VERSION 5.8 ;
BUSBITCHARS "[]" ;
DIVIDERCHAR "/" ;
UNITS
    DATABASE MICRONS 1000 ;
END UNITS

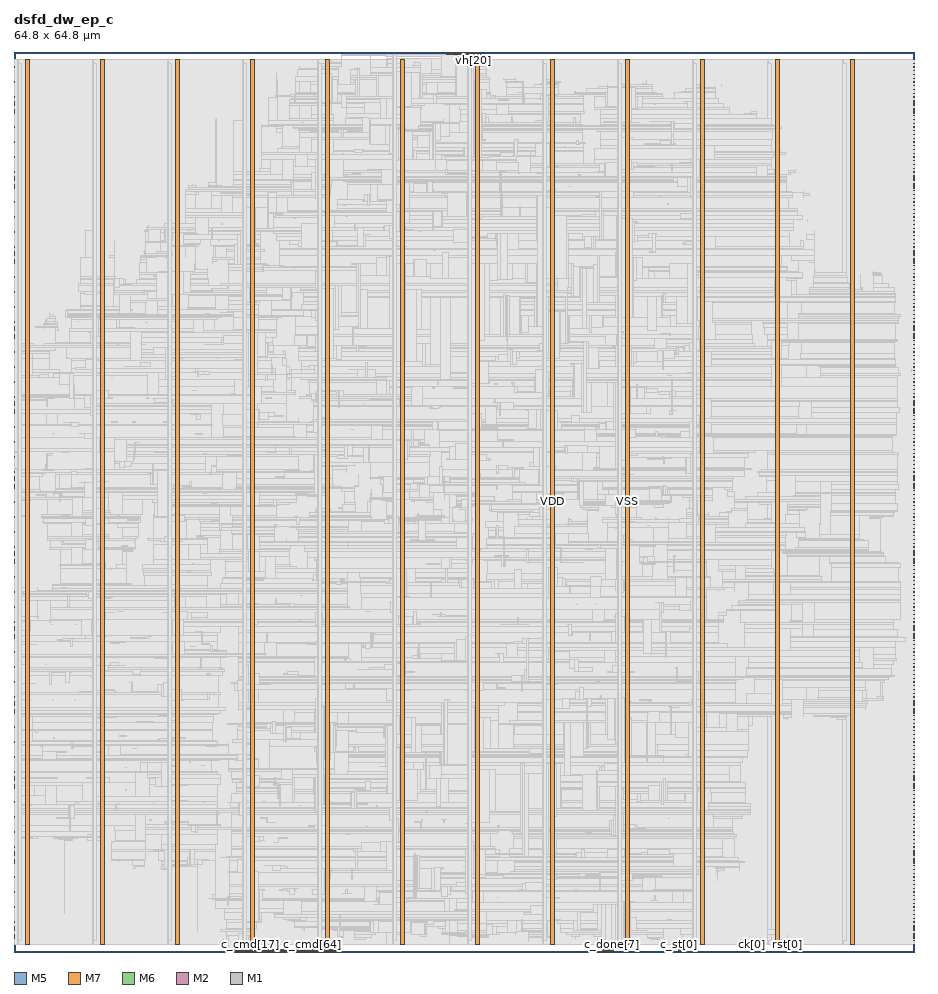
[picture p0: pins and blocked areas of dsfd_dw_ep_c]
MACRO dsfd_dw_ep_c
  FOREIGN dsfd_dw_ep_c 0 0 ;
  CLASS BLOCK ;
  SIZE 64.8 BY 64.8 ;
  PIN c_cmd[0]
    DIRECTION INPUT ;
    USE SIGNAL ;
    PORT
      LAYER M5 ;
        RECT  15.36 0 15.384 0.192 ;
    END
  END c_cmd[0]
  PIN c_cmd[10]
    DIRECTION INPUT ;
    USE SIGNAL ;
    PORT
      LAYER M5 ;
        RECT  16.32 0 16.344 0.192 ;
    END
  END c_cmd[10]
  PIN c_cmd[11]
    DIRECTION INPUT ;
    USE SIGNAL ;
    PORT
      LAYER M5 ;
        RECT  16.416 0 16.44 0.192 ;
    END
  END c_cmd[11]
  PIN c_cmd[12]
    DIRECTION INPUT ;
    USE SIGNAL ;
    PORT
      LAYER M5 ;
        RECT  16.512 0 16.536 0.192 ;
    END
  END c_cmd[12]
  PIN c_cmd[13]
    DIRECTION INPUT ;
    USE SIGNAL ;
    PORT
      LAYER M5 ;
        RECT  16.608 0 16.632 0.192 ;
    END
  END c_cmd[13]
  PIN c_cmd[14]
    DIRECTION INPUT ;
    USE SIGNAL ;
    PORT
      LAYER M5 ;
        RECT  16.704 0 16.728 0.192 ;
    END
  END c_cmd[14]
  PIN c_cmd[15]
    DIRECTION INPUT ;
    USE SIGNAL ;
    PORT
      LAYER M5 ;
        RECT  16.8 0 16.824 0.192 ;
    END
  END c_cmd[15]
  PIN c_cmd[16]
    DIRECTION INPUT ;
    USE SIGNAL ;
    PORT
      LAYER M5 ;
        RECT  16.896 0 16.92 0.192 ;
    END
  END c_cmd[16]
  PIN c_cmd[17]
    DIRECTION INPUT ;
    USE SIGNAL ;
    PORT
      LAYER M5 ;
        RECT  16.992 0 17.016 0.192 ;
    END
  END c_cmd[17]
  PIN c_cmd[18]
    DIRECTION INPUT ;
    USE SIGNAL ;
    PORT
      LAYER M5 ;
        RECT  17.088 0 17.112 0.192 ;
    END
  END c_cmd[18]
  PIN c_cmd[19]
    DIRECTION INPUT ;
    USE SIGNAL ;
    PORT
      LAYER M5 ;
        RECT  17.184 0 17.208 0.192 ;
    END
  END c_cmd[19]
  PIN c_cmd[1]
    DIRECTION INPUT ;
    USE SIGNAL ;
    PORT
      LAYER M5 ;
        RECT  15.456 0 15.48 0.192 ;
    END
  END c_cmd[1]
  PIN c_cmd[20]
    DIRECTION INPUT ;
    USE SIGNAL ;
    PORT
      LAYER M5 ;
        RECT  17.28 0 17.304 0.192 ;
    END
  END c_cmd[20]
  PIN c_cmd[21]
    DIRECTION INPUT ;
    USE SIGNAL ;
    PORT
      LAYER M5 ;
        RECT  17.376 0 17.4 0.192 ;
    END
  END c_cmd[21]
  PIN c_cmd[22]
    DIRECTION INPUT ;
    USE SIGNAL ;
    PORT
      LAYER M5 ;
        RECT  17.472 0 17.496 0.192 ;
    END
  END c_cmd[22]
  PIN c_cmd[23]
    DIRECTION INPUT ;
    USE SIGNAL ;
    PORT
      LAYER M5 ;
        RECT  17.568 0 17.592 0.192 ;
    END
  END c_cmd[23]
  PIN c_cmd[24]
    DIRECTION INPUT ;
    USE SIGNAL ;
    PORT
      LAYER M5 ;
        RECT  17.664 0 17.688 0.192 ;
    END
  END c_cmd[24]
  PIN c_cmd[25]
    DIRECTION INPUT ;
    USE SIGNAL ;
    PORT
      LAYER M5 ;
        RECT  17.76 0 17.784 0.192 ;
    END
  END c_cmd[25]
  PIN c_cmd[26]
    DIRECTION INPUT ;
    USE SIGNAL ;
    PORT
      LAYER M5 ;
        RECT  17.856 0 17.88 0.192 ;
    END
  END c_cmd[26]
  PIN c_cmd[27]
    DIRECTION INPUT ;
    USE SIGNAL ;
    PORT
      LAYER M5 ;
        RECT  17.952 0 17.976 0.192 ;
    END
  END c_cmd[27]
  PIN c_cmd[28]
    DIRECTION INPUT ;
    USE SIGNAL ;
    PORT
      LAYER M5 ;
        RECT  18.048 0 18.072 0.192 ;
    END
  END c_cmd[28]
  PIN c_cmd[29]
    DIRECTION INPUT ;
    USE SIGNAL ;
    PORT
      LAYER M5 ;
        RECT  18.144 0 18.168 0.192 ;
    END
  END c_cmd[29]
  PIN c_cmd[2]
    DIRECTION INPUT ;
    USE SIGNAL ;
    PORT
      LAYER M5 ;
        RECT  15.552 0 15.576 0.192 ;
    END
  END c_cmd[2]
  PIN c_cmd[30]
    DIRECTION INPUT ;
    USE SIGNAL ;
    PORT
      LAYER M5 ;
        RECT  18.24 0 18.264 0.192 ;
    END
  END c_cmd[30]
  PIN c_cmd[31]
    DIRECTION INPUT ;
    USE SIGNAL ;
    PORT
      LAYER M5 ;
        RECT  18.336 0 18.36 0.192 ;
    END
  END c_cmd[31]
  PIN c_cmd[32]
    DIRECTION INPUT ;
    USE SIGNAL ;
    PORT
      LAYER M5 ;
        RECT  18.432 0 18.456 0.192 ;
    END
  END c_cmd[32]
  PIN c_cmd[33]
    DIRECTION INPUT ;
    USE SIGNAL ;
    PORT
      LAYER M5 ;
        RECT  18.528 0 18.552 0.192 ;
    END
  END c_cmd[33]
  PIN c_cmd[34]
    DIRECTION INPUT ;
    USE SIGNAL ;
    PORT
      LAYER M5 ;
        RECT  18.624 0 18.648 0.192 ;
    END
  END c_cmd[34]
  PIN c_cmd[35]
    DIRECTION INPUT ;
    USE SIGNAL ;
    PORT
      LAYER M5 ;
        RECT  18.72 0 18.744 0.192 ;
    END
  END c_cmd[35]
  PIN c_cmd[36]
    DIRECTION INPUT ;
    USE SIGNAL ;
    PORT
      LAYER M5 ;
        RECT  18.816 0 18.84 0.192 ;
    END
  END c_cmd[36]
  PIN c_cmd[37]
    DIRECTION INPUT ;
    USE SIGNAL ;
    PORT
      LAYER M5 ;
        RECT  18.912 0 18.936 0.192 ;
    END
  END c_cmd[37]
  PIN c_cmd[38]
    DIRECTION INPUT ;
    USE SIGNAL ;
    PORT
      LAYER M5 ;
        RECT  19.008 0 19.032 0.192 ;
    END
  END c_cmd[38]
  PIN c_cmd[39]
    DIRECTION INPUT ;
    USE SIGNAL ;
    PORT
      LAYER M5 ;
        RECT  19.104 0 19.128 0.192 ;
    END
  END c_cmd[39]
  PIN c_cmd[3]
    DIRECTION INPUT ;
    USE SIGNAL ;
    PORT
      LAYER M5 ;
        RECT  15.648 0 15.672 0.192 ;
    END
  END c_cmd[3]
  PIN c_cmd[40]
    DIRECTION INPUT ;
    USE SIGNAL ;
    PORT
      LAYER M5 ;
        RECT  19.2 0 19.224 0.192 ;
    END
  END c_cmd[40]
  PIN c_cmd[41]
    DIRECTION INPUT ;
    USE SIGNAL ;
    PORT
      LAYER M5 ;
        RECT  19.296 0 19.32 0.192 ;
    END
  END c_cmd[41]
  PIN c_cmd[42]
    DIRECTION INPUT ;
    USE SIGNAL ;
    PORT
      LAYER M5 ;
        RECT  19.392 0 19.416 0.192 ;
    END
  END c_cmd[42]
  PIN c_cmd[43]
    DIRECTION INPUT ;
    USE SIGNAL ;
    PORT
      LAYER M5 ;
        RECT  19.488 0 19.512 0.192 ;
    END
  END c_cmd[43]
  PIN c_cmd[44]
    DIRECTION INPUT ;
    USE SIGNAL ;
    PORT
      LAYER M5 ;
        RECT  19.584 0 19.608 0.192 ;
    END
  END c_cmd[44]
  PIN c_cmd[45]
    DIRECTION INPUT ;
    USE SIGNAL ;
    PORT
      LAYER M5 ;
        RECT  19.68 0 19.704 0.192 ;
    END
  END c_cmd[45]
  PIN c_cmd[46]
    DIRECTION INPUT ;
    USE SIGNAL ;
    PORT
      LAYER M5 ;
        RECT  19.776 0 19.8 0.192 ;
    END
  END c_cmd[46]
  PIN c_cmd[47]
    DIRECTION INPUT ;
    USE SIGNAL ;
    PORT
      LAYER M5 ;
        RECT  19.872 0 19.896 0.192 ;
    END
  END c_cmd[47]
  PIN c_cmd[48]
    DIRECTION INPUT ;
    USE SIGNAL ;
    PORT
      LAYER M5 ;
        RECT  19.968 0 19.992 0.192 ;
    END
  END c_cmd[48]
  PIN c_cmd[49]
    DIRECTION INPUT ;
    USE SIGNAL ;
    PORT
      LAYER M5 ;
        RECT  20.064 0 20.088 0.192 ;
    END
  END c_cmd[49]
  PIN c_cmd[4]
    DIRECTION INPUT ;
    USE SIGNAL ;
    PORT
      LAYER M5 ;
        RECT  15.744 0 15.768 0.192 ;
    END
  END c_cmd[4]
  PIN c_cmd[50]
    DIRECTION INPUT ;
    USE SIGNAL ;
    PORT
      LAYER M5 ;
        RECT  20.16 0 20.184 0.192 ;
    END
  END c_cmd[50]
  PIN c_cmd[51]
    DIRECTION INPUT ;
    USE SIGNAL ;
    PORT
      LAYER M5 ;
        RECT  20.256 0 20.28 0.192 ;
    END
  END c_cmd[51]
  PIN c_cmd[52]
    DIRECTION INPUT ;
    USE SIGNAL ;
    PORT
      LAYER M5 ;
        RECT  20.352 0 20.376 0.192 ;
    END
  END c_cmd[52]
  PIN c_cmd[53]
    DIRECTION INPUT ;
    USE SIGNAL ;
    PORT
      LAYER M5 ;
        RECT  20.448 0 20.472 0.192 ;
    END
  END c_cmd[53]
  PIN c_cmd[54]
    DIRECTION INPUT ;
    USE SIGNAL ;
    PORT
      LAYER M5 ;
        RECT  20.544 0 20.568 0.192 ;
    END
  END c_cmd[54]
  PIN c_cmd[55]
    DIRECTION INPUT ;
    USE SIGNAL ;
    PORT
      LAYER M5 ;
        RECT  20.64 0 20.664 0.192 ;
    END
  END c_cmd[55]
  PIN c_cmd[56]
    DIRECTION INPUT ;
    USE SIGNAL ;
    PORT
      LAYER M5 ;
        RECT  20.736 0 20.76 0.192 ;
    END
  END c_cmd[56]
  PIN c_cmd[57]
    DIRECTION INPUT ;
    USE SIGNAL ;
    PORT
      LAYER M5 ;
        RECT  20.832 0 20.856 0.192 ;
    END
  END c_cmd[57]
  PIN c_cmd[58]
    DIRECTION INPUT ;
    USE SIGNAL ;
    PORT
      LAYER M5 ;
        RECT  20.928 0 20.952 0.192 ;
    END
  END c_cmd[58]
  PIN c_cmd[59]
    DIRECTION INPUT ;
    USE SIGNAL ;
    PORT
      LAYER M5 ;
        RECT  21.024 0 21.048 0.192 ;
    END
  END c_cmd[59]
  PIN c_cmd[5]
    DIRECTION INPUT ;
    USE SIGNAL ;
    PORT
      LAYER M5 ;
        RECT  15.84 0 15.864 0.192 ;
    END
  END c_cmd[5]
  PIN c_cmd[60]
    DIRECTION INPUT ;
    USE SIGNAL ;
    PORT
      LAYER M5 ;
        RECT  21.12 0 21.144 0.192 ;
    END
  END c_cmd[60]
  PIN c_cmd[61]
    DIRECTION INPUT ;
    USE SIGNAL ;
    PORT
      LAYER M5 ;
        RECT  21.216 0 21.24 0.192 ;
    END
  END c_cmd[61]
  PIN c_cmd[62]
    DIRECTION INPUT ;
    USE SIGNAL ;
    PORT
      LAYER M5 ;
        RECT  21.312 0 21.336 0.192 ;
    END
  END c_cmd[62]
  PIN c_cmd[63]
    DIRECTION INPUT ;
    USE SIGNAL ;
    PORT
      LAYER M5 ;
        RECT  21.408 0 21.432 0.192 ;
    END
  END c_cmd[63]
  PIN c_cmd[64]
    DIRECTION INPUT ;
    USE SIGNAL ;
    PORT
      LAYER M5 ;
        RECT  21.504 0 21.528 0.192 ;
    END
  END c_cmd[64]
  PIN c_cmd[65]
    DIRECTION INPUT ;
    USE SIGNAL ;
    PORT
      LAYER M5 ;
        RECT  21.6 0 21.624 0.192 ;
    END
  END c_cmd[65]
  PIN c_cmd[66]
    DIRECTION INPUT ;
    USE SIGNAL ;
    PORT
      LAYER M5 ;
        RECT  21.696 0 21.72 0.192 ;
    END
  END c_cmd[66]
  PIN c_cmd[67]
    DIRECTION INPUT ;
    USE SIGNAL ;
    PORT
      LAYER M5 ;
        RECT  21.792 0 21.816 0.192 ;
    END
  END c_cmd[67]
  PIN c_cmd[68]
    DIRECTION INPUT ;
    USE SIGNAL ;
    PORT
      LAYER M5 ;
        RECT  21.888 0 21.912 0.192 ;
    END
  END c_cmd[68]
  PIN c_cmd[69]
    DIRECTION INPUT ;
    USE SIGNAL ;
    PORT
      LAYER M5 ;
        RECT  21.984 0 22.008 0.192 ;
    END
  END c_cmd[69]
  PIN c_cmd[6]
    DIRECTION INPUT ;
    USE SIGNAL ;
    PORT
      LAYER M5 ;
        RECT  15.936 0 15.96 0.192 ;
    END
  END c_cmd[6]
  PIN c_cmd[70]
    DIRECTION INPUT ;
    USE SIGNAL ;
    PORT
      LAYER M5 ;
        RECT  22.08 0 22.104 0.192 ;
    END
  END c_cmd[70]
  PIN c_cmd[71]
    DIRECTION INPUT ;
    USE SIGNAL ;
    PORT
      LAYER M5 ;
        RECT  22.176 0 22.2 0.192 ;
    END
  END c_cmd[71]
  PIN c_cmd[72]
    DIRECTION INPUT ;
    USE SIGNAL ;
    PORT
      LAYER M5 ;
        RECT  22.272 0 22.296 0.192 ;
    END
  END c_cmd[72]
  PIN c_cmd[73]
    DIRECTION INPUT ;
    USE SIGNAL ;
    PORT
      LAYER M5 ;
        RECT  22.368 0 22.392 0.192 ;
    END
  END c_cmd[73]
  PIN c_cmd[74]
    DIRECTION INPUT ;
    USE SIGNAL ;
    PORT
      LAYER M5 ;
        RECT  22.464 0 22.488 0.192 ;
    END
  END c_cmd[74]
  PIN c_cmd[75]
    DIRECTION INPUT ;
    USE SIGNAL ;
    PORT
      LAYER M5 ;
        RECT  22.56 0 22.584 0.192 ;
    END
  END c_cmd[75]
  PIN c_cmd[76]
    DIRECTION INPUT ;
    USE SIGNAL ;
    PORT
      LAYER M5 ;
        RECT  22.656 0 22.68 0.192 ;
    END
  END c_cmd[76]
  PIN c_cmd[77]
    DIRECTION INPUT ;
    USE SIGNAL ;
    PORT
      LAYER M5 ;
        RECT  22.752 0 22.776 0.192 ;
    END
  END c_cmd[77]
  PIN c_cmd[78]
    DIRECTION INPUT ;
    USE SIGNAL ;
    PORT
      LAYER M5 ;
        RECT  22.848 0 22.872 0.192 ;
    END
  END c_cmd[78]
  PIN c_cmd[79]
    DIRECTION INPUT ;
    USE SIGNAL ;
    PORT
      LAYER M5 ;
        RECT  22.944 0 22.968 0.192 ;
    END
  END c_cmd[79]
  PIN c_cmd[7]
    DIRECTION INPUT ;
    USE SIGNAL ;
    PORT
      LAYER M5 ;
        RECT  16.032 0 16.056 0.192 ;
    END
  END c_cmd[7]
  PIN c_cmd[80]
    DIRECTION INPUT ;
    USE SIGNAL ;
    PORT
      LAYER M5 ;
        RECT  23.04 0 23.064 0.192 ;
    END
  END c_cmd[80]
  PIN c_cmd[81]
    DIRECTION INPUT ;
    USE SIGNAL ;
    PORT
      LAYER M5 ;
        RECT  23.136 0 23.16 0.192 ;
    END
  END c_cmd[81]
  PIN c_cmd[82]
    DIRECTION INPUT ;
    USE SIGNAL ;
    PORT
      LAYER M5 ;
        RECT  23.232 0 23.256 0.192 ;
    END
  END c_cmd[82]
  PIN c_cmd[83]
    DIRECTION INPUT ;
    USE SIGNAL ;
    PORT
      LAYER M5 ;
        RECT  23.328 0 23.352 0.192 ;
    END
  END c_cmd[83]
  PIN c_cmd[84]
    DIRECTION INPUT ;
    USE SIGNAL ;
    PORT
      LAYER M5 ;
        RECT  23.424 0 23.448 0.192 ;
    END
  END c_cmd[84]
  PIN c_cmd[8]
    DIRECTION INPUT ;
    USE SIGNAL ;
    PORT
      LAYER M5 ;
        RECT  16.128 0 16.152 0.192 ;
    END
  END c_cmd[8]
  PIN c_cmd[9]
    DIRECTION INPUT ;
    USE SIGNAL ;
    PORT
      LAYER M5 ;
        RECT  16.224 0 16.248 0.192 ;
    END
  END c_cmd[9]
  PIN c_done[0]
    DIRECTION OUTPUT ;
    USE SIGNAL ;
    PORT
      LAYER M5 ;
        RECT  42.336 0 42.36 0.192 ;
    END
  END c_done[0]
  PIN c_done[1]
    DIRECTION OUTPUT ;
    USE SIGNAL ;
    PORT
      LAYER M5 ;
        RECT  42.432 0 42.456 0.192 ;
    END
  END c_done[1]
  PIN c_done[2]
    DIRECTION OUTPUT ;
    USE SIGNAL ;
    PORT
      LAYER M5 ;
        RECT  42.528 0 42.552 0.192 ;
    END
  END c_done[2]
  PIN c_done[3]
    DIRECTION OUTPUT ;
    USE SIGNAL ;
    PORT
      LAYER M5 ;
        RECT  42.624 0 42.648 0.192 ;
    END
  END c_done[3]
  PIN c_done[4]
    DIRECTION OUTPUT ;
    USE SIGNAL ;
    PORT
      LAYER M5 ;
        RECT  42.72 0 42.744 0.192 ;
    END
  END c_done[4]
  PIN c_done[5]
    DIRECTION OUTPUT ;
    USE SIGNAL ;
    PORT
      LAYER M5 ;
        RECT  42.816 0 42.84 0.192 ;
    END
  END c_done[5]
  PIN c_done[6]
    DIRECTION OUTPUT ;
    USE SIGNAL ;
    PORT
      LAYER M5 ;
        RECT  42.912 0 42.936 0.192 ;
    END
  END c_done[6]
  PIN c_done[7]
    DIRECTION OUTPUT ;
    USE SIGNAL ;
    PORT
      LAYER M5 ;
        RECT  43.008 0 43.032 0.192 ;
    END
  END c_done[7]
  PIN c_done[8]
    DIRECTION OUTPUT ;
    USE SIGNAL ;
    PORT
      LAYER M5 ;
        RECT  43.104 0 43.128 0.192 ;
    END
  END c_done[8]
  PIN c_st[0]
    DIRECTION OUTPUT ;
    USE SIGNAL ;
    PORT
      LAYER M5 ;
        RECT  47.856 0 47.88 0.192 ;
    END
  END c_st[0]
  PIN c_st[1]
    DIRECTION OUTPUT ;
    USE SIGNAL ;
    PORT
      LAYER M5 ;
        RECT  47.952 0 47.976 0.192 ;
    END
  END c_st[1]
  PIN ck[0]
    DIRECTION INPUT ;
    USE SIGNAL ;
    PORT
      LAYER M5 ;
        RECT  53.088 0 53.112 0.192 ;
    END
  END ck[0]
  PIN rst[0]
    DIRECTION INPUT ;
    USE SIGNAL ;
    PORT
      LAYER M5 ;
        RECT  55.68 0 55.704 0.192 ;
    END
  END rst[0]
  PIN vh[0]
    DIRECTION INPUT ;
    USE SIGNAL ;
    PORT
      LAYER M5 ;
        RECT  31.152 64.608 31.176 64.8 ;
    END
  END vh[0]
  PIN vh[10]
    DIRECTION INPUT ;
    USE SIGNAL ;
    PORT
      LAYER M5 ;
        RECT  32.112 64.608 32.136 64.8 ;
    END
  END vh[10]
  PIN vh[11]
    DIRECTION INPUT ;
    USE SIGNAL ;
    PORT
      LAYER M5 ;
        RECT  32.208 64.608 32.232 64.8 ;
    END
  END vh[11]
  PIN vh[12]
    DIRECTION INPUT ;
    USE SIGNAL ;
    PORT
      LAYER M5 ;
        RECT  32.304 64.608 32.328 64.8 ;
    END
  END vh[12]
  PIN vh[13]
    DIRECTION INPUT ;
    USE SIGNAL ;
    PORT
      LAYER M5 ;
        RECT  32.4 64.608 32.424 64.8 ;
    END
  END vh[13]
  PIN vh[14]
    DIRECTION INPUT ;
    USE SIGNAL ;
    PORT
      LAYER M5 ;
        RECT  32.496 64.608 32.52 64.8 ;
    END
  END vh[14]
  PIN vh[15]
    DIRECTION INPUT ;
    USE SIGNAL ;
    PORT
      LAYER M5 ;
        RECT  32.592 64.608 32.616 64.8 ;
    END
  END vh[15]
  PIN vh[16]
    DIRECTION INPUT ;
    USE SIGNAL ;
    PORT
      LAYER M5 ;
        RECT  32.688 64.608 32.712 64.8 ;
    END
  END vh[16]
  PIN vh[17]
    DIRECTION INPUT ;
    USE SIGNAL ;
    PORT
      LAYER M5 ;
        RECT  32.784 64.608 32.808 64.8 ;
    END
  END vh[17]
  PIN vh[18]
    DIRECTION INPUT ;
    USE SIGNAL ;
    PORT
      LAYER M5 ;
        RECT  32.88 64.608 32.904 64.8 ;
    END
  END vh[18]
  PIN vh[19]
    DIRECTION INPUT ;
    USE SIGNAL ;
    PORT
      LAYER M5 ;
        RECT  32.976 64.608 33 64.8 ;
    END
  END vh[19]
  PIN vh[1]
    DIRECTION INPUT ;
    USE SIGNAL ;
    PORT
      LAYER M5 ;
        RECT  31.248 64.608 31.272 64.8 ;
    END
  END vh[1]
  PIN vh[20]
    DIRECTION INPUT ;
    USE SIGNAL ;
    PORT
      LAYER M5 ;
        RECT  33.072 64.608 33.096 64.8 ;
    END
  END vh[20]
  PIN vh[21]
    DIRECTION INPUT ;
    USE SIGNAL ;
    PORT
      LAYER M5 ;
        RECT  33.168 64.608 33.192 64.8 ;
    END
  END vh[21]
  PIN vh[22]
    DIRECTION INPUT ;
    USE SIGNAL ;
    PORT
      LAYER M5 ;
        RECT  33.264 64.608 33.288 64.8 ;
    END
  END vh[22]
  PIN vh[23]
    DIRECTION INPUT ;
    USE SIGNAL ;
    PORT
      LAYER M5 ;
        RECT  33.36 64.608 33.384 64.8 ;
    END
  END vh[23]
  PIN vh[24]
    DIRECTION INPUT ;
    USE SIGNAL ;
    PORT
      LAYER M5 ;
        RECT  33.456 64.608 33.48 64.8 ;
    END
  END vh[24]
  PIN vh[25]
    DIRECTION INPUT ;
    USE SIGNAL ;
    PORT
      LAYER M5 ;
        RECT  33.552 64.608 33.576 64.8 ;
    END
  END vh[25]
  PIN vh[2]
    DIRECTION INPUT ;
    USE SIGNAL ;
    PORT
      LAYER M5 ;
        RECT  31.344 64.608 31.368 64.8 ;
    END
  END vh[2]
  PIN vh[3]
    DIRECTION INPUT ;
    USE SIGNAL ;
    PORT
      LAYER M5 ;
        RECT  31.44 64.608 31.464 64.8 ;
    END
  END vh[3]
  PIN vh[4]
    DIRECTION INPUT ;
    USE SIGNAL ;
    PORT
      LAYER M5 ;
        RECT  31.536 64.608 31.56 64.8 ;
    END
  END vh[4]
  PIN vh[5]
    DIRECTION INPUT ;
    USE SIGNAL ;
    PORT
      LAYER M5 ;
        RECT  31.632 64.608 31.656 64.8 ;
    END
  END vh[5]
  PIN vh[6]
    DIRECTION INPUT ;
    USE SIGNAL ;
    PORT
      LAYER M5 ;
        RECT  31.728 64.608 31.752 64.8 ;
    END
  END vh[6]
  PIN vh[7]
    DIRECTION INPUT ;
    USE SIGNAL ;
    PORT
      LAYER M5 ;
        RECT  31.824 64.608 31.848 64.8 ;
    END
  END vh[7]
  PIN vh[8]
    DIRECTION INPUT ;
    USE SIGNAL ;
    PORT
      LAYER M5 ;
        RECT  31.92 64.608 31.944 64.8 ;
    END
  END vh[8]
  PIN vh[9]
    DIRECTION INPUT ;
    USE SIGNAL ;
    PORT
      LAYER M5 ;
        RECT  32.016 64.608 32.04 64.8 ;
    END
  END vh[9]
  PIN VDD
    DIRECTION INOUT ;
    USE POWER ;
    PORT
      LAYER M7 ;
        RECT  60.256 0.531 60.544 64.269 ;
        RECT  49.456 0.531 49.744 64.269 ;
        RECT  38.656 0.531 38.944 64.269 ;
        RECT  27.856 0.531 28.144 64.269 ;
        RECT  17.056 0.531 17.344 64.269 ;
        RECT  6.256 0.531 6.544 64.269 ;
      LAYER M6 ;
        RECT  64.768 60.972 64.8 61.26 ;
        RECT  0 60.972 0.032 61.26 ;
        RECT  64.768 55.572 64.8 55.86 ;
        RECT  0 55.572 0.032 55.86 ;
        RECT  64.768 50.172 64.8 50.46 ;
        RECT  0 50.172 0.032 50.46 ;
        RECT  64.768 44.772 64.8 45.06 ;
        RECT  0 44.772 0.032 45.06 ;
        RECT  64.768 39.372 64.8 39.66 ;
        RECT  0 39.372 0.032 39.66 ;
        RECT  64.768 33.972 64.8 34.26 ;
        RECT  0 33.972 0.032 34.26 ;
        RECT  64.768 28.572 64.8 28.86 ;
        RECT  0 28.572 0.032 28.86 ;
        RECT  64.768 23.172 64.8 23.46 ;
        RECT  0 23.172 0.032 23.46 ;
        RECT  64.768 17.772 64.8 18.06 ;
        RECT  0 17.772 0.032 18.06 ;
        RECT  64.768 12.372 64.8 12.66 ;
        RECT  0 12.372 0.032 12.66 ;
        RECT  64.768 6.972 64.8 7.26 ;
        RECT  0 6.972 0.032 7.26 ;
        RECT  64.768 1.572 64.8 1.86 ;
        RECT  0 1.572 0.032 1.86 ;
      LAYER M2 ;
        RECT  64.782 63.981 64.8 63.999 ;
        RECT  0 63.981 0.018 63.999 ;
        RECT  64.782 63.441 64.8 63.459 ;
        RECT  0 63.441 0.018 63.459 ;
        RECT  64.782 62.901 64.8 62.919 ;
        RECT  0 62.901 0.018 62.919 ;
        RECT  64.782 62.361 64.8 62.379 ;
        RECT  0 62.361 0.018 62.379 ;
        RECT  64.782 61.821 64.8 61.839 ;
        RECT  0 61.821 0.018 61.839 ;
        RECT  64.782 61.281 64.8 61.299 ;
        RECT  0 61.281 0.018 61.299 ;
        RECT  64.782 60.741 64.8 60.759 ;
        RECT  0 60.741 0.018 60.759 ;
        RECT  64.782 60.201 64.8 60.219 ;
        RECT  0 60.201 0.018 60.219 ;
        RECT  64.782 59.661 64.8 59.679 ;
        RECT  0 59.661 0.018 59.679 ;
        RECT  64.782 59.121 64.8 59.139 ;
        RECT  0 59.121 0.018 59.139 ;
        RECT  64.782 58.581 64.8 58.599 ;
        RECT  0 58.581 0.018 58.599 ;
        RECT  64.782 58.041 64.8 58.059 ;
        RECT  0 58.041 0.018 58.059 ;
        RECT  64.782 57.501 64.8 57.519 ;
        RECT  0 57.501 0.018 57.519 ;
        RECT  64.782 56.961 64.8 56.979 ;
        RECT  0 56.961 0.018 56.979 ;
        RECT  64.782 56.421 64.8 56.439 ;
        RECT  0 56.421 0.018 56.439 ;
        RECT  64.782 55.881 64.8 55.899 ;
        RECT  0 55.881 0.018 55.899 ;
        RECT  64.782 55.341 64.8 55.359 ;
        RECT  0 55.341 0.018 55.359 ;
        RECT  64.782 54.801 64.8 54.819 ;
        RECT  0 54.801 0.018 54.819 ;
        RECT  64.782 54.261 64.8 54.279 ;
        RECT  0 54.261 0.018 54.279 ;
        RECT  64.782 53.721 64.8 53.739 ;
        RECT  0 53.721 0.018 53.739 ;
        RECT  64.782 53.181 64.8 53.199 ;
        RECT  0 53.181 0.018 53.199 ;
        RECT  64.782 52.641 64.8 52.659 ;
        RECT  0 52.641 0.018 52.659 ;
        RECT  64.782 52.101 64.8 52.119 ;
        RECT  0 52.101 0.018 52.119 ;
        RECT  64.782 51.561 64.8 51.579 ;
        RECT  0 51.561 0.018 51.579 ;
        RECT  64.782 51.021 64.8 51.039 ;
        RECT  0 51.021 0.018 51.039 ;
        RECT  64.782 50.481 64.8 50.499 ;
        RECT  0 50.481 0.018 50.499 ;
        RECT  64.782 49.941 64.8 49.959 ;
        RECT  0 49.941 0.018 49.959 ;
        RECT  64.782 49.401 64.8 49.419 ;
        RECT  0 49.401 0.018 49.419 ;
        RECT  64.782 48.861 64.8 48.879 ;
        RECT  0 48.861 0.018 48.879 ;
        RECT  64.782 48.321 64.8 48.339 ;
        RECT  0 48.321 0.018 48.339 ;
        RECT  64.782 47.781 64.8 47.799 ;
        RECT  0 47.781 0.018 47.799 ;
        RECT  64.782 47.241 64.8 47.259 ;
        RECT  0 47.241 0.018 47.259 ;
        RECT  64.782 46.701 64.8 46.719 ;
        RECT  0 46.701 0.018 46.719 ;
        RECT  64.782 46.161 64.8 46.179 ;
        RECT  0 46.161 0.018 46.179 ;
        RECT  64.782 45.621 64.8 45.639 ;
        RECT  0 45.621 0.018 45.639 ;
        RECT  64.782 45.081 64.8 45.099 ;
        RECT  0 45.081 0.018 45.099 ;
        RECT  64.782 44.541 64.8 44.559 ;
        RECT  0 44.541 0.018 44.559 ;
        RECT  64.782 44.001 64.8 44.019 ;
        RECT  0 44.001 0.018 44.019 ;
        RECT  64.782 43.461 64.8 43.479 ;
        RECT  0 43.461 0.018 43.479 ;
        RECT  64.782 42.921 64.8 42.939 ;
        RECT  0 42.921 0.018 42.939 ;
        RECT  64.782 42.381 64.8 42.399 ;
        RECT  0 42.381 0.018 42.399 ;
        RECT  64.782 41.841 64.8 41.859 ;
        RECT  0 41.841 0.018 41.859 ;
        RECT  64.782 41.301 64.8 41.319 ;
        RECT  0 41.301 0.018 41.319 ;
        RECT  64.782 40.761 64.8 40.779 ;
        RECT  0 40.761 0.018 40.779 ;
        RECT  64.782 40.221 64.8 40.239 ;
        RECT  0 40.221 0.018 40.239 ;
        RECT  64.782 39.681 64.8 39.699 ;
        RECT  0 39.681 0.018 39.699 ;
        RECT  64.782 39.141 64.8 39.159 ;
        RECT  0 39.141 0.018 39.159 ;
        RECT  64.782 38.601 64.8 38.619 ;
        RECT  0 38.601 0.018 38.619 ;
        RECT  64.782 38.061 64.8 38.079 ;
        RECT  0 38.061 0.018 38.079 ;
        RECT  64.782 37.521 64.8 37.539 ;
        RECT  0 37.521 0.018 37.539 ;
        RECT  64.782 36.981 64.8 36.999 ;
        RECT  0 36.981 0.018 36.999 ;
        RECT  64.782 36.441 64.8 36.459 ;
        RECT  0 36.441 0.018 36.459 ;
        RECT  64.782 35.901 64.8 35.919 ;
        RECT  0 35.901 0.018 35.919 ;
        RECT  64.782 35.361 64.8 35.379 ;
        RECT  0 35.361 0.018 35.379 ;
        RECT  64.782 34.821 64.8 34.839 ;
        RECT  0 34.821 0.018 34.839 ;
        RECT  64.782 34.281 64.8 34.299 ;
        RECT  0 34.281 0.018 34.299 ;
        RECT  64.782 33.741 64.8 33.759 ;
        RECT  0 33.741 0.018 33.759 ;
        RECT  64.782 33.201 64.8 33.219 ;
        RECT  0 33.201 0.018 33.219 ;
        RECT  64.782 32.661 64.8 32.679 ;
        RECT  0 32.661 0.018 32.679 ;
        RECT  64.782 32.121 64.8 32.139 ;
        RECT  0 32.121 0.018 32.139 ;
        RECT  64.782 31.581 64.8 31.599 ;
        RECT  0 31.581 0.018 31.599 ;
        RECT  64.782 31.041 64.8 31.059 ;
        RECT  0 31.041 0.018 31.059 ;
        RECT  64.782 30.501 64.8 30.519 ;
        RECT  0 30.501 0.018 30.519 ;
        RECT  64.782 29.961 64.8 29.979 ;
        RECT  0 29.961 0.018 29.979 ;
        RECT  64.782 29.421 64.8 29.439 ;
        RECT  0 29.421 0.018 29.439 ;
        RECT  64.782 28.881 64.8 28.899 ;
        RECT  0 28.881 0.018 28.899 ;
        RECT  64.782 28.341 64.8 28.359 ;
        RECT  0 28.341 0.018 28.359 ;
        RECT  64.782 27.801 64.8 27.819 ;
        RECT  0 27.801 0.018 27.819 ;
        RECT  64.782 27.261 64.8 27.279 ;
        RECT  0 27.261 0.018 27.279 ;
        RECT  64.782 26.721 64.8 26.739 ;
        RECT  0 26.721 0.018 26.739 ;
        RECT  64.782 26.181 64.8 26.199 ;
        RECT  0 26.181 0.018 26.199 ;
        RECT  64.782 25.641 64.8 25.659 ;
        RECT  0 25.641 0.018 25.659 ;
        RECT  64.782 25.101 64.8 25.119 ;
        RECT  0 25.101 0.018 25.119 ;
        RECT  64.782 24.561 64.8 24.579 ;
        RECT  0 24.561 0.018 24.579 ;
        RECT  64.782 24.021 64.8 24.039 ;
        RECT  0 24.021 0.018 24.039 ;
        RECT  64.782 23.481 64.8 23.499 ;
        RECT  0 23.481 0.018 23.499 ;
        RECT  64.782 22.941 64.8 22.959 ;
        RECT  0 22.941 0.018 22.959 ;
        RECT  64.782 22.401 64.8 22.419 ;
        RECT  0 22.401 0.018 22.419 ;
        RECT  64.782 21.861 64.8 21.879 ;
        RECT  0 21.861 0.018 21.879 ;
        RECT  64.782 21.321 64.8 21.339 ;
        RECT  0 21.321 0.018 21.339 ;
        RECT  64.782 20.781 64.8 20.799 ;
        RECT  0 20.781 0.018 20.799 ;
        RECT  64.782 20.241 64.8 20.259 ;
        RECT  0 20.241 0.018 20.259 ;
        RECT  64.782 19.701 64.8 19.719 ;
        RECT  0 19.701 0.018 19.719 ;
        RECT  64.782 19.161 64.8 19.179 ;
        RECT  0 19.161 0.018 19.179 ;
        RECT  64.782 18.621 64.8 18.639 ;
        RECT  0 18.621 0.018 18.639 ;
        RECT  64.782 18.081 64.8 18.099 ;
        RECT  0 18.081 0.018 18.099 ;
        RECT  64.782 17.541 64.8 17.559 ;
        RECT  0 17.541 0.018 17.559 ;
        RECT  64.782 17.001 64.8 17.019 ;
        RECT  0 17.001 0.018 17.019 ;
        RECT  64.782 16.461 64.8 16.479 ;
        RECT  0 16.461 0.018 16.479 ;
        RECT  64.782 15.921 64.8 15.939 ;
        RECT  0 15.921 0.018 15.939 ;
        RECT  64.782 15.381 64.8 15.399 ;
        RECT  0 15.381 0.018 15.399 ;
        RECT  64.782 14.841 64.8 14.859 ;
        RECT  0 14.841 0.018 14.859 ;
        RECT  64.782 14.301 64.8 14.319 ;
        RECT  0 14.301 0.018 14.319 ;
        RECT  64.782 13.761 64.8 13.779 ;
        RECT  0 13.761 0.018 13.779 ;
        RECT  64.782 13.221 64.8 13.239 ;
        RECT  0 13.221 0.018 13.239 ;
        RECT  64.782 12.681 64.8 12.699 ;
        RECT  0 12.681 0.018 12.699 ;
        RECT  64.782 12.141 64.8 12.159 ;
        RECT  0 12.141 0.018 12.159 ;
        RECT  64.782 11.601 64.8 11.619 ;
        RECT  0 11.601 0.018 11.619 ;
        RECT  64.782 11.061 64.8 11.079 ;
        RECT  0 11.061 0.018 11.079 ;
        RECT  64.782 10.521 64.8 10.539 ;
        RECT  0 10.521 0.018 10.539 ;
        RECT  64.782 9.981 64.8 9.999 ;
        RECT  0 9.981 0.018 9.999 ;
        RECT  64.782 9.441 64.8 9.459 ;
        RECT  0 9.441 0.018 9.459 ;
        RECT  64.782 8.901 64.8 8.919 ;
        RECT  0 8.901 0.018 8.919 ;
        RECT  64.782 8.361 64.8 8.379 ;
        RECT  0 8.361 0.018 8.379 ;
        RECT  64.782 7.821 64.8 7.839 ;
        RECT  0 7.821 0.018 7.839 ;
        RECT  64.782 7.281 64.8 7.299 ;
        RECT  0 7.281 0.018 7.299 ;
        RECT  64.782 6.741 64.8 6.759 ;
        RECT  0 6.741 0.018 6.759 ;
        RECT  64.782 6.201 64.8 6.219 ;
        RECT  0 6.201 0.018 6.219 ;
        RECT  64.782 5.661 64.8 5.679 ;
        RECT  0 5.661 0.018 5.679 ;
        RECT  64.782 5.121 64.8 5.139 ;
        RECT  0 5.121 0.018 5.139 ;
        RECT  64.782 4.581 64.8 4.599 ;
        RECT  0 4.581 0.018 4.599 ;
        RECT  64.782 4.041 64.8 4.059 ;
        RECT  0 4.041 0.018 4.059 ;
        RECT  64.782 3.501 64.8 3.519 ;
        RECT  0 3.501 0.018 3.519 ;
        RECT  64.782 2.961 64.8 2.979 ;
        RECT  0 2.961 0.018 2.979 ;
        RECT  64.782 2.421 64.8 2.439 ;
        RECT  0 2.421 0.018 2.439 ;
        RECT  64.782 1.881 64.8 1.899 ;
        RECT  0 1.881 0.018 1.899 ;
        RECT  64.782 1.341 64.8 1.359 ;
        RECT  0 1.341 0.018 1.359 ;
        RECT  64.782 0.801 64.8 0.819 ;
        RECT  0 0.801 0.018 0.819 ;
      LAYER M1 ;
        RECT  64.782 63.981 64.8 63.999 ;
        RECT  0 63.981 0.018 63.999 ;
        RECT  64.782 63.441 64.8 63.459 ;
        RECT  0 63.441 0.018 63.459 ;
        RECT  64.782 62.901 64.8 62.919 ;
        RECT  0 62.901 0.018 62.919 ;
        RECT  64.782 62.361 64.8 62.379 ;
        RECT  0 62.361 0.018 62.379 ;
        RECT  64.782 61.821 64.8 61.839 ;
        RECT  0 61.821 0.018 61.839 ;
        RECT  64.782 61.281 64.8 61.299 ;
        RECT  0 61.281 0.018 61.299 ;
        RECT  64.782 60.741 64.8 60.759 ;
        RECT  0 60.741 0.018 60.759 ;
        RECT  64.782 60.201 64.8 60.219 ;
        RECT  0 60.201 0.018 60.219 ;
        RECT  64.782 59.661 64.8 59.679 ;
        RECT  0 59.661 0.018 59.679 ;
        RECT  64.782 59.121 64.8 59.139 ;
        RECT  0 59.121 0.018 59.139 ;
        RECT  64.782 58.581 64.8 58.599 ;
        RECT  0 58.581 0.018 58.599 ;
        RECT  64.782 58.041 64.8 58.059 ;
        RECT  0 58.041 0.018 58.059 ;
        RECT  64.782 57.501 64.8 57.519 ;
        RECT  0 57.501 0.018 57.519 ;
        RECT  64.782 56.961 64.8 56.979 ;
        RECT  0 56.961 0.018 56.979 ;
        RECT  64.782 56.421 64.8 56.439 ;
        RECT  0 56.421 0.018 56.439 ;
        RECT  64.782 55.881 64.8 55.899 ;
        RECT  0 55.881 0.018 55.899 ;
        RECT  64.782 55.341 64.8 55.359 ;
        RECT  0 55.341 0.018 55.359 ;
        RECT  64.782 54.801 64.8 54.819 ;
        RECT  0 54.801 0.018 54.819 ;
        RECT  64.782 54.261 64.8 54.279 ;
        RECT  0 54.261 0.018 54.279 ;
        RECT  64.782 53.721 64.8 53.739 ;
        RECT  0 53.721 0.018 53.739 ;
        RECT  64.782 53.181 64.8 53.199 ;
        RECT  0 53.181 0.018 53.199 ;
        RECT  64.782 52.641 64.8 52.659 ;
        RECT  0 52.641 0.018 52.659 ;
        RECT  64.782 52.101 64.8 52.119 ;
        RECT  0 52.101 0.018 52.119 ;
        RECT  64.782 51.561 64.8 51.579 ;
        RECT  0 51.561 0.018 51.579 ;
        RECT  64.782 51.021 64.8 51.039 ;
        RECT  0 51.021 0.018 51.039 ;
        RECT  64.782 50.481 64.8 50.499 ;
        RECT  0 50.481 0.018 50.499 ;
        RECT  64.782 49.941 64.8 49.959 ;
        RECT  0 49.941 0.018 49.959 ;
        RECT  64.782 49.401 64.8 49.419 ;
        RECT  0 49.401 0.018 49.419 ;
        RECT  64.782 48.861 64.8 48.879 ;
        RECT  0 48.861 0.018 48.879 ;
        RECT  64.782 48.321 64.8 48.339 ;
        RECT  0 48.321 0.018 48.339 ;
        RECT  64.782 47.781 64.8 47.799 ;
        RECT  0 47.781 0.018 47.799 ;
        RECT  64.782 47.241 64.8 47.259 ;
        RECT  0 47.241 0.018 47.259 ;
        RECT  64.782 46.701 64.8 46.719 ;
        RECT  0 46.701 0.018 46.719 ;
        RECT  64.782 46.161 64.8 46.179 ;
        RECT  0 46.161 0.018 46.179 ;
        RECT  64.782 45.621 64.8 45.639 ;
        RECT  0 45.621 0.018 45.639 ;
        RECT  64.782 45.081 64.8 45.099 ;
        RECT  0 45.081 0.018 45.099 ;
        RECT  64.782 44.541 64.8 44.559 ;
        RECT  0 44.541 0.018 44.559 ;
        RECT  64.782 44.001 64.8 44.019 ;
        RECT  0 44.001 0.018 44.019 ;
        RECT  64.782 43.461 64.8 43.479 ;
        RECT  0 43.461 0.018 43.479 ;
        RECT  64.782 42.921 64.8 42.939 ;
        RECT  0 42.921 0.018 42.939 ;
        RECT  64.782 42.381 64.8 42.399 ;
        RECT  0 42.381 0.018 42.399 ;
        RECT  64.782 41.841 64.8 41.859 ;
        RECT  0 41.841 0.018 41.859 ;
        RECT  64.782 41.301 64.8 41.319 ;
        RECT  0 41.301 0.018 41.319 ;
        RECT  64.782 40.761 64.8 40.779 ;
        RECT  0 40.761 0.018 40.779 ;
        RECT  64.782 40.221 64.8 40.239 ;
        RECT  0 40.221 0.018 40.239 ;
        RECT  64.782 39.681 64.8 39.699 ;
        RECT  0 39.681 0.018 39.699 ;
        RECT  64.782 39.141 64.8 39.159 ;
        RECT  0 39.141 0.018 39.159 ;
        RECT  64.782 38.601 64.8 38.619 ;
        RECT  0 38.601 0.018 38.619 ;
        RECT  64.782 38.061 64.8 38.079 ;
        RECT  0 38.061 0.018 38.079 ;
        RECT  64.782 37.521 64.8 37.539 ;
        RECT  0 37.521 0.018 37.539 ;
        RECT  64.782 36.981 64.8 36.999 ;
        RECT  0 36.981 0.018 36.999 ;
        RECT  64.782 36.441 64.8 36.459 ;
        RECT  0 36.441 0.018 36.459 ;
        RECT  64.782 35.901 64.8 35.919 ;
        RECT  0 35.901 0.018 35.919 ;
        RECT  64.782 35.361 64.8 35.379 ;
        RECT  0 35.361 0.018 35.379 ;
        RECT  64.782 34.821 64.8 34.839 ;
        RECT  0 34.821 0.018 34.839 ;
        RECT  64.782 34.281 64.8 34.299 ;
        RECT  0 34.281 0.018 34.299 ;
        RECT  64.782 33.741 64.8 33.759 ;
        RECT  0 33.741 0.018 33.759 ;
        RECT  64.782 33.201 64.8 33.219 ;
        RECT  0 33.201 0.018 33.219 ;
        RECT  64.782 32.661 64.8 32.679 ;
        RECT  0 32.661 0.018 32.679 ;
        RECT  64.782 32.121 64.8 32.139 ;
        RECT  0 32.121 0.018 32.139 ;
        RECT  64.782 31.581 64.8 31.599 ;
        RECT  0 31.581 0.018 31.599 ;
        RECT  64.782 31.041 64.8 31.059 ;
        RECT  0 31.041 0.018 31.059 ;
        RECT  64.782 30.501 64.8 30.519 ;
        RECT  0 30.501 0.018 30.519 ;
        RECT  64.782 29.961 64.8 29.979 ;
        RECT  0 29.961 0.018 29.979 ;
        RECT  64.782 29.421 64.8 29.439 ;
        RECT  0 29.421 0.018 29.439 ;
        RECT  64.782 28.881 64.8 28.899 ;
        RECT  0 28.881 0.018 28.899 ;
        RECT  64.782 28.341 64.8 28.359 ;
        RECT  0 28.341 0.018 28.359 ;
        RECT  64.782 27.801 64.8 27.819 ;
        RECT  0 27.801 0.018 27.819 ;
        RECT  64.782 27.261 64.8 27.279 ;
        RECT  0 27.261 0.018 27.279 ;
        RECT  64.782 26.721 64.8 26.739 ;
        RECT  0 26.721 0.018 26.739 ;
        RECT  64.782 26.181 64.8 26.199 ;
        RECT  0 26.181 0.018 26.199 ;
        RECT  64.782 25.641 64.8 25.659 ;
        RECT  0 25.641 0.018 25.659 ;
        RECT  64.782 25.101 64.8 25.119 ;
        RECT  0 25.101 0.018 25.119 ;
        RECT  64.782 24.561 64.8 24.579 ;
        RECT  0 24.561 0.018 24.579 ;
        RECT  64.782 24.021 64.8 24.039 ;
        RECT  0 24.021 0.018 24.039 ;
        RECT  64.782 23.481 64.8 23.499 ;
        RECT  0 23.481 0.018 23.499 ;
        RECT  64.782 22.941 64.8 22.959 ;
        RECT  0 22.941 0.018 22.959 ;
        RECT  64.782 22.401 64.8 22.419 ;
        RECT  0 22.401 0.018 22.419 ;
        RECT  64.782 21.861 64.8 21.879 ;
        RECT  0 21.861 0.018 21.879 ;
        RECT  64.782 21.321 64.8 21.339 ;
        RECT  0 21.321 0.018 21.339 ;
        RECT  64.782 20.781 64.8 20.799 ;
        RECT  0 20.781 0.018 20.799 ;
        RECT  64.782 20.241 64.8 20.259 ;
        RECT  0 20.241 0.018 20.259 ;
        RECT  64.782 19.701 64.8 19.719 ;
        RECT  0 19.701 0.018 19.719 ;
        RECT  64.782 19.161 64.8 19.179 ;
        RECT  0 19.161 0.018 19.179 ;
        RECT  64.782 18.621 64.8 18.639 ;
        RECT  0 18.621 0.018 18.639 ;
        RECT  64.782 18.081 64.8 18.099 ;
        RECT  0 18.081 0.018 18.099 ;
        RECT  64.782 17.541 64.8 17.559 ;
        RECT  0 17.541 0.018 17.559 ;
        RECT  64.782 17.001 64.8 17.019 ;
        RECT  0 17.001 0.018 17.019 ;
        RECT  64.782 16.461 64.8 16.479 ;
        RECT  0 16.461 0.018 16.479 ;
        RECT  64.782 15.921 64.8 15.939 ;
        RECT  0 15.921 0.018 15.939 ;
        RECT  64.782 15.381 64.8 15.399 ;
        RECT  0 15.381 0.018 15.399 ;
        RECT  64.782 14.841 64.8 14.859 ;
        RECT  0 14.841 0.018 14.859 ;
        RECT  64.782 14.301 64.8 14.319 ;
        RECT  0 14.301 0.018 14.319 ;
        RECT  64.782 13.761 64.8 13.779 ;
        RECT  0 13.761 0.018 13.779 ;
        RECT  64.782 13.221 64.8 13.239 ;
        RECT  0 13.221 0.018 13.239 ;
        RECT  64.782 12.681 64.8 12.699 ;
        RECT  0 12.681 0.018 12.699 ;
        RECT  64.782 12.141 64.8 12.159 ;
        RECT  0 12.141 0.018 12.159 ;
        RECT  64.782 11.601 64.8 11.619 ;
        RECT  0 11.601 0.018 11.619 ;
        RECT  64.782 11.061 64.8 11.079 ;
        RECT  0 11.061 0.018 11.079 ;
        RECT  64.782 10.521 64.8 10.539 ;
        RECT  0 10.521 0.018 10.539 ;
        RECT  64.782 9.981 64.8 9.999 ;
        RECT  0 9.981 0.018 9.999 ;
        RECT  64.782 9.441 64.8 9.459 ;
        RECT  0 9.441 0.018 9.459 ;
        RECT  64.782 8.901 64.8 8.919 ;
        RECT  0 8.901 0.018 8.919 ;
        RECT  64.782 8.361 64.8 8.379 ;
        RECT  0 8.361 0.018 8.379 ;
        RECT  64.782 7.821 64.8 7.839 ;
        RECT  0 7.821 0.018 7.839 ;
        RECT  64.782 7.281 64.8 7.299 ;
        RECT  0 7.281 0.018 7.299 ;
        RECT  64.782 6.741 64.8 6.759 ;
        RECT  0 6.741 0.018 6.759 ;
        RECT  64.782 6.201 64.8 6.219 ;
        RECT  0 6.201 0.018 6.219 ;
        RECT  64.782 5.661 64.8 5.679 ;
        RECT  0 5.661 0.018 5.679 ;
        RECT  64.782 5.121 64.8 5.139 ;
        RECT  0 5.121 0.018 5.139 ;
        RECT  64.782 4.581 64.8 4.599 ;
        RECT  0 4.581 0.018 4.599 ;
        RECT  64.782 4.041 64.8 4.059 ;
        RECT  0 4.041 0.018 4.059 ;
        RECT  64.782 3.501 64.8 3.519 ;
        RECT  0 3.501 0.018 3.519 ;
        RECT  64.782 2.961 64.8 2.979 ;
        RECT  0 2.961 0.018 2.979 ;
        RECT  64.782 2.421 64.8 2.439 ;
        RECT  0 2.421 0.018 2.439 ;
        RECT  64.782 1.881 64.8 1.899 ;
        RECT  0 1.881 0.018 1.899 ;
        RECT  64.782 1.341 64.8 1.359 ;
        RECT  0 1.341 0.018 1.359 ;
        RECT  64.782 0.801 64.8 0.819 ;
        RECT  0 0.801 0.018 0.819 ;
    END
  END VDD
  PIN VSS
    DIRECTION INOUT ;
    USE GROUND ;
    PORT
      LAYER M7 ;
        RECT  54.856 0.531 55.144 64.269 ;
        RECT  44.056 0.531 44.344 64.269 ;
        RECT  33.256 0.531 33.544 64.269 ;
        RECT  22.456 0.531 22.744 64.269 ;
        RECT  11.656 0.531 11.944 64.269 ;
        RECT  0.856 0.531 1.144 64.269 ;
      LAYER M6 ;
        RECT  64.768 60.396 64.8 60.684 ;
        RECT  0 60.396 0.032 60.684 ;
        RECT  64.768 54.996 64.8 55.284 ;
        RECT  0 54.996 0.032 55.284 ;
        RECT  64.768 49.596 64.8 49.884 ;
        RECT  0 49.596 0.032 49.884 ;
        RECT  64.768 44.196 64.8 44.484 ;
        RECT  0 44.196 0.032 44.484 ;
        RECT  64.768 38.796 64.8 39.084 ;
        RECT  0 38.796 0.032 39.084 ;
        RECT  64.768 33.396 64.8 33.684 ;
        RECT  0 33.396 0.032 33.684 ;
        RECT  64.768 27.996 64.8 28.284 ;
        RECT  0 27.996 0.032 28.284 ;
        RECT  64.768 22.596 64.8 22.884 ;
        RECT  0 22.596 0.032 22.884 ;
        RECT  64.768 17.196 64.8 17.484 ;
        RECT  0 17.196 0.032 17.484 ;
        RECT  64.768 11.796 64.8 12.084 ;
        RECT  0 11.796 0.032 12.084 ;
        RECT  64.768 6.396 64.8 6.684 ;
        RECT  0 6.396 0.032 6.684 ;
        RECT  64.768 0.996 64.8 1.284 ;
        RECT  0 0.996 0.032 1.284 ;
      LAYER M2 ;
        RECT  64.782 64.251 64.8 64.269 ;
        RECT  0 64.251 0.018 64.269 ;
        RECT  64.782 63.711 64.8 63.729 ;
        RECT  0 63.711 0.018 63.729 ;
        RECT  64.782 63.171 64.8 63.189 ;
        RECT  0 63.171 0.018 63.189 ;
        RECT  64.782 62.631 64.8 62.649 ;
        RECT  0 62.631 0.018 62.649 ;
        RECT  64.782 62.091 64.8 62.109 ;
        RECT  0 62.091 0.018 62.109 ;
        RECT  64.782 61.551 64.8 61.569 ;
        RECT  0 61.551 0.018 61.569 ;
        RECT  64.782 61.011 64.8 61.029 ;
        RECT  0 61.011 0.018 61.029 ;
        RECT  64.782 60.471 64.8 60.489 ;
        RECT  0 60.471 0.018 60.489 ;
        RECT  64.782 59.931 64.8 59.949 ;
        RECT  0 59.931 0.018 59.949 ;
        RECT  64.782 59.391 64.8 59.409 ;
        RECT  0 59.391 0.018 59.409 ;
        RECT  64.782 58.851 64.8 58.869 ;
        RECT  0 58.851 0.018 58.869 ;
        RECT  64.782 58.311 64.8 58.329 ;
        RECT  0 58.311 0.018 58.329 ;
        RECT  64.782 57.771 64.8 57.789 ;
        RECT  0 57.771 0.018 57.789 ;
        RECT  64.782 57.231 64.8 57.249 ;
        RECT  0 57.231 0.018 57.249 ;
        RECT  64.782 56.691 64.8 56.709 ;
        RECT  0 56.691 0.018 56.709 ;
        RECT  64.782 56.151 64.8 56.169 ;
        RECT  0 56.151 0.018 56.169 ;
        RECT  64.782 55.611 64.8 55.629 ;
        RECT  0 55.611 0.018 55.629 ;
        RECT  64.782 55.071 64.8 55.089 ;
        RECT  0 55.071 0.018 55.089 ;
        RECT  64.782 54.531 64.8 54.549 ;
        RECT  0 54.531 0.018 54.549 ;
        RECT  64.782 53.991 64.8 54.009 ;
        RECT  0 53.991 0.018 54.009 ;
        RECT  64.782 53.451 64.8 53.469 ;
        RECT  0 53.451 0.018 53.469 ;
        RECT  64.782 52.911 64.8 52.929 ;
        RECT  0 52.911 0.018 52.929 ;
        RECT  64.782 52.371 64.8 52.389 ;
        RECT  0 52.371 0.018 52.389 ;
        RECT  64.782 51.831 64.8 51.849 ;
        RECT  0 51.831 0.018 51.849 ;
        RECT  64.782 51.291 64.8 51.309 ;
        RECT  0 51.291 0.018 51.309 ;
        RECT  64.782 50.751 64.8 50.769 ;
        RECT  0 50.751 0.018 50.769 ;
        RECT  64.782 50.211 64.8 50.229 ;
        RECT  0 50.211 0.018 50.229 ;
        RECT  64.782 49.671 64.8 49.689 ;
        RECT  0 49.671 0.018 49.689 ;
        RECT  64.782 49.131 64.8 49.149 ;
        RECT  0 49.131 0.018 49.149 ;
        RECT  64.782 48.591 64.8 48.609 ;
        RECT  0 48.591 0.018 48.609 ;
        RECT  64.782 48.051 64.8 48.069 ;
        RECT  0 48.051 0.018 48.069 ;
        RECT  64.782 47.511 64.8 47.529 ;
        RECT  0 47.511 0.018 47.529 ;
        RECT  64.782 46.971 64.8 46.989 ;
        RECT  0 46.971 0.018 46.989 ;
        RECT  64.782 46.431 64.8 46.449 ;
        RECT  0 46.431 0.018 46.449 ;
        RECT  64.782 45.891 64.8 45.909 ;
        RECT  0 45.891 0.018 45.909 ;
        RECT  64.782 45.351 64.8 45.369 ;
        RECT  0 45.351 0.018 45.369 ;
        RECT  64.782 44.811 64.8 44.829 ;
        RECT  0 44.811 0.018 44.829 ;
        RECT  64.782 44.271 64.8 44.289 ;
        RECT  0 44.271 0.018 44.289 ;
        RECT  64.782 43.731 64.8 43.749 ;
        RECT  0 43.731 0.018 43.749 ;
        RECT  64.782 43.191 64.8 43.209 ;
        RECT  0 43.191 0.018 43.209 ;
        RECT  64.782 42.651 64.8 42.669 ;
        RECT  0 42.651 0.018 42.669 ;
        RECT  64.782 42.111 64.8 42.129 ;
        RECT  0 42.111 0.018 42.129 ;
        RECT  64.782 41.571 64.8 41.589 ;
        RECT  0 41.571 0.018 41.589 ;
        RECT  64.782 41.031 64.8 41.049 ;
        RECT  0 41.031 0.018 41.049 ;
        RECT  64.782 40.491 64.8 40.509 ;
        RECT  0 40.491 0.018 40.509 ;
        RECT  64.782 39.951 64.8 39.969 ;
        RECT  0 39.951 0.018 39.969 ;
        RECT  64.782 39.411 64.8 39.429 ;
        RECT  0 39.411 0.018 39.429 ;
        RECT  64.782 38.871 64.8 38.889 ;
        RECT  0 38.871 0.018 38.889 ;
        RECT  64.782 38.331 64.8 38.349 ;
        RECT  0 38.331 0.018 38.349 ;
        RECT  64.782 37.791 64.8 37.809 ;
        RECT  0 37.791 0.018 37.809 ;
        RECT  64.782 37.251 64.8 37.269 ;
        RECT  0 37.251 0.018 37.269 ;
        RECT  64.782 36.711 64.8 36.729 ;
        RECT  0 36.711 0.018 36.729 ;
        RECT  64.782 36.171 64.8 36.189 ;
        RECT  0 36.171 0.018 36.189 ;
        RECT  64.782 35.631 64.8 35.649 ;
        RECT  0 35.631 0.018 35.649 ;
        RECT  64.782 35.091 64.8 35.109 ;
        RECT  0 35.091 0.018 35.109 ;
        RECT  64.782 34.551 64.8 34.569 ;
        RECT  0 34.551 0.018 34.569 ;
        RECT  64.782 34.011 64.8 34.029 ;
        RECT  0 34.011 0.018 34.029 ;
        RECT  64.782 33.471 64.8 33.489 ;
        RECT  0 33.471 0.018 33.489 ;
        RECT  64.782 32.931 64.8 32.949 ;
        RECT  0 32.931 0.018 32.949 ;
        RECT  64.782 32.391 64.8 32.409 ;
        RECT  0 32.391 0.018 32.409 ;
        RECT  64.782 31.851 64.8 31.869 ;
        RECT  0 31.851 0.018 31.869 ;
        RECT  64.782 31.311 64.8 31.329 ;
        RECT  0 31.311 0.018 31.329 ;
        RECT  64.782 30.771 64.8 30.789 ;
        RECT  0 30.771 0.018 30.789 ;
        RECT  64.782 30.231 64.8 30.249 ;
        RECT  0 30.231 0.018 30.249 ;
        RECT  64.782 29.691 64.8 29.709 ;
        RECT  0 29.691 0.018 29.709 ;
        RECT  64.782 29.151 64.8 29.169 ;
        RECT  0 29.151 0.018 29.169 ;
        RECT  64.782 28.611 64.8 28.629 ;
        RECT  0 28.611 0.018 28.629 ;
        RECT  64.782 28.071 64.8 28.089 ;
        RECT  0 28.071 0.018 28.089 ;
        RECT  64.782 27.531 64.8 27.549 ;
        RECT  0 27.531 0.018 27.549 ;
        RECT  64.782 26.991 64.8 27.009 ;
        RECT  0 26.991 0.018 27.009 ;
        RECT  64.782 26.451 64.8 26.469 ;
        RECT  0 26.451 0.018 26.469 ;
        RECT  64.782 25.911 64.8 25.929 ;
        RECT  0 25.911 0.018 25.929 ;
        RECT  64.782 25.371 64.8 25.389 ;
        RECT  0 25.371 0.018 25.389 ;
        RECT  64.782 24.831 64.8 24.849 ;
        RECT  0 24.831 0.018 24.849 ;
        RECT  64.782 24.291 64.8 24.309 ;
        RECT  0 24.291 0.018 24.309 ;
        RECT  64.782 23.751 64.8 23.769 ;
        RECT  0 23.751 0.018 23.769 ;
        RECT  64.782 23.211 64.8 23.229 ;
        RECT  0 23.211 0.018 23.229 ;
        RECT  64.782 22.671 64.8 22.689 ;
        RECT  0 22.671 0.018 22.689 ;
        RECT  64.782 22.131 64.8 22.149 ;
        RECT  0 22.131 0.018 22.149 ;
        RECT  64.782 21.591 64.8 21.609 ;
        RECT  0 21.591 0.018 21.609 ;
        RECT  64.782 21.051 64.8 21.069 ;
        RECT  0 21.051 0.018 21.069 ;
        RECT  64.782 20.511 64.8 20.529 ;
        RECT  0 20.511 0.018 20.529 ;
        RECT  64.782 19.971 64.8 19.989 ;
        RECT  0 19.971 0.018 19.989 ;
        RECT  64.782 19.431 64.8 19.449 ;
        RECT  0 19.431 0.018 19.449 ;
        RECT  64.782 18.891 64.8 18.909 ;
        RECT  0 18.891 0.018 18.909 ;
        RECT  64.782 18.351 64.8 18.369 ;
        RECT  0 18.351 0.018 18.369 ;
        RECT  64.782 17.811 64.8 17.829 ;
        RECT  0 17.811 0.018 17.829 ;
        RECT  64.782 17.271 64.8 17.289 ;
        RECT  0 17.271 0.018 17.289 ;
        RECT  64.782 16.731 64.8 16.749 ;
        RECT  0 16.731 0.018 16.749 ;
        RECT  64.782 16.191 64.8 16.209 ;
        RECT  0 16.191 0.018 16.209 ;
        RECT  64.782 15.651 64.8 15.669 ;
        RECT  0 15.651 0.018 15.669 ;
        RECT  64.782 15.111 64.8 15.129 ;
        RECT  0 15.111 0.018 15.129 ;
        RECT  64.782 14.571 64.8 14.589 ;
        RECT  0 14.571 0.018 14.589 ;
        RECT  64.782 14.031 64.8 14.049 ;
        RECT  0 14.031 0.018 14.049 ;
        RECT  64.782 13.491 64.8 13.509 ;
        RECT  0 13.491 0.018 13.509 ;
        RECT  64.782 12.951 64.8 12.969 ;
        RECT  0 12.951 0.018 12.969 ;
        RECT  64.782 12.411 64.8 12.429 ;
        RECT  0 12.411 0.018 12.429 ;
        RECT  64.782 11.871 64.8 11.889 ;
        RECT  0 11.871 0.018 11.889 ;
        RECT  64.782 11.331 64.8 11.349 ;
        RECT  0 11.331 0.018 11.349 ;
        RECT  64.782 10.791 64.8 10.809 ;
        RECT  0 10.791 0.018 10.809 ;
        RECT  64.782 10.251 64.8 10.269 ;
        RECT  0 10.251 0.018 10.269 ;
        RECT  64.782 9.711 64.8 9.729 ;
        RECT  0 9.711 0.018 9.729 ;
        RECT  64.782 9.171 64.8 9.189 ;
        RECT  0 9.171 0.018 9.189 ;
        RECT  64.782 8.631 64.8 8.649 ;
        RECT  0 8.631 0.018 8.649 ;
        RECT  64.782 8.091 64.8 8.109 ;
        RECT  0 8.091 0.018 8.109 ;
        RECT  64.782 7.551 64.8 7.569 ;
        RECT  0 7.551 0.018 7.569 ;
        RECT  64.782 7.011 64.8 7.029 ;
        RECT  0 7.011 0.018 7.029 ;
        RECT  64.782 6.471 64.8 6.489 ;
        RECT  0 6.471 0.018 6.489 ;
        RECT  64.782 5.931 64.8 5.949 ;
        RECT  0 5.931 0.018 5.949 ;
        RECT  64.782 5.391 64.8 5.409 ;
        RECT  0 5.391 0.018 5.409 ;
        RECT  64.782 4.851 64.8 4.869 ;
        RECT  0 4.851 0.018 4.869 ;
        RECT  64.782 4.311 64.8 4.329 ;
        RECT  0 4.311 0.018 4.329 ;
        RECT  64.782 3.771 64.8 3.789 ;
        RECT  0 3.771 0.018 3.789 ;
        RECT  64.782 3.231 64.8 3.249 ;
        RECT  0 3.231 0.018 3.249 ;
        RECT  64.782 2.691 64.8 2.709 ;
        RECT  0 2.691 0.018 2.709 ;
        RECT  64.782 2.151 64.8 2.169 ;
        RECT  0 2.151 0.018 2.169 ;
        RECT  64.782 1.611 64.8 1.629 ;
        RECT  0 1.611 0.018 1.629 ;
        RECT  64.782 1.071 64.8 1.089 ;
        RECT  0 1.071 0.018 1.089 ;
        RECT  64.782 0.531 64.8 0.549 ;
        RECT  0 0.531 0.018 0.549 ;
      LAYER M1 ;
        RECT  64.782 64.251 64.8 64.269 ;
        RECT  0 64.251 0.018 64.269 ;
        RECT  64.782 63.711 64.8 63.729 ;
        RECT  0 63.711 0.018 63.729 ;
        RECT  64.782 63.171 64.8 63.189 ;
        RECT  0 63.171 0.018 63.189 ;
        RECT  64.782 62.631 64.8 62.649 ;
        RECT  0 62.631 0.018 62.649 ;
        RECT  64.782 62.091 64.8 62.109 ;
        RECT  0 62.091 0.018 62.109 ;
        RECT  64.782 61.551 64.8 61.569 ;
        RECT  0 61.551 0.018 61.569 ;
        RECT  64.782 61.011 64.8 61.029 ;
        RECT  0 61.011 0.018 61.029 ;
        RECT  64.782 60.471 64.8 60.489 ;
        RECT  0 60.471 0.018 60.489 ;
        RECT  64.782 59.931 64.8 59.949 ;
        RECT  0 59.931 0.018 59.949 ;
        RECT  64.782 59.391 64.8 59.409 ;
        RECT  0 59.391 0.018 59.409 ;
        RECT  64.782 58.851 64.8 58.869 ;
        RECT  0 58.851 0.018 58.869 ;
        RECT  64.782 58.311 64.8 58.329 ;
        RECT  0 58.311 0.018 58.329 ;
        RECT  64.782 57.771 64.8 57.789 ;
        RECT  0 57.771 0.018 57.789 ;
        RECT  64.782 57.231 64.8 57.249 ;
        RECT  0 57.231 0.018 57.249 ;
        RECT  64.782 56.691 64.8 56.709 ;
        RECT  0 56.691 0.018 56.709 ;
        RECT  64.782 56.151 64.8 56.169 ;
        RECT  0 56.151 0.018 56.169 ;
        RECT  64.782 55.611 64.8 55.629 ;
        RECT  0 55.611 0.018 55.629 ;
        RECT  64.782 55.071 64.8 55.089 ;
        RECT  0 55.071 0.018 55.089 ;
        RECT  64.782 54.531 64.8 54.549 ;
        RECT  0 54.531 0.018 54.549 ;
        RECT  64.782 53.991 64.8 54.009 ;
        RECT  0 53.991 0.018 54.009 ;
        RECT  64.782 53.451 64.8 53.469 ;
        RECT  0 53.451 0.018 53.469 ;
        RECT  64.782 52.911 64.8 52.929 ;
        RECT  0 52.911 0.018 52.929 ;
        RECT  64.782 52.371 64.8 52.389 ;
        RECT  0 52.371 0.018 52.389 ;
        RECT  64.782 51.831 64.8 51.849 ;
        RECT  0 51.831 0.018 51.849 ;
        RECT  64.782 51.291 64.8 51.309 ;
        RECT  0 51.291 0.018 51.309 ;
        RECT  64.782 50.751 64.8 50.769 ;
        RECT  0 50.751 0.018 50.769 ;
        RECT  64.782 50.211 64.8 50.229 ;
        RECT  0 50.211 0.018 50.229 ;
        RECT  64.782 49.671 64.8 49.689 ;
        RECT  0 49.671 0.018 49.689 ;
        RECT  64.782 49.131 64.8 49.149 ;
        RECT  0 49.131 0.018 49.149 ;
        RECT  64.782 48.591 64.8 48.609 ;
        RECT  0 48.591 0.018 48.609 ;
        RECT  64.782 48.051 64.8 48.069 ;
        RECT  0 48.051 0.018 48.069 ;
        RECT  64.782 47.511 64.8 47.529 ;
        RECT  0 47.511 0.018 47.529 ;
        RECT  64.782 46.971 64.8 46.989 ;
        RECT  0 46.971 0.018 46.989 ;
        RECT  64.782 46.431 64.8 46.449 ;
        RECT  0 46.431 0.018 46.449 ;
        RECT  64.782 45.891 64.8 45.909 ;
        RECT  0 45.891 0.018 45.909 ;
        RECT  64.782 45.351 64.8 45.369 ;
        RECT  0 45.351 0.018 45.369 ;
        RECT  64.782 44.811 64.8 44.829 ;
        RECT  0 44.811 0.018 44.829 ;
        RECT  64.782 44.271 64.8 44.289 ;
        RECT  0 44.271 0.018 44.289 ;
        RECT  64.782 43.731 64.8 43.749 ;
        RECT  0 43.731 0.018 43.749 ;
        RECT  64.782 43.191 64.8 43.209 ;
        RECT  0 43.191 0.018 43.209 ;
        RECT  64.782 42.651 64.8 42.669 ;
        RECT  0 42.651 0.018 42.669 ;
        RECT  64.782 42.111 64.8 42.129 ;
        RECT  0 42.111 0.018 42.129 ;
        RECT  64.782 41.571 64.8 41.589 ;
        RECT  0 41.571 0.018 41.589 ;
        RECT  64.782 41.031 64.8 41.049 ;
        RECT  0 41.031 0.018 41.049 ;
        RECT  64.782 40.491 64.8 40.509 ;
        RECT  0 40.491 0.018 40.509 ;
        RECT  64.782 39.951 64.8 39.969 ;
        RECT  0 39.951 0.018 39.969 ;
        RECT  64.782 39.411 64.8 39.429 ;
        RECT  0 39.411 0.018 39.429 ;
        RECT  64.782 38.871 64.8 38.889 ;
        RECT  0 38.871 0.018 38.889 ;
        RECT  64.782 38.331 64.8 38.349 ;
        RECT  0 38.331 0.018 38.349 ;
        RECT  64.782 37.791 64.8 37.809 ;
        RECT  0 37.791 0.018 37.809 ;
        RECT  64.782 37.251 64.8 37.269 ;
        RECT  0 37.251 0.018 37.269 ;
        RECT  64.782 36.711 64.8 36.729 ;
        RECT  0 36.711 0.018 36.729 ;
        RECT  64.782 36.171 64.8 36.189 ;
        RECT  0 36.171 0.018 36.189 ;
        RECT  64.782 35.631 64.8 35.649 ;
        RECT  0 35.631 0.018 35.649 ;
        RECT  64.782 35.091 64.8 35.109 ;
        RECT  0 35.091 0.018 35.109 ;
        RECT  64.782 34.551 64.8 34.569 ;
        RECT  0 34.551 0.018 34.569 ;
        RECT  64.782 34.011 64.8 34.029 ;
        RECT  0 34.011 0.018 34.029 ;
        RECT  64.782 33.471 64.8 33.489 ;
        RECT  0 33.471 0.018 33.489 ;
        RECT  64.782 32.931 64.8 32.949 ;
        RECT  0 32.931 0.018 32.949 ;
        RECT  64.782 32.391 64.8 32.409 ;
        RECT  0 32.391 0.018 32.409 ;
        RECT  64.782 31.851 64.8 31.869 ;
        RECT  0 31.851 0.018 31.869 ;
        RECT  64.782 31.311 64.8 31.329 ;
        RECT  0 31.311 0.018 31.329 ;
        RECT  64.782 30.771 64.8 30.789 ;
        RECT  0 30.771 0.018 30.789 ;
        RECT  64.782 30.231 64.8 30.249 ;
        RECT  0 30.231 0.018 30.249 ;
        RECT  64.782 29.691 64.8 29.709 ;
        RECT  0 29.691 0.018 29.709 ;
        RECT  64.782 29.151 64.8 29.169 ;
        RECT  0 29.151 0.018 29.169 ;
        RECT  64.782 28.611 64.8 28.629 ;
        RECT  0 28.611 0.018 28.629 ;
        RECT  64.782 28.071 64.8 28.089 ;
        RECT  0 28.071 0.018 28.089 ;
        RECT  64.782 27.531 64.8 27.549 ;
        RECT  0 27.531 0.018 27.549 ;
        RECT  64.782 26.991 64.8 27.009 ;
        RECT  0 26.991 0.018 27.009 ;
        RECT  64.782 26.451 64.8 26.469 ;
        RECT  0 26.451 0.018 26.469 ;
        RECT  64.782 25.911 64.8 25.929 ;
        RECT  0 25.911 0.018 25.929 ;
        RECT  64.782 25.371 64.8 25.389 ;
        RECT  0 25.371 0.018 25.389 ;
        RECT  64.782 24.831 64.8 24.849 ;
        RECT  0 24.831 0.018 24.849 ;
        RECT  64.782 24.291 64.8 24.309 ;
        RECT  0 24.291 0.018 24.309 ;
        RECT  64.782 23.751 64.8 23.769 ;
        RECT  0 23.751 0.018 23.769 ;
        RECT  64.782 23.211 64.8 23.229 ;
        RECT  0 23.211 0.018 23.229 ;
        RECT  64.782 22.671 64.8 22.689 ;
        RECT  0 22.671 0.018 22.689 ;
        RECT  64.782 22.131 64.8 22.149 ;
        RECT  0 22.131 0.018 22.149 ;
        RECT  64.782 21.591 64.8 21.609 ;
        RECT  0 21.591 0.018 21.609 ;
        RECT  64.782 21.051 64.8 21.069 ;
        RECT  0 21.051 0.018 21.069 ;
        RECT  64.782 20.511 64.8 20.529 ;
        RECT  0 20.511 0.018 20.529 ;
        RECT  64.782 19.971 64.8 19.989 ;
        RECT  0 19.971 0.018 19.989 ;
        RECT  64.782 19.431 64.8 19.449 ;
        RECT  0 19.431 0.018 19.449 ;
        RECT  64.782 18.891 64.8 18.909 ;
        RECT  0 18.891 0.018 18.909 ;
        RECT  64.782 18.351 64.8 18.369 ;
        RECT  0 18.351 0.018 18.369 ;
        RECT  64.782 17.811 64.8 17.829 ;
        RECT  0 17.811 0.018 17.829 ;
        RECT  64.782 17.271 64.8 17.289 ;
        RECT  0 17.271 0.018 17.289 ;
        RECT  64.782 16.731 64.8 16.749 ;
        RECT  0 16.731 0.018 16.749 ;
        RECT  64.782 16.191 64.8 16.209 ;
        RECT  0 16.191 0.018 16.209 ;
        RECT  64.782 15.651 64.8 15.669 ;
        RECT  0 15.651 0.018 15.669 ;
        RECT  64.782 15.111 64.8 15.129 ;
        RECT  0 15.111 0.018 15.129 ;
        RECT  64.782 14.571 64.8 14.589 ;
        RECT  0 14.571 0.018 14.589 ;
        RECT  64.782 14.031 64.8 14.049 ;
        RECT  0 14.031 0.018 14.049 ;
        RECT  64.782 13.491 64.8 13.509 ;
        RECT  0 13.491 0.018 13.509 ;
        RECT  64.782 12.951 64.8 12.969 ;
        RECT  0 12.951 0.018 12.969 ;
        RECT  64.782 12.411 64.8 12.429 ;
        RECT  0 12.411 0.018 12.429 ;
        RECT  64.782 11.871 64.8 11.889 ;
        RECT  0 11.871 0.018 11.889 ;
        RECT  64.782 11.331 64.8 11.349 ;
        RECT  0 11.331 0.018 11.349 ;
        RECT  64.782 10.791 64.8 10.809 ;
        RECT  0 10.791 0.018 10.809 ;
        RECT  64.782 10.251 64.8 10.269 ;
        RECT  0 10.251 0.018 10.269 ;
        RECT  64.782 9.711 64.8 9.729 ;
        RECT  0 9.711 0.018 9.729 ;
        RECT  64.782 9.171 64.8 9.189 ;
        RECT  0 9.171 0.018 9.189 ;
        RECT  64.782 8.631 64.8 8.649 ;
        RECT  0 8.631 0.018 8.649 ;
        RECT  64.782 8.091 64.8 8.109 ;
        RECT  0 8.091 0.018 8.109 ;
        RECT  64.782 7.551 64.8 7.569 ;
        RECT  0 7.551 0.018 7.569 ;
        RECT  64.782 7.011 64.8 7.029 ;
        RECT  0 7.011 0.018 7.029 ;
        RECT  64.782 6.471 64.8 6.489 ;
        RECT  0 6.471 0.018 6.489 ;
        RECT  64.782 5.931 64.8 5.949 ;
        RECT  0 5.931 0.018 5.949 ;
        RECT  64.782 5.391 64.8 5.409 ;
        RECT  0 5.391 0.018 5.409 ;
        RECT  64.782 4.851 64.8 4.869 ;
        RECT  0 4.851 0.018 4.869 ;
        RECT  64.782 4.311 64.8 4.329 ;
        RECT  0 4.311 0.018 4.329 ;
        RECT  64.782 3.771 64.8 3.789 ;
        RECT  0 3.771 0.018 3.789 ;
        RECT  64.782 3.231 64.8 3.249 ;
        RECT  0 3.231 0.018 3.249 ;
        RECT  64.782 2.691 64.8 2.709 ;
        RECT  0 2.691 0.018 2.709 ;
        RECT  64.782 2.151 64.8 2.169 ;
        RECT  0 2.151 0.018 2.169 ;
        RECT  64.782 1.611 64.8 1.629 ;
        RECT  0 1.611 0.018 1.629 ;
        RECT  64.782 1.071 64.8 1.089 ;
        RECT  0 1.071 0.018 1.089 ;
        RECT  64.782 0.531 64.8 0.549 ;
        RECT  0 0.531 0.018 0.549 ;
    END
  END VSS
  OBS
    LAYER RVTN ;
     RECT  0 0.54 64.8 0.675 ;
     RECT  0 0.945 64.8 1.215 ;
     RECT  0 1.485 64.8 1.755 ;
     RECT  0 2.025 64.8 2.295 ;
     RECT  0 2.565 64.8 2.835 ;
     RECT  0 3.105 64.8 3.375 ;
     RECT  0 3.645 64.8 3.915 ;
     RECT  0 4.185 64.8 4.455 ;
     RECT  0 4.725 64.8 4.995 ;
     RECT  0 5.265 64.8 5.535 ;
     RECT  0 5.805 64.8 6.075 ;
     RECT  0 6.345 64.8 6.615 ;
     RECT  0 6.885 64.8 7.155 ;
     RECT  0 7.425 64.8 7.695 ;
     RECT  0 7.965 64.8 8.235 ;
     RECT  0 8.505 64.8 8.775 ;
     RECT  0 9.045 64.8 9.315 ;
     RECT  0 9.585 64.8 9.855 ;
     RECT  0 10.125 64.8 10.395 ;
     RECT  0 10.665 64.8 10.935 ;
     RECT  0 11.205 64.8 11.475 ;
     RECT  0 11.745 64.8 12.015 ;
     RECT  0 12.285 64.8 12.555 ;
     RECT  0 12.825 64.8 13.095 ;
     RECT  0 13.365 64.8 13.635 ;
     RECT  0 13.905 64.8 14.175 ;
     RECT  0 14.445 64.8 14.715 ;
     RECT  0 14.985 64.8 15.255 ;
     RECT  0 15.525 64.8 15.795 ;
     RECT  0 16.065 64.8 16.335 ;
     RECT  0 16.605 64.8 16.875 ;
     RECT  0 17.145 64.8 17.415 ;
     RECT  0 17.685 64.8 17.955 ;
     RECT  0 18.225 64.8 18.495 ;
     RECT  0 18.765 64.8 19.035 ;
     RECT  0 19.305 64.8 19.575 ;
     RECT  0 19.845 64.8 20.115 ;
     RECT  0 20.385 64.8 20.655 ;
     RECT  0 20.925 64.8 21.195 ;
     RECT  0 21.465 64.8 21.735 ;
     RECT  0 22.005 64.8 22.275 ;
     RECT  0 22.545 64.8 22.815 ;
     RECT  0 23.085 64.8 23.355 ;
     RECT  0 23.625 64.8 23.895 ;
     RECT  0 24.165 64.8 24.435 ;
     RECT  0 24.705 64.8 24.975 ;
     RECT  0 25.245 64.8 25.515 ;
     RECT  0 25.785 64.8 26.055 ;
     RECT  0 26.325 64.8 26.595 ;
     RECT  0 26.865 64.8 27.135 ;
     RECT  0 27.405 64.8 27.675 ;
     RECT  0 27.945 64.8 28.215 ;
     RECT  0 28.485 64.8 28.755 ;
     RECT  0 29.025 64.8 29.295 ;
     RECT  0 29.565 64.8 29.835 ;
     RECT  0 30.105 64.8 30.375 ;
     RECT  0 30.645 64.8 30.915 ;
     RECT  0 31.185 64.8 31.455 ;
     RECT  0 31.725 64.8 31.995 ;
     RECT  0 32.265 64.8 32.535 ;
     RECT  0 32.805 64.8 33.075 ;
     RECT  0 33.345 64.8 33.615 ;
     RECT  0 33.885 64.8 34.155 ;
     RECT  0 34.425 64.8 34.695 ;
     RECT  0 34.965 64.8 35.235 ;
     RECT  0 35.505 64.8 35.775 ;
     RECT  0 36.045 64.8 36.315 ;
     RECT  0 36.585 64.8 36.855 ;
     RECT  0 37.125 64.8 37.395 ;
     RECT  0 37.665 64.8 37.935 ;
     RECT  0 38.205 64.8 38.475 ;
     RECT  0 38.745 64.8 39.015 ;
     RECT  0 39.285 64.8 39.555 ;
     RECT  0 39.825 64.8 40.095 ;
     RECT  0 40.365 64.8 40.635 ;
     RECT  0 40.905 64.8 41.175 ;
     RECT  0 41.445 64.8 41.715 ;
     RECT  0 41.985 64.8 42.255 ;
     RECT  0 42.525 64.8 42.795 ;
     RECT  0 43.065 64.8 43.335 ;
     RECT  0 43.605 64.8 43.875 ;
     RECT  0 44.145 64.8 44.415 ;
     RECT  0 44.685 64.8 44.955 ;
     RECT  0 45.225 64.8 45.495 ;
     RECT  0 45.765 64.8 46.035 ;
     RECT  0 46.305 64.8 46.575 ;
     RECT  0 46.845 64.8 47.115 ;
     RECT  0 47.385 64.8 47.655 ;
     RECT  0 47.925 64.8 48.195 ;
     RECT  0 48.465 64.8 48.735 ;
     RECT  0 49.005 64.8 49.275 ;
     RECT  0 49.545 64.8 49.815 ;
     RECT  0 50.085 64.8 50.355 ;
     RECT  0 50.625 64.8 50.895 ;
     RECT  0 51.165 64.8 51.435 ;
     RECT  0 51.705 64.8 51.975 ;
     RECT  0 52.245 64.8 52.515 ;
     RECT  0 52.785 64.8 53.055 ;
     RECT  0 53.325 64.8 53.595 ;
     RECT  0 53.865 64.8 54.135 ;
     RECT  0 54.405 64.8 54.675 ;
     RECT  0 54.945 64.8 55.215 ;
     RECT  0 55.485 64.8 55.755 ;
     RECT  0 56.025 64.8 56.295 ;
     RECT  0 56.565 64.8 56.835 ;
     RECT  0 57.105 64.8 57.375 ;
     RECT  0 57.645 64.8 57.915 ;
     RECT  0 58.185 64.8 58.455 ;
     RECT  0 58.725 64.8 58.995 ;
     RECT  0 59.265 64.8 59.535 ;
     RECT  0 59.805 64.8 60.075 ;
     RECT  0 60.345 64.8 60.615 ;
     RECT  0 60.885 64.8 61.155 ;
     RECT  0 61.425 64.8 61.695 ;
     RECT  0 61.965 64.8 62.235 ;
     RECT  0 62.505 64.8 62.775 ;
     RECT  0 63.045 64.8 63.315 ;
     RECT  0 63.585 64.8 63.855 ;
     RECT  0 64.125 64.8 64.26 ;
    LAYER RVTP ;
     RECT  0 0.675 64.8 0.945 ;
     RECT  0 1.215 64.8 1.485 ;
     RECT  0 1.755 64.8 2.025 ;
     RECT  0 2.295 64.8 2.565 ;
     RECT  0 2.835 64.8 3.105 ;
     RECT  0 3.375 64.8 3.645 ;
     RECT  0 3.915 64.8 4.185 ;
     RECT  0 4.455 64.8 4.725 ;
     RECT  0 4.995 64.8 5.265 ;
     RECT  0 5.535 64.8 5.805 ;
     RECT  0 6.075 64.8 6.345 ;
     RECT  0 6.615 64.8 6.885 ;
     RECT  0 7.155 64.8 7.425 ;
     RECT  0 7.695 64.8 7.965 ;
     RECT  0 8.235 64.8 8.505 ;
     RECT  0 8.775 64.8 9.045 ;
     RECT  0 9.315 64.8 9.585 ;
     RECT  0 9.855 64.8 10.125 ;
     RECT  0 10.395 64.8 10.665 ;
     RECT  0 10.935 64.8 11.205 ;
     RECT  0 11.475 64.8 11.745 ;
     RECT  0 12.015 64.8 12.285 ;
     RECT  0 12.555 64.8 12.825 ;
     RECT  0 13.095 64.8 13.365 ;
     RECT  0 13.635 64.8 13.905 ;
     RECT  0 14.175 64.8 14.445 ;
     RECT  0 14.715 64.8 14.985 ;
     RECT  0 15.255 64.8 15.525 ;
     RECT  0 15.795 64.8 16.065 ;
     RECT  0 16.335 64.8 16.605 ;
     RECT  0 16.875 64.8 17.145 ;
     RECT  0 17.415 64.8 17.685 ;
     RECT  0 17.955 64.8 18.225 ;
     RECT  0 18.495 64.8 18.765 ;
     RECT  0 19.035 64.8 19.305 ;
     RECT  0 19.575 64.8 19.845 ;
     RECT  0 20.115 64.8 20.385 ;
     RECT  0 20.655 64.8 20.925 ;
     RECT  0 21.195 64.8 21.465 ;
     RECT  0 21.735 64.8 22.005 ;
     RECT  0 22.275 64.8 22.545 ;
     RECT  0 22.815 64.8 23.085 ;
     RECT  0 23.355 64.8 23.625 ;
     RECT  0 23.895 64.8 24.165 ;
     RECT  0 24.435 64.8 24.705 ;
     RECT  0 24.975 64.8 25.245 ;
     RECT  0 25.515 64.8 25.785 ;
     RECT  0 26.055 64.8 26.325 ;
     RECT  0 26.595 64.8 26.865 ;
     RECT  0 27.135 64.8 27.405 ;
     RECT  0 27.675 64.8 27.945 ;
     RECT  0 28.215 64.8 28.485 ;
     RECT  0 28.755 64.8 29.025 ;
     RECT  0 29.295 64.8 29.565 ;
     RECT  0 29.835 64.8 30.105 ;
     RECT  0 30.375 64.8 30.645 ;
     RECT  0 30.915 64.8 31.185 ;
     RECT  0 31.455 64.8 31.725 ;
     RECT  0 31.995 64.8 32.265 ;
     RECT  0 32.535 64.8 32.805 ;
     RECT  0 33.075 64.8 33.345 ;
     RECT  0 33.615 64.8 33.885 ;
     RECT  0 34.155 64.8 34.425 ;
     RECT  0 34.695 64.8 34.965 ;
     RECT  0 35.235 64.8 35.505 ;
     RECT  0 35.775 64.8 36.045 ;
     RECT  0 36.315 64.8 36.585 ;
     RECT  0 36.855 64.8 37.125 ;
     RECT  0 37.395 64.8 37.665 ;
     RECT  0 37.935 64.8 38.205 ;
     RECT  0 38.475 64.8 38.745 ;
     RECT  0 39.015 64.8 39.285 ;
     RECT  0 39.555 64.8 39.825 ;
     RECT  0 40.095 64.8 40.365 ;
     RECT  0 40.635 64.8 40.905 ;
     RECT  0 41.175 64.8 41.445 ;
     RECT  0 41.715 64.8 41.985 ;
     RECT  0 42.255 64.8 42.525 ;
     RECT  0 42.795 64.8 43.065 ;
     RECT  0 43.335 64.8 43.605 ;
     RECT  0 43.875 64.8 44.145 ;
     RECT  0 44.415 64.8 44.685 ;
     RECT  0 44.955 64.8 45.225 ;
     RECT  0 45.495 64.8 45.765 ;
     RECT  0 46.035 64.8 46.305 ;
     RECT  0 46.575 64.8 46.845 ;
     RECT  0 47.115 64.8 47.385 ;
     RECT  0 47.655 64.8 47.925 ;
     RECT  0 48.195 64.8 48.465 ;
     RECT  0 48.735 64.8 49.005 ;
     RECT  0 49.275 64.8 49.545 ;
     RECT  0 49.815 64.8 50.085 ;
     RECT  0 50.355 64.8 50.625 ;
     RECT  0 50.895 64.8 51.165 ;
     RECT  0 51.435 64.8 51.705 ;
     RECT  0 51.975 64.8 52.245 ;
     RECT  0 52.515 64.8 52.785 ;
     RECT  0 53.055 64.8 53.325 ;
     RECT  0 53.595 64.8 53.865 ;
     RECT  0 54.135 64.8 54.405 ;
     RECT  0 54.675 64.8 54.945 ;
     RECT  0 55.215 64.8 55.485 ;
     RECT  0 55.755 64.8 56.025 ;
     RECT  0 56.295 64.8 56.565 ;
     RECT  0 56.835 64.8 57.105 ;
     RECT  0 57.375 64.8 57.645 ;
     RECT  0 57.915 64.8 58.185 ;
     RECT  0 58.455 64.8 58.725 ;
     RECT  0 58.995 64.8 59.265 ;
     RECT  0 59.535 64.8 59.805 ;
     RECT  0 60.075 64.8 60.345 ;
     RECT  0 60.615 64.8 60.885 ;
     RECT  0 61.155 64.8 61.425 ;
     RECT  0 61.695 64.8 61.965 ;
     RECT  0 62.235 64.8 62.505 ;
     RECT  0 62.775 64.8 63.045 ;
     RECT  0 63.315 64.8 63.585 ;
     RECT  0 63.855 64.8 64.125 ;
    LAYER M1 ;
     RECT  0 0.531 64.8 64.269 ;
    LAYER M2 ;
     RECT  0 0.531 26.851 64.269 ;
     RECT  26.851 0.531 31.379 64.314 ;
     RECT  31.379 0.531 64.8 64.269 ;
    LAYER M3 ;
     RECT  15.444 0.187 16.182 0.283 ;
     RECT  15.3 0.283 16.182 0.379 ;
     RECT  15.3 0.379 16.434 0.523 ;
     RECT  43.308 0.187 43.326 0.523 ;
     RECT  42.624 0.523 43.545 0.571 ;
     RECT  48.855 0.523 48.945 0.571 ;
     RECT  42.444 0.571 43.545 0.619 ;
     RECT  48.636 0.571 48.945 0.619 ;
     RECT  15.3 0.523 16.545 0.667 ;
     RECT  42.444 0.619 43.902 0.715 ;
     RECT  15.3 0.667 16.794 0.751 ;
     RECT  42.444 0.715 44.046 0.751 ;
     RECT  0.255 0.523 0.345 0.793 ;
     RECT  5.655 0.523 5.745 0.793 ;
     RECT  11.055 0.523 11.145 0.793 ;
     RECT  21.855 0.523 21.945 0.793 ;
     RECT  27.255 0.523 27.345 0.793 ;
     RECT  32.655 0.523 32.745 0.793 ;
     RECT  38.055 0.523 38.145 0.793 ;
     RECT  48.096 0.619 48.945 0.793 ;
     RECT  54.255 0.523 54.345 0.793 ;
     RECT  59.655 0.523 59.745 0.793 ;
     RECT  45.864 0.841 45.882 0.877 ;
     RECT  24.48 0.877 25.146 0.913 ;
     RECT  45.864 0.877 46.494 0.949 ;
     RECT  23.472 0.187 23.49 1.021 ;
     RECT  24.48 0.913 25.29 1.021 ;
     RECT  32.655 0.793 32.937 1.021 ;
     RECT  37.008 0.751 37.026 1.021 ;
     RECT  38.055 0.793 38.337 1.021 ;
     RECT  45.612 0.949 46.494 1.021 ;
     RECT  32.655 1.021 34.182 1.111 ;
     RECT  40.428 0.985 40.446 1.111 ;
     RECT  37.008 1.021 38.862 1.139 ;
     RECT  23.472 1.021 23.706 1.147 ;
     RECT  40.104 1.111 40.446 1.147 ;
     RECT  42.012 0.751 44.37 1.147 ;
     RECT  55.656 0.187 55.674 1.175 ;
     RECT  31.932 1.111 34.182 1.219 ;
     RECT  31.356 1.219 34.182 1.243 ;
     RECT  29.232 1.111 29.682 1.255 ;
     RECT  31.356 1.243 34.722 1.255 ;
     RECT  41.688 1.147 44.37 1.255 ;
     RECT  48.096 0.793 49.137 1.255 ;
     RECT  37.008 1.139 38.466 1.277 ;
     RECT  24.48 1.021 25.758 1.291 ;
     RECT  27.255 0.793 27.537 1.291 ;
     RECT  30.816 1.255 34.722 1.291 ;
     RECT  40.104 1.147 40.698 1.291 ;
     RECT  41.688 1.255 44.874 1.291 ;
     RECT  45.612 1.021 46.746 1.291 ;
     RECT  54.255 0.793 54.537 1.291 ;
     RECT  36.108 1.255 36.126 1.387 ;
     RECT  30.816 1.291 34.974 1.409 ;
     RECT  37.008 1.277 38.43 1.409 ;
     RECT  39.744 1.291 46.746 1.417 ;
     RECT  36 1.387 36.126 1.453 ;
     RECT  37.008 1.409 38.394 1.453 ;
     RECT  15.3 0.751 17.19 1.489 ;
     RECT  24.48 1.291 26.01 1.489 ;
     RECT  27.216 1.291 27.846 1.489 ;
     RECT  23.328 1.147 23.706 1.525 ;
     RECT  24.48 1.489 27.846 1.525 ;
     RECT  31.932 1.409 34.974 1.561 ;
     RECT  36 1.453 38.394 1.561 ;
     RECT  14.832 1.489 17.19 1.589 ;
     RECT  54.255 1.291 54.918 1.589 ;
     RECT  20.916 1.525 20.934 1.651 ;
     RECT  21.855 0.793 22.137 1.651 ;
     RECT  22.968 1.525 27.846 1.651 ;
     RECT  15.3 1.589 17.19 1.687 ;
     RECT  21.855 1.651 27.846 1.687 ;
     RECT  28.656 1.255 29.682 1.687 ;
     RECT  30.816 1.409 31.086 1.687 ;
     RECT  39.348 1.417 46.746 1.687 ;
     RECT  47.988 1.255 49.137 1.687 ;
     RECT  20.736 1.651 20.934 1.759 ;
     RECT  21.855 1.687 29.682 1.759 ;
     RECT  20.736 1.759 29.682 1.795 ;
     RECT  20.16 1.795 29.682 1.831 ;
     RECT  30.528 1.687 31.086 1.831 ;
     RECT  31.932 1.561 38.394 2.021 ;
     RECT  39.348 1.687 49.137 2.065 ;
     RECT  15.3 1.687 17.442 2.101 ;
     RECT  20.16 1.831 31.086 2.191 ;
     RECT  19.944 2.191 31.086 2.251 ;
     RECT  19.692 2.251 31.086 2.263 ;
     RECT  31.932 2.021 33.246 2.263 ;
     RECT  33.984 2.021 38.394 2.299 ;
     RECT  39.132 2.065 49.137 2.299 ;
     RECT  19.692 2.263 33.246 2.335 ;
     RECT  15.3 2.101 17.838 2.371 ;
     RECT  19.404 2.335 33.246 2.497 ;
     RECT  18.72 2.497 33.246 2.669 ;
     RECT  18.72 2.669 19.422 2.803 ;
     RECT  15.156 2.371 17.838 2.875 ;
     RECT  18.648 2.803 19.422 2.875 ;
     RECT  20.664 2.669 33.246 2.923 ;
     RECT  33.984 2.299 49.137 2.923 ;
     RECT  20.664 2.923 49.137 2.939 ;
     RECT  31.716 2.939 49.137 3.053 ;
     RECT  15.156 2.875 19.422 3.109 ;
     RECT  31.824 3.053 49.137 3.569 ;
     RECT  20.664 2.939 30.978 3.605 ;
     RECT  26.028 3.605 30.978 3.677 ;
     RECT  14.508 3.109 19.422 3.721 ;
     RECT  20.664 3.605 25.254 3.721 ;
     RECT  14.508 3.721 25.254 3.811 ;
     RECT  14.256 3.811 25.254 3.835 ;
     RECT  14.004 3.835 25.254 3.869 ;
     RECT  14.004 3.869 14.526 3.875 ;
     RECT  26.1 3.677 30.978 3.883 ;
     RECT  31.824 3.569 33.03 3.883 ;
     RECT  14.256 3.875 14.526 4.109 ;
     RECT  33.768 3.569 47.43 4.351 ;
     RECT  48.204 3.569 49.137 4.351 ;
     RECT  26.1 3.883 33.03 4.387 ;
     RECT  33.768 4.351 49.137 4.387 ;
     RECT  26.1 4.387 49.137 4.451 ;
     RECT  46.008 4.451 49.137 4.487 ;
     RECT  15.48 3.869 25.254 4.693 ;
     RECT  26.1 4.451 45.27 4.693 ;
     RECT  15.48 4.693 45.27 4.829 ;
     RECT  29.628 4.829 45.27 5.305 ;
     RECT  29.628 5.305 45.342 5.341 ;
     RECT  46.152 4.487 49.137 5.341 ;
     RECT  29.628 5.341 49.137 5.575 ;
     RECT  29.628 5.575 49.302 5.639 ;
     RECT  50.652 5.161 50.67 5.737 ;
     RECT  15.48 4.829 28.854 5.755 ;
     RECT  29.628 5.639 34.83 5.755 ;
     RECT  35.712 5.639 49.302 5.765 ;
     RECT  50.544 5.737 50.67 5.773 ;
     RECT  50.544 5.773 50.742 5.845 ;
     RECT  11.055 0.793 11.337 5.971 ;
     RECT  36 5.765 49.302 5.971 ;
     RECT  50.544 5.845 51.138 6.043 ;
     RECT  50.508 6.043 51.138 6.079 ;
     RECT  52.236 5.881 52.254 6.079 ;
     RECT  8.676 5.995 8.694 6.151 ;
     RECT  10.584 5.971 11.337 6.151 ;
     RECT  13.212 1.489 13.23 6.151 ;
     RECT  36 5.971 49.77 6.151 ;
     RECT  50.508 6.079 52.254 6.151 ;
     RECT  8.676 6.151 9.378 6.241 ;
     RECT  10.584 6.151 13.23 6.331 ;
     RECT  36 6.151 52.254 6.421 ;
     RECT  10.584 6.331 13.554 6.511 ;
     RECT  36 6.421 52.578 6.539 ;
     RECT  7.596 6.511 7.614 6.583 ;
     RECT  10.584 6.511 13.59 6.583 ;
     RECT  15.48 5.755 34.83 6.583 ;
     RECT  36 6.539 52.182 6.583 ;
     RECT  7.02 6.583 7.614 6.619 ;
     RECT  8.496 6.241 9.378 6.619 ;
     RECT  10.404 6.583 13.59 6.619 ;
     RECT  14.508 4.109 14.526 6.619 ;
     RECT  7.02 6.619 9.378 6.691 ;
     RECT  15.48 6.583 52.182 6.808 ;
     RECT  15.3 6.808 52.182 6.809 ;
     RECT  15.3 6.809 34.938 6.845 ;
     RECT  35.676 6.809 51.066 6.845 ;
     RECT  7.02 6.691 9.486 7.231 ;
     RECT  10.404 6.619 14.526 7.231 ;
     RECT  15.624 6.845 34.938 7.349 ;
     RECT  7.02 7.231 14.526 7.373 ;
     RECT  35.676 6.845 50.994 7.421 ;
     RECT  15.624 7.349 34.65 7.427 ;
     RECT  15.624 7.427 34.578 7.619 ;
     RECT  10.584 7.373 14.526 7.771 ;
     RECT  7.02 7.373 9.486 7.925 ;
     RECT  7.056 7.925 9.486 7.949 ;
     RECT  7.308 7.949 9.486 8.033 ;
     RECT  3.6 2.803 3.618 8.041 ;
     RECT  5.655 0.793 5.937 8.041 ;
     RECT  3.6 8.041 4.194 8.131 ;
     RECT  0.255 0.793 0.537 8.155 ;
     RECT  3.204 8.131 4.194 8.167 ;
     RECT  35.928 7.421 50.994 8.167 ;
     RECT  51.84 6.809 51.858 8.167 ;
     RECT  0.255 8.155 0.702 8.203 ;
     RECT  1.656 8.155 1.674 8.203 ;
     RECT  3.06 8.167 4.554 8.275 ;
     RECT  5.292 8.041 6.246 8.275 ;
     RECT  0.255 8.203 1.674 8.311 ;
     RECT  3.06 8.275 6.246 8.311 ;
     RECT  35.928 8.167 51.858 8.311 ;
     RECT  35.928 8.311 52.038 8.429 ;
     RECT  9.468 8.033 9.486 8.473 ;
     RECT  10.584 7.771 14.67 8.473 ;
     RECT  15.624 7.619 34.29 8.509 ;
     RECT  35.928 8.429 51.822 8.539 ;
     RECT  15.624 8.509 34.326 8.545 ;
     RECT  35.856 8.539 51.822 8.699 ;
     RECT  0.255 8.311 6.246 8.707 ;
     RECT  15.624 8.545 34.83 8.707 ;
     RECT  35.856 8.699 51.75 8.707 ;
     RECT  7.308 8.033 8.73 8.743 ;
     RECT  15.624 8.707 34.866 8.779 ;
     RECT  35.712 8.707 51.75 8.779 ;
     RECT  9.468 8.473 14.67 8.851 ;
     RECT  15.624 8.779 51.75 8.851 ;
     RECT  9.468 8.851 51.75 8.969 ;
     RECT  0.255 8.707 6.39 9.115 ;
     RECT  7.2 8.743 8.73 9.115 ;
     RECT  9.468 8.969 14.85 9.149 ;
     RECT  50.328 8.969 51.75 9.625 ;
     RECT  50.328 9.625 52.434 9.751 ;
     RECT  0.255 9.115 8.73 9.895 ;
     RECT  9.468 9.149 14.67 9.895 ;
     RECT  15.624 8.969 49.554 9.895 ;
     RECT  50.292 9.751 52.434 9.895 ;
     RECT  0.255 9.895 14.67 9.931 ;
     RECT  15.624 9.895 52.434 9.931 ;
     RECT  0.255 9.931 14.778 10.057 ;
     RECT  15.624 9.931 53.01 10.057 ;
     RECT  0.255 10.057 53.01 10.157 ;
     RECT  49.968 10.157 53.01 10.229 ;
     RECT  0.255 10.157 49.194 10.355 ;
     RECT  15.552 10.355 49.194 10.427 ;
     RECT  50.004 10.229 53.01 10.471 ;
     RECT  0.255 10.355 14.67 10.589 ;
     RECT  50.004 10.471 53.046 10.661 ;
     RECT  50.004 10.661 52.686 10.769 ;
     RECT  15.588 10.427 49.194 10.781 ;
     RECT  3.024 10.589 14.67 10.859 ;
     RECT  5.655 10.859 14.67 11.201 ;
     RECT  0.255 10.589 2.286 11.273 ;
     RECT  15.624 10.781 49.194 11.407 ;
     RECT  15.624 11.407 49.23 11.435 ;
     RECT  50.22 10.769 52.686 11.515 ;
     RECT  15.984 11.435 49.23 11.551 ;
     RECT  15.984 11.551 49.266 11.785 ;
     RECT  50.148 11.515 52.686 11.785 ;
     RECT  15.984 11.785 52.686 11.813 ;
     RECT  2.268 11.273 2.286 11.983 ;
     RECT  3.024 10.859 4.914 11.983 ;
     RECT  0.255 11.273 1.494 12.019 ;
     RECT  2.268 11.983 4.914 12.019 ;
     RECT  9.72 11.201 14.67 12.091 ;
     RECT  0.255 12.019 4.914 12.181 ;
     RECT  5.655 11.201 8.73 12.181 ;
     RECT  15.984 11.813 34.866 12.181 ;
     RECT  15.696 12.181 34.866 12.209 ;
     RECT  35.604 11.813 52.686 12.209 ;
     RECT  35.604 12.209 52.29 12.245 ;
     RECT  30.636 12.209 34.866 12.281 ;
     RECT  15.696 12.209 29.898 12.389 ;
     RECT  30.708 12.281 34.866 12.389 ;
     RECT  9.72 12.091 14.886 12.487 ;
     RECT  20.016 12.389 29.898 12.515 ;
     RECT  15.696 12.389 19.278 12.523 ;
     RECT  20.016 12.515 28.746 12.749 ;
     RECT  30.744 12.389 34.866 12.763 ;
     RECT  35.604 12.245 51.534 12.763 ;
     RECT  9.576 12.487 14.886 12.797 ;
     RECT  0.255 12.181 8.73 12.901 ;
     RECT  9.576 12.797 14.67 12.901 ;
     RECT  15.624 12.523 19.278 12.991 ;
     RECT  0.255 12.901 14.67 13.019 ;
     RECT  24.012 12.749 28.746 13.019 ;
     RECT  15.408 12.991 19.278 13.171 ;
     RECT  20.016 12.749 23.094 13.171 ;
     RECT  15.408 13.171 23.094 13.199 ;
     RECT  29.484 12.515 29.898 13.441 ;
     RECT  30.744 12.763 51.534 13.441 ;
     RECT  52.272 12.245 52.29 13.441 ;
     RECT  24.084 13.019 28.746 13.639 ;
     RECT  29.484 13.441 52.29 13.639 ;
     RECT  0.255 13.019 14.238 13.801 ;
     RECT  0.255 13.801 14.49 13.837 ;
     RECT  15.408 13.199 17.586 13.837 ;
     RECT  0.255 13.837 17.586 13.937 ;
     RECT  24.084 13.639 52.434 13.981 ;
     RECT  24.084 13.981 52.794 14.099 ;
     RECT  0.255 13.937 17.262 14.135 ;
     RECT  24.084 14.099 45.558 14.171 ;
     RECT  7.632 14.135 17.262 14.237 ;
     RECT  24.084 14.171 45.486 14.251 ;
     RECT  24.048 14.251 45.486 14.341 ;
     RECT  24.012 14.341 45.486 14.429 ;
     RECT  46.296 14.099 52.794 14.521 ;
     RECT  18.36 13.199 23.094 14.791 ;
     RECT  24.048 14.429 45.486 14.819 ;
     RECT  0.255 14.135 6.822 14.881 ;
     RECT  7.632 14.237 15.426 14.881 ;
     RECT  24.084 14.819 45.486 14.923 ;
     RECT  46.296 14.521 52.902 14.923 ;
     RECT  0.255 14.881 15.426 14.945 ;
     RECT  16.455 14.237 17.262 14.953 ;
     RECT  15.408 14.945 15.426 14.981 ;
     RECT  16.455 14.953 17.298 15.025 ;
     RECT  16.455 15.025 17.334 15.061 ;
     RECT  0.255 14.945 14.67 15.179 ;
     RECT  1.332 15.179 14.598 15.215 ;
     RECT  15.732 15.061 17.334 15.287 ;
     RECT  16.056 15.287 17.334 15.331 ;
     RECT  18.36 14.791 23.238 15.331 ;
     RECT  24.084 14.923 52.902 15.863 ;
     RECT  24.084 15.863 51.282 15.869 ;
     RECT  0.255 15.179 0.537 15.961 ;
     RECT  1.332 15.215 14.31 15.961 ;
     RECT  16.056 15.331 23.238 15.979 ;
     RECT  24.084 15.869 45.594 15.979 ;
     RECT  52.092 15.863 52.902 15.989 ;
     RECT  0.255 15.961 14.31 16.013 ;
     RECT  46.44 15.869 51.282 16.133 ;
     RECT  16.056 15.979 45.594 16.259 ;
     RECT  52.884 15.989 52.902 16.339 ;
     RECT  16.236 16.259 45.594 16.403 ;
     RECT  16.416 16.403 45.594 16.439 ;
     RECT  15.48 16.375 15.498 16.445 ;
     RECT  16.416 16.439 23.274 16.529 ;
     RECT  1.332 16.013 14.31 16.537 ;
     RECT  35.676 16.439 45.594 16.673 ;
     RECT  59.655 0.793 59.937 16.771 ;
     RECT  55.656 16.771 55.674 16.843 ;
     RECT  55.404 16.843 55.674 16.915 ;
     RECT  59.292 16.771 59.937 16.915 ;
     RECT  0.255 16.013 0.537 16.951 ;
     RECT  1.332 16.537 14.346 16.951 ;
     RECT  52.092 15.989 52.11 16.951 ;
     RECT  52.884 16.339 53.154 16.951 ;
     RECT  54.255 1.589 54.537 16.951 ;
     RECT  58.788 16.915 59.937 16.951 ;
     RECT  57.636 16.951 59.937 17.041 ;
     RECT  0.255 16.951 14.346 17.077 ;
     RECT  52.092 16.951 54.537 17.077 ;
     RECT  55.404 16.915 55.962 17.077 ;
     RECT  0.255 17.077 14.634 17.149 ;
     RECT  56.808 16.951 56.826 17.149 ;
     RECT  57.564 17.041 60.318 17.149 ;
     RECT  50.796 16.133 51.282 17.185 ;
     RECT  52.092 17.077 55.962 17.185 ;
     RECT  20.196 16.529 23.274 17.221 ;
     RECT  24.084 16.439 34.902 17.221 ;
     RECT  36.252 16.673 45.594 17.221 ;
     RECT  46.44 16.133 49.878 17.221 ;
     RECT  50.796 17.185 55.962 17.221 ;
     RECT  36.252 17.221 45.702 17.311 ;
     RECT  46.44 17.221 55.962 17.311 ;
     RECT  0.255 17.149 14.85 17.419 ;
     RECT  16.416 16.529 19.386 17.455 ;
     RECT  20.196 17.221 34.902 17.455 ;
     RECT  56.808 17.149 60.318 17.581 ;
     RECT  61.308 17.491 61.326 17.581 ;
     RECT  0.255 17.419 15.21 17.609 ;
     RECT  36.252 17.311 55.962 17.717 ;
     RECT  16.128 17.455 34.902 17.725 ;
     RECT  56.808 17.581 61.326 17.761 ;
     RECT  36.252 17.717 54.537 17.879 ;
     RECT  55.296 17.717 55.962 17.887 ;
     RECT  56.808 17.761 61.398 17.887 ;
     RECT  16.128 17.725 35.334 17.951 ;
     RECT  17.604 17.951 35.334 17.995 ;
     RECT  36.252 17.879 51.966 17.995 ;
     RECT  56.808 17.887 61.47 18.023 ;
     RECT  61.092 18.023 61.47 18.121 ;
     RECT  56.808 18.023 60.318 18.185 ;
     RECT  55.296 17.887 55.998 18.193 ;
     RECT  56.808 18.185 57.042 18.193 ;
     RECT  61.092 18.121 62.622 18.221 ;
     RECT  57.852 18.185 60.318 18.293 ;
     RECT  62.136 18.221 62.622 18.419 ;
     RECT  0.255 17.609 14.706 18.571 ;
     RECT  52.74 17.879 54.537 18.605 ;
     RECT  0.255 18.571 14.886 18.689 ;
     RECT  57.888 18.293 60.318 18.841 ;
     RECT  61.092 18.221 61.398 18.841 ;
     RECT  57.888 18.841 61.398 18.845 ;
     RECT  16.128 17.951 16.866 18.859 ;
     RECT  15.948 18.859 16.866 18.931 ;
     RECT  17.604 17.995 51.966 18.931 ;
     RECT  55.296 18.193 57.042 19.039 ;
     RECT  57.888 18.845 61.326 19.039 ;
     RECT  15.948 18.931 51.966 19.339 ;
     RECT  15.624 19.339 51.966 19.379 ;
     RECT  62.352 18.419 62.55 19.381 ;
     RECT  16.128 19.379 51.966 19.579 ;
     RECT  55.296 19.039 61.326 19.579 ;
     RECT  62.352 19.381 62.658 19.579 ;
     RECT  16.128 19.579 52.038 19.615 ;
     RECT  53.316 18.605 54.537 19.615 ;
     RECT  55.296 19.579 62.658 19.615 ;
     RECT  53.316 19.615 62.658 19.651 ;
     RECT  16.128 19.615 52.47 19.777 ;
     RECT  53.316 19.651 62.982 19.777 ;
     RECT  16.128 19.777 63.018 19.805 ;
     RECT  52.704 19.805 63.018 19.813 ;
     RECT  52.704 19.813 63.198 19.849 ;
     RECT  52.704 19.849 63.378 19.901 ;
     RECT  0.255 18.689 14.706 19.921 ;
     RECT  0.255 19.921 15.03 20.191 ;
     RECT  0.255 20.191 15.138 20.309 ;
     RECT  52.704 19.901 63.198 20.381 ;
     RECT  0.255 20.309 15.03 20.489 ;
     RECT  52.704 20.381 61.11 20.489 ;
     RECT  61.848 20.381 63.198 20.695 ;
     RECT  16.128 19.805 51.966 20.849 ;
     RECT  52.884 20.489 61.11 20.849 ;
     RECT  16.128 20.849 42.534 20.885 ;
     RECT  61.848 20.695 63.306 20.965 ;
     RECT  61.848 20.965 63.378 21.001 ;
     RECT  16.128 20.885 24.21 21.119 ;
     RECT  16.128 21.119 24.138 21.155 ;
     RECT  61.848 21.001 63.522 21.155 ;
     RECT  25.02 20.885 42.534 21.191 ;
     RECT  0.255 20.489 14.85 21.235 ;
     RECT  16.128 21.155 24.066 21.235 ;
     RECT  0.255 21.235 15.318 21.271 ;
     RECT  16.092 21.235 24.066 21.271 ;
     RECT  43.272 20.849 51.966 21.271 ;
     RECT  52.884 20.849 60.858 21.271 ;
     RECT  0.255 21.271 24.066 21.299 ;
     RECT  61.848 21.155 63.486 21.389 ;
     RECT  0.255 21.299 18.09 21.425 ;
     RECT  12.276 21.425 18.09 21.461 ;
     RECT  16.128 21.461 18.09 21.497 ;
     RECT  12.276 21.461 15.318 21.677 ;
     RECT  43.272 21.271 60.858 21.695 ;
     RECT  36.252 21.191 42.534 21.739 ;
     RECT  43.272 21.695 54.99 21.739 ;
     RECT  12.276 21.677 14.706 21.767 ;
     RECT  55.872 21.695 60.858 21.901 ;
     RECT  61.848 21.389 63.45 21.901 ;
     RECT  36.252 21.739 54.99 21.929 ;
     RECT  25.02 21.191 35.478 21.937 ;
     RECT  36.252 21.929 51.39 22.199 ;
     RECT  18.864 21.299 24.066 22.207 ;
     RECT  24.984 21.937 35.478 22.207 ;
     RECT  18.864 22.207 35.478 22.219 ;
     RECT  36.252 22.199 50.706 22.219 ;
     RECT  16.128 21.497 18.054 22.315 ;
     RECT  18.864 22.219 50.706 22.315 ;
     RECT  0.255 21.425 11.394 22.351 ;
     RECT  12.276 21.767 14.634 22.351 ;
     RECT  55.872 21.901 63.45 22.351 ;
     RECT  55.872 22.351 64.17 22.649 ;
     RECT  55.872 22.649 63.702 22.739 ;
     RECT  0.255 22.351 14.634 22.781 ;
     RECT  5.58 22.781 14.634 22.811 ;
     RECT  12.168 22.811 14.634 22.981 ;
     RECT  16.128 22.315 50.706 22.981 ;
     RECT  52.596 21.929 54.99 23.017 ;
     RECT  57.528 22.739 63.63 23.189 ;
     RECT  52.56 23.017 54.99 23.323 ;
     RECT  55.872 22.739 56.754 23.323 ;
     RECT  12.168 22.981 14.85 23.431 ;
     RECT  16.128 22.981 50.742 23.431 ;
     RECT  52.56 23.323 56.754 23.593 ;
     RECT  57.528 23.189 63.342 23.593 ;
     RECT  52.56 23.593 63.342 23.693 ;
     RECT  12.168 23.431 50.742 23.701 ;
     RECT  52.56 23.693 56.754 23.701 ;
     RECT  52.236 23.701 56.754 23.729 ;
     RECT  52.236 23.729 55.062 23.741 ;
     RECT  12.168 23.701 51.102 23.819 ;
     RECT  55.8 23.729 56.754 23.819 ;
     RECT  0.255 22.781 4.842 23.891 ;
     RECT  42.444 23.819 51.102 23.891 ;
     RECT  55.872 23.819 56.754 23.891 ;
     RECT  5.58 22.811 11.394 23.935 ;
     RECT  12.168 23.819 41.634 23.935 ;
     RECT  42.48 23.891 51.102 23.963 ;
     RECT  2.628 23.891 4.842 23.971 ;
     RECT  5.58 23.935 41.634 23.971 ;
     RECT  57.636 23.693 63.342 23.971 ;
     RECT  0.255 23.891 1.782 24.161 ;
     RECT  50.724 23.963 51.102 24.205 ;
     RECT  50.724 24.205 51.282 24.461 ;
     RECT  51.264 24.461 51.282 24.601 ;
     RECT  52.308 23.741 55.062 24.601 ;
     RECT  2.628 23.971 41.634 24.629 ;
     RECT  51.264 24.601 55.062 24.629 ;
     RECT  25.02 24.629 41.634 24.637 ;
     RECT  42.48 23.963 49.878 24.637 ;
     RECT  2.628 24.629 24.138 24.773 ;
     RECT  14.832 24.773 24.138 24.899 ;
     RECT  51.66 24.629 55.062 24.935 ;
     RECT  14.832 24.899 24.03 25.043 ;
     RECT  52.164 24.935 55.062 25.051 ;
     RECT  55.944 23.891 56.754 25.051 ;
     RECT  52.164 25.051 56.754 25.141 ;
     RECT  57.636 23.971 63.81 25.141 ;
     RECT  52.164 25.141 63.81 25.277 ;
     RECT  0.255 24.161 1.71 25.321 ;
     RECT  2.628 24.773 11.574 25.321 ;
     RECT  52.668 25.277 63.81 25.349 ;
     RECT  25.02 24.637 49.878 25.511 ;
     RECT  42.228 25.511 49.878 25.583 ;
     RECT  0.255 25.321 11.574 25.591 ;
     RECT  12.348 24.773 13.842 25.591 ;
     RECT  52.884 25.349 63.81 25.709 ;
     RECT  0.255 25.591 13.842 25.753 ;
     RECT  14.832 25.043 15.318 25.753 ;
     RECT  0.255 25.753 15.318 25.825 ;
     RECT  16.128 25.043 24.03 25.825 ;
     RECT  25.02 25.511 41.49 25.825 ;
     RECT  0.255 25.825 24.03 25.979 ;
     RECT  1.692 25.979 24.03 26.015 ;
     RECT  50.724 25.951 50.742 26.095 ;
     RECT  48.384 25.583 49.878 26.131 ;
     RECT  50.652 26.095 50.742 26.131 ;
     RECT  55.908 25.709 63.81 26.131 ;
     RECT  2.736 26.015 24.03 26.159 ;
     RECT  0.255 25.979 0.918 26.249 ;
     RECT  1.692 26.015 1.71 26.249 ;
     RECT  48.384 26.131 51.138 26.249 ;
     RECT  55.908 26.131 63.846 26.249 ;
     RECT  50.976 26.249 51.138 26.257 ;
     RECT  51.876 25.951 51.894 26.257 ;
     RECT  2.736 26.159 13.914 26.393 ;
     RECT  24.912 25.825 41.49 26.401 ;
     RECT  42.228 25.583 47.646 26.401 ;
     RECT  2.736 26.393 8.478 26.429 ;
     RECT  3.312 26.429 8.478 26.519 ;
     RECT  14.832 26.159 24.03 26.555 ;
     RECT  50.976 26.257 51.894 26.599 ;
     RECT  52.884 25.709 54.702 26.599 ;
     RECT  55.908 26.249 63.81 26.599 ;
     RECT  24.912 26.401 47.646 26.699 ;
     RECT  50.976 26.599 63.81 26.699 ;
     RECT  33.984 26.699 47.646 26.789 ;
     RECT  50.976 26.699 58.122 26.789 ;
     RECT  14.976 26.555 24.03 26.861 ;
     RECT  24.912 26.699 33.246 26.861 ;
     RECT  15.084 26.861 18.09 26.933 ;
     RECT  24.912 26.861 32.937 26.941 ;
     RECT  47.016 26.789 47.646 26.941 ;
     RECT  48.384 26.249 50.13 26.941 ;
     RECT  43.344 26.789 45.99 27.059 ;
     RECT  47.016 26.941 50.13 27.059 ;
     RECT  52.668 26.789 58.122 27.059 ;
     RECT  52.668 27.059 57.978 27.095 ;
     RECT  9.396 26.393 13.914 27.103 ;
     RECT  9.396 27.103 14.238 27.139 ;
     RECT  33.984 26.789 42.57 27.239 ;
     RECT  9.324 27.139 14.238 27.329 ;
     RECT  52.668 27.095 54.738 27.329 ;
     RECT  18.828 26.861 24.03 27.337 ;
     RECT  24.876 26.941 32.937 27.337 ;
     RECT  15.228 26.933 18.09 27.365 ;
     RECT  50.976 26.789 51.93 27.409 ;
     RECT  9.324 27.329 14.13 27.481 ;
     RECT  50.688 27.409 51.93 27.509 ;
     RECT  18.828 27.337 32.937 27.599 ;
     RECT  3.312 26.519 8.118 27.635 ;
     RECT  52.668 27.329 54.702 27.635 ;
     RECT  58.86 26.699 63.702 27.715 ;
     RECT  18.828 27.599 20.322 27.779 ;
     RECT  3.312 27.635 6.606 27.835 ;
     RECT  50.724 27.509 51.93 27.841 ;
     RECT  52.668 27.635 54.537 27.841 ;
     RECT  9.252 27.481 14.13 27.869 ;
     RECT  18.828 27.779 19.926 27.869 ;
     RECT  3.276 27.835 6.606 27.905 ;
     RECT  7.38 27.635 8.118 27.905 ;
     RECT  45.216 27.059 45.99 27.913 ;
     RECT  4.932 27.905 6.606 27.941 ;
     RECT  58.86 27.715 63.81 27.941 ;
     RECT  31.5 27.599 32.937 27.949 ;
     RECT  58.86 27.941 63.702 27.949 ;
     RECT  45.216 27.913 46.17 27.985 ;
     RECT  58.716 27.949 63.702 28.013 ;
     RECT  45.036 27.985 46.17 28.027 ;
     RECT  47.016 27.059 49.878 28.027 ;
     RECT  58.716 28.013 63.486 28.049 ;
     RECT  43.344 27.059 44.226 28.139 ;
     RECT  45.036 28.027 49.878 28.139 ;
     RECT  15.228 27.365 16.866 28.147 ;
     RECT  34.092 27.239 42.57 28.219 ;
     RECT  31.5 27.949 32.994 28.255 ;
     RECT  33.768 28.219 42.57 28.255 ;
     RECT  10.044 27.869 14.13 28.283 ;
     RECT  13.392 28.283 14.13 28.291 ;
     RECT  15.192 28.147 16.866 28.291 ;
     RECT  47.016 28.139 49.878 28.291 ;
     RECT  50.724 27.841 54.537 28.291 ;
     RECT  13.392 28.291 16.866 28.381 ;
     RECT  21.132 27.599 30.762 28.381 ;
     RECT  31.5 28.255 42.57 28.381 ;
     RECT  58.716 28.049 62.766 28.445 ;
     RECT  45.036 28.139 46.134 28.481 ;
     RECT  17.64 27.365 18.09 28.489 ;
     RECT  18.828 27.869 19.854 28.489 ;
     RECT  55.692 27.095 57.978 28.489 ;
     RECT  58.716 28.445 62.622 28.489 ;
     RECT  55.692 28.489 62.622 28.561 ;
     RECT  13.392 28.381 16.902 28.679 ;
     RECT  55.62 28.561 62.622 28.723 ;
     RECT  55.332 28.723 62.622 28.751 ;
     RECT  55.332 28.751 62.442 28.829 ;
     RECT  7.812 27.905 8.118 28.831 ;
     RECT  14.796 28.679 16.902 28.831 ;
     RECT  17.64 28.489 19.854 28.831 ;
     RECT  21.132 28.381 42.57 28.831 ;
     RECT  7.812 28.831 8.514 28.921 ;
     RECT  47.016 28.291 54.537 28.921 ;
     RECT  55.332 28.829 61.542 28.921 ;
     RECT  14.796 28.831 19.854 28.949 ;
     RECT  3.312 27.905 4.122 28.957 ;
     RECT  7.812 28.921 8.586 28.957 ;
     RECT  47.016 28.921 61.542 28.985 ;
     RECT  3.276 28.957 4.122 28.987 ;
     RECT  4.932 27.941 6.534 28.987 ;
     RECT  7.488 28.957 8.586 28.987 ;
     RECT  4.932 28.987 8.586 28.993 ;
     RECT  14.796 28.949 14.85 29.021 ;
     RECT  20.916 28.831 42.57 29.021 ;
     RECT  4.932 28.993 8.622 29.065 ;
     RECT  17.64 28.949 19.854 29.065 ;
     RECT  34.02 29.021 42.57 29.065 ;
     RECT  43.38 28.139 44.226 29.065 ;
     RECT  2.592 28.987 4.122 29.101 ;
     RECT  4.932 29.065 8.73 29.101 ;
     RECT  56.268 28.985 61.542 29.129 ;
     RECT  45.036 28.481 46.026 29.191 ;
     RECT  45 29.191 46.026 29.227 ;
     RECT  17.64 29.065 19.89 29.263 ;
     RECT  20.916 29.021 31.878 29.263 ;
     RECT  34.02 29.065 44.226 29.299 ;
     RECT  45 29.227 46.206 29.299 ;
     RECT  47.016 28.985 55.53 29.299 ;
     RECT  34.02 29.299 46.206 29.363 ;
     RECT  10.044 28.283 12.582 29.371 ;
     RECT  13.392 28.679 13.914 29.371 ;
     RECT  39.888 29.363 46.206 29.371 ;
     RECT  46.944 29.299 55.53 29.371 ;
     RECT  39.888 29.371 55.53 29.489 ;
     RECT  17.64 29.263 31.878 29.501 ;
     RECT  39.888 29.489 49.59 29.525 ;
     RECT  17.64 29.501 18.846 29.549 ;
     RECT  46.8 29.525 49.59 29.549 ;
     RECT  19.584 29.501 31.878 29.561 ;
     RECT  56.448 29.129 61.542 29.597 ;
     RECT  2.592 29.101 8.73 29.605 ;
     RECT  56.448 29.597 61.146 29.669 ;
     RECT  10.044 29.371 13.914 29.731 ;
     RECT  9.612 29.731 13.914 29.759 ;
     RECT  34.02 29.363 38.97 29.759 ;
     RECT  56.448 29.669 60.858 29.759 ;
     RECT  2.412 29.605 8.73 29.767 ;
     RECT  9.612 29.759 12.438 29.789 ;
     RECT  2.412 29.767 8.874 29.795 ;
     RECT  19.584 29.561 19.602 29.795 ;
     RECT  47.124 29.549 49.59 29.795 ;
     RECT  56.448 29.759 57.114 29.795 ;
     RECT  50.472 29.489 55.53 29.831 ;
     RECT  34.128 29.759 38.97 29.837 ;
     RECT  20.484 29.561 31.878 29.839 ;
     RECT  32.655 29.021 33.03 29.839 ;
     RECT  56.448 29.795 57.006 29.867 ;
     RECT  13.176 29.759 13.914 29.875 ;
     RECT  14.832 29.021 14.85 29.875 ;
     RECT  56.448 29.867 56.97 29.875 ;
     RECT  2.412 29.795 6.822 29.903 ;
     RECT  48.384 29.795 49.59 29.903 ;
     RECT  7.812 29.795 8.874 29.911 ;
     RECT  17.64 29.549 18.738 29.911 ;
     RECT  20.484 29.839 33.03 29.911 ;
     RECT  34.128 29.837 35.298 29.939 ;
     RECT  13.176 29.875 14.85 29.981 ;
     RECT  50.508 29.831 55.53 30.001 ;
     RECT  4.932 29.903 6.822 30.029 ;
     RECT  57.96 29.759 60.858 30.029 ;
     RECT  57.96 30.029 58.05 30.065 ;
     RECT  15.696 28.949 16.794 30.073 ;
     RECT  17.568 29.911 18.738 30.073 ;
     RECT  20.484 29.911 33.066 30.101 ;
     RECT  39.888 29.525 41.346 30.101 ;
     RECT  20.484 30.101 33.03 30.137 ;
     RECT  15.696 30.073 18.738 30.145 ;
     RECT  36.036 29.837 38.97 30.145 ;
     RECT  39.888 30.101 41.274 30.145 ;
     RECT  50.508 30.001 55.602 30.181 ;
     RECT  56.34 29.875 56.97 30.181 ;
     RECT  20.484 30.137 32.937 30.299 ;
     RECT  50.508 30.181 56.97 30.299 ;
     RECT  34.128 29.939 35.262 30.335 ;
     RECT  13.392 29.981 14.85 30.379 ;
     RECT  15.624 30.145 18.738 30.379 ;
     RECT  20.484 30.299 24.102 30.415 ;
     RECT  13.392 30.379 18.738 30.569 ;
     RECT  50.508 30.299 56.898 30.569 ;
     RECT  34.128 30.335 35.226 30.571 ;
     RECT  7.812 29.911 8.982 30.577 ;
     RECT  15.696 30.569 18.738 30.577 ;
     RECT  20.304 30.415 24.102 30.577 ;
     RECT  42.696 29.525 46.026 30.577 ;
     RECT  47.124 29.795 47.142 30.577 ;
     RECT  15.696 30.577 18.882 30.613 ;
     RECT  19.836 30.577 24.102 30.613 ;
     RECT  36.036 30.145 41.274 30.641 ;
     RECT  36.324 30.641 41.274 30.749 ;
     RECT  4.932 30.029 6.534 30.811 ;
     RECT  48.384 29.903 49.482 30.811 ;
     RECT  50.508 30.569 51.426 30.811 ;
     RECT  57.96 30.065 57.978 30.811 ;
     RECT  57.96 30.811 58.05 30.839 ;
     RECT  13.392 30.569 14.85 30.845 ;
     RECT  2.412 29.903 4.122 30.847 ;
     RECT  4.896 30.811 6.534 30.859 ;
     RECT  7.416 30.577 8.982 30.859 ;
     RECT  39.816 30.749 41.274 30.875 ;
     RECT  52.632 30.569 56.538 30.875 ;
     RECT  48.384 30.811 51.426 30.907 ;
     RECT  52.776 30.875 54.81 30.911 ;
     RECT  2.16 30.847 4.122 30.949 ;
     RECT  2.088 30.949 4.122 30.955 ;
     RECT  4.896 30.859 8.982 30.955 ;
     RECT  42.696 30.577 47.142 30.955 ;
     RECT  47.916 30.907 51.426 30.955 ;
     RECT  24.984 30.299 32.937 30.983 ;
     RECT  33.948 30.571 35.226 30.983 ;
     RECT  39.888 30.875 41.274 30.983 ;
     RECT  13.392 30.845 14.814 30.991 ;
     RECT  41.22 30.983 41.274 30.991 ;
     RECT  24.984 30.983 31.77 31.019 ;
     RECT  32.508 30.983 32.937 31.081 ;
     RECT  15.696 30.613 24.102 31.099 ;
     RECT  24.984 31.019 31.662 31.099 ;
     RECT  13.32 30.991 14.814 31.109 ;
     RECT  15.696 31.099 31.662 31.109 ;
     RECT  36.324 30.749 38.79 31.109 ;
     RECT  39.888 30.983 40.158 31.109 ;
     RECT  41.22 30.991 41.31 31.109 ;
     RECT  42.372 30.955 51.426 31.109 ;
     RECT  52.776 30.911 54.537 31.109 ;
     RECT  15.696 31.109 26.082 31.145 ;
     RECT  52.776 31.109 53.118 31.145 ;
     RECT  53.892 31.109 54.537 31.145 ;
     RECT  32.508 31.081 32.994 31.181 ;
     RECT  46.188 31.109 46.35 31.181 ;
     RECT  47.088 31.109 47.142 31.181 ;
     RECT  54 31.145 54.537 31.181 ;
     RECT  2.088 30.955 9.09 31.189 ;
     RECT  26.856 31.109 31.662 31.217 ;
     RECT  47.952 31.109 51.426 31.229 ;
     RECT  61.596 31.225 61.614 31.243 ;
     RECT  62.388 28.829 62.406 31.243 ;
     RECT  15.696 31.145 25.758 31.253 ;
     RECT  39.888 31.109 39.906 31.253 ;
     RECT  42.372 31.109 45.162 31.253 ;
     RECT  46.188 31.181 46.206 31.253 ;
     RECT  2.016 31.189 9.09 31.261 ;
     RECT  10.044 29.789 12.438 31.261 ;
     RECT  13.32 31.109 14.778 31.261 ;
     RECT  61.596 31.243 62.406 31.261 ;
     RECT  15.696 31.253 20.394 31.289 ;
     RECT  26.856 31.217 31.194 31.289 ;
     RECT  42.372 31.253 44.802 31.289 ;
     RECT  47.124 31.181 47.142 31.289 ;
     RECT  20.16 31.289 20.394 31.325 ;
     RECT  1.98 31.261 9.09 31.379 ;
     RECT  21.24 31.253 25.758 31.379 ;
     RECT  26.856 31.289 27.594 31.379 ;
     RECT  28.908 31.289 30.978 31.379 ;
     RECT  48.384 31.229 51.426 31.379 ;
     RECT  0.255 26.249 0.537 31.381 ;
     RECT  61.596 31.261 62.622 31.387 ;
     RECT  21.24 31.379 25.686 31.415 ;
     RECT  26.856 31.379 27.537 31.415 ;
     RECT  29.088 31.379 30.978 31.415 ;
     RECT  0.255 31.381 1.026 31.421 ;
     RECT  58.788 30.029 60.858 31.423 ;
     RECT  61.596 31.387 63.306 31.423 ;
     RECT  20.376 31.325 20.394 31.451 ;
     RECT  15.696 31.289 18.918 31.459 ;
     RECT  4.932 31.379 9.09 31.469 ;
     RECT  48.384 31.379 49.986 31.487 ;
     RECT  36.324 31.109 37.314 31.495 ;
     RECT  1.98 31.379 4.194 31.523 ;
     RECT  10.044 31.261 14.778 31.523 ;
     RECT  55.548 30.875 56.538 31.523 ;
     RECT  7.812 31.469 9.09 31.531 ;
     RECT  29.088 31.415 29.106 31.565 ;
     RECT  4.932 31.469 6.93 31.649 ;
     RECT  21.24 31.415 25.65 31.649 ;
     RECT  48.384 31.487 49.23 31.649 ;
     RECT  49.968 31.487 49.986 31.649 ;
     RECT  50.76 31.379 51.426 31.649 ;
     RECT  36.216 31.495 37.314 31.657 ;
     RECT  51.3 31.649 51.426 31.657 ;
     RECT  58.788 31.423 63.306 31.657 ;
     RECT  34.776 30.983 35.226 31.675 ;
     RECT  35.964 31.657 37.314 31.675 ;
     RECT  21.672 31.649 24.606 31.685 ;
     RECT  58.788 31.657 63.378 31.693 ;
     RECT  51.3 31.657 51.678 31.721 ;
     RECT  34.776 31.675 37.314 31.729 ;
     RECT  41.292 31.109 41.31 31.765 ;
     RECT  42.084 31.729 42.102 31.765 ;
     RECT  4.932 31.649 6.858 31.793 ;
     RECT  51.66 31.721 51.678 31.801 ;
     RECT  52.776 31.145 52.794 31.801 ;
     RECT  55.656 31.523 56.538 31.801 ;
     RECT  58.788 31.693 63.594 31.805 ;
     RECT  30.168 31.415 30.798 31.829 ;
     RECT  32.508 31.181 32.937 31.891 ;
     RECT  34.308 31.729 37.314 31.891 ;
     RECT  38.055 31.109 38.79 31.891 ;
     RECT  41.292 31.765 42.102 31.891 ;
     RECT  55.656 31.801 57.006 31.891 ;
     RECT  21.672 31.685 22.77 31.919 ;
     RECT  48.384 31.649 49.194 31.919 ;
     RECT  21.855 31.919 22.626 31.955 ;
     RECT  51.66 31.801 52.794 31.955 ;
     RECT  43.38 31.289 44.802 31.999 ;
     RECT  55.656 31.891 57.15 31.999 ;
     RECT  58.032 30.839 58.05 31.999 ;
     RECT  32.04 31.891 32.937 32.011 ;
     RECT  40.896 31.891 42.102 32.035 ;
     RECT  43.38 31.999 44.91 32.035 ;
     RECT  31.68 32.011 32.937 32.063 ;
     RECT  10.08 31.523 14.778 32.071 ;
     RECT  15.588 31.459 18.918 32.071 ;
     RECT  31.86 32.063 32.937 32.071 ;
     RECT  55.656 31.999 58.05 32.071 ;
     RECT  10.08 32.071 18.918 32.155 ;
     RECT  40.752 32.035 42.102 32.155 ;
     RECT  43.02 32.035 44.91 32.155 ;
     RECT  31.86 32.071 32.994 32.161 ;
     RECT  34.308 31.891 38.79 32.197 ;
     RECT  40.752 32.155 44.91 32.197 ;
     RECT  46.116 32.035 46.746 32.197 ;
     RECT  54.255 31.181 54.537 32.197 ;
     RECT  23.616 31.685 24.606 32.225 ;
     RECT  55.656 32.071 58.086 32.225 ;
     RECT  10.08 32.155 19.062 32.233 ;
     RECT  19.836 32.197 19.854 32.233 ;
     RECT  31.86 32.161 33.318 32.233 ;
     RECT  34.164 32.197 38.79 32.233 ;
     RECT  31.86 32.233 38.79 32.297 ;
     RECT  58.86 31.805 63.594 32.297 ;
     RECT  40.752 32.197 46.746 32.305 ;
     RECT  10.08 32.233 19.854 32.341 ;
     RECT  30.168 31.829 30.186 32.341 ;
     RECT  37.584 32.297 38.79 32.341 ;
     RECT  40.752 32.305 47.178 32.341 ;
     RECT  51.876 31.955 52.794 32.341 ;
     RECT  53.676 32.197 54.537 32.341 ;
     RECT  23.796 32.225 24.606 32.369 ;
     RECT  25.452 31.649 25.65 32.431 ;
     RECT  27.255 31.415 27.537 32.431 ;
     RECT  28.836 32.341 28.854 32.431 ;
     RECT  51.876 32.341 54.537 32.431 ;
     RECT  55.656 32.225 58.05 32.431 ;
     RECT  25.452 32.431 25.758 32.459 ;
     RECT  31.86 32.297 36.522 32.459 ;
     RECT  40.752 32.341 47.358 32.459 ;
     RECT  39.636 32.341 39.654 32.467 ;
     RECT  42.768 32.459 47.358 32.495 ;
     RECT  0.255 31.421 0.537 32.503 ;
     RECT  31.86 32.459 34.65 32.531 ;
     RECT  26.856 32.431 27.537 32.539 ;
     RECT  28.584 32.431 28.854 32.539 ;
     RECT  29.7 32.341 30.186 32.539 ;
     RECT  37.584 32.341 38.826 32.539 ;
     RECT  39.6 32.467 39.654 32.539 ;
     RECT  48.636 31.919 49.194 32.539 ;
     RECT  50.292 32.431 50.31 32.539 ;
     RECT  35.496 32.459 36.522 32.567 ;
     RECT  25.596 32.459 25.758 32.575 ;
     RECT  26.532 32.539 27.537 32.575 ;
     RECT  28.584 32.539 30.186 32.575 ;
     RECT  51.876 32.431 58.05 32.603 ;
     RECT  0.255 32.503 1.17 32.611 ;
     RECT  2.412 31.523 4.194 32.611 ;
     RECT  7.812 31.531 9.234 32.611 ;
     RECT  9.972 32.341 20.322 32.611 ;
     RECT  37.584 32.539 39.654 32.611 ;
     RECT  40.752 32.459 41.994 32.611 ;
     RECT  25.596 32.575 27.537 32.639 ;
     RECT  28.44 32.575 30.186 32.701 ;
     RECT  25.632 32.639 27.537 32.729 ;
     RECT  28.44 32.701 30.222 32.729 ;
     RECT  51.876 32.603 51.894 32.729 ;
     RECT  0.255 32.611 4.194 32.731 ;
     RECT  4.932 31.793 6.822 32.731 ;
     RECT  48.636 32.539 50.31 32.737 ;
     RECT  31.86 32.531 34.578 32.765 ;
     RECT  52.668 32.603 58.05 32.765 ;
     RECT  34.56 32.765 34.578 32.771 ;
     RECT  21.855 31.955 22.137 32.773 ;
     RECT  53.496 32.765 58.05 32.801 ;
     RECT  21.456 32.773 22.137 32.809 ;
     RECT  31.86 32.765 33.462 32.845 ;
     RECT  46.584 32.495 47.358 32.845 ;
     RECT  48.132 32.737 50.31 32.845 ;
     RECT  56.124 32.801 58.05 32.873 ;
     RECT  7.812 32.611 20.322 32.881 ;
     RECT  21.132 32.809 22.137 32.881 ;
     RECT  58.86 32.297 63.45 32.881 ;
     RECT  30.996 32.611 31.014 32.971 ;
     RECT  31.788 32.845 33.462 32.971 ;
     RECT  25.632 32.729 25.758 32.999 ;
     RECT  56.268 32.873 58.05 33.007 ;
     RECT  58.824 32.881 63.45 33.007 ;
     RECT  56.268 33.007 63.45 33.053 ;
     RECT  0.255 32.731 6.822 33.067 ;
     RECT  7.812 32.881 22.446 33.067 ;
     RECT  37.584 32.611 41.994 33.071 ;
     RECT  53.496 32.801 55.026 33.071 ;
     RECT  35.892 32.567 36.522 33.079 ;
     RECT  37.584 33.071 41.454 33.079 ;
     RECT  54.036 33.071 55.026 33.107 ;
     RECT  29.916 32.729 30.222 33.109 ;
     RECT  30.996 32.971 33.462 33.109 ;
     RECT  0.255 33.067 22.446 33.143 ;
     RECT  23.796 32.369 24.534 33.151 ;
     RECT  26.496 32.729 27.537 33.151 ;
     RECT  28.44 32.729 29.178 33.151 ;
     RECT  35.892 33.079 41.454 33.179 ;
     RECT  51.336 32.773 51.858 33.179 ;
     RECT  0.255 33.143 1.926 33.269 ;
     RECT  2.988 33.143 22.446 33.269 ;
     RECT  25.74 32.999 25.758 33.269 ;
     RECT  26.496 33.151 29.178 33.269 ;
     RECT  42.768 32.495 45.738 33.277 ;
     RECT  51.336 33.179 51.714 33.277 ;
     RECT  58.824 33.053 63.45 33.277 ;
     RECT  15.84 33.269 22.446 33.305 ;
     RECT  46.584 32.845 50.31 33.307 ;
     RECT  2.988 33.269 14.994 33.341 ;
     RECT  15.912 33.305 22.446 33.341 ;
     RECT  15.948 33.341 22.446 33.349 ;
     RECT  23.58 33.151 24.534 33.349 ;
     RECT  42.372 33.277 45.738 33.349 ;
     RECT  46.548 33.307 50.31 33.349 ;
     RECT  4.032 33.341 14.994 33.413 ;
     RECT  15.948 33.349 24.534 33.413 ;
     RECT  42.372 33.349 50.31 33.421 ;
     RECT  51.156 33.277 51.714 33.421 ;
     RECT  15.948 33.413 23.598 33.449 ;
     RECT  24.516 33.413 24.534 33.511 ;
     RECT  15.984 33.449 23.598 33.539 ;
     RECT  24.516 33.511 24.822 33.611 ;
     RECT  29.916 33.109 33.462 33.619 ;
     RECT  34.704 33.277 34.794 33.619 ;
     RECT  35.892 33.179 41.058 33.619 ;
     RECT  35.82 33.619 41.058 33.629 ;
     RECT  58.824 33.277 63.666 33.629 ;
     RECT  28.764 33.269 29.178 33.643 ;
     RECT  29.916 33.619 34.794 33.643 ;
     RECT  15.984 33.539 22.986 33.647 ;
     RECT  35.82 33.629 36.954 33.677 ;
     RECT  26.496 33.269 27.99 33.691 ;
     RECT  28.764 33.643 34.794 33.691 ;
     RECT  35.82 33.677 36.846 33.691 ;
     RECT  28.764 33.691 36.846 33.809 ;
     RECT  42.372 33.421 51.714 33.883 ;
     RECT  56.268 33.053 58.05 33.883 ;
     RECT  58.824 33.629 63.594 33.883 ;
     RECT  54.144 33.107 54.846 33.925 ;
     RECT  37.764 33.629 41.058 33.961 ;
     RECT  41.976 33.883 51.714 33.961 ;
     RECT  26.388 33.691 27.99 34.051 ;
     RECT  28.764 33.809 36.414 34.051 ;
     RECT  37.764 33.961 51.714 34.087 ;
     RECT  15.984 33.647 22.95 34.115 ;
     RECT  25.632 34.051 25.65 34.123 ;
     RECT  26.388 34.051 36.414 34.123 ;
     RECT  22.896 34.115 22.95 34.187 ;
     RECT  25.632 34.123 36.414 34.187 ;
     RECT  0.255 33.269 1.818 34.231 ;
     RECT  37.764 34.087 51.822 34.231 ;
     RECT  54.144 33.925 54.99 34.231 ;
     RECT  53.64 34.231 54.99 34.321 ;
     RECT  56.268 33.883 63.594 34.321 ;
     RECT  2.988 33.341 3.258 34.357 ;
     RECT  4.104 33.413 14.994 34.357 ;
     RECT  24.804 33.611 24.822 34.385 ;
     RECT  2.988 34.357 14.994 34.393 ;
     RECT  0.255 34.231 2.034 34.429 ;
     RECT  2.988 34.393 15.102 34.493 ;
     RECT  0.255 34.429 2.25 34.501 ;
     RECT  2.988 34.493 13.77 34.501 ;
     RECT  14.544 34.493 15.102 34.501 ;
     RECT  15.984 34.115 22.137 34.501 ;
     RECT  53.64 34.321 63.594 34.501 ;
     RECT  14.544 34.501 22.137 34.619 ;
     RECT  53.496 34.501 63.594 34.619 ;
     RECT  21.348 34.619 22.137 34.655 ;
     RECT  37.764 34.231 52.578 34.691 ;
     RECT  23.94 34.501 23.958 34.699 ;
     RECT  0.255 34.501 13.77 34.727 ;
     RECT  14.544 34.619 20.538 34.733 ;
     RECT  41.688 34.691 52.578 34.735 ;
     RECT  53.82 34.619 63.594 34.763 ;
     RECT  22.932 34.187 22.95 34.771 ;
     RECT  23.904 34.699 23.958 34.771 ;
     RECT  30.78 34.187 36.414 34.771 ;
     RECT  37.764 34.691 40.914 34.771 ;
     RECT  41.688 34.735 53.082 34.781 ;
     RECT  41.688 34.781 52.578 34.889 ;
     RECT  21.528 34.655 22.137 34.933 ;
     RECT  22.932 34.771 23.958 34.933 ;
     RECT  21.528 34.933 23.958 35.041 ;
     RECT  7.236 34.727 13.77 35.159 ;
     RECT  21.528 35.041 24.498 35.227 ;
     RECT  25.632 34.187 29.934 35.227 ;
     RECT  7.236 35.159 7.29 35.357 ;
     RECT  41.904 34.889 52.578 35.581 ;
     RECT  8.1 35.159 13.77 35.671 ;
     RECT  14.544 34.733 20.502 35.671 ;
     RECT  21.528 35.227 29.934 35.671 ;
     RECT  8.1 35.671 20.502 35.815 ;
     RECT  8.1 35.815 20.754 35.851 ;
     RECT  21.528 35.671 30.006 35.851 ;
     RECT  54.255 34.763 63.594 35.851 ;
     RECT  41.904 35.581 52.902 35.879 ;
     RECT  30.78 34.771 40.914 35.941 ;
     RECT  54.255 35.851 63.666 35.969 ;
     RECT  50.364 35.879 52.902 35.977 ;
     RECT  0.255 34.727 6.498 36.013 ;
     RECT  7.236 35.357 7.254 36.013 ;
     RECT  8.1 35.851 30.006 36.013 ;
     RECT  30.78 35.941 41.058 36.013 ;
     RECT  41.904 35.879 49.374 36.013 ;
     RECT  50.364 35.977 53.37 36.085 ;
     RECT  54.255 35.969 63.234 36.085 ;
     RECT  0.255 36.013 7.254 36.239 ;
     RECT  8.1 36.013 49.374 36.347 ;
     RECT  8.1 36.347 29.898 36.481 ;
     RECT  8.064 36.481 29.898 36.509 ;
     RECT  30.636 36.347 49.374 36.779 ;
     RECT  8.064 36.509 29.574 36.887 ;
     RECT  7.236 36.239 7.254 36.895 ;
     RECT  8.064 36.887 25.722 36.895 ;
     RECT  7.236 36.895 25.722 37.049 ;
     RECT  0.255 36.239 6.498 37.051 ;
     RECT  7.236 37.049 14.202 37.051 ;
     RECT  50.364 36.085 63.234 37.057 ;
     RECT  41.904 36.779 49.374 37.093 ;
     RECT  50.292 37.057 63.234 37.093 ;
     RECT  15.048 37.049 20.286 37.121 ;
     RECT  41.904 37.093 63.234 37.201 ;
     RECT  41.904 37.201 63.522 37.229 ;
     RECT  41.904 37.229 56.322 37.319 ;
     RECT  30.636 36.779 41.094 37.579 ;
     RECT  26.496 36.887 29.574 37.627 ;
     RECT  30.492 37.579 41.094 37.627 ;
     RECT  15.048 37.121 20.142 37.733 ;
     RECT  41.904 37.319 49.374 37.741 ;
     RECT  26.496 37.627 41.094 37.831 ;
     RECT  41.868 37.741 49.374 37.831 ;
     RECT  0.255 37.051 14.202 37.903 ;
     RECT  15.048 37.733 16.737 37.939 ;
     RECT  21.06 37.049 25.722 37.939 ;
     RECT  26.496 37.831 49.374 37.939 ;
     RECT  17.532 37.733 20.142 37.975 ;
     RECT  21.06 37.939 49.374 37.975 ;
     RECT  0.255 37.903 14.274 38.003 ;
     RECT  17.532 37.975 49.374 38.003 ;
     RECT  50.184 37.319 56.322 38.011 ;
     RECT  57.06 37.229 63.522 38.011 ;
     RECT  17.532 38.003 33.966 38.129 ;
     RECT  34.704 38.003 49.374 38.137 ;
     RECT  50.184 38.011 63.522 38.137 ;
     RECT  17.532 38.129 20.502 38.201 ;
     RECT  21.312 38.129 33.966 38.201 ;
     RECT  21.492 38.201 33.966 38.309 ;
     RECT  20.484 38.201 20.502 38.399 ;
     RECT  34.704 38.137 63.522 38.399 ;
     RECT  50.148 38.399 56.466 38.543 ;
     RECT  15.012 37.939 16.737 38.668 ;
     RECT  14.976 38.668 16.737 38.717 ;
     RECT  0.255 38.003 2.322 38.749 ;
     RECT  3.096 38.003 14.202 38.749 ;
     RECT  57.384 38.399 63.522 38.821 ;
     RECT  0.255 38.749 14.202 39.083 ;
     RECT  57.384 38.821 63.738 39.209 ;
     RECT  5.148 39.083 14.202 39.245 ;
     RECT  21.528 38.309 33.966 39.289 ;
     RECT  34.704 38.399 49.41 39.289 ;
     RECT  50.184 38.543 56.466 39.289 ;
     RECT  21.528 39.289 49.41 39.317 ;
     RECT  5.655 39.245 14.202 39.361 ;
     RECT  17.532 38.201 19.602 39.479 ;
     RECT  5.655 39.361 14.238 39.523 ;
     RECT  15.048 38.717 16.737 39.523 ;
     RECT  50.184 39.289 56.574 39.631 ;
     RECT  57.384 39.209 63.594 39.631 ;
     RECT  21.528 39.317 28.602 39.721 ;
     RECT  50.184 39.631 63.594 39.721 ;
     RECT  21.42 39.721 28.602 39.829 ;
     RECT  29.412 39.317 49.41 39.829 ;
     RECT  50.148 39.721 63.594 39.829 ;
     RECT  21.06 39.829 28.602 39.865 ;
     RECT  0.255 39.083 4.374 39.901 ;
     RECT  0.255 39.901 4.626 39.991 ;
     RECT  20.52 39.865 28.602 40.019 ;
     RECT  0.255 39.991 4.806 40.063 ;
     RECT  5.655 39.523 17.082 40.063 ;
     RECT  21.06 40.019 28.602 40.127 ;
     RECT  17.82 39.479 19.602 40.135 ;
     RECT  0.255 40.063 17.082 40.163 ;
     RECT  21.06 40.127 26.118 40.163 ;
     RECT  17.82 40.135 20.25 40.289 ;
     RECT  17.82 40.289 18.81 40.361 ;
     RECT  19.584 40.289 20.25 40.445 ;
     RECT  27 40.127 28.602 40.639 ;
     RECT  10.368 40.163 17.082 40.711 ;
     RECT  17.82 40.361 18.666 40.711 ;
     RECT  27 40.639 28.674 40.711 ;
     RECT  29.412 39.829 63.594 40.711 ;
     RECT  27 40.711 63.594 40.739 ;
     RECT  21.24 40.163 26.118 40.981 ;
     RECT  21.168 40.981 26.118 41.131 ;
     RECT  27 40.739 54.537 41.131 ;
     RECT  21.168 41.131 54.537 41.215 ;
     RECT  10.368 40.711 18.666 41.251 ;
     RECT  19.584 40.445 19.602 41.251 ;
     RECT  55.26 40.739 63.594 41.369 ;
     RECT  19.584 41.251 19.854 41.377 ;
     RECT  20.628 41.215 54.537 41.377 ;
     RECT  0.255 40.163 9.594 41.513 ;
     RECT  58.032 41.369 63.594 41.521 ;
     RECT  58.032 41.521 63.81 41.639 ;
     RECT  19.584 41.377 54.537 41.675 ;
     RECT  1.296 41.513 9.594 41.693 ;
     RECT  4.104 41.693 9.594 41.719 ;
     RECT  10.368 41.251 18.81 41.719 ;
     RECT  1.296 41.693 3.294 41.909 ;
     RECT  64.584 41.791 64.602 41.909 ;
     RECT  4.104 41.719 18.81 42.017 ;
     RECT  58.032 41.639 63.666 42.089 ;
     RECT  58.032 42.089 63.486 42.151 ;
     RECT  19.584 41.675 19.854 42.179 ;
     RECT  20.664 41.675 54.537 42.179 ;
     RECT  55.26 41.369 57.078 42.223 ;
     RECT  57.924 42.151 63.486 42.223 ;
     RECT  19.584 42.179 19.602 42.259 ;
     RECT  50.184 42.179 54.537 42.287 ;
     RECT  50.22 42.287 54.537 42.295 ;
     RECT  55.26 42.223 63.486 42.295 ;
     RECT  20.664 42.179 49.446 42.565 ;
     RECT  4.104 42.017 18.558 42.593 ;
     RECT  50.22 42.295 63.486 42.629 ;
     RECT  50.22 42.629 55.782 42.701 ;
     RECT  19.332 42.259 19.602 42.755 ;
     RECT  56.628 42.629 63.486 42.755 ;
     RECT  4.104 42.593 8.37 42.763 ;
     RECT  9.18 42.593 18.558 42.799 ;
     RECT  19.332 42.755 19.53 42.799 ;
     RECT  20.448 42.565 49.446 42.899 ;
     RECT  9.18 42.799 19.53 42.989 ;
     RECT  50.22 42.701 54.537 43.033 ;
     RECT  56.628 42.755 63.414 43.061 ;
     RECT  0.255 41.513 0.537 43.105 ;
     RECT  1.296 41.909 2.538 43.105 ;
     RECT  9.18 42.989 18.666 43.133 ;
     RECT  19.404 42.989 19.53 43.259 ;
     RECT  0.255 43.105 2.538 43.267 ;
     RECT  20.484 42.899 49.446 43.267 ;
     RECT  50.184 43.033 54.537 43.267 ;
     RECT  19.404 43.259 19.422 43.295 ;
     RECT  0.255 43.267 2.574 43.303 ;
     RECT  9.18 43.133 18.63 43.411 ;
     RECT  20.484 43.267 54.537 43.439 ;
     RECT  20.484 43.439 46.098 43.529 ;
     RECT  0.255 43.303 2.97 43.537 ;
     RECT  3.78 42.763 8.37 43.537 ;
     RECT  46.944 43.439 54.537 43.601 ;
     RECT  0.255 43.537 8.37 43.673 ;
     RECT  20.52 43.529 46.098 43.673 ;
     RECT  55.26 42.701 55.782 43.681 ;
     RECT  0.255 43.673 1.386 43.799 ;
     RECT  2.16 43.673 8.37 43.799 ;
     RECT  46.944 43.601 53.334 43.799 ;
     RECT  46.944 43.799 53.19 43.805 ;
     RECT  0.255 43.799 1.242 43.835 ;
     RECT  2.52 43.799 8.37 43.835 ;
     RECT  9.144 43.411 18.63 43.853 ;
     RECT  2.952 43.835 8.37 43.871 ;
     RECT  55.26 43.681 55.854 43.879 ;
     RECT  56.664 43.061 63.414 43.879 ;
     RECT  55.26 43.879 63.414 43.951 ;
     RECT  54.255 43.601 54.537 44.041 ;
     RECT  55.26 43.951 63.594 44.041 ;
     RECT  54.255 44.041 63.594 44.069 ;
     RECT  46.944 43.805 53.154 44.105 ;
     RECT  46.944 44.105 49.662 44.177 ;
     RECT  43.344 43.673 46.098 44.185 ;
     RECT  46.944 44.177 49.302 44.185 ;
     RECT  9.18 43.853 18.63 44.221 ;
     RECT  20.52 43.673 42.57 44.347 ;
     RECT  50.472 44.105 53.154 44.447 ;
     RECT  20.232 44.347 42.57 44.455 ;
     RECT  43.344 44.185 49.302 44.455 ;
     RECT  54.255 44.069 55.674 44.491 ;
     RECT  9.18 44.221 18.882 44.609 ;
     RECT  3.996 43.871 8.37 44.689 ;
     RECT  9.18 44.609 12.906 44.689 ;
     RECT  13.644 44.609 18.882 44.753 ;
     RECT  2.952 43.871 2.97 44.761 ;
     RECT  15.768 44.753 18.882 44.789 ;
     RECT  3.996 44.689 12.906 44.915 ;
     RECT  2.952 44.761 3.222 44.951 ;
     RECT  2.16 44.887 2.178 44.959 ;
     RECT  2.952 44.951 3.114 44.959 ;
     RECT  2.16 44.959 3.114 44.971 ;
     RECT  54 44.491 55.674 44.995 ;
     RECT  1.548 44.971 3.114 45.023 ;
     RECT  20.232 44.455 49.302 45.031 ;
     RECT  50.472 44.447 53.118 45.157 ;
     RECT  53.964 44.995 55.674 45.229 ;
     RECT  2.16 45.023 3.114 45.257 ;
     RECT  56.448 44.069 63.45 45.265 ;
     RECT  50.4 45.157 53.118 45.301 ;
     RECT  53.856 45.229 55.674 45.355 ;
     RECT  56.412 45.265 63.666 45.355 ;
     RECT  2.304 45.257 3.114 45.419 ;
     RECT  50.292 45.301 53.118 45.499 ;
     RECT  53.856 45.355 63.666 45.499 ;
     RECT  4.104 44.915 12.906 45.535 ;
     RECT  13.644 44.753 14.418 45.535 ;
     RECT  4.104 45.535 14.418 45.571 ;
     RECT  17.568 44.789 18.882 45.571 ;
     RECT  2.304 45.419 3.006 45.581 ;
     RECT  50.292 45.499 63.666 45.599 ;
     RECT  4.104 45.571 14.67 45.661 ;
     RECT  17.568 45.571 18.954 45.661 ;
     RECT  4.104 45.661 14.958 45.691 ;
     RECT  17.568 45.661 19.278 45.691 ;
     RECT  15.768 44.789 16.737 45.697 ;
     RECT  17.532 45.691 19.278 45.697 ;
     RECT  4.068 45.691 14.958 45.733 ;
     RECT  15.768 45.697 19.278 45.733 ;
     RECT  20.232 45.031 49.374 45.733 ;
     RECT  2.556 45.581 3.006 45.761 ;
     RECT  3.96 45.733 14.958 45.769 ;
     RECT  15.768 45.733 49.374 45.769 ;
     RECT  56.448 45.599 63.666 45.769 ;
     RECT  3.96 45.769 49.374 45.821 ;
     RECT  3.96 45.821 17.586 45.841 ;
     RECT  2.556 45.761 2.826 45.869 ;
     RECT  3.852 45.841 17.586 45.869 ;
     RECT  56.448 45.769 63.81 45.869 ;
     RECT  3.852 45.869 9.486 45.959 ;
     RECT  56.448 45.869 63.378 45.959 ;
     RECT  2.556 45.869 2.574 46.031 ;
     RECT  3.852 45.959 7.614 46.171 ;
     RECT  18.504 45.821 49.374 46.171 ;
     RECT  3.78 46.171 7.614 46.229 ;
     RECT  10.296 45.869 17.586 46.229 ;
     RECT  18.504 46.171 49.41 46.253 ;
     RECT  10.296 46.229 14.526 46.265 ;
     RECT  12.492 46.265 14.526 46.301 ;
     RECT  12.492 46.301 14.49 46.397 ;
     RECT  4.752 46.229 7.578 46.499 ;
     RECT  10.296 46.265 11.646 46.499 ;
     RECT  4.752 46.499 6.138 46.571 ;
     RECT  20.7 46.253 49.41 46.643 ;
     RECT  15.408 46.229 17.586 46.651 ;
     RECT  8.352 45.959 9.486 46.741 ;
     RECT  50.292 45.599 55.674 46.741 ;
     RECT  56.7 45.959 63.378 46.741 ;
     RECT  50.256 46.741 55.674 46.777 ;
     RECT  56.7 46.741 63.45 46.777 ;
     RECT  20.808 46.643 49.41 46.813 ;
     RECT  50.256 46.777 63.45 46.813 ;
     RECT  8.352 46.741 9.558 46.885 ;
     RECT  10.296 46.499 11.394 46.885 ;
     RECT  15.408 46.651 17.658 46.921 ;
     RECT  18.504 46.253 19.926 46.921 ;
     RECT  20.808 46.813 63.45 47.119 ;
     RECT  20.808 47.119 63.486 47.183 ;
     RECT  15.408 46.921 19.926 47.191 ;
     RECT  12.564 46.397 14.49 47.281 ;
     RECT  15.408 47.191 20.07 47.281 ;
     RECT  55.944 47.183 63.486 47.309 ;
     RECT  7.164 46.499 7.578 47.317 ;
     RECT  8.352 46.885 11.394 47.317 ;
     RECT  12.564 47.281 20.07 47.323 ;
     RECT  7.164 47.317 11.394 47.353 ;
     RECT  12.168 47.323 20.07 47.353 ;
     RECT  57.276 47.309 63.486 47.381 ;
     RECT  4.752 46.571 5.937 47.389 ;
     RECT  7.164 47.353 20.07 47.461 ;
     RECT  20.808 47.183 54.774 47.461 ;
     RECT  57.276 47.381 63.414 47.579 ;
     RECT  4.752 47.389 6.426 47.587 ;
     RECT  7.164 47.461 54.774 47.615 ;
     RECT  57.276 47.579 61.11 47.687 ;
     RECT  60.912 47.687 61.11 47.759 ;
     RECT  39.852 47.615 54.774 47.849 ;
     RECT  57.276 47.687 60.174 47.849 ;
     RECT  60.912 47.759 61.074 47.849 ;
     RECT  61.848 47.579 63.414 47.849 ;
     RECT  60.912 47.849 60.966 47.885 ;
     RECT  7.164 47.615 39.114 47.957 ;
     RECT  4.644 47.587 6.426 47.965 ;
     RECT  7.164 47.957 13.986 47.965 ;
     RECT  4.644 47.965 13.986 48.119 ;
     RECT  57.564 47.849 60.174 48.119 ;
     RECT  61.848 47.849 62.946 48.119 ;
     RECT  4.752 48.119 13.986 48.155 ;
     RECT  14.832 47.957 39.114 48.155 ;
     RECT  57.564 48.119 60.102 48.191 ;
     RECT  55.944 47.309 56.358 48.361 ;
     RECT  4.752 48.155 8.046 48.389 ;
     RECT  8.82 48.155 13.986 48.389 ;
     RECT  4.752 48.389 7.866 48.461 ;
     RECT  9.036 48.389 13.986 48.461 ;
     RECT  55.62 48.361 56.358 48.505 ;
     RECT  39.924 47.849 54.774 48.541 ;
     RECT  55.62 48.505 56.79 48.541 ;
     RECT  57.564 48.191 60.03 48.569 ;
     RECT  4.752 48.461 7.326 48.659 ;
     RECT  57.564 48.569 59.937 48.695 ;
     RECT  61.848 48.119 62.55 48.731 ;
     RECT  9.036 48.461 13.914 48.767 ;
     RECT  60.948 47.885 60.966 48.767 ;
     RECT  61.848 48.731 62.442 48.811 ;
     RECT  61.776 48.811 62.442 48.839 ;
     RECT  9.036 48.767 12.15 48.929 ;
     RECT  12.924 48.767 13.914 48.929 ;
     RECT  39.924 48.541 56.79 48.929 ;
     RECT  57.6 48.695 59.937 48.929 ;
     RECT  61.776 48.839 62.37 48.929 ;
     RECT  10.404 48.929 12.006 48.941 ;
     RECT  10.404 48.941 11.337 48.965 ;
     RECT  39.924 48.929 56.466 48.965 ;
     RECT  61.848 48.929 61.866 48.965 ;
     RECT  57.6 48.929 57.726 48.989 ;
     RECT  39.924 48.965 55.674 49.009 ;
     RECT  15.408 48.155 39.114 49.045 ;
     RECT  39.888 49.009 55.674 49.045 ;
     RECT  12.96 48.929 13.914 49.109 ;
     RECT  12.96 49.109 13.122 49.199 ;
     RECT  13.896 49.109 13.914 49.199 ;
     RECT  15.408 49.045 55.674 49.271 ;
     RECT  19.08 49.271 55.674 49.379 ;
     RECT  15.408 49.271 18.342 49.469 ;
     RECT  15.408 49.469 18.198 49.541 ;
     RECT  12.96 49.199 13.086 49.577 ;
     RECT  57.6 48.989 57.618 49.621 ;
     RECT  9.036 48.929 9.522 49.649 ;
     RECT  14.256 49.549 14.274 49.747 ;
     RECT  56.448 48.965 56.466 49.819 ;
     RECT  57.24 49.621 57.618 49.819 ;
     RECT  9.108 49.649 9.522 49.891 ;
     RECT  14.256 49.747 14.598 49.891 ;
     RECT  15.408 49.541 17.73 49.891 ;
     RECT  7.236 48.659 7.254 49.981 ;
     RECT  9.108 49.891 9.558 49.981 ;
     RECT  4.752 48.659 5.937 50.009 ;
     RECT  14.256 49.891 17.73 50.009 ;
     RECT  9.108 49.981 10.242 50.089 ;
     RECT  11.055 48.965 11.337 50.089 ;
     RECT  9.108 50.089 11.337 50.117 ;
     RECT  9.396 50.117 11.337 50.125 ;
     RECT  19.08 49.379 55.242 50.125 ;
     RECT  55.98 49.819 57.618 50.125 ;
     RECT  6.84 49.981 7.254 50.153 ;
     RECT  9.396 50.125 11.43 50.279 ;
     RECT  15.3 50.009 17.73 50.431 ;
     RECT  10.224 50.279 11.337 50.459 ;
     RECT  9.396 50.279 9.45 50.477 ;
     RECT  15.3 50.431 18.054 50.549 ;
     RECT  19.08 50.125 57.618 50.549 ;
     RECT  19.08 50.549 56.826 50.657 ;
     RECT  13.068 49.577 13.086 50.791 ;
     RECT  50.472 50.657 56.826 50.819 ;
     RECT  12.312 50.017 12.33 50.821 ;
     RECT  13.068 50.791 13.194 50.821 ;
     RECT  12.312 50.821 13.194 50.827 ;
     RECT  14.364 50.009 14.526 50.827 ;
     RECT  15.3 50.549 17.73 50.827 ;
     RECT  14.364 50.827 17.73 50.863 ;
     RECT  12.312 50.827 13.266 50.971 ;
     RECT  12.204 50.971 13.374 51.019 ;
     RECT  9.432 50.477 9.45 51.115 ;
     RECT  9.432 51.115 9.738 51.161 ;
     RECT  19.08 50.657 49.518 51.205 ;
     RECT  7.236 50.153 7.254 51.233 ;
     RECT  19.044 51.205 49.518 51.233 ;
     RECT  56.592 50.819 56.826 51.233 ;
     RECT  10.512 50.459 11.337 51.241 ;
     RECT  19.044 51.233 22.137 51.241 ;
     RECT  12.204 51.019 13.41 51.307 ;
     RECT  14.148 50.863 17.73 51.307 ;
     RECT  57.6 50.549 57.618 51.307 ;
     RECT  18.9 51.241 22.137 51.511 ;
     RECT  22.932 51.233 49.518 51.511 ;
     RECT  50.472 50.819 55.854 51.511 ;
     RECT  12.204 51.307 17.73 51.629 ;
     RECT  57.06 51.307 57.618 51.629 ;
     RECT  12.204 51.629 13.23 51.701 ;
     RECT  18.864 51.511 22.137 51.745 ;
     RECT  10.512 51.241 11.394 51.781 ;
     RECT  12.204 51.701 13.086 51.781 ;
     RECT  9.432 51.161 9.666 51.871 ;
     RECT  14.004 51.629 17.73 51.871 ;
     RECT  18.648 51.745 22.137 51.871 ;
     RECT  9.396 51.871 9.666 51.917 ;
     RECT  5.112 50.009 5.937 51.935 ;
     RECT  57.6 51.629 57.618 51.971 ;
     RECT  14.004 51.871 22.137 51.979 ;
     RECT  22.932 51.511 55.854 51.979 ;
     RECT  9.54 51.917 9.666 52.051 ;
     RECT  10.512 51.781 13.086 52.051 ;
     RECT  9.54 52.051 13.086 52.169 ;
     RECT  14.004 51.979 56.142 52.169 ;
     RECT  9.612 52.169 9.666 52.241 ;
     RECT  9.648 52.241 9.666 52.313 ;
     RECT  10.836 52.169 13.086 52.439 ;
     RECT  23.076 52.169 56.142 52.445 ;
     RECT  57.096 52.591 57.114 52.709 ;
     RECT  28.476 52.445 56.142 52.717 ;
     RECT  12.312 52.439 13.086 52.861 ;
     RECT  14.004 52.169 22.137 52.861 ;
     RECT  28.476 52.717 56.79 53.015 ;
     RECT  12.312 52.861 22.137 53.059 ;
     RECT  23.076 52.445 27.738 53.059 ;
     RECT  12.312 53.059 27.738 53.249 ;
     RECT  19.692 53.249 27.738 53.329 ;
     RECT  28.476 53.015 56.394 53.329 ;
     RECT  19.692 53.329 56.394 53.393 ;
     RECT  12.312 53.249 14.922 53.519 ;
     RECT  23.292 53.393 56.394 53.519 ;
     RECT  12.312 53.519 13.158 53.555 ;
     RECT  23.292 53.519 27.738 53.789 ;
     RECT  23.292 53.789 27.537 54.167 ;
     RECT  28.476 53.519 55.746 54.301 ;
     RECT  15.732 53.249 18.918 54.337 ;
     RECT  19.692 53.393 22.518 54.337 ;
     RECT  56.808 54.301 56.826 54.445 ;
     RECT  14.22 53.519 14.922 54.481 ;
     RECT  15.732 54.337 22.518 54.481 ;
     RECT  28.476 54.301 56.034 54.481 ;
     RECT  12.312 53.555 13.086 54.571 ;
     RECT  56.808 54.445 57.258 54.599 ;
     RECT  28.476 54.481 56.07 54.667 ;
     RECT  56.808 54.599 56.826 54.667 ;
     RECT  28.476 54.667 56.826 54.707 ;
     RECT  56.808 54.707 56.826 54.743 ;
     RECT  12.312 54.571 13.266 54.751 ;
     RECT  14.22 54.481 22.806 54.751 ;
     RECT  28.476 54.707 55.998 54.752 ;
     RECT  12.312 54.751 22.806 54.869 ;
     RECT  12.528 54.869 22.806 55.013 ;
     RECT  13.968 55.013 22.806 55.021 ;
     RECT  13.968 55.021 22.842 55.139 ;
     RECT  12.528 55.013 13.122 55.175 ;
     RECT  14.004 55.139 14.922 55.175 ;
     RECT  12.78 55.175 12.87 55.211 ;
     RECT  12.852 55.211 12.87 55.247 ;
     RECT  15.768 55.139 22.842 55.291 ;
     RECT  23.976 54.167 27.537 55.291 ;
     RECT  14.004 55.175 14.562 55.409 ;
     RECT  23.976 55.291 27.702 55.435 ;
     RECT  28.476 54.752 55.638 55.435 ;
     RECT  23.976 55.435 55.638 55.489 ;
     RECT  15.768 55.291 22.878 55.561 ;
     RECT  23.688 55.489 55.638 55.561 ;
     RECT  15.768 55.561 55.638 55.589 ;
     RECT  20.088 55.589 55.638 55.751 ;
     RECT  23.688 55.751 55.638 55.853 ;
     RECT  15.768 55.589 19.314 55.949 ;
     RECT  20.088 55.751 22.374 55.949 ;
     RECT  54.255 55.853 55.638 55.949 ;
     RECT  55.764 55.957 55.782 55.993 ;
     RECT  54.255 55.949 54.954 56.057 ;
     RECT  55.764 55.993 55.89 56.101 ;
     RECT  23.688 55.853 53.478 56.129 ;
     RECT  15.768 55.949 18.45 56.219 ;
     RECT  23.688 56.129 36.306 56.255 ;
     RECT  55.764 56.101 56.25 56.255 ;
     RECT  54.255 56.057 54.774 56.327 ;
     RECT  56.232 56.255 56.25 56.327 ;
     RECT  17.64 56.219 18.45 56.399 ;
     RECT  37.152 56.129 53.478 56.489 ;
     RECT  20.088 55.949 22.137 56.561 ;
     RECT  37.188 56.489 53.478 56.641 ;
     RECT  54.255 56.327 54.537 56.641 ;
     RECT  37.188 56.641 54.537 56.759 ;
     RECT  34.704 56.255 36.306 56.831 ;
     RECT  31.104 56.255 33.75 57.001 ;
     RECT  34.704 56.831 36.162 57.001 ;
     RECT  41.76 56.759 54.537 57.029 ;
     RECT  17.784 56.399 18.45 57.037 ;
     RECT  19.296 55.949 19.314 57.037 ;
     RECT  20.088 56.561 20.25 57.037 ;
     RECT  21.096 56.561 22.137 57.037 ;
     RECT  23.688 56.255 30.366 57.037 ;
     RECT  31.104 57.001 36.162 57.037 ;
     RECT  21.096 57.037 22.914 57.073 ;
     RECT  23.688 57.037 36.162 57.073 ;
     RECT  50.436 57.029 54.537 57.181 ;
     RECT  21.096 57.073 36.162 57.407 ;
     RECT  17.784 57.037 20.25 57.415 ;
     RECT  21.096 57.407 22.137 57.415 ;
     RECT  50.436 57.181 54.666 57.415 ;
     RECT  50.436 57.415 55.17 57.451 ;
     RECT  17.784 57.415 22.137 57.569 ;
     RECT  50.436 57.451 55.53 57.569 ;
     RECT  17.784 57.569 20.538 57.592 ;
     RECT  50.436 57.569 55.17 57.605 ;
     RECT  22.968 57.407 36.162 57.613 ;
     RECT  37.188 56.759 41.022 57.613 ;
     RECT  50.436 57.605 54.738 57.641 ;
     RECT  22.968 57.613 41.022 57.713 ;
     RECT  41.76 57.029 49.626 57.839 ;
     RECT  18.936 57.592 20.538 57.875 ;
     RECT  28.404 57.713 41.022 57.911 ;
     RECT  19.26 57.875 20.538 57.983 ;
     RECT  42.228 57.839 49.626 58.081 ;
     RECT  50.436 57.641 54.537 58.081 ;
     RECT  29.916 57.911 41.022 58.189 ;
     RECT  29.916 58.189 41.13 58.289 ;
     RECT  21.42 57.569 22.137 58.531 ;
     RECT  22.968 57.713 27.666 58.531 ;
     RECT  28.404 57.911 29.07 58.531 ;
     RECT  42.228 58.081 54.537 58.531 ;
     RECT  20.52 57.983 20.538 58.657 ;
     RECT  21.42 58.531 29.07 58.657 ;
     RECT  19.296 57.983 19.314 58.999 ;
     RECT  20.52 58.657 29.07 59.035 ;
     RECT  29.916 58.289 40.95 59.035 ;
     RECT  42.228 58.531 54.63 59.071 ;
     RECT  20.52 59.035 40.95 59.161 ;
     RECT  20.484 59.161 40.95 59.197 ;
     RECT  41.976 59.071 54.63 59.197 ;
     RECT  20.484 59.197 54.63 59.225 ;
     RECT  29.088 59.225 54.63 59.233 ;
     RECT  18.9 58.999 19.314 59.305 ;
     RECT  20.484 59.225 28.206 59.305 ;
     RECT  29.088 59.233 54.702 59.305 ;
     RECT  20.124 59.305 28.206 59.333 ;
     RECT  29.088 59.305 55.278 59.459 ;
     RECT  17.784 57.592 17.802 59.467 ;
     RECT  18.864 59.305 19.314 59.467 ;
     RECT  17.784 59.467 19.314 59.495 ;
     RECT  29.088 59.459 54.702 59.495 ;
     RECT  18.288 59.495 19.314 59.539 ;
     RECT  20.124 59.333 27.918 59.539 ;
     RECT  18.288 59.539 27.918 59.567 ;
     RECT  29.268 59.495 40.95 59.567 ;
     RECT  42.228 59.495 54.702 59.603 ;
     RECT  29.268 59.567 40.77 59.729 ;
     RECT  29.268 59.729 30.942 59.765 ;
     RECT  30.168 59.765 30.942 59.789 ;
     RECT  30.528 59.789 30.942 59.801 ;
     RECT  15.768 56.219 16.737 59.837 ;
     RECT  18.288 59.567 23.022 59.837 ;
     RECT  14.472 55.409 14.562 59.909 ;
     RECT  14.544 59.909 14.562 59.999 ;
     RECT  19.836 59.837 23.022 59.999 ;
     RECT  23.832 59.567 27.918 59.999 ;
     RECT  42.228 59.603 54.537 59.999 ;
     RECT  23.832 59.999 26.406 60.035 ;
     RECT  30.924 59.801 30.942 60.035 ;
     RECT  21.42 59.999 23.022 60.269 ;
     RECT  27.216 59.999 27.918 60.269 ;
     RECT  32.112 59.729 40.77 60.269 ;
     RECT  42.228 59.999 53.442 60.269 ;
     RECT  42.228 60.269 51.678 60.277 ;
     RECT  42.192 60.277 51.678 60.305 ;
     RECT  52.452 60.269 53.442 60.305 ;
     RECT  23.904 60.035 26.406 60.341 ;
     RECT  52.596 60.305 53.442 60.341 ;
     RECT  35.568 60.269 40.77 60.385 ;
     RECT  35.568 60.385 41.094 60.539 ;
     RECT  53.1 60.341 53.442 60.539 ;
     RECT  29.268 59.765 29.286 60.691 ;
     RECT  32.112 60.269 34.758 60.691 ;
     RECT  42.192 60.305 51.498 60.691 ;
     RECT  23.904 60.341 25.218 60.808 ;
     RECT  41.796 60.691 51.498 60.809 ;
     RECT  27.255 60.269 27.918 60.817 ;
     RECT  29.268 60.691 29.358 60.817 ;
     RECT  19.836 59.999 20.574 60.925 ;
     RECT  21.42 60.269 22.842 60.925 ;
     RECT  27.255 60.817 29.358 60.961 ;
     RECT  31.176 60.925 31.194 61.051 ;
     RECT  32.076 60.691 34.758 61.051 ;
     RECT  35.568 60.539 41.022 61.051 ;
     RECT  19.836 60.925 22.842 61.087 ;
     RECT  23.616 60.808 25.218 61.087 ;
     RECT  30.924 61.051 41.022 61.099 ;
     RECT  45.216 60.809 51.066 61.115 ;
     RECT  27.255 60.961 29.538 61.123 ;
     RECT  30.42 61.099 41.022 61.123 ;
     RECT  19.836 61.087 25.218 61.159 ;
     RECT  26.388 60.341 26.406 61.159 ;
     RECT  19.836 61.159 26.406 61.349 ;
     RECT  45.216 61.115 50.706 61.421 ;
     RECT  19.944 61.349 26.406 61.429 ;
     RECT  27.255 61.123 41.022 61.429 ;
     RECT  47.52 61.421 50.706 61.457 ;
     RECT  18.288 59.837 18.99 61.529 ;
     RECT  41.796 60.809 44.298 61.579 ;
     RECT  45.216 61.421 46.71 61.579 ;
     RECT  19.944 61.429 41.022 61.619 ;
     RECT  18.864 61.529 18.99 61.661 ;
     RECT  19.944 61.619 34.65 61.691 ;
     RECT  35.424 61.619 41.022 61.735 ;
     RECT  41.796 61.579 46.71 61.735 ;
     RECT  19.944 61.691 34.326 61.757 ;
     RECT  35.424 61.735 46.71 61.763 ;
     RECT  20.232 61.757 34.326 61.799 ;
     RECT  40.356 61.763 46.71 61.799 ;
     RECT  20.232 61.799 29.718 61.889 ;
     RECT  30.492 61.799 34.326 61.889 ;
     RECT  40.356 61.799 46.242 61.889 ;
     RECT  47.52 61.457 50.526 61.889 ;
     RECT  40.356 61.889 40.446 61.925 ;
     RECT  40.356 61.925 40.374 61.961 ;
     RECT  48.06 61.889 50.526 61.961 ;
     RECT  41.22 61.889 45.99 62.159 ;
     RECT  41.22 62.159 41.238 62.195 ;
     RECT  48.312 61.961 50.526 62.195 ;
     RECT  48.855 62.195 50.526 62.231 ;
     RECT  35.424 61.763 39.222 62.267 ;
     RECT  50.22 62.231 50.526 62.267 ;
     RECT  42.084 62.159 45.99 62.303 ;
     RECT  50.508 62.267 50.526 62.303 ;
     RECT  37.476 62.267 39.222 62.429 ;
     RECT  42.696 62.303 42.714 62.429 ;
     RECT  43.455 62.303 45.99 62.429 ;
     RECT  48.855 62.231 49.338 62.429 ;
     RECT  50.94 62.311 50.958 62.429 ;
     RECT  21.348 61.889 29.718 62.465 ;
     RECT  37.908 62.429 39.222 62.501 ;
     RECT  43.455 62.429 43.794 62.501 ;
     RECT  45.252 62.429 45.522 62.501 ;
     RECT  24.228 62.465 29.718 62.581 ;
     RECT  30.492 61.889 34.218 62.581 ;
     RECT  35.424 62.267 36.666 62.581 ;
     RECT  38.055 62.501 39.222 62.581 ;
     RECT  35.388 62.581 36.666 62.669 ;
     RECT  35.388 62.669 36.522 62.699 ;
     RECT  38.055 62.581 39.33 62.699 ;
     RECT  20.232 61.889 20.574 62.707 ;
     RECT  21.348 62.465 23.346 62.707 ;
     RECT  45.504 62.501 45.522 62.735 ;
     RECT  18.9 61.661 18.99 62.807 ;
     RECT  35.388 62.699 36.09 62.807 ;
     RECT  38.055 62.699 38.898 62.843 ;
     RECT  24.228 62.581 34.218 62.851 ;
     RECT  35.244 62.815 35.262 62.861 ;
     RECT  24.228 62.851 34.254 62.969 ;
     RECT  36.072 62.807 36.09 62.969 ;
     RECT  20.232 62.707 23.346 63.005 ;
     RECT  24.228 62.969 34.038 63.077 ;
     RECT  25.668 63.077 34.038 63.239 ;
     RECT  18.9 62.807 18.918 63.347 ;
     RECT  25.668 63.239 29.286 63.347 ;
     RECT  20.412 63.005 23.346 63.509 ;
     RECT  30.024 63.239 34.038 63.509 ;
     RECT  24.228 63.077 24.894 63.545 ;
     RECT  20.556 63.509 23.346 63.581 ;
     RECT  24.516 63.545 24.894 63.581 ;
     RECT  24.696 63.581 24.714 63.689 ;
     RECT  25.668 63.347 29.25 63.689 ;
     RECT  20.556 63.581 20.574 63.779 ;
     RECT  21.816 63.581 23.346 63.779 ;
     RECT  30.78 63.509 34.038 63.779 ;
     RECT  21.855 63.779 23.346 63.787 ;
     RECT  28.692 63.689 29.25 63.815 ;
     RECT  28.8 63.815 29.25 63.851 ;
     RECT  26.856 63.689 27.81 63.959 ;
     RECT  0.255 43.835 0.537 64.007 ;
     RECT  5.655 51.935 5.937 64.007 ;
     RECT  11.055 52.439 11.337 64.007 ;
     RECT  16.455 59.837 16.737 64.007 ;
     RECT  21.855 63.787 23.598 64.007 ;
     RECT  26.856 63.959 27.537 64.007 ;
     RECT  38.055 62.843 38.337 64.007 ;
     RECT  43.455 62.501 43.737 64.007 ;
     RECT  48.855 62.429 49.137 64.007 ;
     RECT  54.255 59.999 54.537 64.007 ;
     RECT  59.655 48.929 59.937 64.007 ;
     RECT  30.78 63.779 33.786 64.013 ;
     RECT  22.824 64.007 23.598 64.049 ;
     RECT  28.836 63.851 29.25 64.049 ;
     RECT  28.836 64.049 28.854 64.121 ;
     RECT  30.024 63.509 30.042 64.157 ;
     RECT  30.78 64.013 31.41 64.205 ;
     RECT  22.824 64.049 22.842 64.229 ;
     RECT  32.436 64.013 33.786 64.229 ;
     RECT  31.068 64.205 31.41 64.253 ;
     RECT  32.436 64.229 33.066 64.253 ;
     RECT  0.255 64.007 0.345 64.277 ;
     RECT  5.655 64.007 5.745 64.277 ;
     RECT  11.055 64.007 11.145 64.277 ;
     RECT  16.455 64.007 16.545 64.277 ;
     RECT  21.855 64.007 21.945 64.277 ;
     RECT  26.856 64.007 27.345 64.277 ;
     RECT  32.436 64.253 32.745 64.277 ;
     RECT  38.055 64.007 38.145 64.277 ;
     RECT  43.455 64.007 43.545 64.277 ;
     RECT  48.855 64.007 48.945 64.277 ;
     RECT  54.255 64.007 54.345 64.277 ;
     RECT  59.655 64.007 59.745 64.277 ;
     RECT  26.856 64.277 26.874 64.319 ;
     RECT  31.356 64.253 31.41 64.349 ;
     RECT  32.436 64.277 32.454 64.397 ;
     RECT  31.392 64.349 31.41 64.445 ;
     RECT  23.58 64.049 23.598 64.589 ;
     RECT  25.668 63.689 25.686 64.637 ;
     RECT  26.784 64.507 26.802 64.637 ;
    LAYER M4 ;
     RECT  0.133 34.752 0.248 34.776 ;
     RECT  0.133 36 0.248 36.024 ;
     RECT  0.248 0.528 0.352 64.272 ;
     RECT  0.352 0.798 0.544 64.002 ;
     RECT  0.544 39.744 0.659 39.816 ;
     RECT  0.544 25.92 0.707 25.944 ;
     RECT  0.544 31.392 1.043 31.416 ;
     RECT  0.544 17.616 1.139 18.216 ;
     RECT  0.544 19.344 1.139 20.712 ;
     RECT  0.544 23.136 1.18 23.784 ;
     RECT  1.139 18.192 1.181 18.216 ;
     RECT  1.18 23.568 1.187 23.784 ;
     RECT  0.544 10.56 1.283 10.584 ;
     RECT  0.544 8.16 1.331 8.28 ;
     RECT  1.139 19.344 1.523 19.368 ;
     RECT  0.544 15.984 1.573 16.008 ;
     RECT  1.532 44.976 1.619 45 ;
     RECT  0.544 22.128 1.649 22.152 ;
     RECT  1.573 15.84 1.66 16.008 ;
     RECT  1.621 24.096 1.708 24.12 ;
     RECT  1.331 8.16 1.715 8.184 ;
     RECT  0.544 41.376 1.861 41.4 ;
     RECT  1.897 14.832 2.041 14.856 ;
     RECT  2.041 13.872 2.045 14.856 ;
     RECT  2.06 30.96 2.147 30.984 ;
     RECT  2.077 34.656 2.221 34.68 ;
     RECT  2.149 45.216 2.252 45.24 ;
     RECT  1.609 32.88 2.293 32.904 ;
     RECT  0.659 39.744 2.293 39.768 ;
     RECT  2.221 34.656 2.3 34.824 ;
     RECT  2.293 39.744 2.329 39.864 ;
     RECT  1.66 15.984 2.333 16.008 ;
     RECT  2.252 20.688 2.339 20.712 ;
     RECT  2.252 45.216 2.339 45.576 ;
     RECT  2.293 32.736 2.365 32.904 ;
     RECT  2.3 34.656 2.365 35.112 ;
     RECT  2.365 34.656 2.387 35.88 ;
     RECT  2.329 39.312 2.435 39.864 ;
     RECT  2.396 25.968 2.483 25.992 ;
     RECT  1.861 41.376 2.509 41.592 ;
     RECT  0.544 42.72 2.549 42.744 ;
     RECT  2.581 19.248 2.588 19.272 ;
     RECT  2.54 23.76 2.627 23.784 ;
     RECT  2.588 19.248 2.668 20.184 ;
     RECT  2.668 20.064 2.675 20.184 ;
     RECT  2.387 35.712 2.723 35.88 ;
     RECT  2.684 23.568 2.771 23.592 ;
     RECT  2.339 45.216 2.78 45.24 ;
     RECT  2.435 39.84 2.819 39.864 ;
     RECT  2.365 32.736 2.837 33.048 ;
     RECT  2.387 34.656 2.837 34.68 ;
     RECT  2.78 18.192 2.867 18.216 ;
     RECT  2.723 35.856 2.867 35.88 ;
     RECT  2.509 41.376 2.867 41.736 ;
     RECT  2.78 45.168 2.867 45.24 ;
     RECT  2.773 37.344 2.88 37.368 ;
     RECT  2.833 15.408 2.917 15.432 ;
     RECT  2.045 13.872 3.059 14.424 ;
     RECT  2.869 8.208 3.089 8.232 ;
     RECT  0.544 12.528 3.125 12.552 ;
     RECT  2.867 45.216 3.155 45.24 ;
     RECT  2.837 32.736 3.253 33 ;
     RECT  2.867 41.376 3.265 41.688 ;
     RECT  3.253 32.448 3.34 33 ;
     RECT  3.26 27.84 3.347 27.864 ;
     RECT  2.581 28.992 3.347 29.016 ;
     RECT  3.34 32.784 3.413 33 ;
     RECT  3.116 22.464 3.481 22.488 ;
     RECT  3.413 32.784 3.521 32.904 ;
     RECT  3.452 29.376 3.539 29.544 ;
     RECT  2.675 20.112 3.733 20.184 ;
     RECT  3.397 26.256 3.773 26.28 ;
     RECT  3.059 14.4 3.779 14.424 ;
     RECT  3.74 45.696 3.827 46.2 ;
     RECT  3.769 42.768 3.853 42.792 ;
     RECT  3.829 25.728 3.884 25.752 ;
     RECT  3.049 9.648 3.949 9.672 ;
     RECT  3.397 35.952 3.953 35.976 ;
     RECT  3.884 24.864 3.971 25.752 ;
     RECT  3.397 31.392 3.971 31.416 ;
     RECT  3.265 40.848 3.973 41.688 ;
     RECT  3.949 9.648 3.98 10.584 ;
     RECT  3.733 19.392 4.012 20.184 ;
     RECT  3.827 45.696 4.022 45.768 ;
     RECT  3.971 25.728 4.025 25.752 ;
     RECT  3.98 8.688 4.067 10.584 ;
     RECT  3.481 22.464 4.093 22.584 ;
     RECT  4.022 45.696 4.108 45.72 ;
     RECT  3.589 38.112 4.124 38.136 ;
     RECT  3.409 34.368 4.129 34.392 ;
     RECT  4.012 20.16 4.169 20.184 ;
     RECT  4.129 14.64 4.213 15.048 ;
     RECT  4.093 21.984 4.241 22.584 ;
     RECT  4.213 14.64 4.252 14.808 ;
     RECT  3.973 39.888 4.277 41.688 ;
     RECT  4.067 9.648 4.321 10.584 ;
     RECT  4.277 39.888 4.348 40.824 ;
     RECT  4.321 10.56 4.355 10.584 ;
     RECT  4.309 27.84 4.396 27.864 ;
     RECT  4.357 18.192 4.444 18.216 ;
     RECT  4.129 34.368 4.492 34.632 ;
     RECT  4.417 23.568 4.501 23.592 ;
     RECT  4.556 45.408 4.643 45.432 ;
     RECT  4.453 10.656 4.652 10.776 ;
     RECT  4.124 37.872 4.673 38.136 ;
     RECT  3.521 32.784 4.693 32.808 ;
     RECT  4.693 37.344 5.057 37.368 ;
     RECT  4.693 32.736 5.065 32.808 ;
     RECT  4.693 33.792 5.065 33.816 ;
     RECT  4.796 47.568 5.065 47.592 ;
     RECT  4.348 39.888 5.093 40.056 ;
     RECT  3.539 29.376 5.125 29.4 ;
     RECT  3.985 31.2 5.125 31.224 ;
     RECT  4.417 41.904 5.125 42.072 ;
     RECT  4.241 22.56 5.173 22.584 ;
     RECT  5.221 25.68 5.389 25.992 ;
     RECT  5.093 39.216 5.509 40.056 ;
     RECT  5.353 44.64 5.509 44.664 ;
     RECT  5.389 25.488 5.641 25.992 ;
     RECT  5.276 8.448 5.648 8.472 ;
     RECT  4.652 10.656 5.648 10.872 ;
     RECT  5.209 12.528 5.648 12.552 ;
     RECT  4.252 14.784 5.648 14.808 ;
     RECT  4.741 18.72 5.648 18.744 ;
     RECT  5.509 19.776 5.648 19.8 ;
     RECT  5.173 22.56 5.648 22.776 ;
     RECT  5.641 25.44 5.648 25.992 ;
     RECT  5.509 27.6 5.648 27.624 ;
     RECT  5.125 28.992 5.648 29.688 ;
     RECT  5.125 30.72 5.648 31.224 ;
     RECT  5.065 32.736 5.648 33.816 ;
     RECT  5.125 34.8 5.648 34.824 ;
     RECT  5.057 36.96 5.648 37.368 ;
     RECT  5.509 38.64 5.648 40.056 ;
     RECT  5.125 41.904 5.648 42.648 ;
     RECT  5.509 43.824 5.648 44.664 ;
     RECT  5.065 47.376 5.648 47.592 ;
     RECT  5.648 0.528 5.752 64.272 ;
     RECT  5.752 0.798 5.944 64.002 ;
     RECT  5.944 26.784 6.077 26.808 ;
     RECT  5.944 10.32 6.083 10.728 ;
     RECT  5.944 28.992 6.083 29.592 ;
     RECT  5.944 44.304 6.085 45.72 ;
     RECT  5.944 42.672 6.113 42.696 ;
     RECT  6.085 45.552 6.172 45.72 ;
     RECT  5.944 36 6.185 37.08 ;
     RECT  5.944 16.848 6.257 16.92 ;
     RECT  5.944 30.864 6.265 31.944 ;
     RECT  6.185 36.048 6.275 37.08 ;
     RECT  5.944 23.952 6.293 25.56 ;
     RECT  6.275 36.048 6.293 36.072 ;
     RECT  5.944 18.864 6.323 20.664 ;
     RECT  5.944 14.4 6.329 14.424 ;
     RECT  5.944 41.664 6.365 41.688 ;
     RECT  6.085 44.304 6.419 44.328 ;
     RECT  6.083 10.608 6.509 10.728 ;
     RECT  6.293 23.952 6.611 24.456 ;
     RECT  5.944 22.752 6.645 22.776 ;
     RECT  6.323 20.304 6.797 20.664 ;
     RECT  6.265 30.864 6.797 31.224 ;
     RECT  5.944 33.84 6.797 33.864 ;
     RECT  5.944 39.888 6.803 40.44 ;
     RECT  5.944 9.12 6.851 9.144 ;
     RECT  5.944 12.192 6.869 12.552 ;
     RECT  5.944 48.48 6.899 48.504 ;
     RECT  6.797 20.64 6.937 20.664 ;
     RECT  6.275 37.056 6.94 37.08 ;
     RECT  6.293 25.44 6.977 25.56 ;
     RECT  6.869 12.192 6.995 12.216 ;
     RECT  6.929 27.552 7.013 27.576 ;
     RECT  6.997 7.92 7.085 7.944 ;
     RECT  6.977 25.536 7.085 25.56 ;
     RECT  7.004 41.376 7.091 41.4 ;
     RECT  6.803 39.888 7.121 39.912 ;
     RECT  6.323 18.864 7.225 18.936 ;
     RECT  7.141 47.568 7.228 48.456 ;
     RECT  7.225 18.768 7.265 18.936 ;
     RECT  6.611 24.432 7.265 24.456 ;
     RECT  6.509 10.608 7.292 10.632 ;
     RECT  7.265 18.768 7.373 18.792 ;
     RECT  7.292 10.224 7.379 10.632 ;
     RECT  6.172 45.552 7.381 45.576 ;
     RECT  6.257 16.896 7.409 16.92 ;
     RECT  7.045 38.16 7.427 38.184 ;
     RECT  7.379 10.608 7.477 10.632 ;
     RECT  7.429 43.728 7.516 43.752 ;
     RECT  6.083 28.992 7.517 29.016 ;
     RECT  6.937 20.64 7.553 20.856 ;
     RECT  7.477 31.44 7.564 31.464 ;
     RECT  7.261 35.328 7.585 35.352 ;
     RECT  6.973 22.224 7.589 22.296 ;
     RECT  7.477 10.608 7.625 10.728 ;
     RECT  7.381 44.976 7.625 45.576 ;
     RECT  7.228 47.856 7.625 48.456 ;
     RECT  7.549 37.92 7.733 37.944 ;
     RECT  7.429 24.528 7.877 24.552 ;
     RECT  7.625 48.096 7.907 48.456 ;
     RECT  7.585 34.896 7.955 35.352 ;
     RECT  7.553 20.64 8.021 20.664 ;
     RECT  7.589 22.272 8.021 22.296 ;
     RECT  7.441 33.072 8.021 33.096 ;
     RECT  7.957 26.16 8.057 26.184 ;
     RECT  8.005 13.296 8.092 13.32 ;
     RECT  8.005 11.664 8.093 11.688 ;
     RECT  7.621 15.552 8.093 15.576 ;
     RECT  7.625 44.976 8.125 45 ;
     RECT  7.773 29.232 8.195 29.256 ;
     RECT  8.305 19.392 8.444 19.416 ;
     RECT  7.907 48.096 8.483 48.12 ;
     RECT  7.955 34.992 8.489 35.352 ;
     RECT  8.444 18.72 8.531 19.416 ;
     RECT  8.444 46.224 8.531 46.248 ;
     RECT  8.489 35.328 8.581 35.352 ;
     RECT  8.581 35.328 8.593 35.496 ;
     RECT  8.513 15.984 8.597 16.008 ;
     RECT  8.593 35.328 8.597 35.88 ;
     RECT  8.597 35.472 8.668 35.88 ;
     RECT  8.588 29.472 8.675 29.496 ;
     RECT  8.588 39.264 8.675 39.288 ;
     RECT  8.668 35.856 8.677 35.88 ;
     RECT  8.125 44.88 8.705 45 ;
     RECT  8.636 6 8.723 6.024 ;
     RECT  8.677 35.856 8.723 36.696 ;
     RECT  8.636 45.984 8.723 46.008 ;
     RECT  8.557 38.16 8.764 38.184 ;
     RECT  8.533 14.64 8.819 14.664 ;
     RECT  8.197 31.104 8.957 31.128 ;
     RECT  8.723 36.672 9.065 36.696 ;
     RECT  8.533 20.016 9.107 20.328 ;
     RECT  7.964 42.144 9.109 42.168 ;
     RECT  9.109 43.824 9.196 43.848 ;
     RECT  9.164 48.912 9.251 48.936 ;
     RECT  9.313 47.568 9.404 47.592 ;
     RECT  9.356 50.448 9.404 50.472 ;
     RECT  9.404 50.064 9.443 50.472 ;
     RECT  9.443 50.064 9.491 50.088 ;
     RECT  8.377 22.608 9.493 22.632 ;
     RECT  9.241 43.728 9.497 43.752 ;
     RECT  9.5 45.312 9.587 45.336 ;
     RECT  9.404 47.328 9.589 47.592 ;
     RECT  9.109 13.008 9.605 13.656 ;
     RECT  9.385 51.888 9.665 51.912 ;
     RECT  9.493 22.608 9.677 22.776 ;
     RECT  9.529 39.888 9.677 39.912 ;
     RECT  9.665 51.12 9.683 51.912 ;
     RECT  8.531 18.72 9.685 18.744 ;
     RECT  9.601 29.76 9.685 29.784 ;
     RECT  9.685 34.464 9.817 34.488 ;
     RECT  9.109 42.144 9.82 42.456 ;
     RECT  9.788 9.504 9.875 9.528 ;
     RECT  9.677 22.752 9.893 22.776 ;
     RECT  9.884 26.16 9.971 26.184 ;
     RECT  9.817 33.648 9.98 34.488 ;
     RECT  8.845 16.56 10.019 16.584 ;
     RECT  7.625 10.608 10.033 10.632 ;
     RECT  9.98 33.648 10.067 35.112 ;
     RECT  10.069 31.344 10.141 31.368 ;
     RECT  9.997 39.84 10.141 39.864 ;
     RECT  9.745 12.528 10.213 12.552 ;
     RECT  9.589 47.088 10.261 47.592 ;
     RECT  10.069 48.672 10.261 48.696 ;
     RECT  10.141 31.344 10.309 32.328 ;
     RECT  10.067 33.648 10.309 34.68 ;
     RECT  9.685 18.72 10.364 18.792 ;
     RECT  10.321 15.264 10.46 15.288 ;
     RECT  9.685 29.664 10.537 29.784 ;
     RECT  10.213 11.952 10.645 12.552 ;
     RECT  9.605 13.632 10.645 13.656 ;
     RECT  10.364 18.72 10.645 19.272 ;
     RECT  10.645 18.432 10.748 19.272 ;
     RECT  10.537 29.568 10.825 29.784 ;
     RECT  9.683 51.12 10.837 51.144 ;
     RECT  10.556 6 10.861 6.024 ;
     RECT  10.033 7.344 10.861 7.368 ;
     RECT  10.837 9.36 10.897 9.384 ;
     RECT  10.028 43.008 10.933 43.56 ;
     RECT  10.837 51.12 10.933 51.96 ;
     RECT  10.861 6 11.048 7.368 ;
     RECT  10.897 9.264 11.048 9.384 ;
     RECT  10.033 10.608 11.048 10.824 ;
     RECT  10.645 11.952 11.048 13.656 ;
     RECT  10.46 15.264 11.048 15.384 ;
     RECT  10.393 17.04 11.048 17.064 ;
     RECT  10.748 18.432 11.048 19.416 ;
     RECT  10.105 21.12 11.048 21.144 ;
     RECT  10.717 24.432 11.048 24.456 ;
     RECT  9.241 27.6 11.048 27.624 ;
     RECT  10.825 29.568 11.048 29.928 ;
     RECT  10.309 31.344 11.048 34.68 ;
     RECT  10.117 35.952 11.048 35.976 ;
     RECT  10.753 38.16 11.048 38.184 ;
     RECT  10.141 39.6 11.048 39.864 ;
     RECT  10.933 41.232 11.048 43.56 ;
     RECT  10.261 47.088 11.048 48.936 ;
     RECT  10.933 50.016 11.048 50.04 ;
     RECT  10.933 51.12 11.048 52.056 ;
     RECT  11.048 0.528 11.152 64.272 ;
     RECT  11.152 0.798 11.344 64.002 ;
     RECT  11.344 12 11.369 13.416 ;
     RECT  11.344 39.6 11.405 39.768 ;
     RECT  11.344 9.264 11.441 9.384 ;
     RECT  11.344 15.264 11.441 15.432 ;
     RECT  11.405 39.744 11.459 39.768 ;
     RECT  11.344 33.36 11.477 33.672 ;
     RECT  11.344 41.232 11.621 41.448 ;
     RECT  11.344 7.584 11.692 7.608 ;
     RECT  11.344 37.584 11.692 37.608 ;
     RECT  11.621 41.232 11.693 41.256 ;
     RECT  11.344 45.408 11.788 45.432 ;
     RECT  11.344 16.656 11.843 16.68 ;
     RECT  11.369 13.392 11.873 13.416 ;
     RECT  11.344 26.112 11.939 26.472 ;
     RECT  11.939 26.112 11.987 26.136 ;
     RECT  11.344 43.872 12.017 43.896 ;
     RECT  11.344 18.144 12.025 18.888 ;
     RECT  11.344 29.568 12.125 29.592 ;
     RECT  11.344 42.624 12.125 42.744 ;
     RECT  11.477 33.36 12.161 33.576 ;
     RECT  12.025 18.144 12.179 18.216 ;
     RECT  11.344 47.328 12.227 49.032 ;
     RECT  11.344 35.808 12.275 35.832 ;
     RECT  11.344 31.008 12.305 31.416 ;
     RECT  12.305 31.008 12.323 31.176 ;
     RECT  11.344 6.24 12.337 6.264 ;
     RECT  11.441 15.408 12.341 15.432 ;
     RECT  12.337 6.24 12.409 6.312 ;
     RECT  12.409 6.24 12.481 6.36 ;
     RECT  11.344 10.896 12.515 10.92 ;
     RECT  11.344 23.952 12.515 24.504 ;
     RECT  11.344 52.032 12.517 52.056 ;
     RECT  11.369 12 12.521 12.024 ;
     RECT  11.441 9.36 12.553 9.384 ;
     RECT  12.469 46.368 12.556 46.392 ;
     RECT  12.553 9.12 12.593 9.384 ;
     RECT  12.481 6.24 12.661 6.84 ;
     RECT  12.161 33.552 12.661 33.576 ;
     RECT  12.227 47.472 12.7 49.032 ;
     RECT  12.661 6.24 12.701 7.368 ;
     RECT  12.613 13.68 12.701 13.704 ;
     RECT  12.517 27.408 12.701 27.432 ;
     RECT  12.517 51.936 12.701 52.056 ;
     RECT  12.661 33.552 12.745 33.864 ;
     RECT  12.517 16.944 12.773 16.968 ;
     RECT  12.593 9.12 12.805 9.144 ;
     RECT  12.515 23.952 12.809 24.456 ;
     RECT  12.745 33.552 12.809 33.576 ;
     RECT  12.869 27.936 12.953 27.96 ;
     RECT  12.701 6.288 12.988 7.368 ;
     RECT  12.7 49.008 12.989 49.032 ;
     RECT  11.344 50.832 13.061 50.856 ;
     RECT  12.733 21.984 13.091 22.008 ;
     RECT  12.805 8.688 13.093 9.144 ;
     RECT  12.701 52.032 13.097 52.056 ;
     RECT  12.908 41.76 13.1 41.784 ;
     RECT  12.877 40.416 13.133 40.44 ;
     RECT  13.052 54.72 13.139 54.744 ;
     RECT  12.697 38.688 13.141 38.712 ;
     RECT  13.093 8.592 13.18 9.144 ;
     RECT  13.1 41.76 13.187 42.024 ;
     RECT  13.187 41.76 13.189 41.784 ;
     RECT  12.988 6.288 13.205 6.648 ;
     RECT  13.189 41.424 13.276 41.784 ;
     RECT  12.7 47.472 13.277 47.592 ;
     RECT  12.323 31.152 13.349 31.176 ;
     RECT  13.388 20.448 13.417 20.472 ;
     RECT  13.34 51.024 13.427 51.048 ;
     RECT  13.141 38.352 13.457 38.712 ;
     RECT  13.417 20.448 13.475 21.144 ;
     RECT  13.093 23.088 13.525 23.112 ;
     RECT  13.475 21.12 13.529 21.144 ;
     RECT  13.477 26.16 13.564 26.184 ;
     RECT  13.205 6.336 13.565 6.648 ;
     RECT  13.093 37.296 13.565 37.32 ;
     RECT  13.525 22.176 13.601 23.112 ;
     RECT  13.165 29.952 13.667 29.976 ;
     RECT  13.621 10.752 13.708 10.776 ;
     RECT  13.525 13.44 13.745 13.464 ;
     RECT  13.276 41.568 13.745 41.784 ;
     RECT  13.669 35.856 13.853 35.88 ;
     RECT  13.669 33.024 13.889 33.048 ;
     RECT  12.179 18.192 13.921 18.216 ;
     RECT  12.809 24.096 13.925 24.456 ;
     RECT  13.565 6.624 14.033 6.648 ;
     RECT  13.745 41.616 14.051 41.784 ;
     RECT  13.601 22.176 14.069 22.2 ;
     RECT  13.777 45.984 14.092 46.008 ;
     RECT  13.921 18.192 14.105 18.696 ;
     RECT  14.051 41.616 14.105 41.64 ;
     RECT  13.885 20.016 14.177 20.04 ;
     RECT  14.101 34.464 14.197 34.488 ;
     RECT  13.993 51.312 14.197 51.336 ;
     RECT  14.105 18.672 14.243 18.696 ;
     RECT  14.156 23.808 14.243 23.832 ;
     RECT  14.197 34.464 14.243 35.016 ;
     RECT  14.156 37.968 14.243 37.992 ;
     RECT  13.277 47.568 14.245 47.592 ;
     RECT  14.197 51.312 14.284 52.152 ;
     RECT  14.245 47.568 14.285 47.784 ;
     RECT  14.173 21.648 14.291 22.104 ;
     RECT  13.777 17.136 14.393 17.16 ;
     RECT  13.849 14.832 14.545 14.856 ;
     RECT  14.243 34.992 14.573 35.016 ;
     RECT  13.18 9.12 14.588 9.144 ;
     RECT  14.245 32.304 14.609 32.328 ;
     RECT  14.588 9.12 14.675 10.104 ;
     RECT  14.629 42.72 14.716 42.744 ;
     RECT  14.713 12.768 14.797 12.792 ;
     RECT  14.447 13.824 14.819 13.848 ;
     RECT  14.713 51.216 14.819 51.24 ;
     RECT  14.245 31.056 14.821 31.08 ;
     RECT  14.821 30.432 14.825 31.08 ;
     RECT  14.675 9.12 14.861 9.144 ;
     RECT  14.821 20.448 14.905 20.472 ;
     RECT  14.825 30.432 14.905 30.84 ;
     RECT  13.741 43.728 14.917 43.752 ;
     RECT  14.917 52.416 15.005 52.44 ;
     RECT  14.917 43.728 15.073 44.088 ;
     RECT  15.073 43.728 15.077 44.376 ;
     RECT  14.965 38.688 15.185 38.712 ;
     RECT  15.289 0.288 15.317 0.312 ;
     RECT  14.869 6.816 15.329 6.84 ;
     RECT  14.291 21.648 15.329 21.672 ;
     RECT  14.285 47.76 15.349 47.784 ;
     RECT  13.993 3.84 15.356 3.864 ;
     RECT  15.356 3.36 15.397 3.864 ;
     RECT  14.893 46.032 15.404 46.056 ;
     RECT  15.317 0.288 15.433 1.176 ;
     RECT  15.349 47.76 15.436 47.976 ;
     RECT  15.397 3.36 15.443 4.008 ;
     RECT  15.397 23.808 15.481 23.832 ;
     RECT  15.443 3.984 15.505 4.008 ;
     RECT  15.404 46.032 15.836 46.152 ;
     RECT  15.644 40.176 15.884 40.2 ;
     RECT  15.596 19.344 15.893 19.368 ;
     RECT  15.493 49.488 15.893 49.512 ;
     RECT  15.836 50.88 15.893 50.904 ;
     RECT  15.884 40.176 15.901 40.44 ;
     RECT  15.893 49.488 16.076 50.904 ;
     RECT  15.445 5.76 16.117 5.784 ;
     RECT  15.973 13.824 16.117 13.848 ;
     RECT  15.893 18.864 16.124 19.368 ;
     RECT  15.397 10.752 16.153 10.776 ;
     RECT  15.433 0.192 16.189 1.176 ;
     RECT  16.189 0.192 16.193 1.368 ;
     RECT  16.153 10.08 16.268 10.776 ;
     RECT  16.076 49.488 16.309 51.672 ;
     RECT  16.193 0.288 16.448 1.368 ;
     RECT  16.405 2.592 16.448 2.616 ;
     RECT  15.505 3.984 16.448 4.248 ;
     RECT  16.117 5.76 16.448 6.696 ;
     RECT  16.405 7.968 16.448 7.992 ;
     RECT  16.268 9.84 16.448 10.776 ;
     RECT  16.225 12.288 16.448 12.312 ;
     RECT  16.117 13.824 16.448 14.232 ;
     RECT  15.397 16.416 16.448 16.44 ;
     RECT  16.124 18.864 16.448 19.56 ;
     RECT  14.905 30.816 16.448 30.84 ;
     RECT  15.397 35.76 16.448 35.784 ;
     RECT  15.901 40.176 16.448 41.256 ;
     RECT  15.865 42.624 16.448 42.648 ;
     RECT  15.077 43.776 16.448 44.376 ;
     RECT  15.836 45.696 16.448 46.152 ;
     RECT  15.692 47.328 16.448 47.352 ;
     RECT  16.309 49.488 16.448 51.96 ;
     RECT  14.849 54.624 16.448 54.648 ;
     RECT  16.448 0.288 16.552 64.272 ;
     RECT  16.552 0.288 16.744 64.002 ;
     RECT  16.744 0.288 16.883 1.176 ;
     RECT  16.744 10.896 16.883 10.92 ;
     RECT  16.744 19.296 16.883 20.712 ;
     RECT  16.744 40.656 16.883 44.616 ;
     RECT  16.744 56.16 16.883 56.184 ;
     RECT  16.744 46.8 16.949 47.88 ;
     RECT  16.883 1.152 17.021 1.176 ;
     RECT  16.744 17.568 17.021 17.592 ;
     RECT  16.744 2.208 17.057 8.328 ;
     RECT  17.057 7.344 17.068 8.328 ;
     RECT  16.744 54.576 17.123 54.6 ;
     RECT  16.744 15.84 17.129 16.152 ;
     RECT  16.744 23.184 17.171 23.976 ;
     RECT  16.744 50.976 17.381 53.592 ;
     RECT  16.949 46.8 17.507 46.824 ;
     RECT  16.883 41.568 17.555 44.616 ;
     RECT  17.171 23.568 17.561 23.976 ;
     RECT  16.744 25.104 17.569 25.128 ;
     RECT  17.381 50.976 17.596 51 ;
     RECT  17.057 2.208 17.597 5.832 ;
     RECT  16.744 38.16 17.603 39.048 ;
     RECT  16.744 45.696 17.603 45.816 ;
     RECT  16.744 11.952 17.651 12.744 ;
     RECT  16.883 19.296 17.651 20.088 ;
     RECT  17.068 7.968 17.669 8.328 ;
     RECT  17.651 12.24 17.692 12.744 ;
     RECT  17.597 2.208 17.705 4.488 ;
     RECT  17.692 12.24 17.705 12.312 ;
     RECT  16.744 32.16 17.705 33.048 ;
     RECT  17.603 38.352 17.705 39.048 ;
     RECT  17.705 2.208 17.747 2.232 ;
     RECT  17.603 45.792 17.813 45.816 ;
     RECT  17.705 3.696 17.885 4.488 ;
     RECT  16.744 49.008 17.917 49.176 ;
     RECT  17.669 8.016 17.957 8.328 ;
     RECT  17.917 49.008 17.957 49.416 ;
     RECT  16.744 26.784 17.993 26.808 ;
     RECT  17.957 8.016 18.029 8.04 ;
     RECT  17.948 10.896 18.035 10.92 ;
     RECT  17.885 4.464 18.065 4.488 ;
     RECT  17.651 19.296 18.085 19.32 ;
     RECT  18.037 55.968 18.124 55.992 ;
     RECT  17.555 41.568 18.133 41.592 ;
     RECT  17.555 42.864 18.137 44.616 ;
     RECT  17.737 9.648 18.169 9.672 ;
     RECT  16.949 47.856 18.169 47.88 ;
     RECT  18.085 19.248 18.172 19.32 ;
     RECT  18.161 22.32 18.181 22.344 ;
     RECT  17.129 16.128 18.205 16.152 ;
     RECT  18.169 9.312 18.227 9.672 ;
     RECT  17.381 52.08 18.236 53.592 ;
     RECT  18.229 54.576 18.236 54.6 ;
     RECT  18.181 22.32 18.245 23.016 ;
     RECT  18.137 42.864 18.245 43.848 ;
     RECT  18.245 22.992 18.268 23.016 ;
     RECT  18.133 41.184 18.281 41.592 ;
     RECT  18.236 52.08 18.313 54.6 ;
     RECT  17.705 38.352 18.317 38.856 ;
     RECT  18.313 52.08 18.323 54.648 ;
     RECT  18.245 43.248 18.353 43.848 ;
     RECT  18.205 16.128 18.457 16.44 ;
     RECT  18.172 19.296 18.497 19.32 ;
     RECT  18.281 41.568 18.517 41.592 ;
     RECT  18.097 39.888 18.533 39.912 ;
     RECT  18.457 15.744 18.601 16.44 ;
     RECT  18.517 41.568 18.604 42.216 ;
     RECT  18.025 6.24 18.637 6.264 ;
     RECT  18.353 43.248 18.659 43.704 ;
     RECT  18.323 52.08 18.677 53.208 ;
     RECT  17.705 12.288 18.709 12.312 ;
     RECT  17.705 32.16 18.709 32.184 ;
     RECT  18.709 12 18.745 12.312 ;
     RECT  18.317 38.592 18.755 38.856 ;
     RECT  18.737 30.672 18.757 30.696 ;
     RECT  18.601 15.744 18.803 16.584 ;
     RECT  18.677 52.992 18.803 53.208 ;
     RECT  18.241 36 18.805 36.024 ;
     RECT  18.805 25.44 18.817 25.464 ;
     RECT  18.227 9.312 18.821 9.336 ;
     RECT  18.757 30.672 18.821 30.792 ;
     RECT  18.805 36 18.851 36.504 ;
     RECT  18.745 12 18.857 12.6 ;
     RECT  18.803 15.744 18.857 16.44 ;
     RECT  18.757 45.744 18.864 45.768 ;
     RECT  18.817 25.104 18.893 25.464 ;
     RECT  18.323 54.336 18.893 54.648 ;
     RECT  18.709 32.16 18.929 32.568 ;
     RECT  18.821 30.768 18.937 30.792 ;
     RECT  18.857 12 18.997 12.168 ;
     RECT  18.745 7.872 19.069 7.896 ;
     RECT  19.069 7.872 19.073 8.232 ;
     RECT  18.997 11.088 19.073 12.168 ;
     RECT  18.929 32.16 19.073 32.184 ;
     RECT  19.073 11.088 19.1 12.072 ;
     RECT  19.052 51.936 19.139 51.96 ;
     RECT  18.637 5.856 19.181 6.264 ;
     RECT  19.1 10.56 19.187 12.072 ;
     RECT  18.893 54.336 19.283 54.36 ;
     RECT  18.817 29.52 19.321 29.544 ;
     RECT  18.803 53.088 19.324 53.208 ;
     RECT  18.893 25.104 19.325 25.128 ;
     RECT  19.237 51.504 19.325 51.528 ;
     RECT  18.169 47.328 19.349 47.88 ;
     RECT  18.755 38.592 19.379 38.616 ;
     RECT  19.324 53.088 19.379 53.112 ;
     RECT  18.857 15.744 19.381 16.344 ;
     RECT  17.957 49.392 19.397 49.416 ;
     RECT  19.141 4.464 19.429 4.488 ;
     RECT  18.805 2.832 19.433 2.856 ;
     RECT  18.817 34.176 19.465 34.2 ;
     RECT  19.181 6 19.505 6.264 ;
     RECT  19.465 34.176 19.505 34.728 ;
     RECT  19.429 4.464 19.573 4.584 ;
     RECT  19.381 15.168 19.577 16.344 ;
     RECT  19.577 15.168 19.613 16.152 ;
     RECT  18.604 41.568 19.681 41.592 ;
     RECT  19.573 4.416 19.717 4.584 ;
     RECT  19.381 20.016 19.717 20.04 ;
     RECT  19.505 6 19.721 6.168 ;
     RECT  19.073 8.208 19.721 8.232 ;
     RECT  19.321 29.472 19.793 29.544 ;
     RECT  19.717 4.368 19.825 4.584 ;
     RECT  19.813 51.216 19.825 51.24 ;
     RECT  19.393 25.008 19.861 25.08 ;
     RECT  18.851 36.48 19.868 36.504 ;
     RECT  19.349 46.992 19.897 47.88 ;
     RECT  18.853 61.632 19.933 61.656 ;
     RECT  19.868 35.808 19.955 36.504 ;
     RECT  19.681 41.376 19.957 41.592 ;
     RECT  19.897 46.752 19.957 47.88 ;
     RECT  19.897 55.44 19.957 55.464 ;
     RECT  19.613 15.36 19.973 16.152 ;
     RECT  19.957 40.416 20.003 41.928 ;
     RECT  19.957 46.176 20.003 47.88 ;
     RECT  19.187 10.8 20.077 12.072 ;
     RECT  19.957 54.48 20.153 55.464 ;
     RECT  20.101 49.248 20.188 49.272 ;
     RECT  20.077 10.8 20.189 12.552 ;
     RECT  19.861 24.912 20.189 25.08 ;
     RECT  19.933 61.632 20.204 61.752 ;
     RECT  18.659 43.68 20.221 43.704 ;
     RECT  19.825 4.128 20.225 4.584 ;
     RECT  20.225 4.416 20.261 4.584 ;
     RECT  20.003 40.416 20.261 40.44 ;
     RECT  19.955 36.48 20.284 36.504 ;
     RECT  20.197 52.8 20.284 52.824 ;
     RECT  20.204 61.2 20.291 61.752 ;
     RECT  20.149 31.296 20.321 31.32 ;
     RECT  19.717 20.016 20.473 20.184 ;
     RECT  19.825 50.928 20.473 51.24 ;
     RECT  20.261 4.56 20.477 4.584 ;
     RECT  20.473 19.872 20.513 20.184 ;
     RECT  19.793 29.52 20.513 29.544 ;
     RECT  20.321 30.816 20.531 31.32 ;
     RECT  20.113 38.16 20.531 38.184 ;
     RECT  20.003 46.176 20.531 46.248 ;
     RECT  18.241 57.552 20.531 57.576 ;
     RECT  19.505 34.704 20.549 34.728 ;
     RECT  19.681 2.256 20.617 2.28 ;
     RECT  20.533 10.56 20.62 10.584 ;
     RECT  19.973 15.36 20.62 15.816 ;
     RECT  20.003 47.472 20.621 47.88 ;
     RECT  20.54 23.856 20.627 23.88 ;
     RECT  20.473 50.832 20.725 51.24 ;
     RECT  20.629 25.68 20.801 25.704 ;
     RECT  20.732 59.712 20.819 59.736 ;
     RECT  20.531 46.176 20.869 46.2 ;
     RECT  20.617 2.256 21.049 2.52 ;
     RECT  20.221 43.68 21.049 44.376 ;
     RECT  20.257 32.976 21.121 33 ;
     RECT  21.049 43.68 21.157 44.424 ;
     RECT  21.157 40.08 21.253 40.104 ;
     RECT  20.003 41.904 21.265 41.928 ;
     RECT  20.869 45.744 21.404 46.2 ;
     RECT  20.153 54.912 21.404 55.464 ;
     RECT  21.253 40.08 21.452 40.248 ;
     RECT  21.445 4.512 21.517 4.536 ;
     RECT  21.068 37.44 21.553 37.464 ;
     RECT  20.189 11.712 21.589 12.552 ;
     RECT  21.517 26.784 21.589 26.808 ;
     RECT  21.589 11.328 21.625 12.552 ;
     RECT  20.513 19.872 21.625 19.896 ;
     RECT  21.121 32.976 21.625 33.096 ;
     RECT  21.589 10.176 21.637 10.2 ;
     RECT  21.625 11.232 21.637 12.552 ;
     RECT  20.62 15.792 21.637 15.816 ;
     RECT  20.761 17.472 21.637 17.496 ;
     RECT  21.625 32.976 21.637 34.2 ;
     RECT  21.265 41.904 21.637 42.216 ;
     RECT  20.291 61.632 21.637 61.752 ;
     RECT  21.229 9.072 21.661 9.096 ;
     RECT  21.625 19.872 21.661 20.808 ;
     RECT  21.637 10.176 21.685 12.552 ;
     RECT  21.637 15.792 21.685 17.496 ;
     RECT  21.637 24.432 21.685 24.456 ;
     RECT  21.404 45.696 21.692 46.2 ;
     RECT  21.404 54.912 21.692 56.136 ;
     RECT  21.685 23.616 21.725 24.456 ;
     RECT  21.109 22.176 21.733 22.2 ;
     RECT  21.452 39.792 21.733 40.248 ;
     RECT  21.157 43.584 21.733 44.424 ;
     RECT  20.621 47.712 21.733 47.88 ;
     RECT  21.692 54.24 21.733 56.136 ;
     RECT  21.589 26.784 21.769 27.192 ;
     RECT  21.661 28.224 21.769 28.248 ;
     RECT  21.733 39.6 21.769 40.248 ;
     RECT  21.637 14.448 21.805 14.76 ;
     RECT  21.805 13.584 21.841 14.76 ;
     RECT  21.685 15.792 21.841 18.264 ;
     RECT  21.049 2.208 21.848 2.52 ;
     RECT  21.517 4.176 21.848 4.536 ;
     RECT  19.721 6 21.848 6.024 ;
     RECT  21.661 8.832 21.848 9.096 ;
     RECT  21.685 10.128 21.848 12.552 ;
     RECT  21.841 13.584 21.848 18.264 ;
     RECT  21.661 19.872 21.848 21.192 ;
     RECT  21.733 22.176 21.848 22.344 ;
     RECT  21.725 23.52 21.848 24.456 ;
     RECT  21.769 26.784 21.848 28.248 ;
     RECT  20.545 30.432 21.848 30.456 ;
     RECT  21.733 31.776 21.848 31.8 ;
     RECT  21.637 32.976 21.848 35.832 ;
     RECT  21.553 37.44 21.848 38.184 ;
     RECT  21.769 39.6 21.848 40.44 ;
     RECT  21.637 41.664 21.848 42.216 ;
     RECT  21.733 43.296 21.848 44.424 ;
     RECT  21.692 45.504 21.848 46.2 ;
     RECT  21.733 47.712 21.848 49.032 ;
     RECT  20.725 50.688 21.848 52.488 ;
     RECT  21.733 54.24 21.848 57.096 ;
     RECT  21.373 59.04 21.848 59.064 ;
     RECT  21.637 61.584 21.848 61.752 ;
     RECT  21.848 0.528 21.952 64.272 ;
     RECT  21.952 0.798 22.144 64.002 ;
     RECT  22.144 20.4 22.205 20.424 ;
     RECT  22.144 23.568 22.205 24.456 ;
     RECT  22.144 26.592 22.205 26.808 ;
     RECT  22.144 57.072 22.205 57.096 ;
     RECT  22.144 41.664 22.241 41.688 ;
     RECT  22.144 10.656 22.259 17.688 ;
     RECT  22.144 60.096 22.348 60.12 ;
     RECT  22.144 4.176 22.349 6.024 ;
     RECT  22.259 10.656 22.349 12.84 ;
     RECT  22.259 13.872 22.385 17.688 ;
     RECT  22.385 17.664 22.421 17.688 ;
     RECT  22.144 36.144 22.444 36.168 ;
     RECT  22.349 10.656 22.493 11.256 ;
     RECT  22.144 8.544 22.565 9.096 ;
     RECT  22.144 54.528 22.565 54.936 ;
     RECT  22.144 19.296 22.588 19.368 ;
     RECT  22.205 23.568 22.601 23.592 ;
     RECT  22.565 54.528 22.637 54.552 ;
     RECT  22.493 10.656 22.709 11.016 ;
     RECT  22.349 4.176 22.745 4.2 ;
     RECT  22.349 12.336 22.745 12.84 ;
     RECT  22.349 5.28 22.787 6.024 ;
     RECT  22.565 8.544 22.787 8.568 ;
     RECT  22.385 13.872 22.787 16.536 ;
     RECT  22.588 19.296 22.787 19.32 ;
     RECT  22.144 29.52 22.787 29.544 ;
     RECT  22.144 38.448 22.787 38.472 ;
     RECT  22.745 12.768 22.817 12.84 ;
     RECT  22.144 61.152 22.883 63.288 ;
     RECT  22.787 5.808 22.889 6.024 ;
     RECT  22.817 12.816 22.889 12.84 ;
     RECT  22.883 61.152 22.897 63.048 ;
     RECT  22.787 14.352 22.997 16.536 ;
     RECT  22.144 42.72 22.997 47.784 ;
     RECT  22.997 14.352 23.141 16.296 ;
     RECT  22.997 44.832 23.173 47.784 ;
     RECT  22.205 26.592 23.209 26.664 ;
     RECT  22.144 40.368 23.209 40.392 ;
     RECT  22.997 42.72 23.209 43.704 ;
     RECT  22.144 34.992 23.219 35.016 ;
     RECT  22.144 50.832 23.221 51.192 ;
     RECT  23.141 15.984 23.285 16.296 ;
     RECT  23.221 50.832 23.308 51.24 ;
     RECT  22.897 61.152 23.315 62.808 ;
     RECT  22.144 1.824 23.317 1.848 ;
     RECT  23.209 40.032 23.353 40.392 ;
     RECT  22.144 59.04 23.353 59.064 ;
     RECT  23.173 44.832 23.363 48.024 ;
     RECT  23.315 62.784 23.363 62.808 ;
     RECT  23.317 1.152 23.401 1.848 ;
     RECT  23.401 1.824 23.42 1.848 ;
     RECT  23.353 39.216 23.437 40.392 ;
     RECT  23.353 20.928 23.497 20.952 ;
     RECT  23.413 0.192 23.501 0.216 ;
     RECT  23.42 1.824 23.501 2.712 ;
     RECT  23.501 2.688 23.507 2.712 ;
     RECT  23.209 26.496 23.533 26.664 ;
     RECT  23.315 61.152 23.605 61.752 ;
     RECT  23.533 26.496 23.609 26.808 ;
     RECT  23.209 42.672 23.609 43.704 ;
     RECT  23.363 45.744 23.609 48.024 ;
     RECT  23.353 59.04 23.612 59.256 ;
     RECT  23.609 26.64 23.641 26.808 ;
     RECT  23.365 31.968 23.645 31.992 ;
     RECT  23.569 19.584 23.681 19.608 ;
     RECT  23.612 58.656 23.699 59.256 ;
     RECT  23.497 20.832 23.753 20.952 ;
     RECT  23.641 26.64 23.753 26.856 ;
     RECT  23.437 40.032 23.753 40.392 ;
     RECT  23.669 57.504 23.753 57.528 ;
     RECT  23.753 20.928 23.821 20.952 ;
     RECT  23.317 35.52 23.821 35.736 ;
     RECT  23.753 26.64 23.825 26.808 ;
     RECT  23.756 22.992 23.843 23.016 ;
     RECT  23.756 53.76 23.843 53.784 ;
     RECT  23.677 55.968 23.857 55.992 ;
     RECT  23.677 4.224 23.893 4.248 ;
     RECT  23.821 20.928 23.933 21.048 ;
     RECT  23.605 60.816 23.939 61.752 ;
     RECT  23.933 20.928 23.969 20.952 ;
     RECT  23.857 55.92 23.969 55.992 ;
     RECT  23.893 52.992 23.977 53.016 ;
     RECT  23.821 35.52 23.98 36.504 ;
     RECT  23.893 4.224 24.005 4.488 ;
     RECT  23.699 59.04 24.041 59.256 ;
     RECT  24.001 29.232 24.085 29.256 ;
     RECT  24.085 29.232 24.113 29.544 ;
     RECT  24.113 29.52 24.172 29.544 ;
     RECT  22.709 10.656 24.217 10.68 ;
     RECT  23.941 8.448 24.257 8.472 ;
     RECT  22.889 5.856 24.277 6.024 ;
     RECT  24.217 10.56 24.289 11.496 ;
     RECT  24.005 4.224 24.329 4.248 ;
     RECT  24.277 5.232 24.364 6.024 ;
     RECT  23.98 35.712 24.371 36.504 ;
     RECT  23.609 43.68 24.389 43.704 ;
     RECT  24.361 44.928 24.389 44.952 ;
     RECT  23.969 55.968 24.397 55.992 ;
     RECT  24.325 37.584 24.412 37.608 ;
     RECT  24.109 7.44 24.433 7.464 ;
     RECT  23.893 18.96 24.437 19.368 ;
     RECT  23.141 14.352 24.469 14.472 ;
     RECT  24.389 43.68 24.473 44.952 ;
     RECT  24.145 51.936 24.505 51.96 ;
     RECT  24.433 31.104 24.517 31.128 ;
     RECT  24.289 10.368 24.541 11.496 ;
     RECT  24.437 18.96 24.545 19.32 ;
     RECT  24.469 14.352 24.577 14.712 ;
     RECT  23.939 61.632 24.577 61.752 ;
     RECT  24.469 62.784 24.577 62.808 ;
     RECT  24.505 51.936 24.589 52.392 ;
     RECT  24.364 5.856 24.613 6.024 ;
     RECT  24.433 7.248 24.613 7.464 ;
     RECT  24.541 10.368 24.653 11.688 ;
     RECT  24.473 43.68 24.668 43.704 ;
     RECT  23.285 15.984 24.685 16.152 ;
     RECT  23.609 46.032 24.685 48.024 ;
     RECT  24.289 49.536 24.685 49.56 ;
     RECT  24.613 5.856 24.7 7.464 ;
     RECT  23.308 50.832 24.757 50.856 ;
     RECT  24.589 51.936 24.757 52.152 ;
     RECT  24.653 10.368 24.761 10.68 ;
     RECT  24.073 41.904 24.764 41.928 ;
     RECT  24.577 61.632 24.764 62.808 ;
     RECT  24.577 14.352 24.797 14.808 ;
     RECT  24.473 44.928 24.829 44.952 ;
     RECT  24.685 46.032 24.829 49.56 ;
     RECT  24.668 43.248 24.833 43.704 ;
     RECT  24.764 61.632 24.851 63.528 ;
     RECT  24.829 44.928 24.941 49.56 ;
     RECT  24.397 55.968 24.941 56.04 ;
     RECT  24.797 14.352 25.043 14.472 ;
     RECT  24.7 7.248 25.045 7.464 ;
     RECT  24.041 59.04 25.117 59.064 ;
     RECT  24.073 60.048 25.117 60.072 ;
     RECT  25.043 14.352 25.121 14.424 ;
     RECT  24.505 57.6 25.121 57.768 ;
     RECT  24.371 35.712 25.141 36.36 ;
     RECT  24.757 50.832 25.149 52.152 ;
     RECT  25.1 38.112 25.187 38.136 ;
     RECT  25.121 57.744 25.187 57.768 ;
     RECT  25.045 22.032 25.189 22.056 ;
     RECT  25.117 54.048 25.225 54.072 ;
     RECT  25.148 39.504 25.235 39.528 ;
     RECT  24.653 11.664 25.297 11.688 ;
     RECT  25.149 50.832 25.301 51.672 ;
     RECT  25.189 22.032 25.333 22.248 ;
     RECT  24.764 41.376 25.34 41.928 ;
     RECT  24.833 43.584 25.373 43.704 ;
     RECT  25.34 41.376 25.427 42.456 ;
     RECT  24.761 10.656 25.445 10.68 ;
     RECT  24.941 44.928 25.445 47.736 ;
     RECT  25.388 9.024 25.475 9.048 ;
     RECT  25.225 54.048 25.477 54.552 ;
     RECT  25.141 35.232 25.525 36.36 ;
     RECT  25.477 53.76 25.564 54.552 ;
     RECT  24.757 20.352 25.585 20.376 ;
     RECT  25.117 59.04 25.589 60.072 ;
     RECT  25.525 35.232 25.612 36.552 ;
     RECT  25.297 39.744 25.619 39.864 ;
     RECT  25.117 1.536 25.621 1.56 ;
     RECT  25.589 59.04 25.621 59.88 ;
     RECT  25.564 54.048 25.657 54.552 ;
     RECT  23.569 64.56 25.657 64.584 ;
     RECT  25.333 21.888 25.661 22.248 ;
     RECT  25.297 24.528 25.667 24.552 ;
     RECT  25.58 32.592 25.667 32.616 ;
     RECT  25.661 21.936 25.669 22.248 ;
     RECT  25.621 1.536 25.693 2.184 ;
     RECT  25.297 11.664 25.697 12.264 ;
     RECT  25.301 51.648 25.697 51.672 ;
     RECT  25.621 58.128 25.697 59.88 ;
     RECT  25.669 21.936 25.763 23.016 ;
     RECT  25.763 22.032 25.805 23.016 ;
     RECT  25.693 1.44 25.873 2.184 ;
     RECT  25.805 22.224 25.913 23.016 ;
     RECT  25.441 56.304 26.017 56.328 ;
     RECT  25.913 22.848 26.021 23.016 ;
     RECT  25.427 41.376 26.021 41.928 ;
     RECT  24.941 48.72 26.125 49.56 ;
     RECT  24.851 61.632 26.125 62.808 ;
     RECT  25.657 54.048 26.14 55.272 ;
     RECT  26.101 10.512 26.188 10.536 ;
     RECT  25.873 3.408 26.233 3.432 ;
     RECT  26.149 38.16 26.236 38.184 ;
     RECT  25.873 1.44 26.243 2.28 ;
     RECT  26.156 8.976 26.243 9 ;
     RECT  26.125 61.632 26.243 63.336 ;
     RECT  26.233 3.408 26.3 3.912 ;
     RECT  26.3 3.408 26.341 4.2 ;
     RECT  25.045 7.248 26.389 7.896 ;
     RECT  26.14 55.248 26.449 55.272 ;
     RECT  26.017 56.256 26.449 56.328 ;
     RECT  24.685 15.792 26.593 16.152 ;
     RECT  26.588 33.072 26.636 33.096 ;
     RECT  26.269 34.224 26.636 34.248 ;
     RECT  26.593 15.456 26.665 16.152 ;
     RECT  25.585 20.352 26.665 20.472 ;
     RECT  25.765 31.104 26.665 31.128 ;
     RECT  26.629 51.936 26.701 52.248 ;
     RECT  25.121 14.352 26.737 14.376 ;
     RECT  26.665 15.456 26.737 16.344 ;
     RECT  26.305 13.344 26.773 13.368 ;
     RECT  26.737 14.352 26.773 16.344 ;
     RECT  25.697 58.128 26.773 59.496 ;
     RECT  25.657 64.56 26.773 64.632 ;
     RECT  24.7 5.856 26.809 6.024 ;
     RECT  26.389 7.248 26.809 7.944 ;
     RECT  24.545 18.96 26.809 18.984 ;
     RECT  26.021 41.376 26.809 41.448 ;
     RECT  26.773 64.512 26.813 64.632 ;
     RECT  23.825 26.64 26.828 26.664 ;
     RECT  26.125 48.72 26.828 49.992 ;
     RECT  26.14 54.048 26.828 54.072 ;
     RECT  26.413 11.424 26.845 11.448 ;
     RECT  26.845 11.424 26.917 11.976 ;
     RECT  26.773 13.344 26.917 16.344 ;
     RECT  26.665 30.864 26.953 31.128 ;
     RECT  27.013 9.504 27.02 9.528 ;
     RECT  26.701 51.936 27.02 52.296 ;
     RECT  26.773 58.128 27.02 59.544 ;
     RECT  26.828 26.544 27.061 26.664 ;
     RECT  25.445 44.928 27.061 47.16 ;
     RECT  26.828 48.72 27.061 50.088 ;
     RECT  27.025 25.152 27.109 25.176 ;
     RECT  26.243 1.44 27.248 2.184 ;
     RECT  26.341 3.408 27.248 4.296 ;
     RECT  26.809 5.856 27.248 7.944 ;
     RECT  27.02 9.504 27.248 10.44 ;
     RECT  26.917 11.424 27.248 16.344 ;
     RECT  26.809 18.144 27.248 18.984 ;
     RECT  26.665 20.352 27.248 20.712 ;
     RECT  26.021 22.848 27.248 22.872 ;
     RECT  27.109 24.48 27.248 25.176 ;
     RECT  27.061 26.544 27.248 26.808 ;
     RECT  26.953 30.864 27.248 31.224 ;
     RECT  26.636 33.072 27.248 34.248 ;
     RECT  25.612 35.232 27.248 36.36 ;
     RECT  25.619 39.744 27.248 39.768 ;
     RECT  26.809 41.136 27.248 41.448 ;
     RECT  25.373 43.68 27.248 43.704 ;
     RECT  27.061 44.928 27.248 50.088 ;
     RECT  27.02 51.408 27.248 52.296 ;
     RECT  26.828 53.28 27.248 54.072 ;
     RECT  26.449 55.248 27.248 56.328 ;
     RECT  27.02 57.456 27.248 59.544 ;
     RECT  26.243 61.632 27.248 63.096 ;
     RECT  26.813 64.512 27.248 64.584 ;
     RECT  27.248 0.528 27.352 64.584 ;
     RECT  27.352 0.798 27.544 64.584 ;
     RECT  27.544 7.872 27.683 9.624 ;
     RECT  27.544 30.192 27.683 31.368 ;
     RECT  27.544 57.024 27.683 59.208 ;
     RECT  27.683 7.872 27.713 9.144 ;
     RECT  27.544 23.616 27.713 24.264 ;
     RECT  27.544 50.784 27.713 50.856 ;
     RECT  27.544 15.696 27.721 17.016 ;
     RECT  27.713 7.872 27.749 7.992 ;
     RECT  27.544 39.36 27.749 39.816 ;
     RECT  27.749 7.872 27.779 7.896 ;
     RECT  27.544 10.944 27.785 14.712 ;
     RECT  27.544 51.888 27.785 53.352 ;
     RECT  27.683 30.192 27.821 30.888 ;
     RECT  27.713 9.12 27.893 9.144 ;
     RECT  27.544 55.44 27.923 55.464 ;
     RECT  27.544 60.864 27.929 63.432 ;
     RECT  27.683 57.072 28.012 59.208 ;
     RECT  27.749 39.36 28.037 39.384 ;
     RECT  27.785 51.984 28.145 52.296 ;
     RECT  27.544 19.92 28.163 20.76 ;
     RECT  27.544 42.528 28.204 49.56 ;
     RECT  28.163 20.16 28.217 20.76 ;
     RECT  28.145 51.984 28.217 52.248 ;
     RECT  27.544 38.112 28.259 38.136 ;
     RECT  27.713 50.784 28.259 50.808 ;
     RECT  27.544 3.6 28.289 3.96 ;
     RECT  27.544 25.584 28.289 27.624 ;
     RECT  27.544 35.472 28.361 36.84 ;
     RECT  28.289 25.584 28.499 25.608 ;
     RECT  27.544 32.592 28.499 32.616 ;
     RECT  28.361 35.712 28.505 36.84 ;
     RECT  27.544 33.696 28.549 33.72 ;
     RECT  27.544 1.44 28.556 2.28 ;
     RECT  27.544 18.864 28.577 18.888 ;
     RECT  27.929 60.864 28.588 63.336 ;
     RECT  28.556 1.44 28.604 2.328 ;
     RECT  27.785 14.352 28.609 14.712 ;
     RECT  27.721 15.696 28.609 16.92 ;
     RECT  28.604 1.296 28.643 2.328 ;
     RECT  28.505 36.384 28.652 36.84 ;
     RECT  27.713 23.616 28.681 24.168 ;
     RECT  28.012 57.072 28.685 59.064 ;
     RECT  28.652 36.384 28.739 37.608 ;
     RECT  28.217 51.984 28.739 52.008 ;
     RECT  28.289 3.888 28.741 3.96 ;
     RECT  27.544 5.184 28.741 6.888 ;
     RECT  28.204 48.672 28.741 49.56 ;
     RECT  28.741 3.888 28.789 6.888 ;
     RECT  28.681 23.568 28.789 24.168 ;
     RECT  27.544 41.136 28.793 41.16 ;
     RECT  28.685 57.072 28.793 57.768 ;
     RECT  28.741 48.672 28.828 49.896 ;
     RECT  28.217 20.16 28.829 20.184 ;
     RECT  28.789 3.888 28.844 6.936 ;
     RECT  28.609 14.352 28.883 16.92 ;
     RECT  27.821 30.864 28.897 30.888 ;
     RECT  28.844 3.888 28.931 7.128 ;
     RECT  28.289 26.64 28.937 27.624 ;
     RECT  28.789 23.568 28.973 24.504 ;
     RECT  28.204 42.528 28.973 47.688 ;
     RECT  28.793 57.072 28.973 57.72 ;
     RECT  28.931 3.888 29.009 6.936 ;
     RECT  27.785 10.944 29.027 13.128 ;
     RECT  28.897 30.864 29.036 31.08 ;
     RECT  28.549 33.312 29.045 33.72 ;
     RECT  29.009 4.464 29.075 6.936 ;
     RECT  28.717 21.168 29.084 21.384 ;
     RECT  29.084 21.168 29.113 21.768 ;
     RECT  28.973 23.568 29.117 23.64 ;
     RECT  29.036 30.864 29.123 31.56 ;
     RECT  28.739 36.384 29.123 36.84 ;
     RECT  28.573 29.664 29.125 29.688 ;
     RECT  29.123 30.864 29.125 31.08 ;
     RECT  29.075 4.56 29.189 6.936 ;
     RECT  28.588 61.44 29.189 63.336 ;
     RECT  29.113 21.168 29.197 22.152 ;
     RECT  29.117 23.616 29.261 23.64 ;
     RECT  29.045 33.648 29.261 33.72 ;
     RECT  29.123 36.624 29.261 36.84 ;
     RECT  28.837 9.36 29.269 9.384 ;
     RECT  29.197 21.168 29.293 21.528 ;
     RECT  29.027 11.424 29.297 13.128 ;
     RECT  29.189 61.488 29.297 63.336 ;
     RECT  29.221 51.888 29.308 51.912 ;
     RECT  29.269 8.832 29.317 9.384 ;
     RECT  29.317 8.832 29.356 9.528 ;
     RECT  28.883 14.352 29.369 16.344 ;
     RECT  28.973 44.832 29.369 47.688 ;
     RECT  29.297 61.488 29.404 63.096 ;
     RECT  29.356 9.504 29.405 9.528 ;
     RECT  28.973 42.528 29.437 43.848 ;
     RECT  29.261 33.696 29.545 33.72 ;
     RECT  29.261 36.624 29.548 36.648 ;
     RECT  28.643 1.296 29.564 2.136 ;
     RECT  29.297 11.712 29.612 13.128 ;
     RECT  29.564 1.248 29.651 2.136 ;
     RECT  29.437 42.192 29.651 43.848 ;
     RECT  29.612 11.712 29.653 13.32 ;
     RECT  29.369 14.352 29.653 14.376 ;
     RECT  29.125 29.664 29.657 31.08 ;
     RECT  28.789 54.672 29.689 55.32 ;
     RECT  29.653 11.712 29.699 14.376 ;
     RECT  28.828 48.672 29.729 49.848 ;
     RECT  29.653 10.08 29.737 10.104 ;
     RECT  29.651 1.968 29.756 2.136 ;
     RECT  29.689 54.672 29.773 55.56 ;
     RECT  29.617 27.888 29.797 27.912 ;
     RECT  29.545 33.696 29.797 34.152 ;
     RECT  28.973 57.072 29.948 57.528 ;
     RECT  28.685 58.8 29.948 59.064 ;
     RECT  29.729 48.672 29.977 49.56 ;
     RECT  28.753 25.536 29.989 25.56 ;
     RECT  28.937 26.64 29.989 26.664 ;
     RECT  29.651 42.288 29.996 43.848 ;
     RECT  29.369 44.832 29.996 47.16 ;
     RECT  29.189 4.56 30.049 6.024 ;
     RECT  29.989 25.536 30.076 26.664 ;
     RECT  29.941 39.168 30.121 39.192 ;
     RECT  27.785 53.328 30.121 53.352 ;
     RECT  29.948 57.072 30.133 59.064 ;
     RECT  30.133 38.16 30.157 38.184 ;
     RECT  30.076 25.536 30.161 25.56 ;
     RECT  29.773 54.672 30.161 55.512 ;
     RECT  30.133 57.072 30.22 59.784 ;
     RECT  30.121 51.984 30.227 53.352 ;
     RECT  30.161 54.672 30.227 54.888 ;
     RECT  29.404 61.488 30.229 61.752 ;
     RECT  29.756 1.968 30.233 2.28 ;
     RECT  30.121 40.608 30.269 40.632 ;
     RECT  30.049 4.416 30.301 6.024 ;
     RECT  29.657 29.664 30.305 29.688 ;
     RECT  30.229 50.544 30.316 50.568 ;
     RECT  30.22 57.072 30.364 59.64 ;
     RECT  29.699 11.712 30.428 12.504 ;
     RECT  30.229 61.104 30.449 61.752 ;
     RECT  30.157 37.632 30.469 38.184 ;
     RECT  30.476 40.848 30.481 40.872 ;
     RECT  30.121 24.288 30.517 24.312 ;
     RECT  30.229 22.992 30.521 23.016 ;
     RECT  30.469 37.584 30.556 38.184 ;
     RECT  30.121 39.168 30.563 39.384 ;
     RECT  30.481 40.848 30.563 41.16 ;
     RECT  30.563 41.136 30.659 41.16 ;
     RECT  29.699 14.208 30.661 14.376 ;
     RECT  29.797 33.696 30.661 34.2 ;
     RECT  29.797 27.888 30.665 27.96 ;
     RECT  30.661 13.584 30.697 14.376 ;
     RECT  30.301 4.416 30.701 6.072 ;
     RECT  30.428 10.464 30.701 12.504 ;
     RECT  29.404 62.976 30.701 63.096 ;
     RECT  30.701 10.608 30.707 12.504 ;
     RECT  30.364 58.416 30.707 59.64 ;
     RECT  30.517 24.192 30.709 24.312 ;
     RECT  29.996 42.288 30.725 47.16 ;
     RECT  29.369 15.696 30.733 16.344 ;
     RECT  30.563 39.216 30.737 39.384 ;
     RECT  30.668 2.304 30.755 2.328 ;
     RECT  30.076 26.64 30.757 26.664 ;
     RECT  30.701 4.416 30.769 4.728 ;
     RECT  30.697 13.488 30.769 14.376 ;
     RECT  29.293 21.12 30.769 21.528 ;
     RECT  29.657 30.864 30.769 31.08 ;
     RECT  27.544 64.512 30.769 64.584 ;
     RECT  30.665 27.888 30.773 27.912 ;
     RECT  30.709 24.192 30.796 24.456 ;
     RECT  30.733 15.696 30.805 16.392 ;
     RECT  30.445 17.952 30.805 17.976 ;
     RECT  30.227 52.224 30.805 53.352 ;
     RECT  30.701 63.024 30.805 63.096 ;
     RECT  30.769 64.176 30.805 64.584 ;
     RECT  30.364 57.072 30.809 57.432 ;
     RECT  30.661 33.696 30.844 34.968 ;
     RECT  29.977 48.48 30.877 49.56 ;
     RECT  30.701 5.952 30.881 6.072 ;
     RECT  29.185 19.392 30.881 19.416 ;
     RECT  30.805 52.224 30.881 53.4 ;
     RECT  30.844 33.696 30.901 34.2 ;
     RECT  30.805 9.552 30.908 9.576 ;
     RECT  30.769 13.488 30.913 14.472 ;
     RECT  30.805 15.696 30.913 17.976 ;
     RECT  30.881 6.048 30.953 6.072 ;
     RECT  30.913 13.488 30.985 17.976 ;
     RECT  30.901 33.12 30.988 34.2 ;
     RECT  30.908 9.36 30.995 9.576 ;
     RECT  30.809 57.072 31.061 57.336 ;
     RECT  30.757 26.64 31.093 26.856 ;
     RECT  30.769 54.624 31.093 54.648 ;
     RECT  31.057 55.968 31.093 55.992 ;
     RECT  30.796 24.192 31.097 24.312 ;
     RECT  30.995 9.552 31.139 9.576 ;
     RECT  31.093 26.64 31.18 27.576 ;
     RECT  30.881 52.992 31.201 53.4 ;
     RECT  31.093 54.432 31.201 54.648 ;
     RECT  30.769 3.984 31.205 4.728 ;
     RECT  31.093 55.968 31.205 56.328 ;
     RECT  30.985 13.488 31.241 18.168 ;
     RECT  30.707 10.752 31.277 12.504 ;
     RECT  30.877 48.48 31.277 50.376 ;
     RECT  30.805 1.296 31.333 1.32 ;
     RECT  30.769 30.864 31.333 31.272 ;
     RECT  31.148 35.472 31.333 35.544 ;
     RECT  31.241 17.952 31.349 18.168 ;
     RECT  30.707 58.704 31.349 59.64 ;
     RECT  30.988 33.888 31.385 34.2 ;
     RECT  31.333 1.248 31.42 1.32 ;
     RECT  31.205 4.176 31.42 4.728 ;
     RECT  30.737 39.36 31.421 39.384 ;
     RECT  30.725 41.232 31.421 47.16 ;
     RECT  31.385 33.888 31.427 34.152 ;
     RECT  31.421 41.232 31.457 42.84 ;
     RECT  31.42 4.416 31.493 4.728 ;
     RECT  31.349 17.952 31.493 17.976 ;
     RECT  31.333 30.864 31.601 32.04 ;
     RECT  31.621 51.984 31.669 52.008 ;
     RECT  30.769 20.976 31.705 21.528 ;
     RECT  30.449 61.632 31.772 61.752 ;
     RECT  30.805 63.024 31.772 64.584 ;
     RECT  31.705 3.024 31.813 3.048 ;
     RECT  31.333 35.472 31.82 36.408 ;
     RECT  31.493 4.704 31.849 4.728 ;
     RECT  31.772 61.632 31.859 64.584 ;
     RECT  31.705 20.976 31.885 22.296 ;
     RECT  31.18 26.64 31.993 26.808 ;
     RECT  31.993 26.544 32.065 26.808 ;
     RECT  32.065 26.352 32.101 26.808 ;
     RECT  31.349 59.04 32.101 59.64 ;
     RECT  32.101 26.256 32.209 26.808 ;
     RECT  31.601 32.016 32.245 32.04 ;
     RECT  31.061 57.312 32.396 57.336 ;
     RECT  32.396 57.312 32.453 57.96 ;
     RECT  31.42 1.296 32.485 1.32 ;
     RECT  31.849 4.704 32.485 5.016 ;
     RECT  32.341 6.144 32.485 6.168 ;
     RECT  31.885 20.976 32.492 22.536 ;
     RECT  32.485 4.704 32.497 6.168 ;
     RECT  32.209 7.392 32.497 7.416 ;
     RECT  32.497 4.704 32.533 7.416 ;
     RECT  32.209 10.32 32.569 10.344 ;
     RECT  31.201 52.992 32.605 54.648 ;
     RECT  31.241 13.488 32.641 16.392 ;
     RECT  32.485 1.296 32.648 1.464 ;
     RECT  31.813 2.976 32.648 3.048 ;
     RECT  32.533 4.224 32.648 7.416 ;
     RECT  32.533 9.264 32.648 9.288 ;
     RECT  32.569 10.32 32.648 10.44 ;
     RECT  31.277 11.616 32.648 12.504 ;
     RECT  32.641 13.488 32.648 16.68 ;
     RECT  32.485 18.816 32.648 18.84 ;
     RECT  32.492 20.976 32.648 22.728 ;
     RECT  31.097 24.192 32.648 24.216 ;
     RECT  32.209 26.256 32.648 26.856 ;
     RECT  32.533 28.176 32.648 28.2 ;
     RECT  31.697 30.192 32.648 30.84 ;
     RECT  32.245 32.016 32.648 32.568 ;
     RECT  31.427 34.08 32.648 34.152 ;
     RECT  31.82 35.472 32.648 36.6 ;
     RECT  30.556 37.632 32.648 38.184 ;
     RECT  31.633 40.608 32.648 40.632 ;
     RECT  31.457 41.712 32.648 42.84 ;
     RECT  31.421 43.824 32.648 47.16 ;
     RECT  31.277 48.48 32.648 49.992 ;
     RECT  31.669 51.072 32.648 52.008 ;
     RECT  32.605 52.992 32.648 54.696 ;
     RECT  31.205 55.968 32.648 56.088 ;
     RECT  32.453 57.264 32.648 57.96 ;
     RECT  32.101 59.04 32.648 59.832 ;
     RECT  31.859 61.632 32.648 64.488 ;
     RECT  32.648 0.528 32.723 64.488 ;
     RECT  32.723 0.528 32.752 64.392 ;
     RECT  32.752 0.798 32.944 64.392 ;
     RECT  32.944 5.568 33.059 7.944 ;
     RECT  32.944 33.024 33.059 33.048 ;
     RECT  32.944 57.216 33.059 64.392 ;
     RECT  33.059 63.84 33.077 64.248 ;
     RECT  32.944 22.8 33.113 22.824 ;
     RECT  32.944 26.208 33.113 26.808 ;
     RECT  33.059 57.216 33.148 62.76 ;
     RECT  32.944 14.448 33.155 17.64 ;
     RECT  33.077 63.84 33.365 64.104 ;
     RECT  32.944 40.944 33.437 49.56 ;
     RECT  32.944 55.968 33.437 56.232 ;
     RECT  33.437 55.968 33.473 56.088 ;
     RECT  33.365 63.888 33.491 64.104 ;
     RECT  32.944 34.08 33.509 35.832 ;
     RECT  33.473 56.064 33.509 56.088 ;
     RECT  33.437 43.824 33.545 49.56 ;
     RECT  33.509 34.08 33.581 34.44 ;
     RECT  33.491 64.08 33.587 64.104 ;
     RECT  32.944 28.992 33.635 29.016 ;
     RECT  32.944 54.672 33.635 54.792 ;
     RECT  32.944 52.8 33.683 53.112 ;
     RECT  33.148 57.216 33.683 62.088 ;
     RECT  32.944 37.68 33.689 38.808 ;
     RECT  33.683 57.216 33.689 60.408 ;
     RECT  33.689 58.464 33.725 60.408 ;
     RECT  32.944 18.816 33.797 19.416 ;
     RECT  33.155 14.448 33.827 16.92 ;
     RECT  33.581 34.08 33.869 34.104 ;
     RECT  32.944 2.928 33.875 2.952 ;
     RECT  33.545 44.016 33.875 49.56 ;
     RECT  33.725 58.464 33.923 58.488 ;
     RECT  33.059 5.568 33.971 7.416 ;
     RECT  33.725 59.76 33.977 60.408 ;
     RECT  32.944 1.248 34.009 1.416 ;
     RECT  33.683 61.488 34.013 62.088 ;
     RECT  33.509 35.424 34.049 35.832 ;
     RECT  32.944 51.36 34.081 51.48 ;
     RECT  34.081 51.36 34.117 51.528 ;
     RECT  33.977 59.76 34.156 60.072 ;
     RECT  33.437 40.944 34.157 42.552 ;
     RECT  34.049 35.424 34.193 35.544 ;
     RECT  34.157 40.944 34.204 41.256 ;
     RECT  32.944 9.36 34.211 13.128 ;
     RECT  33.689 57.216 34.211 57.336 ;
     RECT  33.875 44.448 34.229 49.56 ;
     RECT  34.124 32.208 34.261 32.232 ;
     RECT  34.156 59.76 34.265 59.784 ;
     RECT  33.827 14.64 34.301 16.92 ;
     RECT  34.193 35.424 34.337 35.496 ;
     RECT  34.013 61.488 34.337 61.752 ;
     RECT  34.261 31.776 34.348 32.232 ;
     RECT  33.113 26.208 34.405 26.616 ;
     RECT  34.337 61.488 34.445 61.656 ;
     RECT  34.009 1.248 34.481 1.992 ;
     RECT  34.405 26.208 34.585 26.664 ;
     RECT  34.508 32.736 34.595 32.76 ;
     RECT  34.441 39.552 34.597 39.576 ;
     RECT  33.925 30.576 34.657 30.6 ;
     RECT  34.157 42.528 34.657 42.552 ;
     RECT  33.971 7.056 34.661 7.416 ;
     RECT  34.445 61.488 34.661 61.608 ;
     RECT  34.597 39.552 34.684 39.768 ;
     RECT  34.117 51.36 34.693 51.72 ;
     RECT  34.211 10.128 34.697 13.128 ;
     RECT  34.657 29.808 34.729 30.6 ;
     RECT  34.481 1.248 34.739 1.848 ;
     RECT  33.797 19.392 34.765 19.416 ;
     RECT  34.693 51.264 34.765 51.72 ;
     RECT  34.229 48.384 34.78 49.56 ;
     RECT  34.621 40.896 34.787 40.92 ;
     RECT  34.78 48.432 34.789 49.56 ;
     RECT  34.765 50.832 34.789 51.72 ;
     RECT  34.684 39.552 34.801 39.576 ;
     RECT  34.765 19.008 34.805 19.416 ;
     RECT  33.689 37.68 34.837 37.8 ;
     RECT  34.837 36.864 34.841 37.8 ;
     RECT  34.693 21.504 34.873 21.528 ;
     RECT  34.729 34.464 34.876 35.016 ;
     RECT  34.301 14.64 34.877 16.68 ;
     RECT  34.585 26.208 34.877 26.808 ;
     RECT  34.796 3.936 34.883 3.96 ;
     RECT  34.657 42.528 34.909 42.888 ;
     RECT  34.729 29.808 34.913 30.696 ;
     RECT  34.801 39.072 34.933 39.576 ;
     RECT  34.873 21.264 34.945 21.528 ;
     RECT  34.789 9.072 34.985 9.096 ;
     RECT  33.635 54.672 34.988 54.696 ;
     RECT  34.909 56.16 34.988 56.184 ;
     RECT  33.683 52.992 35.017 53.112 ;
     RECT  34.988 54.672 35.017 56.184 ;
     RECT  34.933 38.64 35.02 39.576 ;
     RECT  34.229 44.448 35.036 47.16 ;
     RECT  34.789 48.432 35.053 51.72 ;
     RECT  34.211 57.312 35.053 57.336 ;
     RECT  35.017 52.992 35.075 56.184 ;
     RECT  34.585 28.512 35.089 28.536 ;
     RECT  35.075 52.992 35.165 54.696 ;
     RECT  34.841 36.864 35.189 36.888 ;
     RECT  35.089 27.744 35.221 28.536 ;
     RECT  34.913 29.808 35.221 29.832 ;
     RECT  33.973 5.328 35.237 5.496 ;
     RECT  35.036 44.304 35.269 47.16 ;
     RECT  34.945 20.832 35.273 21.528 ;
     RECT  35.189 36.384 35.273 36.888 ;
     RECT  35.221 62.832 35.308 62.856 ;
     RECT  35.221 27.744 35.309 29.832 ;
     RECT  35.228 31.68 35.315 31.704 ;
     RECT  35.269 44.304 35.353 47.352 ;
     RECT  34.805 19.008 35.363 19.032 ;
     RECT  35.237 5.328 35.381 5.352 ;
     RECT  35.309 27.744 35.381 28.536 ;
     RECT  35.309 29.808 35.381 29.832 ;
     RECT  35.353 44.304 35.441 47.304 ;
     RECT  35.075 56.16 35.453 56.184 ;
     RECT  34.909 42.528 35.521 43.032 ;
     RECT  35.441 44.016 35.521 47.304 ;
     RECT  35.521 42.528 35.525 47.304 ;
     RECT  35.053 48.432 35.555 51.768 ;
     RECT  34.876 34.752 35.561 35.016 ;
     RECT  34.739 1.392 35.564 1.848 ;
     RECT  35.381 28.512 35.597 28.536 ;
     RECT  34.909 61.344 35.633 61.416 ;
     RECT  35.525 44.496 35.699 47.304 ;
     RECT  35.273 20.832 35.705 20.856 ;
     RECT  35.525 42.528 35.773 43.368 ;
     RECT  35.165 54.672 35.777 54.696 ;
     RECT  35.804 60.144 35.845 60.168 ;
     RECT  35.845 40.944 35.881 40.968 ;
     RECT  35.555 48.432 35.885 49.608 ;
     RECT  35.773 42.288 35.891 43.368 ;
     RECT  35.885 48.48 35.891 49.608 ;
     RECT  35.845 59.76 35.891 60.168 ;
     RECT  35.561 34.752 35.917 34.872 ;
     RECT  35.891 59.76 35.939 59.784 ;
     RECT  35.053 23.568 35.953 23.592 ;
     RECT  35.053 57.312 35.953 57.576 ;
     RECT  34.877 14.64 35.957 16.392 ;
     RECT  35.273 36.864 35.957 36.888 ;
     RECT  35.02 39.072 35.957 39.576 ;
     RECT  35.953 57.312 36.025 58.152 ;
     RECT  35.881 40.704 36.029 40.968 ;
     RECT  35.957 15.696 36.035 16.392 ;
     RECT  35.917 34.176 36.035 34.872 ;
     RECT  36.029 40.704 36.037 40.728 ;
     RECT  34.877 26.208 36.061 26.664 ;
     RECT  36.025 57.312 36.061 58.392 ;
     RECT  35.564 1.392 36.172 2.28 ;
     RECT  35.891 42.288 36.209 43.272 ;
     RECT  35.953 23.568 36.236 23.736 ;
     RECT  35.564 32.256 36.281 32.28 ;
     RECT  36.037 40.32 36.281 40.728 ;
     RECT  36.061 57.312 36.281 58.488 ;
     RECT  36.281 58.368 36.317 58.488 ;
     RECT  36.236 23.568 36.323 24.072 ;
     RECT  36.317 58.368 36.323 58.392 ;
     RECT  35.555 50.592 36.325 51.768 ;
     RECT  36.277 31.152 36.364 31.176 ;
     RECT  35.699 44.496 36.371 47.208 ;
     RECT  35.165 52.992 36.38 53.64 ;
     RECT  36.209 42.72 36.389 43.272 ;
     RECT  36.325 56.064 36.412 56.088 ;
     RECT  34.697 10.128 36.457 12.792 ;
     RECT  36.389 43.248 36.461 43.272 ;
     RECT  36.371 44.496 36.467 47.16 ;
     RECT  36.38 52.992 36.467 53.688 ;
     RECT  35.845 8.544 36.469 8.568 ;
     RECT  36.457 10.128 36.469 13.608 ;
     RECT  36.277 37.584 36.497 37.608 ;
     RECT  35.845 19.488 36.517 19.944 ;
     RECT  36.172 1.488 36.524 2.28 ;
     RECT  36.467 44.496 36.533 45.816 ;
     RECT  36.061 26.208 36.569 27.528 ;
     RECT  36.277 61.872 36.593 61.896 ;
     RECT  35.953 22.224 36.601 22.344 ;
     RECT  36.517 18.768 36.605 19.944 ;
     RECT  36.524 1.488 36.611 2.328 ;
     RECT  36.421 4.464 36.637 4.488 ;
     RECT  34.661 7.056 36.637 7.128 ;
     RECT  36.469 8.544 36.637 13.608 ;
     RECT  36.593 61.872 36.637 62.664 ;
     RECT  36.611 1.488 36.677 1.704 ;
     RECT  36.637 61.008 36.677 62.664 ;
     RECT  36.035 34.848 36.713 34.872 ;
     RECT  36.677 61.008 36.721 61.8 ;
     RECT  36.637 7.056 36.745 13.608 ;
     RECT  36.605 19.488 36.745 19.944 ;
     RECT  36.745 6.864 36.785 13.608 ;
     RECT  36.323 23.568 36.821 23.736 ;
     RECT  36.637 4.464 36.853 4.92 ;
     RECT  35.891 48.48 36.853 49.56 ;
     RECT  35.957 39.072 36.917 39.096 ;
     RECT  36.745 19.488 36.925 20.328 ;
     RECT  36.601 22.224 36.925 22.584 ;
     RECT  36.908 31.2 36.995 31.224 ;
     RECT  36.569 26.208 36.997 26.568 ;
     RECT  36.853 48.24 36.997 49.56 ;
     RECT  36.925 19.488 37.037 22.584 ;
     RECT  36.821 23.568 37.037 23.592 ;
     RECT  36.533 44.592 37.037 45.816 ;
     RECT  36.785 6.864 37.043 12.84 ;
     RECT  37.037 19.488 37.043 20.904 ;
     RECT  36.889 28.032 37.043 29.016 ;
     RECT  36.908 37.68 37.045 37.704 ;
     RECT  36.917 38.976 37.045 39.096 ;
     RECT  35.957 14.64 37.105 14.664 ;
     RECT  36.709 2.736 37.177 2.856 ;
     RECT  37.093 34.944 37.393 35.256 ;
     RECT  37.357 36.336 37.393 36.36 ;
     RECT  37.393 41.376 37.465 41.4 ;
     RECT  36.281 40.32 37.501 40.344 ;
     RECT  37.465 41.376 37.501 41.448 ;
     RECT  37.037 45.024 37.501 45.816 ;
     RECT  36.467 47.088 37.501 47.16 ;
     RECT  37.501 40.32 37.573 41.448 ;
     RECT  36.281 57.312 37.573 57.336 ;
     RECT  36.325 51.216 37.609 51.768 ;
     RECT  36.467 52.992 37.609 53.64 ;
     RECT  37.045 37.68 37.621 39.096 ;
     RECT  37.501 45.024 37.621 47.16 ;
     RECT  36.997 48.192 37.621 49.56 ;
     RECT  36.908 33.648 37.645 33.672 ;
     RECT  37.609 51.216 37.645 53.64 ;
     RECT  37.621 45.024 37.669 49.56 ;
     RECT  37.645 51.216 37.669 54.456 ;
     RECT  37.141 31.344 37.813 31.656 ;
     RECT  37.645 33.6 37.813 33.672 ;
     RECT  37.393 34.944 37.813 36.36 ;
     RECT  37.704 43.296 37.861 43.32 ;
     RECT  37.621 37.632 37.909 39.096 ;
     RECT  36.721 61.44 37.909 61.8 ;
     RECT  36.677 1.68 38.048 1.704 ;
     RECT  37.177 2.736 38.048 3.336 ;
     RECT  36.853 4.464 38.048 5.016 ;
     RECT  37.043 6.864 38.048 7.416 ;
     RECT  37.043 8.976 38.048 9 ;
     RECT  37.043 10.32 38.048 12.84 ;
     RECT  37.105 14.304 38.048 14.664 ;
     RECT  36.035 15.696 38.048 16.344 ;
     RECT  37.043 19.488 38.048 19.608 ;
     RECT  37.043 20.832 38.048 20.904 ;
     RECT  37.037 22.56 38.048 22.584 ;
     RECT  37.909 23.952 38.048 23.976 ;
     RECT  36.997 26.16 38.048 26.568 ;
     RECT  37.043 28.032 38.048 28.056 ;
     RECT  37.813 31.344 38.048 32.04 ;
     RECT  37.813 33.6 38.048 36.36 ;
     RECT  37.909 37.584 38.048 39.096 ;
     RECT  37.573 40.32 38.048 41.976 ;
     RECT  37.861 43.296 38.048 43.848 ;
     RECT  37.669 45.024 38.048 54.456 ;
     RECT  37.609 56.064 38.048 56.088 ;
     RECT  37.573 57.312 38.048 58.248 ;
     RECT  37.537 59.856 38.048 59.88 ;
     RECT  37.909 61.392 38.048 61.8 ;
     RECT  38.048 0.528 38.152 64.272 ;
     RECT  38.152 0.798 38.344 64.002 ;
     RECT  38.344 39.984 38.369 47.208 ;
     RECT  38.344 1.248 38.483 1.272 ;
     RECT  38.344 7.056 38.483 13.608 ;
     RECT  38.344 21.072 38.483 21.96 ;
     RECT  38.344 25.44 38.483 27.672 ;
     RECT  38.344 59.712 38.483 61.704 ;
     RECT  38.369 42.768 38.485 47.208 ;
     RECT  38.483 59.712 38.485 59.88 ;
     RECT  38.369 39.984 38.513 41.784 ;
     RECT  38.513 39.984 38.531 40.44 ;
     RECT  38.344 29.088 38.572 29.256 ;
     RECT  38.344 56.544 38.585 58.248 ;
     RECT  38.485 59.856 38.585 59.88 ;
     RECT  38.344 33.024 38.621 34.968 ;
     RECT  38.344 2.304 38.693 3.912 ;
     RECT  38.344 36.048 38.693 39 ;
     RECT  38.585 58.032 38.729 58.248 ;
     RECT  38.483 61.44 38.729 61.704 ;
     RECT  38.344 48.48 38.765 53.592 ;
     RECT  38.344 30.576 38.771 30.6 ;
     RECT  38.765 48.48 38.771 53.256 ;
     RECT  38.513 41.664 38.801 41.784 ;
     RECT  38.344 15.696 38.837 18.216 ;
     RECT  38.621 33.024 38.837 33.672 ;
     RECT  38.585 56.544 38.837 56.712 ;
     RECT  38.344 54.864 38.873 55.464 ;
     RECT  38.621 34.704 38.963 34.968 ;
     RECT  38.873 54.864 39.011 54.888 ;
     RECT  38.344 23.904 39.017 23.928 ;
     RECT  38.483 7.056 39.053 8.568 ;
     RECT  38.344 5.232 39.059 5.592 ;
     RECT  38.483 9.744 39.059 13.608 ;
     RECT  38.963 34.944 39.059 34.968 ;
     RECT  38.729 61.68 39.1 61.704 ;
     RECT  38.693 37.584 39.125 39 ;
     RECT  39.053 8.496 39.155 8.568 ;
     RECT  38.344 19.248 39.155 19.272 ;
     RECT  38.483 26.304 39.161 27.672 ;
     RECT  38.837 56.544 39.197 56.568 ;
     RECT  38.485 42.768 39.244 46.104 ;
     RECT  38.693 3.888 39.299 3.912 ;
     RECT  38.572 29.088 39.329 29.112 ;
     RECT  39.059 10.32 39.341 13.608 ;
     RECT  39.244 43.344 39.347 46.104 ;
     RECT  38.693 2.304 39.377 2.328 ;
     RECT  39.329 28.032 39.395 29.112 ;
     RECT  38.837 33.024 39.404 33.048 ;
     RECT  39.395 28.032 39.413 28.488 ;
     RECT  39.125 37.584 39.443 38.184 ;
     RECT  39.341 10.32 39.449 11.688 ;
     RECT  39.161 26.304 39.485 26.952 ;
     RECT  39.404 32.832 39.491 33.048 ;
     RECT  38.837 17.568 39.517 18.216 ;
     RECT  38.344 14.592 39.553 14.664 ;
     RECT  38.837 15.696 39.553 16.536 ;
     RECT  39.341 12.72 39.625 13.608 ;
     RECT  39.553 14.592 39.625 16.536 ;
     RECT  39.491 33.024 39.635 33.048 ;
     RECT  38.693 36.048 39.661 36.072 ;
     RECT  39.661 36.048 39.697 36.456 ;
     RECT  39.347 43.776 39.697 46.104 ;
     RECT  38.485 47.184 39.697 47.208 ;
     RECT  39.644 57.984 39.731 58.008 ;
     RECT  39.485 26.304 39.737 26.904 ;
     RECT  39.737 26.304 39.809 26.568 ;
     RECT  38.771 48.48 39.809 53.016 ;
     RECT  39.697 43.776 39.827 47.208 ;
     RECT  39.827 47.184 39.829 47.208 ;
     RECT  39.827 43.776 39.875 46.104 ;
     RECT  39.697 35.856 39.881 36.456 ;
     RECT  39.805 59.28 39.889 59.304 ;
     RECT  39.809 48.48 39.917 51.768 ;
     RECT  39.877 23.568 39.925 23.592 ;
     RECT  39.875 43.776 39.925 45.816 ;
     RECT  38.483 21.072 39.971 21.672 ;
     RECT  39.809 26.304 39.98 26.328 ;
     RECT  39.971 21.072 39.985 21.096 ;
     RECT  39.925 30.72 40.012 30.744 ;
     RECT  39.925 43.92 40.012 45.816 ;
     RECT  39.517 17.568 40.025 18.264 ;
     RECT  39.98 25.824 40.067 26.328 ;
     RECT  39.98 55.104 40.067 55.128 ;
     RECT  38.531 39.984 40.093 40.344 ;
     RECT  39.625 12.72 40.097 16.536 ;
     RECT  39.443 38.112 40.129 38.184 ;
     RECT  39.829 47.184 40.165 47.4 ;
     RECT  39.917 48.48 40.165 49.56 ;
     RECT  39.925 22.8 40.169 23.592 ;
     RECT  40.076 33.84 40.172 33.864 ;
     RECT  40.093 39.984 40.201 40.44 ;
     RECT  40.169 22.8 40.241 23.064 ;
     RECT  40.172 33.84 40.259 34.248 ;
     RECT  40.093 42.288 40.268 42.36 ;
     RECT  39.913 2.256 40.273 2.28 ;
     RECT  39.155 8.496 40.277 8.52 ;
     RECT  40.165 47.184 40.277 49.56 ;
     RECT  40.201 39.984 40.309 41.256 ;
     RECT  40.268 42.288 40.309 42.408 ;
     RECT  39.985 20.4 40.381 21.096 ;
     RECT  40.309 39.984 40.381 42.408 ;
     RECT  40.309 59.52 40.393 60.12 ;
     RECT  39.053 7.056 40.453 7.128 ;
     RECT  40.025 18.192 40.453 18.264 ;
     RECT  40.453 6.912 40.489 7.128 ;
     RECT  40.405 61.872 40.492 61.896 ;
     RECT  40.489 6.912 40.525 7.176 ;
     RECT  40.417 4.464 40.529 4.488 ;
     RECT  40.508 25.008 40.595 25.032 ;
     RECT  40.273 1.536 40.597 2.28 ;
     RECT  40.556 32.64 40.597 32.664 ;
     RECT  40.259 33.84 40.597 34.104 ;
     RECT  40.381 20.208 40.637 21.096 ;
     RECT  40.497 58.176 40.643 58.44 ;
     RECT  40.597 32.64 40.673 34.104 ;
     RECT  40.643 58.176 40.691 58.2 ;
     RECT  39.059 5.472 40.705 5.592 ;
     RECT  40.129 38.112 40.709 38.664 ;
     RECT  40.277 47.184 40.709 49.368 ;
     RECT  40.393 59.52 40.732 59.544 ;
     RECT  40.453 18.192 40.741 18.792 ;
     RECT  40.673 32.64 40.741 33.912 ;
     RECT  40.597 1.536 40.781 2.952 ;
     RECT  40.669 55.92 40.781 55.944 ;
     RECT  40.709 47.184 40.813 49.224 ;
     RECT  40.525 6.816 40.849 7.176 ;
     RECT  40.789 61.632 40.876 61.656 ;
     RECT  39.809 52.992 40.885 53.016 ;
     RECT  40.381 39.888 40.892 42.408 ;
     RECT  39.449 10.896 40.933 11.688 ;
     RECT  40.097 12.72 40.933 12.792 ;
     RECT  40.012 44.928 40.949 45.816 ;
     RECT  40.813 46.848 40.949 49.224 ;
     RECT  40.933 10.896 40.957 12.792 ;
     RECT  39.917 51.312 40.961 51.768 ;
     RECT  40.892 38.832 40.993 42.408 ;
     RECT  40.097 14.112 41.02 16.536 ;
     RECT  40.741 18.192 41.027 19.08 ;
     RECT  40.741 32.112 41.027 33.912 ;
     RECT  40.993 38.832 41.029 42.552 ;
     RECT  40.012 43.92 41.029 43.944 ;
     RECT  39.413 28.032 41.033 28.056 ;
     RECT  40.961 51.312 41.065 51.528 ;
     RECT  40.849 6.816 41.105 7.416 ;
     RECT  40.417 29.04 41.173 29.064 ;
     RECT  40.705 5.472 41.177 5.64 ;
     RECT  41.029 38.832 41.213 43.944 ;
     RECT  41.02 14.64 41.221 16.536 ;
     RECT  41.027 18.192 41.221 18.264 ;
     RECT  40.949 44.928 41.249 49.224 ;
     RECT  41.221 14.64 41.285 18.264 ;
     RECT  39.881 36 41.285 36.456 ;
     RECT  41.285 14.736 41.308 18.264 ;
     RECT  41.308 14.736 41.357 16.536 ;
     RECT  41.213 42 41.363 43.944 ;
     RECT  40.241 23.04 41.42 23.064 ;
     RECT  41.249 44.928 41.461 45.816 ;
     RECT  41.357 14.784 41.501 16.536 ;
     RECT  41.42 22.464 41.507 23.064 ;
     RECT  40.067 26.304 41.533 26.328 ;
     RECT  41.461 44.592 41.545 45.816 ;
     RECT  41.213 38.832 41.573 40.968 ;
     RECT  41.173 8.592 41.603 8.616 ;
     RECT  41.065 50.736 41.605 51.528 ;
     RECT  41.308 17.712 41.609 18.264 ;
     RECT  40.637 20.208 41.645 20.472 ;
     RECT  41.173 28.992 41.645 29.064 ;
     RECT  41.645 20.448 41.681 20.472 ;
     RECT  40.781 2.832 41.701 2.952 ;
     RECT  41.605 50.64 41.701 51.528 ;
     RECT  41.249 46.8 41.713 49.224 ;
     RECT  40.885 52.992 41.857 53.112 ;
     RECT  41.701 50.592 41.891 51.528 ;
     RECT  40.849 37.632 41.893 37.656 ;
     RECT  41.857 25.104 41.941 25.128 ;
     RECT  40.957 10.176 41.948 12.792 ;
     RECT  41.893 37.584 41.98 37.656 ;
     RECT  41.948 10.176 42.005 13.08 ;
     RECT  41.027 32.592 42.005 33.912 ;
     RECT  42.005 13.056 42.035 13.08 ;
     RECT  40.781 1.536 42.037 1.656 ;
     RECT  41.701 2.832 42.037 3.432 ;
     RECT  41.713 46.8 42.037 49.512 ;
     RECT  41.645 29.04 42.101 29.064 ;
     RECT  41.363 42 42.113 43.56 ;
     RECT  41.965 19.44 42.131 19.464 ;
     RECT  41.98 37.632 42.133 37.656 ;
     RECT  41.285 36 42.145 36.408 ;
     RECT  41.891 51.312 42.145 51.528 ;
     RECT  41.857 52.992 42.145 53.304 ;
     RECT  41.857 54.384 42.145 54.408 ;
     RECT  42.005 10.176 42.149 11.928 ;
     RECT  42.073 34.752 42.157 34.776 ;
     RECT  42.113 42 42.172 42.6 ;
     RECT  41.177 5.472 42.173 5.496 ;
     RECT  42.037 46.8 42.179 50.184 ;
     RECT  42.173 4.512 42.181 5.496 ;
     RECT  41.609 18.192 42.181 18.264 ;
     RECT  42.145 35.904 42.181 36.408 ;
     RECT  42.145 51.312 42.181 53.304 ;
     RECT  42.145 54.384 42.181 54.456 ;
     RECT  42.037 56.208 42.181 56.232 ;
     RECT  42.101 29.04 42.221 29.352 ;
     RECT  42.181 18.192 42.229 18.312 ;
     RECT  42.181 4.512 42.257 5.736 ;
     RECT  42.181 51.312 42.265 54.792 ;
     RECT  42.181 13.104 42.289 13.32 ;
     RECT  42.229 18.192 42.316 18.504 ;
     RECT  42.037 1.536 42.325 3.432 ;
     RECT  41.533 26.304 42.329 27.048 ;
     RECT  41.545 44.976 42.401 45.816 ;
     RECT  42.265 51.312 42.437 53.16 ;
     RECT  42.401 45.024 42.473 45.816 ;
     RECT  42.289 13.104 42.541 13.368 ;
     RECT  42.181 56.208 42.541 56.808 ;
     RECT  42.005 32.592 42.565 32.952 ;
     RECT  41.605 61.872 42.565 61.896 ;
     RECT  41.501 15.696 42.572 16.536 ;
     RECT  42.316 18.192 42.572 18.264 ;
     RECT  42.541 55.824 42.577 56.808 ;
     RECT  42.325 0.576 42.613 3.432 ;
     RECT  42.133 37.632 42.613 38.04 ;
     RECT  42.613 37.632 42.668 38.184 ;
     RECT  41.105 6.816 42.721 7.176 ;
     RECT  42.572 15.696 42.757 18.264 ;
     RECT  41.573 39.312 42.757 40.968 ;
     RECT  42.565 60.912 42.757 61.896 ;
     RECT  42.793 8.736 42.901 8.76 ;
     RECT  42.613 0.528 42.997 3.432 ;
     RECT  42.901 8.736 42.997 9.48 ;
     RECT  41.507 23.04 42.997 23.064 ;
     RECT  42.997 8.496 43.045 9.48 ;
     RECT  42.757 20.16 43.117 20.184 ;
     RECT  43.045 8.4 43.153 9.48 ;
     RECT  42.668 37.632 43.153 38.232 ;
     RECT  42.757 39.312 43.153 41.016 ;
     RECT  42.757 15.312 43.261 18.264 ;
     RECT  42.997 22.32 43.292 23.064 ;
     RECT  43.225 24.144 43.292 24.168 ;
     RECT  43.292 22.32 43.297 24.168 ;
     RECT  42.181 34.8 43.325 36.408 ;
     RECT  43.153 37.632 43.325 41.016 ;
     RECT  43.153 8.4 43.333 9.864 ;
     RECT  42.149 10.896 43.333 11.928 ;
     RECT  43.261 15.216 43.333 18.264 ;
     RECT  43.297 22.32 43.333 24.216 ;
     RECT  42.329 26.304 43.333 26.856 ;
     RECT  42.565 32.16 43.333 32.952 ;
     RECT  42.172 42.192 43.333 42.6 ;
     RECT  43.117 43.632 43.333 43.656 ;
     RECT  42.473 45.696 43.333 45.816 ;
     RECT  42.179 46.8 43.333 47.304 ;
     RECT  42.179 48.672 43.333 50.184 ;
     RECT  42.997 0.192 43.337 3.432 ;
     RECT  43.333 48.672 43.369 50.328 ;
     RECT  42.437 51.312 43.369 53.016 ;
     RECT  43.337 0.528 43.448 3.432 ;
     RECT  42.257 5.472 43.448 5.736 ;
     RECT  42.721 6.816 43.448 7.416 ;
     RECT  43.333 8.4 43.448 11.928 ;
     RECT  42.541 13.104 43.448 13.56 ;
     RECT  43.333 15.024 43.448 18.264 ;
     RECT  43.117 20.16 43.448 20.616 ;
     RECT  43.333 22.32 43.448 24.408 ;
     RECT  43.333 26.016 43.448 26.856 ;
     RECT  42.221 29.328 43.448 29.352 ;
     RECT  43.333 30.48 43.448 30.504 ;
     RECT  43.333 31.488 43.448 32.952 ;
     RECT  43.325 34.8 43.448 41.016 ;
     RECT  43.333 42.192 43.448 43.656 ;
     RECT  43.333 45.696 43.448 47.304 ;
     RECT  43.369 48.672 43.448 53.016 ;
     RECT  42.265 54.336 43.448 54.792 ;
     RECT  42.577 55.824 43.448 56.856 ;
     RECT  42.469 59.76 43.448 59.784 ;
     RECT  42.757 60.912 43.448 62.28 ;
     RECT  43.448 0.528 43.552 64.272 ;
     RECT  43.552 0.624 43.744 64.002 ;
     RECT  43.744 10.992 43.859 11.688 ;
     RECT  43.744 25.92 43.859 26.808 ;
     RECT  43.744 44.64 43.859 44.664 ;
     RECT  43.744 29.52 43.907 29.976 ;
     RECT  43.744 0.624 43.913 3.624 ;
     RECT  43.744 8.736 43.913 9.96 ;
     RECT  43.744 13.68 43.921 18.312 ;
     RECT  43.744 23.04 43.921 24.168 ;
     RECT  43.859 26.016 43.955 26.664 ;
     RECT  43.913 0.96 43.985 3.624 ;
     RECT  43.744 6.912 43.985 7.416 ;
     RECT  43.921 14.16 43.985 18.312 ;
     RECT  43.985 18 43.993 18.312 ;
     RECT  43.913 8.736 44.021 9.192 ;
     RECT  43.955 26.256 44.093 26.376 ;
     RECT  43.744 35.424 44.165 37.656 ;
     RECT  43.907 29.712 44.188 29.976 ;
     RECT  43.744 32.208 44.188 32.232 ;
     RECT  43.744 34.368 44.188 34.44 ;
     RECT  43.921 24.144 44.201 24.168 ;
     RECT  44.165 35.424 44.237 35.928 ;
     RECT  43.744 56.352 44.237 58.68 ;
     RECT  43.744 20.16 44.309 20.616 ;
     RECT  44.093 26.352 44.309 26.376 ;
     RECT  43.985 1.536 44.381 3.624 ;
     RECT  43.744 38.784 44.417 40.632 ;
     RECT  44.237 56.352 44.435 57.048 ;
     RECT  43.985 14.16 44.453 16.92 ;
     RECT  43.993 18 44.489 18.024 ;
     RECT  43.744 42.192 44.489 43.656 ;
     RECT  43.744 59.712 44.489 62.28 ;
     RECT  44.188 29.712 44.524 29.736 ;
     RECT  43.744 45.696 44.524 52.776 ;
     RECT  43.744 5.184 44.531 5.64 ;
     RECT  44.531 5.184 44.561 5.496 ;
     RECT  44.524 51.168 44.561 52.776 ;
     RECT  44.489 42.192 44.579 43.272 ;
     RECT  43.744 54.336 44.579 54.744 ;
     RECT  44.188 34.368 44.62 34.392 ;
     RECT  44.524 45.696 44.627 50.04 ;
     RECT  44.435 56.352 44.633 56.856 ;
     RECT  44.237 58.656 44.633 58.68 ;
     RECT  44.561 51.168 44.669 52.632 ;
     RECT  43.744 30.96 44.675 30.984 ;
     RECT  44.381 3.6 44.705 3.624 ;
     RECT  44.309 20.16 44.705 20.184 ;
     RECT  44.579 54.336 44.705 54.36 ;
     RECT  44.165 37.056 44.723 37.656 ;
     RECT  44.489 60.768 44.741 62.28 ;
     RECT  44.021 8.88 44.777 9.192 ;
     RECT  44.669 52.56 44.777 52.632 ;
     RECT  44.381 1.536 44.813 2.472 ;
     RECT  44.627 48.384 44.813 50.04 ;
     RECT  44.723 37.584 44.819 37.656 ;
     RECT  44.579 42.432 44.819 43.272 ;
     RECT  44.417 39.888 44.828 40.632 ;
     RECT  44.819 37.632 44.849 37.656 ;
     RECT  44.633 56.544 44.867 56.856 ;
     RECT  44.777 8.88 44.885 9.096 ;
     RECT  44.669 51.168 44.885 51.576 ;
     RECT  44.777 52.56 44.885 52.584 ;
     RECT  44.741 60.768 44.885 61.608 ;
     RECT  44.828 39.888 44.915 40.872 ;
     RECT  43.859 10.992 44.917 11.4 ;
     RECT  44.237 35.76 44.921 35.928 ;
     RECT  44.885 8.88 44.993 8.952 ;
     RECT  44.489 59.712 45.065 59.736 ;
     RECT  44.917 10.848 45.137 11.4 ;
     RECT  43.985 7.056 45.157 7.128 ;
     RECT  44.813 48.528 45.245 50.04 ;
     RECT  43.921 23.04 45.26 23.064 ;
     RECT  45.301 21.504 45.313 21.528 ;
     RECT  45.26 23.04 45.313 23.976 ;
     RECT  45.013 32.448 45.313 32.472 ;
     RECT  45.313 21.504 45.347 23.976 ;
     RECT  45.169 28.416 45.349 28.44 ;
     RECT  44.915 39.888 45.389 40.632 ;
     RECT  45.013 18.144 45.425 18.216 ;
     RECT  44.993 8.928 45.484 8.952 ;
     RECT  45.313 32.4 45.493 32.472 ;
     RECT  44.453 14.16 45.529 16.536 ;
     RECT  44.417 38.784 45.529 38.808 ;
     RECT  45.493 32.208 45.533 32.472 ;
     RECT  45.389 40.32 45.533 40.632 ;
     RECT  45.533 32.208 45.58 32.424 ;
     RECT  45.349 28.032 45.587 28.44 ;
     RECT  45.385 29.52 45.587 29.544 ;
     RECT  45.58 32.4 45.587 32.424 ;
     RECT  44.627 45.696 45.589 47.208 ;
     RECT  45.529 13.728 45.613 16.536 ;
     RECT  45.157 7.056 45.637 7.176 ;
     RECT  44.813 1.536 45.641 1.56 ;
     RECT  44.885 51.456 45.673 51.576 ;
     RECT  45.245 48.528 45.676 49.32 ;
     RECT  44.885 61.584 45.677 61.608 ;
     RECT  45.137 10.944 45.709 11.4 ;
     RECT  45.425 18.144 45.74 18.168 ;
     RECT  45.601 30.72 45.779 30.744 ;
     RECT  45.709 33.504 45.817 33.528 ;
     RECT  45.529 38.784 45.821 39.288 ;
     RECT  45.74 18 45.827 18.168 ;
     RECT  45.385 26.832 45.857 26.856 ;
     RECT  45.821 38.784 45.857 38.808 ;
     RECT  45.347 21.504 45.893 23.928 ;
     RECT  45.827 18.144 45.929 18.168 ;
     RECT  45.781 50.4 45.953 50.424 ;
     RECT  45.673 51.456 45.953 51.72 ;
     RECT  45.853 3.696 46.097 3.72 ;
     RECT  45.889 53.04 46.109 53.064 ;
     RECT  44.867 56.544 46.109 56.568 ;
     RECT  45.676 48.528 46.141 48.984 ;
     RECT  45.853 19.776 46.163 19.8 ;
     RECT  46.133 37.2 46.172 37.224 ;
     RECT  46.097 3.696 46.181 4.104 ;
     RECT  46.105 61.008 46.189 61.032 ;
     RECT  46.172 37.104 46.213 37.224 ;
     RECT  46.133 2.256 46.217 2.28 ;
     RECT  45.613 14.16 46.217 16.536 ;
     RECT  45.953 50.4 46.217 51.72 ;
     RECT  45.589 44.736 46.289 47.208 ;
     RECT  46.217 51.696 46.289 51.72 ;
     RECT  46.213 37.104 46.3 37.464 ;
     RECT  46.181 3.696 46.348 3.72 ;
     RECT  44.561 5.472 46.357 5.496 ;
     RECT  44.819 42.528 46.357 43.272 ;
     RECT  45.533 40.32 46.361 40.584 ;
     RECT  46.105 8.736 46.397 8.76 ;
     RECT  46.357 5.472 46.444 5.64 ;
     RECT  45.709 10.944 46.465 11.976 ;
     RECT  45.893 23.04 46.465 23.928 ;
     RECT  46.177 25.152 46.465 25.176 ;
     RECT  46.361 40.32 46.501 40.344 ;
     RECT  45.817 33.456 46.537 33.528 ;
     RECT  45.385 58.176 46.537 58.2 ;
     RECT  45.587 28.032 46.541 28.056 ;
     RECT  46.46 30.912 46.547 30.936 ;
     RECT  46.46 54.432 46.547 54.456 ;
     RECT  46.3 37.104 46.609 37.176 ;
     RECT  46.289 45.648 46.645 47.208 ;
     RECT  46.444 5.472 46.649 5.496 ;
     RECT  46.465 23.04 46.649 25.176 ;
     RECT  46.465 10.944 46.652 12.264 ;
     RECT  46.537 33.312 46.673 33.528 ;
     RECT  45.589 35.472 46.673 35.496 ;
     RECT  46.357 42.528 46.709 43.32 ;
     RECT  46.645 45.648 46.721 47.256 ;
     RECT  46.652 10.608 46.739 12.264 ;
     RECT  46.649 24.48 46.739 25.176 ;
     RECT  46.217 14.16 46.741 14.184 ;
     RECT  46.673 35.472 46.741 35.688 ;
     RECT  46.673 32.928 46.753 33.528 ;
     RECT  46.741 35.184 46.757 35.688 ;
     RECT  46.721 46.8 46.789 47.256 ;
     RECT  46.741 13.632 46.793 14.184 ;
     RECT  46.709 41.904 46.793 43.32 ;
     RECT  46.739 10.944 46.796 12.264 ;
     RECT  46.757 35.184 46.828 35.592 ;
     RECT  46.741 29.52 46.829 29.544 ;
     RECT  46.789 46.8 46.876 47.4 ;
     RECT  46.796 10.944 46.883 12.504 ;
     RECT  45.893 21.504 46.892 21.528 ;
     RECT  46.793 13.632 46.901 13.656 ;
     RECT  46.753 32.928 46.901 33.576 ;
     RECT  46.892 21.216 46.933 21.528 ;
     RECT  46.649 23.04 46.933 23.064 ;
     RECT  46.609 37.056 46.937 37.176 ;
     RECT  46.885 38.4 46.973 38.424 ;
     RECT  46.933 21.216 46.979 23.064 ;
     RECT  46.883 10.944 47.027 12.264 ;
     RECT  46.901 32.928 47.045 33.528 ;
     RECT  47.036 53.856 47.123 53.88 ;
     RECT  46.556 44.496 47.18 44.52 ;
     RECT  46.141 48.48 47.185 48.984 ;
     RECT  45.637 7.056 47.189 7.416 ;
     RECT  47.045 32.928 47.189 33.336 ;
     RECT  47.125 9.6 47.212 9.624 ;
     RECT  46.501 40.176 47.221 40.344 ;
     RECT  47.185 48.48 47.221 49.464 ;
     RECT  46.217 15.696 47.257 16.536 ;
     RECT  47.185 17.616 47.257 17.784 ;
     RECT  47.18 44.4 47.267 44.52 ;
     RECT  46.537 58.176 47.276 58.44 ;
     RECT  46.721 45.648 47.293 45.816 ;
     RECT  45.745 59.808 47.293 59.832 ;
     RECT  46.979 22.224 47.297 23.064 ;
     RECT  47.077 41.52 47.315 41.544 ;
     RECT  47.185 38.688 47.324 39 ;
     RECT  47.221 39.984 47.324 40.344 ;
     RECT  47.285 56.736 47.324 56.76 ;
     RECT  47.324 38.688 47.329 40.344 ;
     RECT  47.276 58.176 47.329 58.488 ;
     RECT  47.293 59.664 47.329 59.832 ;
     RECT  46.828 35.568 47.333 35.592 ;
     RECT  47.077 2.304 47.369 2.328 ;
     RECT  47.257 15.696 47.369 17.784 ;
     RECT  47.285 32.352 47.369 32.904 ;
     RECT  47.329 38.688 47.404 41.064 ;
     RECT  47.404 38.976 47.411 41.064 ;
     RECT  47.324 56.304 47.411 56.76 ;
     RECT  47.411 39.984 47.441 41.064 ;
     RECT  47.013 27.744 47.468 27.768 ;
     RECT  47.329 58.176 47.477 59.832 ;
     RECT  47.189 7.056 47.509 7.128 ;
     RECT  47.468 27.312 47.509 27.768 ;
     RECT  47.509 27.312 47.555 28.536 ;
     RECT  47.468 61.824 47.555 61.848 ;
     RECT  46.793 42.768 47.585 43.32 ;
     RECT  47.477 59.28 47.585 59.832 ;
     RECT  47.555 28.512 47.593 28.536 ;
     RECT  47.369 15.696 47.617 16.536 ;
     RECT  47.441 39.984 47.621 40.392 ;
     RECT  47.585 43.056 47.653 43.32 ;
     RECT  47.477 58.176 47.657 58.2 ;
     RECT  47.653 43.056 47.689 43.368 ;
     RECT  47.293 45.024 47.693 45.816 ;
     RECT  47.401 19.392 47.725 19.416 ;
     RECT  47.653 20.448 47.725 20.472 ;
     RECT  47.693 45.264 47.725 45.816 ;
     RECT  46.876 46.8 47.725 47.208 ;
     RECT  47.411 38.976 47.729 39 ;
     RECT  47.725 19.392 47.737 20.472 ;
     RECT  47.509 55.488 47.749 55.8 ;
     RECT  47.369 17.616 47.873 17.784 ;
     RECT  47.737 19.392 47.873 19.608 ;
     RECT  47.689 43.056 47.873 43.56 ;
     RECT  46.739 24.864 47.893 25.032 ;
     RECT  47.845 0.576 47.941 0.6 ;
     RECT  47.893 30.912 47.941 30.936 ;
     RECT  46.937 37.056 47.989 37.08 ;
     RECT  47.977 52.8 47.989 52.824 ;
     RECT  47.873 43.248 48.229 43.56 ;
     RECT  48.133 50.976 48.229 51 ;
     RECT  47.027 10.944 48.301 11.4 ;
     RECT  48.229 43.248 48.301 43.608 ;
     RECT  48.301 10.896 48.332 11.4 ;
     RECT  47.893 34.656 48.332 34.68 ;
     RECT  48.229 50.976 48.332 51.096 ;
     RECT  48.332 34.464 48.373 34.68 ;
     RECT  48.373 34.464 48.428 35.544 ;
     RECT  48.373 14.208 48.445 14.232 ;
     RECT  47.749 55.152 48.469 55.8 ;
     RECT  47.725 45.264 48.481 47.208 ;
     RECT  47.221 48.48 48.481 49.56 ;
     RECT  48.181 61.2 48.524 61.224 ;
     RECT  48.481 41.712 48.553 41.736 ;
     RECT  48.445 14.112 48.589 14.232 ;
     RECT  47.617 15.456 48.589 16.536 ;
     RECT  47.873 17.76 48.589 17.784 ;
     RECT  47.297 23.04 48.661 23.064 ;
     RECT  48.301 43.248 48.661 43.656 ;
     RECT  47.989 37.056 48.668 37.464 ;
     RECT  48.428 34.464 48.689 35.592 ;
     RECT  47.893 24.624 48.709 25.032 ;
     RECT  48.469 54.672 48.709 55.8 ;
     RECT  47.893 56.832 48.709 56.856 ;
     RECT  48.589 17.76 48.769 17.976 ;
     RECT  47.941 0.576 48.848 0.648 ;
     RECT  47.509 6.144 48.848 7.128 ;
     RECT  48.332 10.8 48.848 11.4 ;
     RECT  48.589 14.112 48.848 16.536 ;
     RECT  48.769 17.76 48.848 18.216 ;
     RECT  47.873 19.392 48.848 19.512 ;
     RECT  48.589 21.696 48.848 21.72 ;
     RECT  48.661 23.04 48.848 23.304 ;
     RECT  48.709 24.624 48.848 25.224 ;
     RECT  47.555 27.456 48.848 27.48 ;
     RECT  48.805 28.464 48.848 28.488 ;
     RECT  47.941 30.912 48.848 31.224 ;
     RECT  47.369 32.88 48.848 32.904 ;
     RECT  48.689 34.464 48.848 35.832 ;
     RECT  48.668 37.056 48.848 38.184 ;
     RECT  47.621 39.984 48.848 40.344 ;
     RECT  48.553 41.664 48.848 41.736 ;
     RECT  48.661 43.248 48.848 43.896 ;
     RECT  48.481 45.264 48.848 49.56 ;
     RECT  48.332 50.976 48.848 51.192 ;
     RECT  47.989 52.8 48.848 53.208 ;
     RECT  48.709 54.432 48.848 55.8 ;
     RECT  48.709 56.832 48.848 57.144 ;
     RECT  47.585 59.28 48.848 59.688 ;
     RECT  48.524 60.816 48.848 61.224 ;
     RECT  48.848 0.528 48.952 64.272 ;
     RECT  48.952 0.798 49.144 64.002 ;
     RECT  49.144 10.944 49.205 12.072 ;
     RECT  49.144 21.696 49.205 21.768 ;
     RECT  49.205 10.944 49.241 11.784 ;
     RECT  49.144 37.056 49.241 37.176 ;
     RECT  49.144 45.456 49.241 47.16 ;
     RECT  49.144 30.96 49.277 31.416 ;
     RECT  49.144 48.72 49.283 48.792 ;
     RECT  49.144 19.584 49.285 20.232 ;
     RECT  49.144 38.16 49.321 38.616 ;
     RECT  49.144 43.296 49.349 44.088 ;
     RECT  49.144 55.776 49.349 57.096 ;
     RECT  49.241 45.456 49.427 47.112 ;
     RECT  49.285 19.584 49.493 19.944 ;
     RECT  49.349 56.256 49.565 57.096 ;
     RECT  49.144 40.128 49.571 40.392 ;
     RECT  49.144 17.712 49.601 18.216 ;
     RECT  49.493 19.92 49.601 19.944 ;
     RECT  49.321 38.16 49.609 38.184 ;
     RECT  49.277 31.2 49.637 31.416 ;
     RECT  49.241 37.104 49.637 37.176 ;
     RECT  49.144 22.8 49.673 23.304 ;
     RECT  49.144 58.128 49.673 58.68 ;
     RECT  49.144 52.56 49.715 53.112 ;
     RECT  49.673 22.8 49.745 22.824 ;
     RECT  49.349 43.392 49.859 44.088 ;
     RECT  49.144 54.672 49.859 54.696 ;
     RECT  49.144 61.632 49.859 62.184 ;
     RECT  49.144 41.76 49.907 41.784 ;
     RECT  49.144 6.672 49.925 6.792 ;
     RECT  49.565 56.256 49.961 56.904 ;
     RECT  49.961 56.496 49.996 56.904 ;
     RECT  49.205 21.744 50.051 21.768 ;
     RECT  49.673 58.128 50.051 58.392 ;
     RECT  49.996 56.496 50.147 56.52 ;
     RECT  49.144 33.6 50.173 33.624 ;
     RECT  49.144 59.664 50.173 59.88 ;
     RECT  49.859 62.16 50.177 62.184 ;
     RECT  50.173 59.664 50.197 60.456 ;
     RECT  50.173 14.736 50.209 14.76 ;
     RECT  49.427 46.848 50.281 47.112 ;
     RECT  49.601 17.712 50.284 18.024 ;
     RECT  49.715 53.088 50.285 53.112 ;
     RECT  50.197 59.664 50.285 60.696 ;
     RECT  49.144 35.28 50.317 35.544 ;
     RECT  49.144 50.592 50.317 50.616 ;
     RECT  50.284 17.712 50.321 17.976 ;
     RECT  50.245 21.696 50.332 21.72 ;
     RECT  49.427 45.456 50.341 45.72 ;
     RECT  50.321 17.712 50.348 17.736 ;
     RECT  50.285 59.664 50.393 60.456 ;
     RECT  50.348 17.472 50.435 17.736 ;
     RECT  49.241 10.944 50.492 10.968 ;
     RECT  50.281 13.68 50.497 13.704 ;
     RECT  50.209 14.736 50.537 14.952 ;
     RECT  50.435 17.712 50.537 17.736 ;
     RECT  50.341 45.168 50.605 45.72 ;
     RECT  50.54 39.024 50.627 39.048 ;
     RECT  49.637 31.2 50.636 31.224 ;
     RECT  50.317 50.496 50.636 50.616 ;
     RECT  50.492 10.944 50.677 11.544 ;
     RECT  50.245 37.392 50.677 37.416 ;
     RECT  50.497 13.632 50.713 13.704 ;
     RECT  50.713 13.632 50.723 13.992 ;
     RECT  50.636 50.112 50.723 50.616 ;
     RECT  50.605 54.864 50.723 55.512 ;
     RECT  50.677 10.752 50.725 11.544 ;
     RECT  50.051 58.128 50.725 58.248 ;
     RECT  50.723 50.496 50.732 50.616 ;
     RECT  49.283 48.768 50.753 48.792 ;
     RECT  50.317 34.752 50.773 35.544 ;
     RECT  49.859 43.392 50.789 43.896 ;
     RECT  50.713 24.432 50.797 24.456 ;
     RECT  50.732 8.4 50.819 8.424 ;
     RECT  50.732 50.496 50.819 51.48 ;
     RECT  50.281 46.848 50.821 47.304 ;
     RECT  50.78 48.384 50.821 48.408 ;
     RECT  50.723 13.728 50.825 13.992 ;
     RECT  50.725 19.44 50.825 19.464 ;
     RECT  50.461 40.464 50.828 40.488 ;
     RECT  50.173 33.072 50.861 33.624 ;
     RECT  50.821 46.848 50.867 48.408 ;
     RECT  50.605 44.88 50.897 45.72 ;
     RECT  50.819 50.496 50.897 50.712 ;
     RECT  50.828 40.416 50.915 40.488 ;
     RECT  50.725 10.752 50.929 12.168 ;
     RECT  50.773 34.752 50.929 35.736 ;
     RECT  50.929 10.704 50.933 12.168 ;
     RECT  50.789 43.392 50.933 43.416 ;
     RECT  50.897 44.976 50.969 45.72 ;
     RECT  50.723 55.392 50.969 55.512 ;
     RECT  50.725 57.6 50.969 58.248 ;
     RECT  49.144 26.208 51.005 26.232 ;
     RECT  50.867 46.848 51.005 48.168 ;
     RECT  50.969 57.6 51.059 57.96 ;
     RECT  50.933 10.704 51.073 11.448 ;
     RECT  50.969 45.408 51.077 45.72 ;
     RECT  50.969 55.488 51.077 55.512 ;
     RECT  51.013 21.168 51.1 21.192 ;
     RECT  50.636 30.672 51.149 31.224 ;
     RECT  49.925 6.672 51.299 6.696 ;
     RECT  51.145 19.872 51.299 19.896 ;
     RECT  51.149 30.672 51.301 30.888 ;
     RECT  50.929 34.704 51.301 35.736 ;
     RECT  51.301 34.704 51.329 35.832 ;
     RECT  50.393 60.432 51.329 60.456 ;
     RECT  51.301 30.192 51.347 30.888 ;
     RECT  49.144 28.464 51.365 28.488 ;
     RECT  51.301 43.248 51.397 43.272 ;
     RECT  51.397 42.768 51.437 43.272 ;
     RECT  51.397 51.936 51.445 52.2 ;
     RECT  51.005 46.848 51.473 48.024 ;
     RECT  50.897 50.592 51.473 50.712 ;
     RECT  51.473 46.848 51.509 47.928 ;
     RECT  51.445 51.936 51.532 52.488 ;
     RECT  51.329 35.52 51.541 35.832 ;
     RECT  50.677 37.104 51.541 37.416 ;
     RECT  51.059 57.6 51.548 57.912 ;
     RECT  50.825 13.728 51.581 13.752 ;
     RECT  51.509 46.848 51.581 47.304 ;
     RECT  51.548 56.688 51.581 57.912 ;
     RECT  51.5 54.336 51.587 54.36 ;
     RECT  51.073 10.56 51.613 11.448 ;
     RECT  51.541 35.52 51.635 37.416 ;
     RECT  51.581 56.688 51.635 57.384 ;
     RECT  51.613 10.512 51.637 11.448 ;
     RECT  51.347 30.192 51.649 30.552 ;
     RECT  51.635 35.76 51.689 37.416 ;
     RECT  51.637 9.792 51.725 11.448 ;
     RECT  51.637 32.832 51.725 32.856 ;
     RECT  51.649 29.664 51.733 30.552 ;
     RECT  51.725 10.512 51.797 11.448 ;
     RECT  51.077 45.456 51.797 45.72 ;
     RECT  51.635 57.36 51.868 57.384 ;
     RECT  51.797 10.56 51.875 11.448 ;
     RECT  51.689 36.096 51.875 37.416 ;
     RECT  50.915 40.464 51.877 40.488 ;
     RECT  51.577 34.512 51.941 34.536 ;
     RECT  51.877 50.064 51.964 50.088 ;
     RECT  51.721 38.736 52.009 38.76 ;
     RECT  51.875 10.704 52.049 11.064 ;
     RECT  51.875 37.392 52.049 37.416 ;
     RECT  52.049 10.8 52.121 11.064 ;
     RECT  52.009 38.736 52.225 38.808 ;
     RECT  52.213 23.712 52.3 23.736 ;
     RECT  51.877 40.464 52.301 41.112 ;
     RECT  52.121 11.04 52.403 11.064 ;
     RECT  51.437 42.768 52.441 42.792 ;
     RECT  52.117 43.776 52.441 44.136 ;
     RECT  52.357 56.064 52.444 56.088 ;
     RECT  51.797 45.696 52.481 45.72 ;
     RECT  52.225 38.64 52.517 38.808 ;
     RECT  52.517 38.736 52.553 38.808 ;
     RECT  51.649 60.144 52.585 60.168 ;
     RECT  52.508 23.04 52.595 23.064 ;
     RECT  52.441 42.768 52.621 44.136 ;
     RECT  51.875 36.096 52.636 36.408 ;
     RECT  51.532 51.936 52.657 52.2 ;
     RECT  52.553 38.784 52.661 38.808 ;
     RECT  52.645 19.968 52.693 19.992 ;
     RECT  52.585 60.144 52.7 60.312 ;
     RECT  52.645 53.808 52.732 54.072 ;
     RECT  52.693 19.968 52.733 20.088 ;
     RECT  52.645 21.6 52.733 21.624 ;
     RECT  51.581 46.848 52.765 46.872 ;
     RECT  51.925 17.52 52.769 17.544 ;
     RECT  52.685 18.576 52.769 18.6 ;
     RECT  52.733 20.064 52.777 20.088 ;
     RECT  52.765 47.952 52.909 47.976 ;
     RECT  52.801 49.44 52.909 49.464 ;
     RECT  52.301 40.464 52.913 40.488 ;
     RECT  52.7 59.472 52.94 60.312 ;
     RECT  52.873 25.008 53.017 25.032 ;
     RECT  53.017 24.096 53.021 25.032 ;
     RECT  52.621 42.768 53.021 44.328 ;
     RECT  53.021 42.768 53.027 43.8 ;
     RECT  52.94 58.656 53.027 60.312 ;
     RECT  52.909 47.952 53.045 49.464 ;
     RECT  52.636 36.288 53.057 36.408 ;
     RECT  53.027 59.28 53.089 60.312 ;
     RECT  53.027 42.768 53.101 42.792 ;
     RECT  53.036 34.752 53.123 34.776 ;
     RECT  51.733 30.528 53.129 30.552 ;
     RECT  53.045 47.952 53.129 50.088 ;
     RECT  53.084 36.672 53.171 36.696 ;
     RECT  53.089 59.28 53.173 60.456 ;
     RECT  52.765 46.464 53.201 46.872 ;
     RECT  53.132 37.68 53.219 37.704 ;
     RECT  53.153 38.976 53.237 39 ;
     RECT  53.197 57.312 53.341 57.336 ;
     RECT  53.341 57.312 53.377 58.152 ;
     RECT  53.605 40.32 53.948 40.344 ;
     RECT  53.948 39.168 53.989 39.192 ;
     RECT  53.948 40.224 53.989 40.344 ;
     RECT  53.377 57.024 53.989 58.152 ;
     RECT  53.173 59.28 53.989 59.88 ;
     RECT  54.061 44.976 54.092 45 ;
     RECT  53.021 24.096 54.133 24.12 ;
     RECT  54.092 44.88 54.133 45 ;
     RECT  53.201 46.512 54.133 46.872 ;
     RECT  53.129 47.952 54.133 49.464 ;
     RECT  54.025 53.28 54.133 53.304 ;
     RECT  49.144 16.272 54.248 16.296 ;
     RECT  54.092 19.44 54.248 19.464 ;
     RECT  53.029 22.464 54.248 22.872 ;
     RECT  54.133 24.096 54.248 24.744 ;
     RECT  53.516 30.48 54.248 30.504 ;
     RECT  53.756 37.44 54.248 37.464 ;
     RECT  53.989 39.168 54.248 40.344 ;
     RECT  53.893 41.904 54.248 41.928 ;
     RECT  53.027 43.776 54.248 43.8 ;
     RECT  54.133 44.88 54.248 45.24 ;
     RECT  54.133 46.512 54.248 49.464 ;
     RECT  52.657 51.36 54.248 52.2 ;
     RECT  54.133 53.28 54.248 53.4 ;
     RECT  54.241 54.384 54.248 54.408 ;
     RECT  53.804 55.824 54.248 55.848 ;
     RECT  53.989 57.024 54.248 59.88 ;
     RECT  54.248 0.528 54.352 64.272 ;
     RECT  54.352 0.798 54.544 64.002 ;
     RECT  54.544 24.72 54.605 25.512 ;
     RECT  54.544 58.656 54.605 58.68 ;
     RECT  54.544 19.488 54.659 21.096 ;
     RECT  54.544 44.976 54.659 47.928 ;
     RECT  54.544 48.96 54.659 54.744 ;
     RECT  54.544 55.776 54.659 56.04 ;
     RECT  54.544 33.024 54.685 33.048 ;
     RECT  54.659 54.672 54.707 54.744 ;
     RECT  54.544 34.896 54.713 34.92 ;
     RECT  54.544 57.552 54.749 57.576 ;
     RECT  54.544 26.64 54.793 26.664 ;
     RECT  54.659 45.936 54.796 47.928 ;
     RECT  54.544 23.088 54.821 23.112 ;
     RECT  54.659 50.784 54.965 53.304 ;
     RECT  54.544 36.048 55.001 36.072 ;
     RECT  54.965 50.784 55.187 53.256 ;
     RECT  54.544 42.672 55.235 42.696 ;
     RECT  54.544 40.176 55.369 40.2 ;
     RECT  54.796 45.936 55.475 47.112 ;
     RECT  54.659 48.96 55.523 49.464 ;
     RECT  55.475 47.088 55.541 47.112 ;
     RECT  55.187 50.784 55.564 52.824 ;
     RECT  55.525 30.72 55.612 30.744 ;
     RECT  54.659 20.832 55.613 21.096 ;
     RECT  55.564 50.784 55.685 52.536 ;
     RECT  54.544 43.824 55.721 43.848 ;
     RECT  55.645 0.192 55.729 0.216 ;
     RECT  55.685 50.784 55.793 50.808 ;
     RECT  54.659 19.488 55.825 19.512 ;
     RECT  55.475 45.936 55.861 45.96 ;
     RECT  54.707 54.672 55.861 54.696 ;
     RECT  55.685 52.464 55.865 52.536 ;
     RECT  54.659 56.016 55.907 56.04 ;
     RECT  55.861 54.384 55.945 54.744 ;
     RECT  55.865 52.512 55.996 52.536 ;
     RECT  55.825 19.488 56.005 19.608 ;
     RECT  54.605 25.296 56.009 25.512 ;
     RECT  55.945 54.672 56.009 54.744 ;
     RECT  56.005 19.488 56.041 19.704 ;
     RECT  55.957 49.824 56.044 49.848 ;
     RECT  56.012 38.592 56.099 38.616 ;
     RECT  56.041 18.72 56.113 19.704 ;
     RECT  56.009 25.296 56.153 25.32 ;
     RECT  56.113 18.528 56.293 19.704 ;
     RECT  56.009 54.672 56.297 54.696 ;
     RECT  56.252 36.432 56.339 36.936 ;
     RECT  56.293 18.528 56.405 19.848 ;
     RECT  56.341 39.984 56.428 40.008 ;
     RECT  56.405 18.624 56.441 19.848 ;
     RECT  55.861 26.784 56.441 26.808 ;
     RECT  56.339 36.912 56.441 36.936 ;
     RECT  55.613 21.072 56.477 21.096 ;
     RECT  55.861 45.312 56.485 45.96 ;
     RECT  56.485 45.312 56.531 46.2 ;
     RECT  56.588 33.264 56.675 33.288 ;
     RECT  56.441 19.584 56.729 19.848 ;
     RECT  56.531 46.176 56.729 46.2 ;
     RECT  56.729 19.584 56.801 19.704 ;
     RECT  56.801 19.68 56.837 19.704 ;
     RECT  56.581 41.472 56.981 41.496 ;
     RECT  56.905 27.552 57.011 27.576 ;
     RECT  56.833 31.968 57.011 31.992 ;
     RECT  57.005 51.312 57.089 51.528 ;
     RECT  57.548 35.28 57.589 35.304 ;
     RECT  57.301 36.48 57.589 36.504 ;
     RECT  57.589 35.28 57.635 36.504 ;
     RECT  57.661 24.624 57.697 24.648 ;
     RECT  57.685 39.072 57.773 39.096 ;
     RECT  57.692 48.96 57.779 48.984 ;
     RECT  57.836 26.64 57.923 26.664 ;
     RECT  57.877 42.864 57.985 42.888 ;
     RECT  57.985 42.864 58.163 43.176 ;
     RECT  57.884 28.992 58.169 29.016 ;
     RECT  58.117 33.024 58.205 33.048 ;
     RECT  54.544 16.272 58.237 16.296 ;
     RECT  58.163 42.864 58.349 42.888 ;
     RECT  58.124 45.408 58.417 45.432 ;
     RECT  58.345 29.088 58.429 29.112 ;
     RECT  58.093 47.424 58.493 47.448 ;
     RECT  58.345 41.04 58.499 41.064 ;
     RECT  57.635 36.048 58.597 36.072 ;
     RECT  58.597 36.048 58.637 36.456 ;
     RECT  58.625 22.752 58.669 22.776 ;
     RECT  57.697 24.528 58.673 24.648 ;
     RECT  58.673 24.528 58.693 24.552 ;
     RECT  58.637 36.432 58.693 36.456 ;
     RECT  58.561 33.888 58.885 33.912 ;
     RECT  58.633 26.352 58.94 26.376 ;
     RECT  58.741 18.576 59.065 18.6 ;
     RECT  58.94 26.352 59.173 26.472 ;
     RECT  58.885 33.888 59.173 34.44 ;
     RECT  58.693 36.432 59.353 37.08 ;
     RECT  58.669 22.752 59.42 22.92 ;
     RECT  58.417 44.592 59.509 45.432 ;
     RECT  59.353 36.432 59.605 37.608 ;
     RECT  58.405 38.64 59.605 38.664 ;
     RECT  58.237 16.272 59.648 17.112 ;
     RECT  59.065 18.192 59.648 18.6 ;
     RECT  58.345 20.448 59.648 20.472 ;
     RECT  59.42 22.176 59.648 22.92 ;
     RECT  58.693 24.384 59.648 24.552 ;
     RECT  59.173 26.256 59.648 26.472 ;
     RECT  58.741 31.776 59.648 31.8 ;
     RECT  59.173 33.888 59.648 34.68 ;
     RECT  59.605 36.432 59.648 38.664 ;
     RECT  59.509 44.592 59.648 45.672 ;
     RECT  58.988 48.432 59.648 48.456 ;
     RECT  59.648 0.528 59.752 64.272 ;
     RECT  59.752 0.798 59.944 64.002 ;
     RECT  59.944 17.088 60.083 17.112 ;
     RECT  59.944 43.584 60.083 43.608 ;
     RECT  59.944 40.848 60.131 41.256 ;
     RECT  59.944 18.816 60.257 20.568 ;
     RECT  59.944 42.48 60.419 42.504 ;
     RECT  59.944 33.84 60.437 34.776 ;
     RECT  59.944 39.6 60.437 39.624 ;
     RECT  59.944 37.584 60.473 38.472 ;
     RECT  59.944 26.208 60.617 26.76 ;
     RECT  59.944 35.952 60.659 35.976 ;
     RECT  60.437 34.752 60.707 34.776 ;
     RECT  59.944 24.624 60.796 24.648 ;
     RECT  59.944 28.416 60.851 28.44 ;
     RECT  60.131 41.232 60.905 41.256 ;
     RECT  59.944 22.992 60.956 23.016 ;
     RECT  59.944 31.92 60.988 31.944 ;
     RECT  60.617 26.736 60.995 26.76 ;
     RECT  60.956 22.032 61.043 23.016 ;
     RECT  61.043 22.992 61.153 23.016 ;
     RECT  60.257 20.352 61.193 20.376 ;
     RECT  61.141 43.536 61.228 43.56 ;
     RECT  60.997 36.48 61.229 36.504 ;
     RECT  61.153 22.992 61.265 23.112 ;
     RECT  60.473 38.448 61.265 38.472 ;
     RECT  60.257 18.816 61.301 19.368 ;
     RECT  61.301 18.816 61.409 18.84 ;
     RECT  60.997 25.728 61.409 25.752 ;
     RECT  61.369 38.736 61.549 38.76 ;
     RECT  61.549 38.736 61.553 39.384 ;
     RECT  61.333 31.872 61.573 31.896 ;
     RECT  59.944 47.856 61.573 47.88 ;
     RECT  61.573 44.064 61.66 44.904 ;
     RECT  61.58 33.792 61.667 33.816 ;
     RECT  61.513 46.752 61.769 46.776 ;
     RECT  61.573 31.248 61.805 31.896 ;
     RECT  61.765 40.848 61.849 40.872 ;
     RECT  61.573 47.856 61.877 48.504 ;
     RECT  61.805 31.248 62.129 31.272 ;
     RECT  61.553 39.36 62.165 39.384 ;
     RECT  62.108 20.832 62.195 20.856 ;
     RECT  61.66 44.064 62.237 44.664 ;
     RECT  62.237 44.064 62.273 44.472 ;
     RECT  62.437 26.736 62.449 26.76 ;
     RECT  62.204 28.8 62.453 28.824 ;
     RECT  61.877 47.856 62.489 47.88 ;
     RECT  61.265 22.992 62.633 23.016 ;
     RECT  62.273 44.448 62.633 44.472 ;
     RECT  62.557 24.528 62.675 24.552 ;
     RECT  62.305 36.48 62.741 36.504 ;
     RECT  62.701 20.592 62.849 20.616 ;
     RECT  62.449 26.208 62.921 26.76 ;
     RECT  62.341 21.648 63.245 21.672 ;
     RECT  63.233 31.392 63.317 31.416 ;
     RECT  63.253 19.872 63.389 19.896 ;
     RECT  63.253 24.384 63.461 24.408 ;
     RECT  62.921 26.208 63.497 26.376 ;
     RECT  63.253 33.6 63.677 33.624 ;
     RECT  63.497 26.208 63.713 26.232 ;
    LAYER M5 ;
     RECT  53.232 0.053 53.256 0.144 ;
     RECT  23.328 0.144 23.448 0.227 ;
     RECT  55.68 0.144 55.704 0.227 ;
     RECT  53.088 0.144 53.256 0.235 ;
     RECT  15.36 0.144 16.728 0.277 ;
     RECT  42.336 0.144 43.128 0.517 ;
     RECT  47.856 0.144 47.976 0.517 ;
     RECT  42.336 0.517 43.56 0.611 ;
     RECT  47.856 0.517 48.96 0.611 ;
     RECT  47.952 0.611 48.96 0.659 ;
     RECT  0.24 0.517 0.36 0.787 ;
     RECT  5.64 0.517 5.76 0.787 ;
     RECT  11.04 0.517 11.16 0.787 ;
     RECT  21.84 0.517 21.96 0.787 ;
     RECT  27.24 0.517 27.36 0.787 ;
     RECT  32.64 0.517 32.76 0.787 ;
     RECT  38.04 0.517 38.16 0.787 ;
     RECT  42.432 0.611 43.56 0.787 ;
     RECT  48.84 0.659 48.96 0.787 ;
     RECT  54.24 0.517 54.36 0.787 ;
     RECT  59.64 0.517 59.76 0.787 ;
     RECT  15.36 0.277 16.872 1.187 ;
     RECT  23.328 0.227 23.352 1.187 ;
     RECT  42.432 0.787 43.752 1.187 ;
     RECT  32.64 0.787 32.952 1.237 ;
     RECT  38.04 0.787 38.352 1.237 ;
     RECT  29.616 1.237 29.64 1.285 ;
     RECT  31.344 1.237 31.368 1.285 ;
     RECT  32.64 1.237 33.72 1.363 ;
     RECT  34.704 1.237 34.728 1.363 ;
     RECT  16.224 1.187 16.752 1.379 ;
     RECT  27.24 0.787 27.552 1.397 ;
     RECT  32.64 1.363 34.728 1.397 ;
     RECT  36.096 1.363 36.12 1.397 ;
     RECT  30.816 1.285 31.368 1.451 ;
     RECT  32.496 1.397 36.6 1.451 ;
     RECT  38.04 1.237 38.472 1.451 ;
     RECT  32.496 1.451 32.952 1.485 ;
     RECT  27.24 1.397 27.672 1.525 ;
     RECT  28.656 1.285 29.64 1.973 ;
     RECT  30.816 1.451 30.84 2.027 ;
     RECT  34.752 1.451 36.6 2.027 ;
     RECT  25.632 1.525 27.672 2.067 ;
     RECT  28.656 1.973 29.832 2.067 ;
     RECT  25.632 2.067 29.832 2.155 ;
     RECT  25.632 2.155 28.632 2.195 ;
     RECT  16.44 1.379 16.752 2.197 ;
     RECT  26.208 2.195 28.632 2.219 ;
     RECT  29.808 2.155 29.832 2.259 ;
     RECT  16.44 2.197 17.736 2.283 ;
     RECT  26.208 2.219 26.232 2.291 ;
     RECT  27.24 2.219 28.632 2.291 ;
     RECT  29.808 2.259 30.744 2.291 ;
     RECT  35.616 2.027 36.6 2.291 ;
     RECT  46.176 2.207 46.2 2.291 ;
     RECT  40.704 2.229 40.728 2.317 ;
     RECT  36.576 2.291 36.6 2.339 ;
     RECT  28.608 2.291 28.632 2.347 ;
     RECT  30.72 2.291 30.744 2.347 ;
     RECT  43.44 1.187 43.752 2.725 ;
     RECT  23.472 2.643 23.496 2.731 ;
     RECT  18.816 2.783 18.84 2.821 ;
     RECT  18.816 2.821 19.416 2.867 ;
     RECT  36.72 2.783 36.744 2.867 ;
     RECT  32.64 1.485 32.952 2.869 ;
     RECT  43.44 2.725 43.944 2.923 ;
     RECT  32.64 2.869 33.864 2.963 ;
     RECT  19.392 2.867 19.416 3.051 ;
     RECT  38.04 1.451 38.352 3.301 ;
     RECT  37.584 3.301 38.352 3.385 ;
     RECT  41.712 3.381 41.736 3.469 ;
     RECT  38.04 3.385 38.352 3.589 ;
     RECT  16.44 2.283 17.688 3.667 ;
     RECT  16.44 3.667 17.832 3.755 ;
     RECT  46.272 3.667 46.296 3.755 ;
     RECT  15.408 3.349 15.432 3.829 ;
     RECT  38.04 3.589 38.616 3.859 ;
     RECT  14.208 3.829 15.432 3.913 ;
     RECT  28.608 3.445 28.632 3.923 ;
     RECT  14.784 3.913 15.432 3.947 ;
     RECT  38.04 3.859 39.288 3.947 ;
     RECT  34.848 3.925 34.872 4.011 ;
     RECT  38.04 3.947 38.616 4.011 ;
     RECT  15.408 3.947 15.432 4.019 ;
     RECT  46.128 4.021 46.152 4.115 ;
     RECT  27.24 2.291 27.552 4.165 ;
     RECT  32.64 2.963 32.952 4.179 ;
     RECT  26.352 4.165 27.552 4.267 ;
     RECT  32.544 4.179 32.952 4.267 ;
     RECT  19.92 4.319 19.944 4.403 ;
     RECT  31.344 4.165 31.368 4.587 ;
     RECT  42.192 4.501 42.216 4.587 ;
     RECT  28.752 4.341 29.112 4.594 ;
     RECT  28.752 4.594 29.16 4.715 ;
     RECT  16.44 3.755 17.112 5.045 ;
     RECT  16.44 5.045 17.544 5.133 ;
     RECT  38.04 4.011 38.352 5.221 ;
     RECT  21.84 0.787 22.152 5.231 ;
     RECT  27.24 4.267 27.552 5.269 ;
     RECT  29.376 4.755 29.4 5.269 ;
     RECT  24.288 5.203 24.312 5.291 ;
     RECT  21.84 5.231 22.776 5.315 ;
     RECT  27.24 5.269 28.296 5.355 ;
     RECT  29.376 5.269 29.688 5.355 ;
     RECT  43.44 2.923 43.752 5.587 ;
     RECT  32.64 4.267 32.952 5.605 ;
     RECT  43.44 5.587 44.52 5.675 ;
     RECT  46.368 5.587 46.392 5.675 ;
     RECT  38.04 5.221 39.048 5.739 ;
     RECT  42.192 5.663 42.216 5.747 ;
     RECT  16.44 5.133 16.752 5.749 ;
     RECT  29.088 5.715 29.112 5.803 ;
     RECT  11.04 0.787 11.352 5.971 ;
     RECT  8.688 5.971 8.712 6.059 ;
     RECT  10.608 5.971 11.352 6.059 ;
     RECT  15.456 5.749 16.752 6.059 ;
     RECT  32.496 5.605 32.952 6.133 ;
     RECT  32.352 6.133 32.952 6.239 ;
     RECT  32.352 6.239 33.672 6.251 ;
     RECT  27.24 5.355 27.552 6.261 ;
     RECT  32.496 6.251 33.672 6.323 ;
     RECT  51.264 6.661 51.288 6.827 ;
     RECT  16.44 6.059 16.752 6.837 ;
     RECT  12.672 6.767 12.696 6.851 ;
     RECT  14.88 6.767 14.904 6.851 ;
     RECT  24.624 6.767 24.648 6.851 ;
     RECT  28.8 6.837 28.92 6.947 ;
     RECT  28.896 6.947 28.92 7.139 ;
     RECT  43.44 5.675 43.752 7.141 ;
     RECT  45.168 6.837 45.192 7.187 ;
     RECT  11.04 6.059 11.352 7.333 ;
     RECT  10.224 7.333 11.352 7.349 ;
     RECT  12.912 7.315 12.936 7.403 ;
     RECT  10.224 7.349 11.64 7.417 ;
     RECT  24.432 7.391 24.456 7.475 ;
     RECT  11.04 7.417 11.64 7.619 ;
     RECT  26.832 6.261 27.552 7.827 ;
     RECT  32.496 6.323 32.952 7.861 ;
     RECT  33.936 6.421 33.96 7.861 ;
     RECT  38.04 5.739 38.352 7.861 ;
     RECT  26.832 7.827 27.768 7.891 ;
     RECT  26.4 7.891 27.768 7.915 ;
     RECT  26.4 7.915 27.672 7.955 ;
     RECT  32.496 7.861 33.96 7.955 ;
     RECT  16.44 6.837 17.016 7.967 ;
     RECT  7.008 7.891 7.032 7.979 ;
     RECT  16.44 7.967 17.784 8.051 ;
     RECT  37.008 7.967 37.032 8.051 ;
     RECT  0.24 0.787 0.552 8.211 ;
     RECT  1.68 8.149 1.704 8.211 ;
     RECT  0.24 8.211 1.704 8.235 ;
     RECT  2.88 8.159 2.904 8.243 ;
     RECT  0.24 8.235 1.32 8.299 ;
     RECT  16.44 8.051 17.688 8.377 ;
     RECT  43.44 7.141 43.848 8.389 ;
     RECT  5.64 0.787 5.952 8.437 ;
     RECT  21.84 5.315 22.152 8.437 ;
     RECT  50.784 8.373 50.808 8.461 ;
     RECT  38.04 7.861 39.144 8.485 ;
     RECT  43.056 8.389 43.848 8.485 ;
     RECT  5.328 8.437 5.952 8.501 ;
     RECT  23.952 8.437 23.976 8.521 ;
     RECT  5.328 8.501 6.84 8.555 ;
     RECT  38.04 8.485 39.912 8.569 ;
     RECT  21.84 8.437 22.776 8.579 ;
     RECT  38.04 8.569 39.144 8.579 ;
     RECT  43.008 8.485 43.848 8.619 ;
     RECT  41.568 8.543 41.592 8.627 ;
     RECT  13.104 8.565 13.128 8.677 ;
     RECT  13.056 8.677 13.128 8.678 ;
     RECT  4.032 8.309 4.056 8.723 ;
     RECT  13.056 8.678 13.08 8.761 ;
     RECT  43.056 8.619 43.848 8.773 ;
     RECT  21.84 8.579 22.152 8.821 ;
     RECT  43.056 8.773 43.896 8.869 ;
     RECT  26.4 7.955 27.552 8.885 ;
     RECT  38.04 8.579 38.472 8.927 ;
     RECT  45.408 8.821 45.432 8.963 ;
     RECT  26.208 8.885 27.552 8.979 ;
     RECT  25.44 8.979 27.552 9.011 ;
     RECT  33.936 7.955 33.96 9.061 ;
     RECT  25.44 9.011 25.464 9.067 ;
     RECT  43.056 8.869 43.944 9.119 ;
     RECT  37.92 8.927 38.472 9.141 ;
     RECT  5.64 8.555 6.84 9.155 ;
     RECT  43.056 9.119 44.472 9.203 ;
     RECT  11.04 7.619 11.352 9.349 ;
     RECT  29.28 8.787 29.304 9.349 ;
     RECT  28.848 9.349 29.304 9.461 ;
     RECT  30.96 9.349 30.984 9.461 ;
     RECT  43.056 9.203 43.896 9.491 ;
     RECT  36.96 9.141 38.472 9.493 ;
     RECT  28.848 9.461 29.352 9.515 ;
     RECT  30.816 9.461 30.984 9.525 ;
     RECT  36.48 9.493 38.472 9.539 ;
     RECT  29.328 9.515 29.352 9.549 ;
     RECT  26.832 9.011 27.552 9.555 ;
     RECT  9.84 9.493 9.864 9.579 ;
     RECT  10.848 9.349 12.024 9.579 ;
     RECT  36.48 9.539 36.504 9.579 ;
     RECT  30.816 9.525 31.128 9.587 ;
     RECT  31.104 9.587 31.128 9.613 ;
     RECT  26.832 9.555 27.672 9.643 ;
     RECT  47.136 9.555 47.16 9.643 ;
     RECT  37.776 9.539 38.472 9.695 ;
     RECT  4.272 9.637 4.296 9.721 ;
     RECT  18.192 9.637 18.216 9.721 ;
     RECT  37.776 9.695 39.048 9.779 ;
     RECT  16.44 8.377 16.752 9.811 ;
     RECT  51.648 9.717 51.672 9.827 ;
     RECT  16.32 9.811 16.752 9.899 ;
     RECT  21.744 8.821 22.152 10.101 ;
     RECT  14.64 10.069 14.664 10.155 ;
     RECT  29.664 10.069 29.688 10.155 ;
     RECT  41.04 10.213 41.064 10.229 ;
     RECT  7.344 10.195 7.368 10.283 ;
     RECT  40.944 10.229 41.064 10.297 ;
     RECT  21.696 10.101 22.152 10.405 ;
     RECT  0.24 8.299 0.552 10.485 ;
     RECT  26.832 9.643 27.552 10.501 ;
     RECT  32.496 7.955 32.952 10.579 ;
     RECT  33.936 9.061 34.824 10.579 ;
     RECT  0.24 10.485 1.272 10.595 ;
     RECT  4.32 10.485 4.344 10.595 ;
     RECT  20.544 10.229 20.568 10.595 ;
     RECT  26.112 10.501 27.552 10.603 ;
     RECT  30.672 10.549 30.696 10.643 ;
     RECT  32.496 10.579 34.824 10.667 ;
     RECT  46.704 10.597 46.728 10.681 ;
     RECT  11.04 9.579 12.024 10.741 ;
     RECT  48.84 0.787 49.152 10.789 ;
     RECT  13.632 10.707 13.656 10.795 ;
     RECT  37.776 9.779 38.352 10.795 ;
     RECT  4.464 10.741 4.488 10.805 ;
     RECT  5.64 9.155 6.072 10.805 ;
     RECT  4.464 10.805 6.072 10.825 ;
     RECT  15.408 10.741 15.432 10.825 ;
     RECT  4.704 10.825 6.072 10.859 ;
     RECT  16.44 9.899 16.752 10.869 ;
     RECT  26.832 10.603 27.552 10.869 ;
     RECT  36.624 10.741 36.648 10.883 ;
     RECT  43.344 9.491 43.896 10.885 ;
     RECT  4.704 10.859 5.952 10.893 ;
     RECT  21.648 10.405 22.152 10.899 ;
     RECT  26.832 10.869 28.44 10.899 ;
     RECT  11.04 10.741 12.504 10.931 ;
     RECT  48.384 10.789 49.152 10.931 ;
     RECT  16.44 10.869 16.872 10.957 ;
     RECT  18 10.869 18.024 10.957 ;
     RECT  26.832 10.899 29.016 10.979 ;
     RECT  21.648 10.899 22.344 10.987 ;
     RECT  28.992 10.979 29.016 10.987 ;
     RECT  43.296 10.885 43.896 11.027 ;
     RECT  51.84 10.549 51.864 11.029 ;
     RECT  19.152 10.515 19.176 11.061 ;
     RECT  30.48 11.029 30.504 11.115 ;
     RECT  51.84 11.029 52.392 11.115 ;
     RECT  19.008 11.061 19.176 11.149 ;
     RECT  37.92 10.795 38.352 11.221 ;
     RECT  21.648 10.987 22.152 11.317 ;
     RECT  45.024 10.885 45.048 11.363 ;
     RECT  40.944 10.297 40.968 11.381 ;
     RECT  19.44 11.375 19.464 11.459 ;
     RECT  51.84 11.115 51.864 11.459 ;
     RECT  50.688 10.837 50.712 11.509 ;
     RECT  32.496 10.667 32.952 11.573 ;
     RECT  40.56 11.381 40.968 11.573 ;
     RECT  32.352 11.573 32.952 11.605 ;
     RECT  31.92 11.605 32.952 11.637 ;
     RECT  33.936 10.667 33.96 11.637 ;
     RECT  31.92 11.637 33.96 11.691 ;
     RECT  37.92 11.221 39.24 11.699 ;
     RECT  40.224 11.573 40.968 11.699 ;
     RECT  8.016 11.637 8.04 11.725 ;
     RECT  25.584 11.637 25.608 11.725 ;
     RECT  32.496 11.691 33.96 11.795 ;
     RECT  16.44 10.957 16.752 11.941 ;
     RECT  21.6 11.317 22.152 11.987 ;
     RECT  11.04 10.931 12.024 12.035 ;
     RECT  50.544 11.509 50.712 12.133 ;
     RECT  40.944 11.699 40.968 12.179 ;
     RECT  50.544 12.133 50.856 12.203 ;
     RECT  18.816 12.133 18.84 12.217 ;
     RECT  6.96 12.149 6.984 12.237 ;
     RECT  50.688 12.203 50.856 12.267 ;
     RECT  46.848 12.213 47.016 12.301 ;
     RECT  46.848 12.301 46.872 12.515 ;
     RECT  16.44 11.941 17.64 12.755 ;
     RECT  14.736 12.719 14.76 12.803 ;
     RECT  32.496 11.795 32.952 12.853 ;
     RECT  33.936 11.795 33.96 12.853 ;
     RECT  32.496 12.853 33.96 12.981 ;
     RECT  38.04 11.699 39.24 13.011 ;
     RECT  32.496 12.981 34.584 13.035 ;
     RECT  9.12 12.959 9.144 13.045 ;
     RECT  33.936 13.035 34.584 13.091 ;
     RECT  38.04 13.011 39.336 13.099 ;
     RECT  42 13.011 42.024 13.099 ;
     RECT  9.12 13.045 9.24 13.237 ;
     RECT  8.016 13.237 9.24 13.291 ;
     RECT  8.016 13.291 9.144 13.331 ;
     RECT  21.648 11.987 22.152 13.395 ;
     RECT  8.784 13.331 9.144 13.667 ;
     RECT  50.688 12.267 50.712 13.667 ;
     RECT  12.624 13.651 12.648 13.739 ;
     RECT  46.752 13.621 46.776 13.739 ;
     RECT  45.552 13.679 45.576 13.763 ;
     RECT  16.44 12.755 16.752 13.813 ;
     RECT  3.024 13.843 3.048 13.861 ;
     RECT  21.648 13.395 22.248 13.861 ;
     RECT  14.496 13.813 14.808 13.897 ;
     RECT  15.984 13.813 16.752 13.897 ;
     RECT  2.256 13.861 3.048 13.931 ;
     RECT  2.256 13.931 2.28 13.945 ;
     RECT  21.648 13.861 22.776 13.945 ;
     RECT  38.04 13.099 38.352 14.069 ;
     RECT  40.944 14.069 40.968 14.157 ;
     RECT  43.344 11.027 43.896 14.197 ;
     RECT  29.664 13.237 29.688 14.281 ;
     RECT  43.344 14.197 43.944 14.281 ;
     RECT  30.816 14.245 30.84 14.329 ;
     RECT  3.744 14.355 3.768 14.389 ;
     RECT  5.64 10.893 5.952 14.389 ;
     RECT  32.496 13.035 32.952 14.437 ;
     RECT  33.936 13.091 33.96 14.437 ;
     RECT  3.744 14.389 4.104 14.443 ;
     RECT  5.64 14.389 6.312 14.473 ;
     RECT  25.008 14.341 25.032 14.483 ;
     RECT  4.08 14.443 4.104 14.581 ;
     RECT  38.04 14.069 38.76 14.627 ;
     RECT  8.784 13.667 8.808 14.629 ;
     RECT  8.544 14.629 8.808 14.675 ;
     RECT  21.648 13.945 22.248 14.771 ;
     RECT  4.08 14.581 4.2 14.827 ;
     RECT  14.496 13.897 14.52 14.867 ;
     RECT  32.496 14.437 33.96 14.963 ;
     RECT  4.176 14.827 4.2 15.059 ;
     RECT  21.696 14.771 22.248 15.071 ;
     RECT  21.696 15.071 23.112 15.155 ;
     RECT  40.992 15.071 41.016 15.155 ;
     RECT  21.696 15.155 22.92 15.211 ;
     RECT  19.392 15.157 19.416 15.241 ;
     RECT  43.344 14.281 43.752 15.263 ;
     RECT  11.04 12.035 11.352 15.315 ;
     RECT  42.768 15.263 43.752 15.347 ;
     RECT  10.512 15.315 11.352 15.349 ;
     RECT  10.512 15.349 12.024 15.403 ;
     RECT  20.544 15.157 20.568 15.403 ;
     RECT  11.04 15.403 12.024 15.443 ;
     RECT  2.88 15.379 2.904 15.467 ;
     RECT  21.696 15.211 22.776 15.539 ;
     RECT  32.64 14.963 33.96 15.541 ;
     RECT  1.584 15.829 1.608 15.915 ;
     RECT  38.04 14.627 38.352 15.925 ;
     RECT  26.832 10.979 27.552 15.983 ;
     RECT  38.04 15.925 39.336 16.009 ;
     RECT  8.544 14.675 8.568 16.019 ;
     RECT  26.832 15.983 28.488 16.067 ;
     RECT  32.64 15.541 34.248 16.213 ;
     RECT  38.04 16.009 38.472 16.213 ;
     RECT  35.328 16.223 35.352 16.245 ;
     RECT  32.64 16.213 34.296 16.299 ;
     RECT  37.248 16.213 38.472 16.299 ;
     RECT  28.848 16.245 29.16 16.333 ;
     RECT  35.328 16.245 36.072 16.333 ;
     RECT  43.344 15.347 43.752 16.367 ;
     RECT  35.328 16.333 36.024 16.403 ;
     RECT  39.984 16.309 40.008 16.403 ;
     RECT  15.408 16.405 15.432 16.491 ;
     RECT  35.328 16.403 35.352 16.491 ;
     RECT  41.856 16.213 41.88 16.499 ;
     RECT  21.696 15.539 22.152 16.549 ;
     RECT  40.176 16.405 40.2 16.555 ;
     RECT  11.04 15.443 11.352 16.629 ;
     RECT  18.768 16.549 18.792 16.633 ;
     RECT  21.648 16.549 22.152 16.633 ;
     RECT  32.64 16.299 34.104 16.643 ;
     RECT  9.984 16.549 10.008 16.683 ;
     RECT  5.64 14.473 5.952 16.851 ;
     RECT  5.64 16.851 6.888 16.939 ;
     RECT  28.848 16.333 28.872 16.939 ;
     RECT  26.832 16.067 27.672 17.067 ;
     RECT  38.04 16.299 38.472 17.077 ;
     RECT  43.248 16.367 43.752 17.077 ;
     RECT  59.64 0.787 59.952 17.077 ;
     RECT  30.816 16.885 30.84 17.123 ;
     RECT  42.96 17.077 43.848 17.461 ;
     RECT  16.44 13.897 16.752 17.557 ;
     RECT  0.24 10.595 0.552 17.589 ;
     RECT  16.44 17.557 16.872 17.643 ;
     RECT  50.4 17.461 50.424 17.643 ;
     RECT  51.936 17.509 51.96 17.643 ;
     RECT  11.04 16.629 11.832 17.653 ;
     RECT  41.232 17.173 41.256 17.653 ;
     RECT  0.24 17.589 1.128 17.677 ;
     RECT  39.888 17.653 39.912 17.987 ;
     RECT  42.624 17.461 43.848 18.085 ;
     RECT  45.792 17.653 45.816 18.143 ;
     RECT  41.232 17.653 41.592 18.165 ;
     RECT  11.04 17.653 12.168 18.179 ;
     RECT  26.832 17.067 27.552 18.179 ;
     RECT  38.04 17.077 38.808 18.181 ;
     RECT  40.992 18.165 41.592 18.219 ;
     RECT  42.624 18.085 43.944 18.219 ;
     RECT  45.024 18.143 45.816 18.219 ;
     RECT  50.208 17.989 50.232 18.219 ;
     RECT  45.024 18.219 45.048 18.227 ;
     RECT  2.832 18.165 2.856 18.253 ;
     RECT  4.368 18.165 4.392 18.253 ;
     RECT  21.696 16.633 22.152 18.275 ;
     RECT  38.04 18.181 39.336 18.283 ;
     RECT  42.192 18.229 42.264 18.323 ;
     RECT  43.44 18.219 43.944 18.323 ;
     RECT  42.24 18.323 42.264 18.515 ;
     RECT  59.64 17.077 60.072 18.565 ;
     RECT  58.752 18.565 60.072 18.667 ;
     RECT  14.208 18.661 14.232 18.745 ;
     RECT  9.696 18.719 9.72 18.757 ;
     RECT  11.04 18.179 11.976 18.757 ;
     RECT  40.992 18.219 41.016 18.757 ;
     RECT  9.696 18.757 11.976 18.803 ;
     RECT  27.12 18.179 27.552 18.803 ;
     RECT  36.528 18.719 36.552 18.803 ;
     RECT  5.64 16.939 5.952 18.805 ;
     RECT  16.44 17.643 16.752 18.805 ;
     RECT  27.24 18.803 27.552 18.805 ;
     RECT  32.64 16.643 33.72 18.805 ;
     RECT  32.496 18.805 33.72 18.851 ;
     RECT  40.464 18.757 41.016 18.859 ;
     RECT  5.64 18.805 6.888 18.899 ;
     RECT  27.24 18.805 27.672 18.899 ;
     RECT  35.328 18.963 35.352 19.051 ;
     RECT  40.992 18.859 41.016 19.091 ;
     RECT  21.744 18.275 22.152 19.189 ;
     RECT  32.496 18.851 32.952 19.243 ;
     RECT  21.744 19.189 22.536 19.285 ;
     RECT  10.416 18.803 11.976 19.307 ;
     RECT  18.096 19.219 18.12 19.307 ;
     RECT  38.04 18.283 39.144 19.307 ;
     RECT  0.24 17.677 0.552 19.317 ;
     RECT  15.936 18.805 16.752 19.317 ;
     RECT  2.592 19.237 2.616 19.371 ;
     RECT  21.744 19.285 22.776 19.371 ;
     RECT  3.936 19.253 3.96 19.381 ;
     RECT  38.04 19.307 38.352 19.381 ;
     RECT  54.24 0.787 54.552 19.381 ;
     RECT  0.24 19.317 1.512 19.405 ;
     RECT  15.648 19.317 16.752 19.405 ;
     RECT  21.744 19.371 22.536 19.405 ;
     RECT  8.496 18.684 8.52 19.427 ;
     RECT  10.8 19.307 11.976 19.427 ;
     RECT  3.84 19.381 3.96 19.475 ;
     RECT  42.096 19.381 42.12 19.475 ;
     RECT  50.736 19.381 50.76 19.475 ;
     RECT  54.144 19.381 54.552 19.475 ;
     RECT  54.24 19.475 54.552 19.477 ;
     RECT  16.176 19.405 16.752 19.597 ;
     RECT  36.144 19.381 36.168 19.619 ;
     RECT  37.872 19.381 38.352 19.619 ;
     RECT  5.64 18.899 6.312 19.701 ;
     RECT  3.936 19.475 3.96 19.755 ;
     RECT  5.52 19.701 6.312 19.811 ;
     RECT  46.128 19.765 46.152 19.849 ;
     RECT  27.24 18.899 27.552 19.893 ;
     RECT  52.704 18.565 52.728 19.893 ;
     RECT  51.264 19.861 51.288 19.947 ;
     RECT  63.264 19.861 63.288 19.947 ;
     RECT  16.44 19.597 16.752 19.957 ;
     RECT  48.84 10.931 49.152 19.957 ;
     RECT  27.24 19.893 28.152 19.981 ;
     RECT  52.656 19.893 52.728 20.003 ;
     RECT  19.392 19.957 19.416 20.051 ;
     RECT  8.544 19.957 9.096 20.075 ;
     RECT  43.44 18.323 43.848 20.085 ;
     RECT  16.44 19.957 17.64 20.099 ;
     RECT  52.704 20.003 52.728 20.099 ;
     RECT  16.44 20.099 17.256 20.109 ;
     RECT  2.64 20.053 2.664 20.139 ;
     RECT  42.768 20.085 43.848 20.149 ;
     RECT  42.768 20.149 44.472 20.195 ;
     RECT  43.104 20.195 44.472 20.203 ;
     RECT  43.44 20.203 44.472 20.233 ;
     RECT  48.84 19.957 49.272 20.267 ;
     RECT  5.64 19.811 6.312 20.339 ;
     RECT  9.072 20.075 9.096 20.339 ;
     RECT  37.008 20.255 37.032 20.339 ;
     RECT  21.744 19.405 22.152 20.389 ;
     RECT  59.64 18.667 60.072 20.437 ;
     RECT  58.656 20.437 60.072 20.469 ;
     RECT  13.44 20.437 13.464 20.523 ;
     RECT  14.832 20.437 14.856 20.523 ;
     RECT  47.664 20.437 47.688 20.523 ;
     RECT  58.656 20.469 60.216 20.523 ;
     RECT  0.24 19.405 1.128 20.723 ;
     RECT  16.44 20.109 16.872 20.723 ;
     RECT  2.304 20.661 2.328 20.749 ;
     RECT  21.696 20.389 22.152 20.773 ;
     RECT  27.24 19.981 28.104 20.843 ;
     RECT  59.64 20.523 60.216 20.843 ;
     RECT  21.648 20.773 22.152 20.857 ;
     RECT  62.16 20.789 62.184 20.877 ;
     RECT  54.24 19.477 55.32 21.107 ;
     RECT  39.36 21.109 39.384 21.203 ;
     RECT  51.024 21.139 51.048 21.227 ;
     RECT  45.312 21.459 45.336 21.547 ;
     RECT  52.656 21.173 52.68 21.635 ;
     RECT  48.84 20.267 49.152 21.715 ;
     RECT  50.256 21.651 50.28 21.715 ;
     RECT  48.84 21.715 50.28 21.739 ;
     RECT  48.84 21.739 50.04 21.803 ;
     RECT  38.04 19.619 38.352 21.907 ;
     RECT  25.728 21.907 25.752 21.995 ;
     RECT  38.04 21.907 38.472 21.995 ;
     RECT  13.056 21.935 13.08 22.019 ;
     RECT  59.64 20.843 59.952 22.069 ;
     RECT  14.256 21.637 14.28 22.115 ;
     RECT  61.008 22.021 61.032 22.123 ;
     RECT  29.136 21.733 29.16 22.163 ;
     RECT  21.696 20.857 22.152 22.165 ;
     RECT  21.12 22.165 22.152 22.251 ;
     RECT  46.944 21.205 46.968 22.259 ;
     RECT  43.44 20.233 43.848 22.309 ;
     RECT  54.24 21.107 54.552 22.453 ;
     RECT  3.168 22.419 3.192 22.507 ;
     RECT  36.096 22.213 36.12 22.507 ;
     RECT  41.472 22.419 41.496 22.507 ;
     RECT  43.008 22.309 43.848 22.507 ;
     RECT  53.04 22.453 53.064 22.537 ;
     RECT  32.64 19.243 32.952 22.549 ;
     RECT  32.544 22.549 32.952 22.739 ;
     RECT  5.64 20.339 5.952 22.741 ;
     RECT  59.472 22.069 59.952 22.741 ;
     RECT  39.936 21.637 39.96 22.835 ;
     RECT  54.144 22.453 54.552 22.837 ;
     RECT  58.656 22.741 59.952 22.943 ;
     RECT  16.44 20.723 16.752 22.965 ;
     RECT  58.656 22.943 60.936 23.019 ;
     RECT  25.68 22.943 25.704 23.027 ;
     RECT  30.24 22.943 30.264 23.027 ;
     RECT  58.704 23.019 60.936 23.027 ;
     RECT  53.568 22.837 54.552 23.029 ;
     RECT  18.192 22.261 18.216 23.053 ;
     RECT  23.808 22.965 23.832 23.053 ;
     RECT  52.56 22.995 52.584 23.083 ;
     RECT  53.568 23.029 54.744 23.083 ;
     RECT  13.104 23.029 13.128 23.123 ;
     RECT  54.24 23.083 54.744 23.123 ;
     RECT  0.24 20.723 0.552 23.125 ;
     RECT  0.24 23.125 1.128 23.541 ;
     RECT  4.464 23.519 4.488 23.603 ;
     RECT  39.888 23.519 39.912 23.603 ;
     RECT  0.24 23.541 1.656 23.605 ;
     RECT  2.736 23.541 2.76 23.605 ;
     RECT  0.24 23.605 2.76 23.629 ;
     RECT  52.224 23.605 52.248 23.787 ;
     RECT  0.24 23.629 2.616 23.795 ;
     RECT  14.208 23.763 14.232 23.851 ;
     RECT  15.408 23.797 15.432 23.881 ;
     RECT  43.344 22.507 43.848 23.893 ;
     RECT  38.04 21.995 38.352 23.925 ;
     RECT  16.44 22.965 17.16 23.941 ;
     RECT  20.592 23.797 20.616 23.979 ;
     RECT  37.92 23.925 38.352 24.013 ;
     RECT  45.312 23.925 45.336 24.013 ;
     RECT  36.288 23.925 36.312 24.083 ;
     RECT  54.24 23.123 54.552 24.085 ;
     RECT  1.632 23.795 1.656 24.131 ;
     RECT  21.696 22.251 22.152 24.373 ;
     RECT  43.344 23.893 43.896 24.419 ;
     RECT  11.04 19.427 11.976 24.431 ;
     RECT  13.104 24.373 13.128 24.431 ;
     RECT  48.84 21.803 49.152 24.437 ;
     RECT  58.704 23.027 59.952 24.437 ;
     RECT  62.64 24.373 63.288 24.457 ;
     RECT  21.648 24.373 22.152 24.467 ;
     RECT  27.24 20.843 27.552 24.469 ;
     RECT  5.64 22.741 6.6 24.479 ;
     RECT  11.04 24.431 13.128 24.491 ;
     RECT  30.72 24.403 30.744 24.491 ;
     RECT  50.736 24.421 50.76 24.505 ;
     RECT  11.04 24.491 12.504 24.515 ;
     RECT  5.64 24.479 7.464 24.555 ;
     RECT  27.12 24.469 27.552 24.555 ;
     RECT  53.568 24.085 54.552 24.555 ;
     RECT  7.44 24.555 7.464 24.563 ;
     RECT  25.632 24.479 25.656 24.563 ;
     RECT  58.704 24.437 60.744 24.563 ;
     RECT  62.64 24.457 62.664 24.563 ;
     RECT  59.64 24.563 60.744 24.659 ;
     RECT  54.144 24.555 54.552 24.755 ;
     RECT  3.936 24.821 3.96 24.909 ;
     RECT  47.904 24.437 49.152 24.979 ;
     RECT  40.56 24.979 40.584 25.067 ;
     RECT  47.808 24.979 49.152 25.067 ;
     RECT  41.904 25.077 41.928 25.165 ;
     RECT  46.704 24.431 46.728 25.225 ;
     RECT  48.72 25.067 49.152 25.235 ;
     RECT  38.04 24.013 38.352 25.397 ;
     RECT  16.44 23.941 17.544 25.451 ;
     RECT  18.816 25.397 18.84 25.485 ;
     RECT  38.04 25.397 38.472 25.485 ;
     RECT  27.24 24.555 27.552 25.555 ;
     RECT  27.24 25.555 28.488 25.643 ;
     RECT  5.64 24.555 5.952 25.66 ;
     RECT  20.64 25.631 20.664 25.715 ;
     RECT  30 25.589 30.024 25.715 ;
     RECT  0.24 23.795 0.552 25.717 ;
     RECT  3.84 25.683 3.864 25.771 ;
     RECT  61.008 25.717 61.032 25.801 ;
     RECT  40.032 25.813 40.056 25.899 ;
     RECT  0.24 25.717 0.696 25.955 ;
     RECT  2.448 25.717 2.472 26.003 ;
     RECT  5.232 25.66 5.952 26.003 ;
     RECT  43.44 24.419 43.896 26.005 ;
     RECT  11.04 24.515 11.976 26.147 ;
     RECT  59.64 24.659 59.952 26.197 ;
     RECT  9.936 26.131 9.96 26.219 ;
     RECT  13.488 26.131 13.512 26.219 ;
     RECT  59.64 26.197 60.984 26.229 ;
     RECT  7.968 26.149 7.992 26.233 ;
     RECT  50.736 26.197 50.76 26.283 ;
     RECT  58.992 26.229 60.984 26.283 ;
     RECT  3.408 26.207 3.432 26.291 ;
     RECT  58.992 26.283 59.952 26.483 ;
     RECT  27.24 25.643 27.552 26.485 ;
     RECT  11.04 26.147 11.928 26.539 ;
     RECT  26.88 26.485 27.552 26.579 ;
     RECT  54.24 24.755 54.552 26.613 ;
     RECT  43.344 26.005 43.944 26.675 ;
     RECT  54.24 26.613 54.744 26.701 ;
     RECT  57.888 26.629 57.912 26.731 ;
     RECT  60.96 26.283 60.984 26.795 ;
     RECT  62.448 26.707 62.472 26.795 ;
     RECT  55.872 26.613 55.896 26.819 ;
     RECT  30.768 26.783 30.792 26.867 ;
     RECT  43.344 26.675 43.896 26.867 ;
     RECT  12.528 27.359 12.552 27.443 ;
     RECT  5.64 26.003 5.952 27.509 ;
     RECT  6.96 27.503 6.984 27.509 ;
     RECT  32.64 22.739 32.952 27.509 ;
     RECT  5.52 27.509 6.984 27.587 ;
     RECT  56.976 27.503 57 27.587 ;
     RECT  9.936 27.551 9.96 27.589 ;
     RECT  11.04 26.539 11.352 27.589 ;
     RECT  31.104 27.509 31.128 27.597 ;
     RECT  5.52 27.587 6.84 27.635 ;
     RECT  9.936 27.589 11.352 27.635 ;
     RECT  10.8 27.635 11.352 27.691 ;
     RECT  47.52 27.301 47.544 27.733 ;
     RECT  3.312 27.765 3.336 27.875 ;
     RECT  4.32 27.765 4.344 27.875 ;
     RECT  47.04 27.733 47.544 27.883 ;
     RECT  12.912 27.829 12.936 27.971 ;
     RECT  32.544 27.509 32.952 28.211 ;
     RECT  59.64 26.483 59.952 28.371 ;
     RECT  59.64 28.371 60.84 28.459 ;
     RECT  45.552 28.405 45.576 28.489 ;
     RECT  47.52 27.883 47.544 28.547 ;
     RECT  5.64 27.635 6.84 28.981 ;
     RECT  32.64 28.211 32.952 28.981 ;
     RECT  38.04 25.485 38.352 28.981 ;
     RECT  39.36 28.453 39.384 28.981 ;
     RECT  5.136 28.981 6.84 29.027 ;
     RECT  3.312 28.947 3.336 29.035 ;
     RECT  35.232 28.947 35.256 29.035 ;
     RECT  41.184 28.947 41.208 29.035 ;
     RECT  57.936 28.947 57.96 29.035 ;
     RECT  62.256 28.405 62.28 29.035 ;
     RECT  32.64 28.981 33.624 29.065 ;
     RECT  37.008 28.981 37.032 29.065 ;
     RECT  38.04 28.981 39.384 29.123 ;
     RECT  58.368 29.039 58.392 29.123 ;
     RECT  8.16 29.203 8.184 29.221 ;
     RECT  38.04 29.123 38.52 29.267 ;
     RECT  43.44 26.867 43.896 29.301 ;
     RECT  7.824 29.221 8.184 29.355 ;
     RECT  42.144 29.279 42.168 29.363 ;
     RECT  3.504 29.331 3.96 29.419 ;
     RECT  10.896 27.691 11.352 29.429 ;
     RECT  21.84 24.467 22.152 29.471 ;
     RECT  21.84 29.471 22.776 29.555 ;
     RECT  45.552 29.471 45.576 29.555 ;
     RECT  46.752 29.471 46.776 29.555 ;
     RECT  3.504 29.419 3.528 29.581 ;
     RECT  24.096 29.493 24.12 29.581 ;
     RECT  10.896 29.429 11.64 29.603 ;
     RECT  5.136 29.027 6.072 29.611 ;
     RECT  8.64 29.429 8.664 29.611 ;
     RECT  10.896 29.603 11.448 29.611 ;
     RECT  5.136 29.611 5.952 29.699 ;
     RECT  9.696 29.237 9.72 29.699 ;
     RECT  51.696 29.615 51.72 29.699 ;
     RECT  43.44 29.301 44.472 29.747 ;
     RECT  13.632 29.941 13.656 30.025 ;
     RECT  27.24 26.579 27.552 30.181 ;
     RECT  32.64 29.065 32.952 30.181 ;
     RECT  14.832 29.941 14.856 30.467 ;
     RECT  43.44 29.747 44.136 30.469 ;
     RECT  54.24 26.701 54.552 30.469 ;
     RECT  38.04 29.267 38.352 30.565 ;
     RECT  53.568 30.469 54.552 30.571 ;
     RECT  33.936 30.517 33.96 30.611 ;
     RECT  38.04 30.565 38.76 30.649 ;
     RECT  18.864 30.645 18.888 30.661 ;
     RECT  51.312 30.181 51.336 30.661 ;
     RECT  5.64 29.699 5.952 30.675 ;
     RECT  31.728 30.181 32.952 30.755 ;
     RECT  39.936 30.581 39.96 30.755 ;
     RECT  55.536 30.517 55.56 30.755 ;
     RECT  5.136 30.675 5.952 30.763 ;
     RECT  18.768 30.661 18.888 30.803 ;
     RECT  50.688 30.661 51.336 30.803 ;
     RECT  10.896 29.611 11.352 30.837 ;
     RECT  20.352 30.645 20.376 30.851 ;
     RECT  31.776 30.755 32.952 30.851 ;
     RECT  45.744 30.709 45.768 30.867 ;
     RECT  48.84 25.235 49.152 30.867 ;
     RECT  51.312 30.803 51.336 30.899 ;
     RECT  43.344 30.469 44.136 30.901 ;
     RECT  45.744 30.867 46.536 30.955 ;
     RECT  47.904 30.867 49.152 30.955 ;
     RECT  43.344 30.901 44.664 30.995 ;
     RECT  10.464 30.837 12.312 31.083 ;
     RECT  14.256 31.007 14.28 31.091 ;
     RECT  29.136 30.181 29.16 31.091 ;
     RECT  26.016 31.059 26.04 31.147 ;
     RECT  21.84 29.555 22.152 31.157 ;
     RECT  24.48 31.093 24.504 31.177 ;
     RECT  36.288 31.141 36.312 31.189 ;
     RECT  20.496 31.157 22.152 31.221 ;
     RECT  13.104 31.141 13.128 31.225 ;
     RECT  36.288 31.189 36.984 31.333 ;
     RECT  38.04 30.649 38.352 31.333 ;
     RECT  20.496 31.221 22.392 31.339 ;
     RECT  61.584 31.237 61.608 31.339 ;
     RECT  0.24 25.955 0.552 31.349 ;
     RECT  20.496 31.339 20.52 31.369 ;
     RECT  3.408 31.343 3.432 31.381 ;
     RECT  2.112 30.949 2.136 31.403 ;
     RECT  21.744 31.339 22.392 31.403 ;
     RECT  5.64 30.763 5.952 31.413 ;
     RECT  27.24 30.181 27.672 31.417 ;
     RECT  3.408 31.381 3.96 31.427 ;
     RECT  63.264 31.343 63.288 31.427 ;
     RECT  0.24 31.349 1.032 31.437 ;
     RECT  3.936 31.427 3.96 31.467 ;
     RECT  7.488 31.413 7.512 31.501 ;
     RECT  35.28 31.477 35.304 31.715 ;
     RECT  36.288 31.333 38.352 31.723 ;
     RECT  59.64 28.459 59.952 31.765 ;
     RECT  58.752 31.765 59.952 31.891 ;
     RECT  30.24 31.045 30.264 31.915 ;
     RECT  5.64 31.413 6.216 31.955 ;
     RECT  21.744 31.403 22.152 31.979 ;
     RECT  58.752 31.891 60.936 31.979 ;
     RECT  23.376 31.919 23.4 32.003 ;
     RECT  56.976 31.919 57 32.003 ;
     RECT  31.344 31.861 31.368 32.051 ;
     RECT  37.824 31.723 38.352 32.107 ;
     RECT  43.344 30.995 43.752 32.117 ;
     RECT  42.576 32.117 43.752 32.181 ;
     RECT  34.272 31.669 34.296 32.197 ;
     RECT  42.576 32.181 44.136 32.205 ;
     RECT  42.672 32.205 44.136 32.235 ;
     RECT  34.176 32.197 34.296 32.245 ;
     RECT  42.768 32.235 44.136 32.269 ;
     RECT  10.464 31.083 11.352 32.293 ;
     RECT  34.176 32.245 34.584 32.299 ;
     RECT  35.616 32.211 35.64 32.299 ;
     RECT  45.504 32.181 45.528 32.351 ;
     RECT  10.224 32.293 11.352 32.377 ;
     RECT  14.256 32.293 14.28 32.377 ;
     RECT  47.328 32.341 47.352 32.427 ;
     RECT  45.504 32.351 45.576 32.435 ;
     RECT  32.64 30.851 32.952 32.485 ;
     RECT  32.448 32.485 32.952 32.495 ;
     RECT  45.024 32.437 45.048 32.521 ;
     RECT  27.24 31.417 27.552 32.543 ;
     RECT  40.992 32.101 41.016 32.543 ;
     RECT  27.24 32.543 27.96 32.565 ;
     RECT  32.256 32.495 32.952 32.579 ;
     RECT  26.64 32.565 27.96 32.581 ;
     RECT  29.088 31.525 29.112 32.581 ;
     RECT  40.992 32.543 41.64 32.627 ;
     RECT  40.992 32.627 41.448 32.629 ;
     RECT  25.632 32.565 25.656 32.653 ;
     RECT  26.64 32.581 29.112 32.683 ;
     RECT  3.264 32.437 3.288 32.687 ;
     RECT  5.64 31.955 5.952 32.693 ;
     RECT  38.04 32.107 38.352 32.693 ;
     RECT  39.6 32.565 39.624 32.693 ;
     RECT  2.832 32.687 3.288 32.747 ;
     RECT  2.832 32.747 2.856 32.771 ;
     RECT  34.56 32.299 34.584 32.771 ;
     RECT  4.704 32.693 5.952 32.773 ;
     RECT  51.648 32.787 51.672 32.821 ;
     RECT  48.84 30.955 49.152 32.869 ;
     RECT  4.08 32.773 5.952 32.875 ;
     RECT  50.688 32.821 51.672 32.875 ;
     RECT  10.32 32.377 11.352 32.939 ;
     RECT  42.768 32.269 43.752 32.953 ;
     RECT  47.904 32.869 49.152 32.953 ;
     RECT  46.704 32.879 46.728 32.963 ;
     RECT  42.912 32.953 43.752 32.973 ;
     RECT  32.64 32.579 32.952 32.979 ;
     RECT  54.24 30.571 54.552 33.013 ;
     RECT  38.04 32.693 39.624 33.059 ;
     RECT  2.784 32.979 2.808 33.067 ;
     RECT  32.64 32.979 33.048 33.067 ;
     RECT  13.68 33.013 13.704 33.097 ;
     RECT  54.24 33.013 54.648 33.097 ;
     RECT  40.608 32.629 41.448 33.155 ;
     RECT  30.912 33.109 30.936 33.195 ;
     RECT  58.128 33.013 58.152 33.259 ;
     RECT  56.64 33.205 56.664 33.299 ;
     RECT  28.56 32.683 29.112 33.347 ;
     RECT  46.176 33.269 46.2 33.491 ;
     RECT  29.088 33.347 29.112 33.683 ;
     RECT  4.704 32.875 5.952 33.811 ;
     RECT  59.64 31.979 59.952 33.829 ;
     RECT  36.96 33.637 36.984 33.835 ;
     RECT  61.632 33.747 61.656 33.835 ;
     RECT  63.264 33.589 63.288 33.835 ;
     RECT  59.64 33.829 60.408 33.839 ;
     RECT  4.704 33.811 6.744 33.899 ;
     RECT  30 33.685 30.024 33.899 ;
     RECT  40.128 33.811 40.152 33.899 ;
     RECT  12.672 33.829 12.696 33.913 ;
     RECT  41.616 33.839 41.64 33.923 ;
     RECT  58.656 33.839 60.408 33.923 ;
     RECT  31.392 33.845 31.416 33.933 ;
     RECT  21.84 31.979 22.152 34.165 ;
     RECT  38.04 33.059 38.952 34.165 ;
     RECT  26.64 32.683 27.552 34.259 ;
     RECT  4.704 33.899 5.952 34.323 ;
     RECT  43.44 32.973 43.752 34.323 ;
     RECT  43.44 34.323 44.568 34.357 ;
     RECT  3.84 34.323 5.952 34.411 ;
     RECT  36 34.165 36.024 34.411 ;
     RECT  40.224 34.213 40.248 34.411 ;
     RECT  32.64 33.067 32.952 34.421 ;
     RECT  10.512 32.939 11.352 34.453 ;
     RECT  48.84 32.953 49.152 34.453 ;
     RECT  34.8 34.415 34.824 34.499 ;
     RECT  32.64 34.421 33.288 34.509 ;
     RECT  9.696 34.453 11.352 34.539 ;
     RECT  4.416 34.411 5.952 34.643 ;
     RECT  48.384 34.453 49.152 34.645 ;
     RECT  0.24 31.437 0.552 34.707 ;
     RECT  42.72 34.357 44.568 34.707 ;
     RECT  59.64 33.923 60.408 34.707 ;
     RECT  2.784 34.645 2.808 34.731 ;
     RECT  10.032 34.539 11.352 34.731 ;
     RECT  42.096 34.707 44.568 34.731 ;
     RECT  47.904 34.645 49.152 34.731 ;
     RECT  50.688 32.875 50.712 34.741 ;
     RECT  0.144 34.707 0.552 34.795 ;
     RECT  19.968 34.693 19.992 34.795 ;
     RECT  32.64 34.509 33.096 34.795 ;
     RECT  42.096 34.731 43.752 34.795 ;
     RECT  53.088 34.707 53.112 34.795 ;
     RECT  59.64 34.707 60.696 34.795 ;
     RECT  37.824 34.165 38.952 34.805 ;
     RECT  5.136 34.643 5.952 34.835 ;
     RECT  54.24 33.097 54.552 34.847 ;
     RECT  36.48 34.799 36.504 34.883 ;
     RECT  37.632 34.805 38.952 34.899 ;
     RECT  2.304 34.789 2.376 34.923 ;
     RECT  7.92 34.357 7.944 34.931 ;
     RECT  54.24 34.847 54.696 34.931 ;
     RECT  30.672 34.899 30.696 34.987 ;
     RECT  37.632 34.899 39.048 34.987 ;
     RECT  23.184 34.963 23.208 35.051 ;
     RECT  7.968 34.981 7.992 35.065 ;
     RECT  10.032 34.731 10.056 35.149 ;
     RECT  42.192 34.795 43.752 35.179 ;
     RECT  26.976 34.259 27.552 35.221 ;
     RECT  37.632 34.987 38.352 35.221 ;
     RECT  46.752 35.173 46.776 35.257 ;
     RECT  25.152 34.997 25.176 35.267 ;
     RECT  48.48 34.731 49.152 35.269 ;
     RECT  50.688 34.741 51.048 35.269 ;
     RECT  37.104 35.221 38.352 35.307 ;
     RECT  42.192 35.179 42.216 35.315 ;
     RECT  48.48 35.269 51.048 35.381 ;
     RECT  48.48 35.381 51.336 35.475 ;
     RECT  2.352 34.923 2.376 35.499 ;
     RECT  45.6 35.423 45.624 35.507 ;
     RECT  8.592 35.445 8.616 35.533 ;
     RECT  31.2 35.445 31.224 35.555 ;
     RECT  48.48 35.475 51.624 35.627 ;
     RECT  46.704 35.317 46.728 35.699 ;
     RECT  14.208 34.453 14.232 35.701 ;
     RECT  23.904 35.509 23.928 35.701 ;
     RECT  13.68 35.701 14.232 35.755 ;
     RECT  48.72 35.627 51.624 35.755 ;
     RECT  15.408 35.701 15.432 35.795 ;
     RECT  11.04 34.731 11.352 35.797 ;
     RECT  21.648 34.165 22.152 35.843 ;
     RECT  51.312 35.755 51.624 35.843 ;
     RECT  2.688 35.701 2.712 35.845 ;
     RECT  19.92 35.765 19.944 35.853 ;
     RECT  2.688 35.845 2.856 35.883 ;
     RECT  11.04 35.797 12.264 35.883 ;
     RECT  48.72 35.755 49.152 35.883 ;
     RECT  51.6 35.843 51.624 35.883 ;
     RECT  13.68 35.755 13.704 35.891 ;
     RECT  11.04 35.883 11.352 35.893 ;
     RECT  59.64 34.795 59.952 35.893 ;
     RECT  2.832 35.883 2.856 35.941 ;
     RECT  0.24 34.795 0.552 35.957 ;
     RECT  10.128 35.893 11.352 35.987 ;
     RECT  59.64 35.893 60.648 35.987 ;
     RECT  54.24 34.931 54.552 35.999 ;
     RECT  2.832 35.941 3.432 36.011 ;
     RECT  21.84 35.843 22.152 36.021 ;
     RECT  3.408 36.011 3.432 36.025 ;
     RECT  0.144 35.957 0.552 36.045 ;
     RECT  54.24 35.999 54.744 36.083 ;
     RECT  26.208 35.221 27.552 36.139 ;
     RECT  51.84 36.051 52.584 36.139 ;
     RECT  21.84 36.021 22.392 36.203 ;
     RECT  23.904 35.701 24.36 36.331 ;
     RECT  26.16 36.243 26.184 36.331 ;
     RECT  59.64 35.987 59.952 36.421 ;
     RECT  29.088 36.373 29.112 36.459 ;
     RECT  31.344 36.373 31.368 36.459 ;
     RECT  35.232 36.373 35.256 36.459 ;
     RECT  51.84 36.139 52.152 36.459 ;
     RECT  5.64 34.835 5.952 36.469 ;
     RECT  18.816 35.989 18.84 36.515 ;
     RECT  24.336 36.331 24.36 36.515 ;
     RECT  57.6 35.269 57.624 36.515 ;
     RECT  20.208 36.435 20.232 36.523 ;
     RECT  32.64 34.795 32.952 36.533 ;
     RECT  51.84 36.459 51.864 36.553 ;
     RECT  61.008 36.469 61.032 36.553 ;
     RECT  25.536 36.499 25.56 36.587 ;
     RECT  31.872 36.533 32.952 36.621 ;
     RECT  29.472 36.613 29.496 36.715 ;
     RECT  5.64 36.469 6.264 36.949 ;
     RECT  43.44 35.179 43.752 36.959 ;
     RECT  56.304 36.421 56.328 36.971 ;
     RECT  5.088 36.949 6.264 36.981 ;
     RECT  43.344 36.959 43.752 37.011 ;
     RECT  48.84 35.883 49.152 37.045 ;
     RECT  5.088 36.981 6.888 37.091 ;
     RECT  58.704 36.421 59.952 37.091 ;
     RECT  53.136 36.661 53.16 37.099 ;
     RECT  46.224 37.075 46.248 37.151 ;
     RECT  46.176 37.151 46.248 37.235 ;
     RECT  5.088 37.091 5.952 37.301 ;
     RECT  32.64 36.621 32.952 37.365 ;
     RECT  38.04 35.307 38.352 37.365 ;
     RECT  13.104 37.285 13.128 37.369 ;
     RECT  50.784 37.045 50.808 37.379 ;
     RECT  2.784 37.301 2.808 37.389 ;
     RECT  4.704 37.301 5.952 37.389 ;
     RECT  21.84 36.203 22.152 37.395 ;
     RECT  54.24 36.083 54.552 37.395 ;
     RECT  48.24 37.045 49.368 37.429 ;
     RECT  21.12 37.395 22.152 37.483 ;
     RECT  53.184 37.395 54.552 37.483 ;
     RECT  43.344 37.011 44.712 37.493 ;
     RECT  38.04 37.365 38.472 37.535 ;
     RECT  42.72 37.493 44.712 37.547 ;
     RECT  11.04 35.987 11.352 37.557 ;
     RECT  30.576 37.365 30.6 37.557 ;
     RECT  36.432 37.535 36.456 37.557 ;
     RECT  37.92 37.535 38.472 37.557 ;
     RECT  42.72 37.547 43.752 37.557 ;
     RECT  42.672 37.557 43.752 37.573 ;
     RECT  46.224 37.235 46.248 37.611 ;
     RECT  48 37.429 49.368 37.611 ;
     RECT  32.64 37.365 33.096 37.621 ;
     RECT  37.632 37.557 39.432 37.621 ;
     RECT  11.04 37.557 11.64 37.645 ;
     RECT  24.336 37.557 24.36 37.645 ;
     RECT  28.704 37.557 28.728 37.645 ;
     RECT  36.288 37.557 36.456 37.645 ;
     RECT  44.784 37.557 44.808 37.645 ;
     RECT  32.64 37.621 33.192 37.651 ;
     RECT  34.8 37.557 34.824 37.651 ;
     RECT  37.632 37.621 39.624 37.669 ;
     RECT  41.904 37.573 43.752 37.675 ;
     RECT  32.64 37.651 34.824 37.739 ;
     RECT  34.8 37.739 34.824 37.811 ;
     RECT  4.176 37.843 4.2 37.931 ;
     RECT  30.48 37.557 30.6 38.005 ;
     RECT  32.64 37.739 33.48 38.005 ;
     RECT  14.208 37.957 14.232 38.059 ;
     RECT  30.48 38.005 33.48 38.099 ;
     RECT  27.24 36.139 27.552 38.101 ;
     RECT  48.72 37.611 49.368 38.111 ;
     RECT  30.48 38.099 31.368 38.133 ;
     RECT  16.44 25.451 16.752 38.149 ;
     RECT  25.152 38.069 25.176 38.157 ;
     RECT  3.936 38.101 3.96 38.187 ;
     RECT  27.24 38.101 28.248 38.187 ;
     RECT  30.144 38.133 31.368 38.187 ;
     RECT  36.96 37.669 39.624 38.187 ;
     RECT  42.144 37.675 43.752 38.187 ;
     RECT  7.392 38.111 7.416 38.195 ;
     RECT  21.6 37.483 22.152 38.195 ;
     RECT  39.6 38.187 39.624 38.195 ;
     RECT  48.72 38.111 49.56 38.195 ;
     RECT  8.688 35.845 8.712 38.221 ;
     RECT  20.496 38.133 20.52 38.221 ;
     RECT  26.16 38.133 26.184 38.221 ;
     RECT  30.144 38.187 30.552 38.221 ;
     RECT  32.544 38.099 33.48 38.221 ;
     RECT  48.72 38.195 49.272 38.221 ;
     RECT  42.72 38.187 43.752 38.243 ;
     RECT  13.152 38.197 13.176 38.387 ;
     RECT  46.896 38.325 46.92 38.435 ;
     RECT  21.84 38.195 22.152 38.437 ;
     RECT  21.84 38.437 22.776 38.521 ;
     RECT  5.64 37.389 5.952 38.611 ;
     RECT  53.184 37.483 53.208 38.611 ;
     RECT  48.84 38.221 49.272 38.635 ;
     RECT  56.064 38.547 56.088 38.635 ;
     RECT  18.72 38.581 19.368 38.665 ;
     RECT  34.944 38.581 34.968 38.675 ;
     RECT  52.416 38.611 53.208 38.699 ;
     RECT  40.176 38.629 40.2 38.713 ;
     RECT  58.416 38.629 58.44 38.713 ;
     RECT  32.64 38.221 33.48 38.733 ;
     RECT  47.328 38.645 47.352 38.733 ;
     RECT  18.72 38.665 18.744 38.867 ;
     RECT  36.96 38.187 38.352 39.011 ;
     RECT  53.184 38.699 53.208 39.011 ;
     RECT  16.44 38.149 17.592 39.059 ;
     RECT  54.24 37.483 54.552 39.123 ;
     RECT  43.296 38.243 43.752 39.157 ;
     RECT  5.52 38.611 5.952 39.205 ;
     RECT  30.528 38.221 30.552 39.205 ;
     RECT  37.104 39.011 38.352 39.211 ;
     RECT  40.944 39.013 41.112 39.211 ;
     RECT  47.376 39.013 47.4 39.211 ;
     RECT  50.592 39.013 50.616 39.211 ;
     RECT  54 39.123 54.552 39.211 ;
     RECT  57.696 39.061 57.72 39.211 ;
     RECT  30.528 39.205 30.696 39.221 ;
     RECT  5.136 39.205 5.952 39.289 ;
     RECT  23.376 39.205 23.4 39.289 ;
     RECT  30.336 39.221 30.696 39.289 ;
     RECT  2.784 39.221 2.808 39.301 ;
     RECT  43.296 39.157 43.944 39.301 ;
     RECT  30.336 39.289 30.36 39.309 ;
     RECT  27.24 38.187 27.552 39.349 ;
     RECT  21.84 38.521 22.152 39.589 ;
     RECT  59.64 37.091 59.952 39.589 ;
     RECT  11.04 37.645 11.352 39.637 ;
     RECT  10.368 39.637 11.352 39.699 ;
     RECT  21.744 39.589 22.152 39.733 ;
     RECT  27.24 39.349 27.672 39.733 ;
     RECT  42.768 39.301 43.944 39.733 ;
     RECT  0.24 36.045 0.552 39.763 ;
     RECT  8.64 39.253 8.664 39.787 ;
     RECT  10.368 39.699 11.448 39.787 ;
     RECT  25.2 39.493 25.224 39.787 ;
     RECT  26.736 39.733 27.672 39.787 ;
     RECT  34.608 39.699 34.632 39.787 ;
     RECT  59.64 39.589 60.072 39.787 ;
     RECT  2.4 39.301 2.808 39.791 ;
     RECT  0.24 39.763 0.648 39.851 ;
     RECT  2.304 39.791 2.808 39.875 ;
     RECT  5.64 39.289 5.952 39.877 ;
     RECT  25.584 39.829 25.608 39.915 ;
     RECT  42.048 39.733 43.944 39.915 ;
     RECT  40.416 39.839 40.44 39.923 ;
     RECT  48.84 38.635 49.152 39.925 ;
     RECT  48.72 39.925 49.152 40.019 ;
     RECT  56.352 39.925 56.376 40.019 ;
     RECT  42.48 39.915 43.944 40.021 ;
     RECT  42.48 40.021 44.568 40.107 ;
     RECT  42.624 40.107 43.752 40.115 ;
     RECT  48.84 40.019 49.152 40.117 ;
     RECT  16.44 39.059 16.752 40.165 ;
     RECT  54.144 39.211 54.552 40.165 ;
     RECT  54.144 40.165 55.32 40.181 ;
     RECT  54 40.181 55.32 40.249 ;
     RECT  21.264 39.733 22.152 40.259 ;
     RECT  54 40.249 54.552 40.275 ;
     RECT  41.472 40.261 41.496 40.363 ;
     RECT  48.84 40.117 49.56 40.363 ;
     RECT  53.616 40.275 54.552 40.363 ;
     RECT  38.04 39.211 38.352 40.405 ;
     RECT  15.696 40.165 16.752 40.437 ;
     RECT  5.64 39.877 6.888 40.491 ;
     RECT  15.696 40.437 16.872 40.491 ;
     RECT  37.92 40.405 38.52 40.491 ;
     RECT  50.88 40.405 50.904 40.491 ;
     RECT  16.44 40.491 16.872 40.747 ;
     RECT  3.984 39.797 4.008 40.757 ;
     RECT  40.992 40.693 41.016 40.777 ;
     RECT  59.64 39.787 59.952 40.821 ;
     RECT  3.984 40.757 4.296 40.845 ;
     RECT  61.776 40.799 61.8 40.883 ;
     RECT  59.64 40.821 60.12 40.909 ;
     RECT  32.64 38.733 32.952 40.933 ;
     RECT  30.528 40.837 30.552 40.939 ;
     RECT  44.88 40.837 44.904 40.939 ;
     RECT  34.752 40.885 34.776 40.969 ;
     RECT  32.64 40.933 33.672 41.017 ;
     RECT  58.464 40.991 58.488 41.075 ;
     RECT  37.92 40.491 38.352 41.077 ;
     RECT  51.888 40.949 51.912 41.123 ;
     RECT  30.624 41.077 30.648 41.171 ;
     RECT  11.04 39.787 11.352 41.221 ;
     RECT  2.88 41.205 2.904 41.333 ;
     RECT  26.736 39.787 27.552 41.333 ;
     RECT  7.056 41.269 7.08 41.411 ;
     RECT  2.256 41.333 2.904 41.421 ;
     RECT  24.816 41.333 24.84 41.421 ;
     RECT  25.872 41.333 27.552 41.421 ;
     RECT  2.832 41.421 2.904 41.509 ;
     RECT  3.984 40.845 4.008 41.509 ;
     RECT  21.84 40.259 22.152 41.589 ;
     RECT  2.832 41.509 4.008 41.593 ;
     RECT  47.28 41.509 47.304 41.593 ;
     RECT  5.64 40.491 5.952 41.619 ;
     RECT  21.744 41.589 22.152 41.653 ;
     RECT  2.832 41.593 3 41.699 ;
     RECT  3.984 41.593 4.008 41.707 ;
     RECT  5.64 41.619 6.312 41.707 ;
     RECT  34.128 41.221 34.152 41.707 ;
     RECT  32.64 41.017 33.048 41.737 ;
     RECT  2.832 41.699 2.856 41.747 ;
     RECT  37.68 41.077 38.352 41.747 ;
     RECT  13.2 41.413 13.224 41.749 ;
     RECT  48.84 40.363 49.152 41.749 ;
     RECT  32.64 41.737 32.952 41.781 ;
     RECT  12.96 41.749 14.04 41.835 ;
     RECT  48.84 41.749 49.896 41.835 ;
     RECT  5.64 41.707 6.072 41.845 ;
     RECT  54.24 40.363 54.552 41.845 ;
     RECT  40.32 41.221 40.344 41.893 ;
     RECT  10.944 41.221 11.592 41.909 ;
     RECT  4.752 41.845 6.072 41.939 ;
     RECT  19.968 40.405 19.992 41.939 ;
     RECT  53.904 41.845 54.552 41.939 ;
     RECT  16.44 40.747 16.752 41.973 ;
     RECT  46.752 41.893 46.776 41.977 ;
     RECT  13.152 41.835 13.224 41.99 ;
     RECT  32.304 41.781 32.952 42.061 ;
     RECT  42.096 41.973 42.12 42.061 ;
     RECT  13.152 41.99 13.176 42.091 ;
     RECT  9.744 42.037 9.768 42.095 ;
     RECT  30.768 42.085 30.792 42.133 ;
     RECT  16.44 41.973 17.4 42.143 ;
     RECT  43.344 40.115 43.752 42.143 ;
     RECT  26.736 41.421 27.552 42.165 ;
     RECT  42.768 42.143 43.752 42.165 ;
     RECT  8.016 42.101 8.04 42.189 ;
     RECT  25.392 41.749 25.656 42.219 ;
     RECT  26.736 42.165 27.768 42.219 ;
     RECT  30.768 42.133 30.936 42.219 ;
     RECT  16.44 42.143 17.544 42.227 ;
     RECT  18.528 41.557 18.552 42.227 ;
     RECT  21.648 41.653 22.152 42.227 ;
     RECT  29.616 42.143 29.64 42.227 ;
     RECT  42.768 42.165 44.568 42.227 ;
     RECT  40.32 41.893 41.064 42.229 ;
     RECT  40.32 42.229 41.64 42.313 ;
     RECT  40.32 42.313 41.496 42.323 ;
     RECT  40.32 42.323 40.344 42.325 ;
     RECT  30.48 42.259 30.504 42.347 ;
     RECT  41.472 42.323 41.496 42.347 ;
     RECT  43.296 42.227 44.568 42.387 ;
     RECT  40.176 42.325 40.344 42.419 ;
     RECT  9.648 42.095 9.768 42.421 ;
     RECT  25.392 42.219 25.416 42.467 ;
     RECT  59.64 40.909 59.952 42.469 ;
     RECT  9.12 42.421 9.768 42.505 ;
     RECT  43.296 42.387 44.808 42.549 ;
     RECT  59.64 42.469 60.408 42.553 ;
     RECT  43.296 42.549 45 42.579 ;
     RECT  46.32 42.165 46.344 42.579 ;
     RECT  43.296 42.579 46.344 42.611 ;
     RECT  10.848 41.909 11.592 42.613 ;
     RECT  27.24 42.219 27.768 42.613 ;
     RECT  54.24 41.939 54.552 42.661 ;
     RECT  5.136 41.939 6.072 42.667 ;
     RECT  37.92 41.747 38.352 42.677 ;
     RECT  27.24 42.613 28.536 42.697 ;
     RECT  40.176 42.419 40.2 42.731 ;
     RECT  43.344 42.611 46.344 42.731 ;
     RECT  37.92 42.677 38.616 42.741 ;
     RECT  5.64 42.667 6.072 42.745 ;
     RECT  54.24 42.661 55.224 42.745 ;
     RECT  27.24 42.697 27.768 42.803 ;
     RECT  3.792 42.741 3.816 42.829 ;
     RECT  10.848 42.613 11.976 42.963 ;
     RECT  14.64 42.671 14.664 42.997 ;
     RECT  45.936 42.731 46.344 43.021 ;
     RECT  10.08 42.963 11.976 43.051 ;
     RECT  48.84 41.835 49.152 43.247 ;
     RECT  21.84 42.227 22.152 43.253 ;
     RECT  46.608 43.125 46.728 43.273 ;
     RECT  37.92 42.741 39.192 43.285 ;
     RECT  16.44 42.227 17.4 43.317 ;
     RECT  18.624 43.237 18.648 43.317 ;
     RECT  36.048 40.309 36.072 43.317 ;
     RECT  16.44 43.317 18.648 43.321 ;
     RECT  51.312 43.237 51.336 43.321 ;
     RECT  43.344 42.731 43.752 43.331 ;
     RECT  37.776 43.285 39.192 43.333 ;
     RECT  29.088 42.933 29.112 43.347 ;
     RECT  53.04 42.741 53.064 43.445 ;
     RECT  41.04 43.381 41.064 43.487 ;
     RECT  10.368 43.051 11.352 43.571 ;
     RECT  41.04 43.487 41.64 43.571 ;
     RECT  24.72 43.219 24.744 43.573 ;
     RECT  32.64 42.061 32.952 43.573 ;
     RECT  48.84 43.247 49.272 43.573 ;
     RECT  59.64 42.553 59.952 43.573 ;
     RECT  58.128 43.141 58.152 43.627 ;
     RECT  48.432 43.573 49.272 43.657 ;
     RECT  59.64 43.573 60.072 43.657 ;
     RECT  14.64 42.997 15.384 43.679 ;
     RECT  24.72 43.573 25.176 43.691 ;
     RECT  41.04 43.571 41.352 43.701 ;
     RECT  52.176 43.445 53.064 43.715 ;
     RECT  14.208 43.679 15.384 43.763 ;
     RECT  37.776 43.333 39.336 43.765 ;
     RECT  40.56 43.701 41.352 43.765 ;
     RECT  48.84 43.657 49.272 43.765 ;
     RECT  54.24 42.745 54.552 43.765 ;
     RECT  21.744 43.253 22.152 43.795 ;
     RECT  14.928 43.763 15.384 43.811 ;
     RECT  52.176 43.715 52.584 43.811 ;
     RECT  5.64 42.745 5.952 43.813 ;
     RECT  29.088 43.347 29.544 43.829 ;
     RECT  35.616 43.317 36.072 43.829 ;
     RECT  29.088 43.829 30.072 43.849 ;
     RECT  53.568 43.765 55.32 43.849 ;
     RECT  54.144 43.849 55.32 43.859 ;
     RECT  7.44 43.717 7.464 43.883 ;
     RECT  9.12 43.795 9.144 43.883 ;
     RECT  21.408 43.795 22.152 43.883 ;
     RECT  61.152 43.509 61.176 43.893 ;
     RECT  16.44 43.321 18.264 43.897 ;
     RECT  30.048 43.849 30.072 43.917 ;
     RECT  61.152 43.893 61.608 43.947 ;
     RECT  37.776 43.765 41.352 43.955 ;
     RECT  48.84 43.765 49.56 43.957 ;
     RECT  31.248 43.957 31.272 43.987 ;
     RECT  32.496 43.573 32.952 43.987 ;
     RECT  34.752 43.829 36.072 43.987 ;
     RECT  61.584 43.947 61.608 44.015 ;
     RECT  5.52 43.813 5.952 44.021 ;
     RECT  21.84 43.883 22.152 44.021 ;
     RECT  27.24 42.803 27.552 44.021 ;
     RECT  37.776 43.955 39.96 44.051 ;
     RECT  52.464 43.811 52.584 44.051 ;
     RECT  31.152 43.987 31.272 44.075 ;
     RECT  32.496 43.987 36.072 44.075 ;
     RECT  41.04 43.955 41.352 44.075 ;
     RECT  52.464 44.051 52.488 44.089 ;
     RECT  14.928 43.811 14.952 44.099 ;
     RECT  24.432 44.015 24.456 44.099 ;
     RECT  31.248 44.075 31.272 44.099 ;
     RECT  48.84 43.957 49.848 44.099 ;
     RECT  61.584 44.015 62.184 44.099 ;
     RECT  27.24 44.021 28.392 44.109 ;
     RECT  32.496 44.075 33.528 44.109 ;
     RECT  5.52 44.021 6.408 44.339 ;
     RECT  34.752 44.075 36.072 44.339 ;
     RECT  47.232 43.957 47.256 44.435 ;
     RECT  34.752 44.339 34.776 44.483 ;
     RECT  5.52 44.339 6.072 44.591 ;
     RECT  21.84 44.021 22.92 44.597 ;
     RECT  43.44 43.331 43.752 44.597 ;
     RECT  16.44 43.897 18.024 44.627 ;
     RECT  16.44 44.627 17.64 44.651 ;
     RECT  46.608 44.485 46.632 44.651 ;
     RECT  41.472 44.581 41.496 44.665 ;
     RECT  5.376 44.591 6.072 44.675 ;
     RECT  43.44 44.597 43.848 44.685 ;
     RECT  32.496 44.109 32.952 44.821 ;
     RECT  21.84 44.597 23.352 44.867 ;
     RECT  31.776 44.821 32.952 44.963 ;
     RECT  8.64 44.597 8.664 45.011 ;
     RECT  37.776 44.051 39.192 45.013 ;
     RECT  45.6 44.725 45.624 45.157 ;
     RECT  1.584 44.965 1.608 45.173 ;
     RECT  2.832 45.139 2.856 45.173 ;
     RECT  37.728 45.013 39.192 45.173 ;
     RECT  1.584 45.173 3.144 45.227 ;
     RECT  50.352 45.157 50.376 45.241 ;
     RECT  2.304 45.227 3.144 45.261 ;
     RECT  11.04 43.571 11.352 45.301 ;
     RECT  25.872 45.173 25.896 45.301 ;
     RECT  40.464 44.917 40.488 45.301 ;
     RECT  8.688 45.267 9.576 45.355 ;
     RECT  42.192 44.965 42.216 45.355 ;
     RECT  37.728 45.173 39.288 45.359 ;
     RECT  40.464 45.301 41.16 45.398 ;
     RECT  48.84 44.099 49.152 45.407 ;
     RECT  25.392 45.301 25.896 45.429 ;
     RECT  27.24 44.109 27.552 45.429 ;
     RECT  37.728 45.359 39.336 45.429 ;
     RECT  11.04 45.301 11.736 45.443 ;
     RECT  4.608 45.365 4.632 45.453 ;
     RECT  58.176 45.365 58.2 45.453 ;
     RECT  21.84 44.867 22.872 45.459 ;
     RECT  41.04 45.398 41.16 45.483 ;
     RECT  45.6 45.157 46.2 45.483 ;
     RECT  55.872 45.301 56.52 45.483 ;
     RECT  48.84 45.407 49.56 45.491 ;
     RECT  25.392 45.429 27.672 45.517 ;
     RECT  29.232 45.459 29.256 45.547 ;
     RECT  50.736 45.459 50.76 45.547 ;
     RECT  25.584 45.517 27.672 45.611 ;
     RECT  37.056 45.429 39.336 45.611 ;
     RECT  41.136 45.483 41.16 45.611 ;
     RECT  5.64 44.675 6.072 45.621 ;
     RECT  7.392 44.965 7.416 45.621 ;
     RECT  16.44 44.651 16.752 45.621 ;
     RECT  21.744 45.459 22.872 45.621 ;
     RECT  37.632 45.611 39.336 45.621 ;
     RECT  59.64 43.657 59.952 45.621 ;
     RECT  45.6 45.483 45.624 45.635 ;
     RECT  15.888 45.621 16.752 45.651 ;
     RECT  2.304 45.261 2.328 45.675 ;
     RECT  5.64 45.621 7.416 45.675 ;
     RECT  61.584 44.099 61.608 45.675 ;
     RECT  37.632 45.621 40.056 45.709 ;
     RECT  46.752 45.621 47.064 45.709 ;
     RECT  59.52 45.621 59.952 45.709 ;
     RECT  3.792 45.621 4.056 45.731 ;
     RECT  21.456 45.621 22.872 45.731 ;
     RECT  46.752 45.709 46.776 45.739 ;
     RECT  18.768 45.685 18.792 45.779 ;
     RECT  15.888 45.651 17.592 45.781 ;
     RECT  5.64 45.675 6.84 45.803 ;
     RECT  28.56 45.715 28.584 45.803 ;
     RECT  30.288 45.715 30.312 45.803 ;
     RECT  3.792 45.731 3.96 45.817 ;
     RECT  15.888 45.781 17.688 45.867 ;
     RECT  48.84 45.491 49.416 45.877 ;
     RECT  36.048 44.339 36.072 45.925 ;
     RECT  54.144 43.859 54.648 45.925 ;
     RECT  25.584 45.611 25.704 45.971 ;
     RECT  25.68 45.971 25.704 45.995 ;
     RECT  35.904 45.925 36.072 46.009 ;
     RECT  21.744 45.731 22.872 46.019 ;
     RECT  8.688 45.355 8.712 46.029 ;
     RECT  14.016 45.941 14.04 46.029 ;
     RECT  15.888 45.867 17.496 46.099 ;
     RECT  48.72 45.877 49.416 46.099 ;
     RECT  37.632 45.709 39.864 46.123 ;
     RECT  19.968 46.165 19.992 46.175 ;
     RECT  48.144 46.099 49.416 46.175 ;
     RECT  15.456 46.099 17.496 46.187 ;
     RECT  3.792 45.817 3.816 46.211 ;
     RECT  47.904 46.175 49.416 46.211 ;
     RECT  32.64 44.963 32.952 46.213 ;
     RECT  21.744 46.019 22.152 46.251 ;
     RECT  19.968 46.175 20.52 46.259 ;
     RECT  43.44 44.685 43.752 46.261 ;
     RECT  8.496 46.197 8.52 46.285 ;
     RECT  37.632 46.123 39.816 46.315 ;
     RECT  30.672 46.291 30.696 46.379 ;
     RECT  12.48 46.357 12.504 46.443 ;
     RECT  35.952 46.009 36.072 46.559 ;
     RECT  43.44 46.261 43.944 46.581 ;
     RECT  43.344 46.581 43.944 46.597 ;
     RECT  41.136 46.581 41.16 46.611 ;
     RECT  35.952 46.559 36.456 46.643 ;
     RECT  43.344 46.597 44.472 46.751 ;
     RECT  32.64 46.213 33.096 46.773 ;
     RECT  40.992 46.611 41.16 46.773 ;
     RECT  42.72 46.751 44.472 46.773 ;
     RECT  47.904 46.211 49.152 46.773 ;
     RECT  54.144 45.925 55.32 46.773 ;
     RECT  19.968 46.259 19.992 46.787 ;
     RECT  56.496 45.483 56.52 46.827 ;
     RECT  16.44 46.187 17.496 46.835 ;
     RECT  32.496 46.773 33.096 46.837 ;
     RECT  54.144 46.773 55.464 46.861 ;
     RECT  47.328 46.773 49.152 46.885 ;
     RECT  31.92 46.837 33.096 46.931 ;
     RECT  46.368 46.885 49.152 46.931 ;
     RECT  37.632 46.315 38.472 46.933 ;
     RECT  37.584 46.933 38.472 46.979 ;
     RECT  39.744 46.315 39.816 47.019 ;
     RECT  19.392 46.943 19.944 47.027 ;
     RECT  19.824 47.027 19.944 47.075 ;
     RECT  9.6 47.059 9.624 47.077 ;
     RECT  11.04 45.443 11.352 47.077 ;
     RECT  19.824 47.075 19.848 47.083 ;
     RECT  37.584 46.979 38.352 47.083 ;
     RECT  28.704 47.029 28.728 47.123 ;
     RECT  39.792 47.019 39.816 47.147 ;
     RECT  46.368 46.931 46.824 47.147 ;
     RECT  50.496 46.867 50.52 47.147 ;
     RECT  27.12 45.611 27.552 47.157 ;
     RECT  35.952 46.643 36.36 47.221 ;
     RECT  54.144 46.861 54.744 47.245 ;
     RECT  35.664 47.221 36.36 47.275 ;
     RECT  35.664 47.275 35.688 47.279 ;
     RECT  5.64 45.803 5.952 47.285 ;
     RECT  9.6 47.077 11.352 47.285 ;
     RECT  16.44 46.835 16.872 47.285 ;
     RECT  46.656 47.147 46.824 47.305 ;
     RECT  24.192 47.221 24.216 47.315 ;
     RECT  27.12 47.157 28.488 47.315 ;
     RECT  35.28 47.279 35.688 47.315 ;
     RECT  40.992 46.773 44.472 47.349 ;
     RECT  35.28 47.315 35.304 47.363 ;
     RECT  9.456 47.285 12.216 47.373 ;
     RECT  15.744 47.285 16.872 47.373 ;
     RECT  48.048 46.931 49.152 47.403 ;
     RECT  46.8 47.305 46.824 47.437 ;
     RECT  9.6 47.373 12.216 47.443 ;
     RECT  39.84 47.365 39.864 47.467 ;
     RECT  32.64 46.931 33.096 47.509 ;
     RECT  9.6 47.443 12.936 47.531 ;
     RECT  5.52 47.285 5.952 47.541 ;
     RECT  9.6 47.531 12.648 47.603 ;
     RECT  4.848 47.541 5.952 47.629 ;
     RECT  16.44 47.373 16.872 47.651 ;
     RECT  37.632 47.083 38.352 47.651 ;
     RECT  32.64 47.509 33.72 47.659 ;
     RECT  40.992 47.349 44.568 47.763 ;
     RECT  32.64 47.659 33.096 47.787 ;
     RECT  27.12 47.315 28.152 47.845 ;
     RECT  37.68 47.651 38.352 47.851 ;
     RECT  50.832 47.157 50.856 47.855 ;
     RECT  27.072 47.845 28.152 47.891 ;
     RECT  40.992 47.763 44.616 47.939 ;
     RECT  50.832 47.855 51.336 47.939 ;
     RECT  54.24 47.245 54.744 47.939 ;
     RECT  15.36 47.925 15.384 48.013 ;
     RECT  8.448 47.989 8.472 48.131 ;
     RECT  40.992 47.939 43.752 48.147 ;
     RECT  21.84 46.251 22.152 48.373 ;
     RECT  34.704 48.339 34.728 48.373 ;
     RECT  7.152 47.541 7.176 48.403 ;
     RECT  59.64 45.709 59.952 48.403 ;
     RECT  34.704 48.373 35.112 48.407 ;
     RECT  10.272 47.603 12.648 48.427 ;
     RECT  40.8 48.147 43.752 48.427 ;
     RECT  44.736 48.339 44.76 48.427 ;
     RECT  50.832 47.939 50.856 48.427 ;
     RECT  5.64 47.629 5.952 48.437 ;
     RECT  7.152 48.403 7.896 48.437 ;
     RECT  5.64 48.437 7.896 48.491 ;
     RECT  61.584 48.431 61.608 48.515 ;
     RECT  5.64 48.491 7.224 48.525 ;
     RECT  7.2 48.525 7.224 48.619 ;
     RECT  10.272 48.427 12.408 48.659 ;
     RECT  34.704 48.407 35.784 48.693 ;
     RECT  48.72 47.403 49.152 48.693 ;
     RECT  29.088 48.661 29.112 48.747 ;
     RECT  30.144 48.661 30.168 48.747 ;
     RECT  53.04 48.661 53.064 48.747 ;
     RECT  48.72 48.693 49.272 48.781 ;
     RECT  48.72 48.781 49.152 48.821 ;
     RECT  40.8 48.427 41.64 48.863 ;
     RECT  27.072 47.891 27.552 48.885 ;
     RECT  26.736 48.885 27.552 48.901 ;
     RECT  48.24 48.821 49.152 48.909 ;
     RECT  54.24 47.939 54.552 48.915 ;
     RECT  33.984 48.693 35.784 48.947 ;
     RECT  40.08 48.863 41.64 48.947 ;
     RECT  34.176 48.947 35.784 48.949 ;
     RECT  54.24 48.915 55.512 48.949 ;
     RECT  40.464 48.947 41.64 48.973 ;
     RECT  37.872 47.851 38.352 48.997 ;
     RECT  9.216 48.901 9.24 49.003 ;
     RECT  26.544 48.901 27.552 49.003 ;
     RECT  30.24 48.901 30.264 49.003 ;
     RECT  41.04 48.973 41.64 49.003 ;
     RECT  57.744 48.915 57.768 49.003 ;
     RECT  59.04 48.403 59.952 49.003 ;
     RECT  10.272 48.659 12.024 49.008 ;
     RECT  21.744 48.373 22.152 49.043 ;
     RECT  10.944 49.008 12.024 49.06 ;
     RECT  16.44 47.651 16.752 49.077 ;
     RECT  41.04 49.003 41.064 49.091 ;
     RECT  16.44 49.077 17.064 49.187 ;
     RECT  32.64 47.787 32.952 49.205 ;
     RECT  37.872 48.997 38.52 49.247 ;
     RECT  45.024 49.269 45.048 49.285 ;
     RECT  32.64 49.205 33.048 49.293 ;
     RECT  20.112 49.237 20.136 49.323 ;
     RECT  47.232 49.269 47.256 49.357 ;
     RECT  37.824 49.247 38.52 49.381 ;
     RECT  45.024 49.285 45.624 49.387 ;
     RECT  34.176 48.949 35.88 49.427 ;
     RECT  27.12 49.003 27.552 49.439 ;
     RECT  16.44 49.187 16.752 49.461 ;
     RECT  30.864 49.237 30.888 49.461 ;
     RECT  54.24 48.949 55.992 49.515 ;
     RECT  27.12 49.439 27.912 49.523 ;
     RECT  15.504 49.461 16.752 49.549 ;
     RECT  30.864 49.461 31.224 49.549 ;
     RECT  34.8 49.427 35.88 49.619 ;
     RECT  42.768 48.427 43.752 49.765 ;
     RECT  55.968 49.515 55.992 49.859 ;
     RECT  37.68 49.381 38.52 49.861 ;
     RECT  28.752 49.861 28.776 50.027 ;
     RECT  27.12 49.523 27.552 50.037 ;
     RECT  10.944 49.06 11.352 50.051 ;
     RECT  45.024 49.387 45.048 50.051 ;
     RECT  34.8 49.619 35.544 50.099 ;
     RECT  53.088 50.015 53.112 50.099 ;
     RECT  26.88 50.037 27.552 50.125 ;
     RECT  51.888 50.037 51.912 50.125 ;
     RECT  50.688 49.973 50.808 50.147 ;
     RECT  37.68 49.861 39.24 50.389 ;
     RECT  9.456 50.037 9.48 50.437 ;
     RECT  37.68 50.389 39.864 50.483 ;
     RECT  42.048 49.765 43.752 50.549 ;
     RECT  48.84 48.909 49.152 50.549 ;
     RECT  35.328 50.099 35.544 50.581 ;
     RECT  41.712 50.549 43.752 50.591 ;
     RECT  9.408 50.437 9.48 50.603 ;
     RECT  37.824 50.483 39.864 50.603 ;
     RECT  41.616 50.591 43.752 50.613 ;
     RECT  35.328 50.581 36.312 50.617 ;
     RECT  41.616 50.613 43.848 50.629 ;
     RECT  48.84 50.549 49.656 50.637 ;
     RECT  35.424 50.617 36.312 50.667 ;
     RECT  37.872 50.603 39.864 50.667 ;
     RECT  21.84 49.043 22.152 50.725 ;
     RECT  30.24 49.973 30.264 50.731 ;
     RECT  27.24 50.125 27.552 50.735 ;
     RECT  54.24 49.515 54.648 50.735 ;
     RECT  20.736 50.677 20.76 50.783 ;
     RECT  27.24 50.735 28.248 50.819 ;
     RECT  27.24 50.819 27.672 50.867 ;
     RECT  15.936 49.549 16.752 50.869 ;
     RECT  15.888 50.869 16.752 50.965 ;
     RECT  48.84 50.637 49.152 50.965 ;
     RECT  32.64 49.293 32.952 51.027 ;
     RECT  15.888 50.965 17.544 51.051 ;
     RECT  11.04 50.051 11.352 51.061 ;
     RECT  31.776 51.027 32.952 51.061 ;
     RECT  13.392 50.997 13.416 51.085 ;
     RECT  25.248 50.997 25.272 51.107 ;
     RECT  54.24 50.735 55.32 51.109 ;
     RECT  41.616 50.629 44.472 51.115 ;
     RECT  9.696 51.061 11.352 51.155 ;
     RECT  20.496 50.783 20.76 51.205 ;
     RECT  15.888 51.051 17.16 51.213 ;
     RECT  14.784 50.997 14.808 51.253 ;
     RECT  15.888 51.213 17.112 51.307 ;
     RECT  19.824 51.205 20.76 51.307 ;
     RECT  23.232 51.205 23.256 51.307 ;
     RECT  45.984 50.549 46.008 51.311 ;
     RECT  37.872 50.667 38.904 51.371 ;
     RECT  27.24 50.867 27.552 51.381 ;
     RECT  36.576 51.301 36.6 51.385 ;
     RECT  45.984 51.311 46.2 51.395 ;
     RECT  48.144 50.965 49.152 51.499 ;
     RECT  45.552 51.445 45.576 51.529 ;
     RECT  57.024 51.301 57.048 51.539 ;
     RECT  50.784 50.147 50.808 51.627 ;
     RECT  16.128 51.307 17.112 51.683 ;
     RECT  53.04 51.573 53.064 51.683 ;
     RECT  42.768 51.115 44.472 51.691 ;
     RECT  36.816 51.667 36.84 51.755 ;
     RECT  41.52 51.157 41.544 51.755 ;
     RECT  42.816 51.691 44.472 51.883 ;
     RECT  53.232 51.733 53.256 51.883 ;
     RECT  19.248 51.475 19.272 51.893 ;
     RECT  27.072 51.381 27.552 51.893 ;
     RECT  29.232 51.859 29.256 51.893 ;
     RECT  26.64 51.893 27.552 51.925 ;
     RECT  43.44 51.883 44.472 51.925 ;
     RECT  31.68 51.061 32.952 51.935 ;
     RECT  14.208 51.253 14.808 51.957 ;
     RECT  29.232 51.893 30.216 51.957 ;
     RECT  31.632 51.935 32.952 51.957 ;
     RECT  9.648 51.877 9.672 51.961 ;
     RECT  10.848 51.155 11.352 51.971 ;
     RECT  12.528 51.887 12.552 51.971 ;
     RECT  16.32 51.683 17.112 51.971 ;
     RECT  24.192 51.887 24.216 51.971 ;
     RECT  29.232 51.957 32.952 51.973 ;
     RECT  26.64 51.925 27.672 51.981 ;
     RECT  43.44 51.925 44.568 52.011 ;
     RECT  28.704 51.973 32.952 52.019 ;
     RECT  10.944 51.971 11.352 52.075 ;
     RECT  16.32 51.971 16.752 52.075 ;
     RECT  28.704 52.019 29.256 52.075 ;
     RECT  31.728 52.019 32.952 52.075 ;
     RECT  43.44 52.011 44.472 52.075 ;
     RECT  24.528 52.085 24.6 52.117 ;
     RECT  29.232 52.075 29.256 52.139 ;
     RECT  14.208 51.957 14.952 52.163 ;
     RECT  24.528 52.117 25.08 52.203 ;
     RECT  43.44 52.075 43.992 52.203 ;
     RECT  26.784 51.981 27.672 52.211 ;
     RECT  37.872 51.371 38.76 52.211 ;
     RECT  19.104 51.893 19.272 52.371 ;
     RECT  24.528 52.203 24.552 52.403 ;
     RECT  20.736 51.307 20.76 52.435 ;
     RECT  21.744 50.725 22.152 52.435 ;
     RECT  14.928 52.163 14.952 52.451 ;
     RECT  54.24 51.109 55.608 52.501 ;
     RECT  20.736 52.435 22.152 52.523 ;
     RECT  51.456 52.435 51.48 52.523 ;
     RECT  48.84 51.499 49.152 52.549 ;
     RECT  54.24 52.501 55.944 52.587 ;
     RECT  18.288 52.371 19.272 52.755 ;
     RECT  32.64 52.075 32.952 52.755 ;
     RECT  48.84 52.549 49.704 52.819 ;
     RECT  18.288 52.755 20.232 52.843 ;
     RECT  32.64 52.755 33.672 52.843 ;
     RECT  54.24 52.587 55.512 52.843 ;
     RECT  18.288 52.843 19.368 52.917 ;
     RECT  37.872 52.211 38.352 52.979 ;
     RECT  18 52.917 19.368 53.005 ;
     RECT  16.44 52.075 16.752 53.039 ;
     RECT  30.72 52.019 30.744 53.045 ;
     RECT  23.904 52.981 23.928 53.065 ;
     RECT  48.048 52.819 49.704 53.077 ;
     RECT  36.288 53.029 36.312 53.109 ;
     RECT  40.944 53.039 40.968 53.109 ;
     RECT  48.048 53.077 49.848 53.109 ;
     RECT  35.424 53.109 36.312 53.113 ;
     RECT  16.44 53.039 16.92 53.123 ;
     RECT  40.944 53.109 41.112 53.123 ;
     RECT  35.424 53.113 35.448 53.125 ;
     RECT  30.48 53.045 30.744 53.133 ;
     RECT  48 53.109 49.848 53.219 ;
     RECT  37.92 52.979 38.352 53.221 ;
     RECT  48.192 53.219 49.848 53.227 ;
     RECT  35.328 53.125 35.448 53.267 ;
     RECT  27.24 52.211 27.672 53.269 ;
     RECT  41.088 53.123 41.112 53.291 ;
     RECT  48.336 53.227 49.848 53.291 ;
     RECT  37.92 53.221 38.76 53.305 ;
     RECT  42.144 53.231 42.168 53.315 ;
     RECT  54.24 52.843 55.176 53.328 ;
     RECT  54.24 53.328 54.648 53.331 ;
     RECT  26.88 53.269 27.672 53.419 ;
     RECT  30.816 53.331 30.84 53.419 ;
     RECT  54.144 53.331 54.648 53.419 ;
     RECT  42.192 53.461 42.216 53.547 ;
     RECT  26.88 53.419 27.552 53.651 ;
     RECT  36.432 53.653 36.456 53.739 ;
     RECT  23.808 53.685 23.832 53.795 ;
     RECT  18.288 53.005 19.368 53.813 ;
     RECT  18.288 53.813 19.992 53.867 ;
     RECT  32.64 52.843 32.952 54.005 ;
     RECT  32.448 54.005 32.952 54.069 ;
     RECT  52.656 53.749 52.68 54.093 ;
     RECT  35.328 53.267 35.352 54.123 ;
     RECT  32.256 54.069 32.952 54.157 ;
     RECT  47.088 53.845 47.112 54.197 ;
     RECT  21.84 52.523 22.152 54.229 ;
     RECT  46.512 54.197 47.112 54.251 ;
     RECT  25.488 53.685 25.512 54.291 ;
     RECT  43.44 52.203 43.752 54.325 ;
     RECT  19.248 53.867 19.992 54.371 ;
     RECT  51.552 54.291 51.576 54.379 ;
     RECT  48.84 53.291 49.848 54.389 ;
     RECT  46.512 54.251 46.536 54.467 ;
     RECT  42.48 54.325 43.752 54.469 ;
     RECT  25.488 54.291 26.088 54.517 ;
     RECT  21.744 54.229 22.152 54.563 ;
     RECT  16.44 53.123 16.752 54.565 ;
     RECT  25.248 54.517 26.088 54.601 ;
     RECT  42.48 54.469 44.136 54.623 ;
     RECT  18.24 54.547 18.264 54.635 ;
     RECT  16.44 54.565 17.112 54.649 ;
     RECT  48.72 54.389 49.848 54.661 ;
     RECT  42.48 54.623 44.424 54.669 ;
     RECT  42.72 54.669 44.424 54.699 ;
     RECT  19.968 54.371 19.992 54.707 ;
     RECT  32.64 54.157 32.952 54.709 ;
     RECT  37.92 53.305 38.352 54.709 ;
     RECT  43.44 54.699 44.424 54.709 ;
     RECT  48.48 54.661 49.848 54.709 ;
     RECT  54.24 53.419 54.648 54.709 ;
     RECT  14.88 54.613 14.904 54.763 ;
     RECT  13.104 54.709 13.128 54.793 ;
     RECT  43.44 54.709 44.568 54.793 ;
     RECT  54.24 54.709 54.696 54.793 ;
     RECT  55.872 54.373 55.896 54.793 ;
     RECT  32.64 54.709 33.624 54.803 ;
     RECT  47.76 54.709 49.848 54.815 ;
     RECT  30.192 54.815 30.216 54.899 ;
     RECT  37.92 54.709 39 54.899 ;
     RECT  47.76 54.815 50.712 54.899 ;
     RECT  26.064 54.601 26.088 54.925 ;
     RECT  29.088 54.837 29.112 55.139 ;
     RECT  40.032 54.837 40.056 55.139 ;
     RECT  47.76 54.899 49.848 55.187 ;
     RECT  27.24 53.651 27.552 55.391 ;
     RECT  27.24 55.391 27.912 55.475 ;
     RECT  37.92 54.899 38.808 55.475 ;
     RECT  47.904 55.187 49.848 55.475 ;
     RECT  29.712 55.349 29.784 55.501 ;
     RECT  35.04 55.413 35.064 55.501 ;
     RECT  29.712 55.501 29.736 55.571 ;
     RECT  54.24 54.793 54.552 55.765 ;
     RECT  54.24 55.765 54.648 55.813 ;
     RECT  16.44 54.649 16.752 55.925 ;
     RECT  53.856 55.813 54.648 55.989 ;
     RECT  53.568 55.989 54.936 56.005 ;
     RECT  18.048 55.925 18.072 56.013 ;
     RECT  37.92 55.475 38.352 56.019 ;
     RECT  53.568 56.005 55.896 56.077 ;
     RECT  21.84 54.563 22.152 56.083 ;
     RECT  36.336 56.019 36.36 56.107 ;
     RECT  37.824 56.019 38.352 56.107 ;
     RECT  52.368 56.019 52.392 56.107 ;
     RECT  21.456 56.083 22.152 56.171 ;
     RECT  55.872 56.077 55.896 56.171 ;
     RECT  16.44 55.925 16.872 56.195 ;
     RECT  43.44 54.793 43.752 56.245 ;
     RECT  43.44 56.245 44.424 56.341 ;
     RECT  48.84 55.475 49.848 56.485 ;
     RECT  48.84 56.485 50.136 56.569 ;
     RECT  47.376 56.293 47.4 56.687 ;
     RECT  47.328 56.687 47.4 56.771 ;
     RECT  43.44 56.341 44.52 56.787 ;
     RECT  48.84 56.569 49.944 56.787 ;
     RECT  43.44 56.787 44.856 56.875 ;
     RECT  47.904 56.787 49.944 56.875 ;
     RECT  48.432 56.875 49.944 56.939 ;
     RECT  27.24 55.475 27.552 56.979 ;
     RECT  53.568 56.077 54.648 57.059 ;
     RECT  43.44 56.875 44.424 57.097 ;
     RECT  21.744 56.171 22.152 57.131 ;
     RECT  48.72 56.939 49.152 57.195 ;
     RECT  32.64 54.803 32.952 57.253 ;
     RECT  34.176 57.205 34.2 57.289 ;
     RECT  51.6 56.616 51.624 57.349 ;
     RECT  27.24 56.979 27.672 57.427 ;
     RECT  51.6 57.349 51.816 57.451 ;
     RECT  35.376 57.205 35.4 57.503 ;
     RECT  32.496 57.253 32.952 57.541 ;
     RECT  23.712 57.493 23.736 57.579 ;
     RECT  20.496 57.077 20.52 57.587 ;
     RECT  35.328 57.503 35.4 57.587 ;
     RECT  32.496 57.541 33.624 57.589 ;
     RECT  27.072 57.427 27.672 57.647 ;
     RECT  25.056 57.647 25.08 57.695 ;
     RECT  25.056 57.695 25.176 57.731 ;
     RECT  54.096 57.059 54.648 57.771 ;
     RECT  25.152 57.731 25.176 57.779 ;
     RECT  43.44 57.097 44.184 57.875 ;
     RECT  50.736 57.589 51.528 57.923 ;
     RECT  27.072 57.647 28.536 57.939 ;
     RECT  32.448 57.589 33.624 57.971 ;
     RECT  50.736 57.923 51.048 57.997 ;
     RECT  38.04 56.107 38.352 58.021 ;
     RECT  27.072 57.939 28.632 58.027 ;
     RECT  27.072 58.027 28.392 58.101 ;
     RECT  38.04 58.021 38.664 58.101 ;
     RECT  26.352 58.101 28.392 58.117 ;
     RECT  39.696 57.973 39.72 58.131 ;
     RECT  54.096 57.771 54.552 58.165 ;
     RECT  25.632 58.117 28.392 58.189 ;
     RECT  37.776 58.101 38.664 58.189 ;
     RECT  39.696 58.131 40.68 58.219 ;
     RECT  30.288 57.637 30.312 58.323 ;
     RECT  46.176 58.165 46.2 58.323 ;
     RECT  48.84 57.195 49.152 58.323 ;
     RECT  50.736 57.997 50.856 58.323 ;
     RECT  48.84 58.323 50.856 58.347 ;
     RECT  36.144 58.293 36.312 58.403 ;
     RECT  30 58.323 30.312 58.405 ;
     RECT  30 58.405 30.696 58.411 ;
     RECT  38.04 58.189 38.664 58.411 ;
     RECT  46.176 58.323 46.632 58.411 ;
     RECT  48.84 58.347 50.04 58.411 ;
     RECT  30.672 58.411 30.696 58.421 ;
     RECT  32.64 57.971 33.624 58.453 ;
     RECT  36.144 58.403 36.168 58.475 ;
     RECT  38.04 58.411 38.616 58.475 ;
     RECT  40.512 58.219 40.632 58.475 ;
     RECT  30.672 58.421 31.32 58.489 ;
     RECT  48.84 58.411 49.464 58.489 ;
     RECT  47.328 58.421 47.352 58.509 ;
     RECT  32.64 58.453 33.912 58.539 ;
     RECT  43.44 57.875 43.944 58.643 ;
     RECT  25.632 58.189 25.848 58.667 ;
     RECT  27.12 58.189 28.392 58.739 ;
     RECT  31.296 58.489 31.32 58.739 ;
     RECT  23.664 58.613 23.688 59.077 ;
     RECT  23.376 59.077 23.688 59.125 ;
     RECT  23.376 59.125 23.784 59.179 ;
     RECT  23.76 59.179 23.784 59.219 ;
     RECT  25.824 58.667 25.848 59.219 ;
     RECT  27.12 58.739 27.96 59.219 ;
     RECT  52.992 58.613 53.016 59.269 ;
     RECT  54 58.165 54.552 59.269 ;
     RECT  39.84 59.231 39.864 59.315 ;
     RECT  47.568 59.253 47.592 59.363 ;
     RECT  52.992 59.269 54.552 59.445 ;
     RECT  32.64 58.539 33.672 59.475 ;
     RECT  27.12 59.219 27.552 59.509 ;
     RECT  38.04 58.475 38.352 59.509 ;
     RECT  52.752 59.445 54.552 59.533 ;
     RECT  40.32 59.475 40.68 59.563 ;
     RECT  30.816 59.567 31.272 59.651 ;
     RECT  26.784 59.509 27.552 59.691 ;
     RECT  31.248 59.651 31.272 59.691 ;
     RECT  20.784 59.667 20.808 59.755 ;
     RECT  32.256 59.475 33.672 59.765 ;
     RECT  43.44 58.643 43.752 59.765 ;
     RECT  46.992 59.759 47.352 59.797 ;
     RECT  48.84 58.489 49.152 59.807 ;
     RECT  50.16 59.573 50.184 59.807 ;
     RECT  30.144 59.731 30.168 59.819 ;
     RECT  35.904 59.731 35.928 59.819 ;
     RECT  46.128 59.797 47.352 59.843 ;
     RECT  53.136 59.533 54.552 59.843 ;
     RECT  32.112 59.765 33.672 59.853 ;
     RECT  48.84 59.807 50.184 59.891 ;
     RECT  47.328 59.843 47.352 59.947 ;
     RECT  21.84 57.131 22.152 60.021 ;
     RECT  32.64 59.853 33.672 60.021 ;
     RECT  25.392 59.829 25.416 60.083 ;
     RECT  32.64 60.021 34.104 60.109 ;
     RECT  40.32 59.563 40.344 60.169 ;
     RECT  35.856 60.085 35.88 60.179 ;
     RECT  53.136 59.843 53.16 60.467 ;
     RECT  43.44 59.765 44.328 60.757 ;
     RECT  48.84 59.891 49.152 60.789 ;
     RECT  27.24 59.691 27.552 60.819 ;
     RECT  43.44 60.757 44.472 60.843 ;
     RECT  50.208 60.661 50.232 60.843 ;
     RECT  23.904 60.767 23.928 60.851 ;
     RECT  43.44 60.843 43.944 60.901 ;
     RECT  27.24 60.819 28.536 60.907 ;
     RECT  46.128 59.843 46.152 61.043 ;
     RECT  30.24 60.853 30.264 61.139 ;
     RECT  48.576 60.789 49.152 61.189 ;
     RECT  21.84 60.021 22.296 61.365 ;
     RECT  38.04 59.509 38.472 61.365 ;
     RECT  48.192 61.189 49.152 61.365 ;
     RECT  20.256 61.189 20.28 61.419 ;
     RECT  47.52 61.365 49.152 61.419 ;
     RECT  35.568 61.365 35.592 61.453 ;
     RECT  37.92 61.365 38.472 61.557 ;
     RECT  48.84 61.419 49.152 61.557 ;
     RECT  21.648 61.365 22.296 61.619 ;
     RECT  32.64 60.109 33.672 61.619 ;
     RECT  44.976 61.535 45 61.619 ;
     RECT  40.8 61.557 40.824 61.667 ;
     RECT  48.84 61.557 49.848 61.667 ;
     RECT  37.92 61.557 39.048 61.715 ;
     RECT  42.576 60.901 43.944 61.739 ;
     RECT  36.672 60.853 36.696 61.765 ;
     RECT  37.92 61.715 38.352 61.765 ;
     RECT  36.672 61.765 38.352 61.813 ;
     RECT  47.52 61.419 47.544 61.859 ;
     RECT  36.288 61.813 38.352 61.867 ;
     RECT  36.288 61.867 36.648 61.907 ;
     RECT  40.416 61.843 40.44 61.931 ;
     RECT  41.616 61.861 41.64 61.945 ;
     RECT  21.84 61.619 22.296 61.957 ;
     RECT  27.24 60.907 27.552 62.227 ;
     RECT  42.768 61.739 43.944 62.245 ;
     RECT  21.84 61.957 22.776 62.293 ;
     RECT  29.328 62.197 29.352 62.315 ;
     RECT  42.768 62.245 44.472 62.315 ;
     RECT  21.84 62.293 23.304 62.325 ;
     RECT  25.536 62.261 25.56 62.325 ;
     RECT  43.44 62.315 44.472 62.329 ;
     RECT  25.392 62.325 25.56 62.437 ;
     RECT  25.104 62.437 25.56 62.581 ;
     RECT  27.24 62.227 28.2 62.629 ;
     RECT  32.64 61.619 33.048 62.639 ;
     RECT  27.24 62.629 28.728 62.677 ;
     RECT  31.824 62.639 33.048 62.725 ;
     RECT  25.008 62.581 25.56 62.771 ;
     RECT  21.84 62.325 23.352 62.819 ;
     RECT  35.232 62.803 35.256 62.891 ;
     RECT  36.624 61.907 36.648 62.891 ;
     RECT  26.736 62.677 28.728 62.901 ;
     RECT  26.544 62.901 28.728 63.011 ;
     RECT  30.24 62.965 30.264 63.013 ;
     RECT  30.24 63.013 30.84 63.049 ;
     RECT  30.288 63.049 30.84 63.123 ;
     RECT  31.824 62.725 33.096 63.123 ;
     RECT  26.544 63.011 28.008 63.147 ;
     RECT  30.288 63.123 33.096 63.147 ;
     RECT  21.84 62.819 22.872 63.299 ;
     RECT  27.24 63.147 28.008 63.339 ;
     RECT  26.208 63.263 26.232 63.347 ;
     RECT  27.24 63.339 27.768 63.443 ;
     RECT  24.816 63.477 24.84 63.565 ;
     RECT  30.816 63.147 33.096 63.829 ;
     RECT  30.816 63.829 33.192 63.861 ;
     RECT  30.816 63.861 33.288 63.875 ;
     RECT  31.152 63.875 33.288 63.877 ;
     RECT  0.24 39.851 0.552 64.013 ;
     RECT  5.64 48.525 5.952 64.013 ;
     RECT  11.04 52.075 11.352 64.013 ;
     RECT  16.44 56.195 16.752 64.013 ;
     RECT  21.84 63.299 22.152 64.013 ;
     RECT  27.24 63.443 27.552 64.013 ;
     RECT  38.04 61.867 38.352 64.013 ;
     RECT  43.44 62.329 43.752 64.013 ;
     RECT  48.84 61.667 49.152 64.013 ;
     RECT  54.24 59.843 54.552 64.013 ;
     RECT  59.64 49.003 59.952 64.013 ;
     RECT  31.152 63.877 33.48 64.069 ;
     RECT  0.24 64.013 0.36 64.283 ;
     RECT  5.64 64.013 5.76 64.283 ;
     RECT  11.04 64.013 11.16 64.283 ;
     RECT  16.44 64.013 16.56 64.283 ;
     RECT  21.84 64.013 21.96 64.283 ;
     RECT  27.24 64.013 27.36 64.283 ;
     RECT  38.04 64.013 38.16 64.283 ;
     RECT  43.44 64.013 43.56 64.283 ;
     RECT  48.84 64.013 48.96 64.283 ;
     RECT  54.24 64.013 54.36 64.283 ;
     RECT  59.64 64.013 59.76 64.283 ;
     RECT  31.152 64.069 33.576 64.656 ;
    LAYER M6 ;
     RECT  0 33.396 0.133 34.26 ;
     RECT  0.133 33.396 0.491 36 ;
     RECT  0 38.796 0.613 39.66 ;
     RECT  0 22.596 1.093 23.46 ;
     RECT  0 11.796 1.237 12.66 ;
     RECT  0 6.396 1.269 7.26 ;
     RECT  1.269 6.396 1.342 8.288 ;
     RECT  0 17.196 1.461 18.06 ;
     RECT  1.093 20.096 1.461 20.704 ;
     RECT  0 44.196 1.573 45.06 ;
     RECT  1.205 15.872 1.619 15.904 ;
     RECT  1.237 10.496 2.245 12.66 ;
     RECT  1.573 44.196 2.293 45.216 ;
     RECT  1.461 17.196 2.339 20.704 ;
     RECT  0.491 33.396 2.341 34.912 ;
     RECT  0.661 25.728 2.613 25.76 ;
     RECT  0.613 38.796 2.613 39.84 ;
     RECT  2.245 41.344 2.613 41.376 ;
     RECT  2.341 33.396 2.677 35.488 ;
     RECT  2.339 17.196 2.686 20.128 ;
     RECT  2.677 33.396 2.741 35.872 ;
     RECT  2.741 33.024 2.821 35.872 ;
     RECT  2.613 38.796 2.821 41.376 ;
     RECT  0 27.996 3.125 28.86 ;
     RECT  1.093 22.596 3.157 23.648 ;
     RECT  3.125 27.996 3.301 29.408 ;
     RECT  3.157 22.464 3.307 23.648 ;
     RECT  2.613 25.728 3.443 26.272 ;
     RECT  0.997 31.36 3.443 31.392 ;
     RECT  2.821 32.704 3.443 36 ;
     RECT  3.301 27.776 3.493 29.408 ;
     RECT  2.245 10.496 3.733 13.92 ;
     RECT  2.869 15.424 3.733 15.456 ;
     RECT  2.821 38.796 3.758 41.696 ;
     RECT  3.758 38.796 3.827 42.784 ;
     RECT  3.733 10.496 3.883 15.456 ;
     RECT  3.307 22.596 3.925 23.648 ;
     RECT  3.443 25.728 3.925 25.76 ;
     RECT  3.443 32.704 3.925 35.488 ;
     RECT  2.613 37.312 3.925 37.344 ;
     RECT  3.827 38.796 3.925 42.656 ;
     RECT  2.293 44.196 3.925 45.664 ;
     RECT  3.493 27.776 3.957 29.536 ;
     RECT  2.686 17.196 4.011 20.064 ;
     RECT  3.925 22.596 4.011 25.76 ;
     RECT  1.342 6.396 4.021 8.224 ;
     RECT  3.883 10.496 4.203 14.816 ;
     RECT  4.203 14.4 4.211 14.816 ;
     RECT  4.211 14.4 4.222 14.624 ;
     RECT  4.203 10.496 4.261 13.024 ;
     RECT  4.261 9.664 4.331 13.024 ;
     RECT  3.925 37.312 4.395 42.656 ;
     RECT  4.011 17.196 4.403 18.208 ;
     RECT  4.331 10.496 4.459 13.024 ;
     RECT  4.459 10.752 4.523 13.024 ;
     RECT  4.011 22.596 4.523 23.584 ;
     RECT  3.925 31.424 4.739 35.488 ;
     RECT  4.395 37.312 4.739 37.344 ;
     RECT  3.957 27.776 5.102 29.664 ;
     RECT  4.739 31.424 5.102 31.456 ;
     RECT  5.102 27.776 5.171 31.456 ;
     RECT  4.011 25.728 5.267 25.76 ;
     RECT  4.021 6.396 5.317 8.352 ;
     RECT  4.395 38.656 5.365 42.656 ;
     RECT  3.925 44.196 5.365 45.792 ;
     RECT  5.171 27.776 5.509 29.6 ;
     RECT  4.837 47.552 5.509 47.584 ;
     RECT  5.509 47.296 5.557 47.584 ;
     RECT  0 49.596 5.621 50.46 ;
     RECT  5.365 38.656 5.675 45.792 ;
     RECT  4.523 10.816 6.083 13.024 ;
     RECT  4.739 32.832 6.229 35.488 ;
     RECT  5.077 36.992 6.229 37.024 ;
     RECT  4.222 14.4 6.323 14.432 ;
     RECT  4.523 22.596 6.565 23.46 ;
     RECT  6.229 32.832 6.699 37.024 ;
     RECT  6.699 33.396 6.827 37.024 ;
     RECT  4.403 17.196 6.837 18.06 ;
     RECT  4.011 19.712 6.837 20.064 ;
     RECT  5.675 38.796 6.851 45.792 ;
     RECT  5.557 47.104 6.853 47.584 ;
     RECT  5.621 49.596 6.853 51.104 ;
     RECT  6.827 36.992 6.899 37.024 ;
     RECT  6.851 38.796 6.899 45.664 ;
     RECT  6.837 16.896 6.91 20.064 ;
     RECT  5.317 6.396 7.019 8.544 ;
     RECT  5.509 27.52 7.147 29.6 ;
     RECT  6.083 11.648 7.349 13.024 ;
     RECT  6.899 38.796 7.381 39.66 ;
     RECT  7.333 10.24 7.403 10.272 ;
     RECT  6.565 22.596 7.475 24.544 ;
     RECT  5.171 31.424 7.523 31.456 ;
     RECT  7.093 26.176 8.003 26.208 ;
     RECT  7.349 11.648 8.051 13.28 ;
     RECT  6.91 17.196 8.485 18.06 ;
     RECT  6.91 20.032 8.485 20.064 ;
     RECT  6.899 41.28 8.485 45.664 ;
     RECT  6.853 47.104 8.485 51.104 ;
     RECT  7.381 38.144 8.61 39.66 ;
     RECT  7.147 27.996 8.675 29.6 ;
     RECT  7.019 6.396 8.677 8.352 ;
     RECT  8.61 38.144 8.683 39.776 ;
     RECT  8.683 38.144 8.723 39.66 ;
     RECT  8.485 17.196 9.061 20.064 ;
     RECT  8.051 11.796 9.251 13.28 ;
     RECT  8.485 41.28 9.397 51.104 ;
     RECT  9.397 41.28 9.515 51.936 ;
     RECT  9.515 47.104 9.635 51.936 ;
     RECT  8.677 6.016 9.829 8.352 ;
     RECT  8.675 27.996 9.902 29.472 ;
     RECT  9.902 27.584 9.971 29.472 ;
     RECT  9.061 17.196 9.973 20.32 ;
     RECT  9.909 26.176 9.982 26.208 ;
     RECT  6.827 33.396 10.101 35.488 ;
     RECT  10.101 33.396 10.174 35.936 ;
     RECT  10.174 33.396 10.213 35.104 ;
     RECT  10.213 32.32 10.283 35.104 ;
     RECT  8.723 38.796 10.338 39.66 ;
     RECT  9.973 16.64 10.501 20.32 ;
     RECT  9.635 47.296 10.603 51.936 ;
     RECT  9.829 6.016 10.883 9.568 ;
     RECT  9.971 27.648 10.931 29.472 ;
     RECT  10.603 51.904 10.933 51.936 ;
     RECT  9.515 41.28 10.979 45.344 ;
     RECT  10.931 27.996 11.317 29.472 ;
     RECT  10.453 30.848 11.317 30.88 ;
     RECT  10.283 32.32 11.317 34.26 ;
     RECT  9.717 37.312 11.317 37.344 ;
     RECT  10.338 38.796 11.317 39.776 ;
     RECT  11.317 27.996 11.459 34.26 ;
     RECT  11.317 37.312 11.459 39.776 ;
     RECT  11.459 27.996 11.651 29.472 ;
     RECT  10.979 41.92 11.747 45.344 ;
     RECT  10.501 15.36 11.987 20.32 ;
     RECT  11.987 15.36 12.203 18.848 ;
     RECT  11.459 30.848 12.323 34.26 ;
     RECT  10.603 47.296 12.45 50.46 ;
     RECT  9.251 11.796 12.469 12.66 ;
     RECT  7.475 22.596 12.469 23.46 ;
     RECT  11.893 26.496 12.469 26.528 ;
     RECT  11.651 27.996 12.469 28.86 ;
     RECT  12.203 15.36 12.523 18.06 ;
     RECT  12.45 46.4 12.523 50.46 ;
     RECT  12.469 26.496 12.563 28.86 ;
     RECT  12.469 10.752 12.659 13.728 ;
     RECT  12.523 47.296 12.907 50.46 ;
     RECT  11.747 41.92 12.949 45.06 ;
     RECT  12.563 27.84 12.971 28.86 ;
     RECT  10.883 6.016 13.045 8.352 ;
     RECT  12.469 22.596 13.045 24.48 ;
     RECT  0 54.996 13.093 55.86 ;
     RECT  13.045 21.952 13.139 24.48 ;
     RECT  11.459 37.312 13.139 39.66 ;
     RECT  12.907 49.596 13.381 50.46 ;
     RECT  10.933 51.904 13.381 52.064 ;
     RECT  11.987 20.288 13.429 20.32 ;
     RECT  12.917 26.176 13.523 26.208 ;
     RECT  12.971 27.996 13.621 28.86 ;
     RECT  12.323 31.04 13.621 34.26 ;
     RECT  12.229 35.84 13.669 35.872 ;
     RECT  13.669 35.712 13.715 35.872 ;
     RECT  12.949 41.792 13.986 45.06 ;
     RECT  13.986 41.792 14.059 45.984 ;
     RECT  12.523 16.448 14.197 18.06 ;
     RECT  13.139 21.952 14.291 23.84 ;
     RECT  13.621 27.996 14.291 34.26 ;
     RECT  12.659 10.752 14.629 12.66 ;
     RECT  14.629 10.112 14.702 12.66 ;
     RECT  14.702 10.112 14.763 12.768 ;
     RECT  14.197 3.84 14.773 3.872 ;
     RECT  14.763 10.752 14.773 12.768 ;
     RECT  13.429 20.288 14.867 20.512 ;
     RECT  14.291 27.996 14.867 29.984 ;
     RECT  13.093 54.72 14.915 55.86 ;
     RECT  14.059 42.112 15.413 45.06 ;
     RECT  12.907 47.296 15.413 47.968 ;
     RECT  13.381 49.596 15.413 52.064 ;
     RECT  14.197 16.448 15.443 18.72 ;
     RECT  14.291 22.596 15.443 23.84 ;
     RECT  13.715 35.712 15.443 35.744 ;
     RECT  15.413 42.112 15.467 47.968 ;
     RECT  13.045 6.016 15.491 8.736 ;
     RECT  15.467 42.112 15.491 47.456 ;
     RECT  15.413 49.472 15.539 52.064 ;
     RECT  15.443 17.196 15.637 18.72 ;
     RECT  14.867 20.288 15.637 20.32 ;
     RECT  13.139 38.016 15.685 39.66 ;
     RECT  15.637 17.196 15.979 20.32 ;
     RECT  15.685 38.016 15.979 40.48 ;
     RECT  15.491 47.296 15.979 47.456 ;
     RECT  14.773 10.752 16.019 13.856 ;
     RECT  14.773 3.84 16.117 3.936 ;
     RECT  15.491 6.396 16.309 8.736 ;
     RECT  16.019 10.752 16.309 12.66 ;
     RECT  15.539 49.596 16.491 52.064 ;
     RECT  16.117 3.392 16.565 3.936 ;
     RECT  16.309 6.396 16.619 12.66 ;
     RECT  15.979 38.796 16.821 40.48 ;
     RECT  0 0.996 16.837 1.86 ;
     RECT  16.565 3.392 16.837 5.088 ;
     RECT  14.915 54.996 16.837 55.86 ;
     RECT  15.979 47.424 16.883 47.456 ;
     RECT  16.821 38.796 16.894 40.736 ;
     RECT  16.837 0.996 16.939 5.088 ;
     RECT  16.885 53.056 16.954 53.088 ;
     RECT  16.491 49.596 17.029 51.552 ;
     RECT  16.837 54.996 17.077 55.968 ;
     RECT  15.979 17.196 17.267 20.064 ;
     RECT  15.491 42.112 17.365 45.856 ;
     RECT  17.365 41.984 17.461 45.856 ;
     RECT  14.291 33.396 17.525 34.26 ;
     RECT  16.939 5.056 17.555 5.088 ;
     RECT  17.029 49.088 17.643 51.552 ;
     RECT  16.619 6.396 17.795 8.736 ;
     RECT  17.077 54.592 18.083 55.968 ;
     RECT  15.443 22.596 18.101 23.46 ;
     RECT  17.267 17.196 18.155 20 ;
     RECT  17.795 8.704 18.181 8.736 ;
     RECT  16.619 10.88 18.181 12.66 ;
     RECT  18.101 22.464 18.181 23.46 ;
     RECT  16.939 0.996 18.219 3.744 ;
     RECT  17.643 49.596 18.277 51.552 ;
     RECT  17.989 52.928 18.277 52.96 ;
     RECT  18.083 54.592 18.277 55.86 ;
     RECT  17.461 41.984 18.682 47.008 ;
     RECT  18.155 17.196 18.757 18.06 ;
     RECT  18.682 41.984 18.795 42.016 ;
     RECT  18.682 43.584 18.803 47.008 ;
     RECT  17.509 25.408 18.851 25.44 ;
     RECT  15.925 15.168 19.061 15.2 ;
     RECT  18.757 16.576 19.061 18.06 ;
     RECT  18.181 22.272 19.115 23.46 ;
     RECT  18.181 8.704 19.243 12.66 ;
     RECT  16.894 38.796 19.333 39.66 ;
     RECT  18.219 0.996 19.427 3.04 ;
     RECT  18.155 19.968 19.427 20 ;
     RECT  19.243 9.216 19.475 12.66 ;
     RECT  18.803 46.976 19.813 47.008 ;
     RECT  19.813 46.976 19.887 47.072 ;
     RECT  19.887 46.976 19.955 47.008 ;
     RECT  17.525 33.024 19.957 34.26 ;
     RECT  19.909 35.776 19.957 35.808 ;
     RECT  18.277 49.596 20.003 55.86 ;
     RECT  19.957 33.024 20.011 36.512 ;
     RECT  20.011 33.024 20.026 34.784 ;
     RECT  20.003 49.596 20.085 52.832 ;
     RECT  20.085 49.28 20.158 52.832 ;
     RECT  20.011 36.48 20.243 36.512 ;
     RECT  20.158 49.596 20.243 52.832 ;
     RECT  0 60.396 20.245 61.26 ;
     RECT  18.853 30.656 20.387 30.688 ;
     RECT  19.333 38.592 20.485 39.66 ;
     RECT  18.803 43.584 20.485 45.06 ;
     RECT  20.003 54.996 20.485 55.86 ;
     RECT  19.115 22.464 20.533 23.46 ;
     RECT  19.475 9.216 20.579 10.272 ;
     RECT  19.061 15.168 20.579 18.06 ;
     RECT  20.533 22.208 20.581 23.84 ;
     RECT  20.581 22.208 20.597 23.968 ;
     RECT  20.597 22.208 20.675 25.696 ;
     RECT  20.245 60.396 20.773 61.408 ;
     RECT  20.485 38.144 21.09 39.66 ;
     RECT  21.09 37.44 21.109 39.66 ;
     RECT  20.675 22.208 21.155 24.416 ;
     RECT  21.109 37.44 21.163 39.776 ;
     RECT  20.243 49.596 21.203 52.512 ;
     RECT  21.163 38.144 21.493 39.776 ;
     RECT  21.493 38.144 21.675 39.904 ;
     RECT  20.579 16.576 21.683 18.06 ;
     RECT  21.155 22.596 21.683 24.416 ;
     RECT  20.485 43.584 21.685 46.24 ;
     RECT  20.485 31.168 21.733 31.328 ;
     RECT  20.026 33.024 21.733 34.26 ;
     RECT  21.203 49.596 21.733 52.448 ;
     RECT  21.621 41.6 21.779 41.632 ;
     RECT  21.685 43.264 21.779 46.24 ;
     RECT  20.485 54.996 21.779 57.12 ;
     RECT  21.675 38.464 21.931 39.904 ;
     RECT  21.779 43.264 21.931 45.664 ;
     RECT  20.773 59.712 22.197 61.408 ;
     RECT  19.475 11.796 22.213 12.66 ;
     RECT  20.579 9.216 22.309 10.144 ;
     RECT  22.213 11.796 22.309 13.472 ;
     RECT  21.683 17.196 22.325 18.06 ;
     RECT  22.261 36.16 22.325 36.192 ;
     RECT  21.733 31.168 22.326 34.26 ;
     RECT  22.309 9.216 22.379 13.472 ;
     RECT  22.326 31.232 22.403 34.26 ;
     RECT  22.325 36.032 22.403 36.192 ;
     RECT  19.909 4.352 22.741 4.384 ;
     RECT  17.795 6.396 22.741 7.26 ;
     RECT  22.379 9.216 22.741 10.144 ;
     RECT  22.379 11.796 22.741 13.472 ;
     RECT  20.579 15.168 22.741 15.2 ;
     RECT  14.867 27.996 22.741 28.86 ;
     RECT  22.197 59.136 22.741 61.408 ;
     RECT  22.403 31.36 23.173 34.26 ;
     RECT  22.741 59.136 23.173 62.496 ;
     RECT  23.173 31.36 23.411 35.04 ;
     RECT  19.427 0.996 23.461 1.86 ;
     RECT  23.461 0.996 23.595 2.72 ;
     RECT  23.173 59.136 23.653 62.688 ;
     RECT  23.653 58.624 23.669 62.688 ;
     RECT  23.669 57.536 23.747 62.688 ;
     RECT  21.733 48.384 23.797 52.448 ;
     RECT  21.779 54.996 23.797 55.86 ;
     RECT  23.411 33.024 23.893 35.04 ;
     RECT  23.797 48.384 23.915 55.86 ;
     RECT  23.893 33.024 23.925 36.32 ;
     RECT  21.931 38.464 23.925 39.66 ;
     RECT  22.741 4.352 23.987 10.144 ;
     RECT  22.741 27.996 24.131 29.536 ;
     RECT  23.915 48.384 24.162 53.024 ;
     RECT  23.925 33.024 24.371 39.66 ;
     RECT  21.931 43.584 24.437 45.664 ;
     RECT  23.411 31.36 24.469 31.392 ;
     RECT  23.987 4.352 24.491 7.456 ;
     RECT  24.437 43.584 24.709 45.92 ;
     RECT  23.747 58.624 24.805 62.688 ;
     RECT  24.805 58.624 24.875 63.52 ;
     RECT  24.875 58.624 25.045 62.944 ;
     RECT  22.741 11.796 25.077 15.2 ;
     RECT  25.077 11.648 25.131 15.2 ;
     RECT  24.371 38.08 25.189 39.66 ;
     RECT  23.915 54.996 25.237 55.86 ;
     RECT  25.189 38.08 25.259 39.776 ;
     RECT  24.162 47.232 25.269 53.024 ;
     RECT  25.237 54.528 25.269 55.86 ;
     RECT  24.805 41.344 25.381 41.376 ;
     RECT  24.709 43.264 25.381 45.92 ;
     RECT  23.987 9.216 25.429 10.144 ;
     RECT  24.371 33.024 25.571 36.576 ;
     RECT  25.259 38.144 25.573 39.776 ;
     RECT  21.683 22.596 25.621 23.46 ;
     RECT  24.469 31.104 25.621 31.392 ;
     RECT  25.571 33.024 25.621 36.32 ;
     RECT  25.573 38.144 25.643 39.904 ;
     RECT  25.381 41.344 25.643 45.92 ;
     RECT  25.643 43.584 25.669 45.92 ;
     RECT  25.269 47.232 25.669 55.86 ;
     RECT  21.637 20.8 25.717 20.832 ;
     RECT  25.621 22.596 25.717 24.544 ;
     RECT  25.429 9.024 26.082 10.144 ;
     RECT  25.131 11.648 26.082 12.66 ;
     RECT  25.643 38.144 26.195 39.66 ;
     RECT  23.595 0.996 26.197 1.86 ;
     RECT  26.082 9.024 26.197 12.66 ;
     RECT  25.045 57.664 26.197 62.944 ;
     RECT  24.491 6.396 26.229 7.26 ;
     RECT  26.197 8.896 26.229 12.66 ;
     RECT  24.491 4.352 26.341 4.384 ;
     RECT  26.229 6.396 26.798 12.66 ;
     RECT  26.341 4.224 26.805 4.384 ;
     RECT  22.325 17.196 26.805 19.36 ;
     RECT  25.717 20.8 26.805 24.544 ;
     RECT  26.805 4.224 26.859 4.704 ;
     RECT  26.805 17.196 26.859 24.544 ;
     RECT  26.798 6.272 26.867 12.66 ;
     RECT  26.859 22.596 26.869 24.544 ;
     RECT  26.85 26.496 26.869 26.528 ;
     RECT  26.869 22.596 26.923 26.528 ;
     RECT  25.643 41.344 27.061 42.208 ;
     RECT  25.669 43.584 27.061 55.86 ;
     RECT  26.197 57.664 27.061 63.328 ;
     RECT  27.061 41.344 27.109 55.86 ;
     RECT  26.923 22.596 27.155 25.632 ;
     RECT  27.109 41.216 27.509 55.86 ;
     RECT  27.061 57.472 27.509 63.328 ;
     RECT  26.195 38.656 27.618 39.66 ;
     RECT  26.859 17.196 27.637 20.832 ;
     RECT  25.621 31.104 27.637 36.32 ;
     RECT  27.637 30.784 27.683 36.32 ;
     RECT  27.509 41.216 27.683 63.328 ;
     RECT  27.618 38.656 27.691 39.776 ;
     RECT  27.683 57.664 27.701 63.328 ;
     RECT  26.867 6.396 27.779 12.66 ;
     RECT  27.683 41.216 27.779 52.448 ;
     RECT  27.701 57.664 27.779 63.392 ;
     RECT  27.683 32.576 27.971 36.32 ;
     RECT  27.779 57.664 27.971 63.328 ;
     RECT  27.971 60.396 28.019 63.328 ;
     RECT  27.637 17.024 28.115 20.832 ;
     RECT  27.155 25.6 28.213 25.632 ;
     RECT  24.131 27.996 28.213 28.86 ;
     RECT  27.691 38.656 28.213 39.66 ;
     RECT  26.859 4.352 28.261 4.704 ;
     RECT  27.779 6.396 28.261 7.26 ;
     RECT  28.115 17.024 28.267 19.936 ;
     RECT  27.779 42.624 28.282 52.448 ;
     RECT  27.971 57.664 28.403 58.528 ;
     RECT  25.131 14.848 28.453 15.2 ;
     RECT  28.267 17.024 28.453 19.232 ;
     RECT  28.453 14.848 28.469 19.232 ;
     RECT  28.469 14.208 28.523 19.232 ;
     RECT  27.971 32.64 28.533 36.32 ;
     RECT  28.403 57.664 28.547 58.016 ;
     RECT  26.197 0.996 28.578 2.272 ;
     RECT  28.533 32.64 28.587 36.704 ;
     RECT  28.578 0.996 28.597 2.336 ;
     RECT  28.261 4.352 28.597 7.26 ;
     RECT  28.547 57.792 28.643 58.016 ;
     RECT  28.597 0.996 28.651 7.26 ;
     RECT  28.651 3.456 28.666 7.26 ;
     RECT  28.587 36.288 28.693 36.704 ;
     RECT  28.213 38.144 28.693 39.66 ;
     RECT  27.683 53.952 28.779 55.86 ;
     RECT  27.779 8.832 29.035 12.66 ;
     RECT  28.666 4.352 29.123 7.26 ;
     RECT  28.523 16.256 29.171 19.232 ;
     RECT  27.683 30.784 29.171 30.816 ;
     RECT  28.651 0.996 29.227 2.144 ;
     RECT  29.035 8.832 29.315 10.144 ;
     RECT  28.019 60.396 29.363 63.136 ;
     RECT  27.779 41.216 29.365 41.248 ;
     RECT  29.365 41.088 29.605 41.248 ;
     RECT  28.282 42.624 29.605 50.46 ;
     RECT  29.035 11.648 29.621 12.66 ;
     RECT  28.523 14.208 29.621 14.24 ;
     RECT  29.123 4.544 29.699 7.26 ;
     RECT  29.621 11.648 29.699 14.24 ;
     RECT  28.643 57.792 29.989 57.824 ;
     RECT  29.363 60.396 30.114 61.26 ;
     RECT  27.155 22.596 30.197 23.46 ;
     RECT  28.213 25.6 30.197 28.86 ;
     RECT  28.587 32.64 30.229 34.26 ;
     RECT  29.605 41.088 30.229 50.46 ;
     RECT  28.282 51.904 30.229 52.448 ;
     RECT  30.197 22.596 30.251 28.86 ;
     RECT  29.363 62.976 30.323 63.136 ;
     RECT  29.315 9.216 30.469 10.144 ;
     RECT  29.699 11.648 30.469 12.66 ;
     RECT  30.229 41.088 30.469 52.448 ;
     RECT  28.779 54.08 30.469 55.86 ;
     RECT  28.693 36.288 30.498 39.66 ;
     RECT  30.469 41.088 30.498 55.86 ;
     RECT  29.989 57.792 30.517 58.4 ;
     RECT  30.114 59.776 30.517 61.26 ;
     RECT  30.498 36.288 30.571 55.86 ;
     RECT  30.229 31.872 30.661 34.26 ;
     RECT  29.227 0.996 30.69 2.016 ;
     RECT  30.571 41.088 30.699 55.86 ;
     RECT  30.469 9.216 30.718 12.66 ;
     RECT  30.251 22.596 30.755 24.48 ;
     RECT  30.69 0.996 30.763 2.336 ;
     RECT  30.699 41.792 30.763 55.86 ;
     RECT  30.251 26.816 30.803 28.86 ;
     RECT  30.763 0.996 30.851 2.016 ;
     RECT  30.773 14.272 30.851 14.304 ;
     RECT  29.171 16.896 30.851 19.232 ;
     RECT  30.763 41.792 30.947 42.208 ;
     RECT  30.718 11.072 31.083 12.66 ;
     RECT  30.763 43.584 31.147 55.86 ;
     RECT  30.661 31.872 31.189 34.976 ;
     RECT  30.571 36.288 31.189 39.66 ;
     RECT  31.157 62.784 31.717 62.816 ;
     RECT  31.717 62.784 31.733 63.2 ;
     RECT  31.733 62.784 31.813 63.904 ;
     RECT  31.813 62.656 31.861 63.904 ;
     RECT  31.189 31.872 31.915 39.66 ;
     RECT  31.861 62.656 31.915 64.032 ;
     RECT  31.915 62.784 31.955 64.032 ;
     RECT  30.851 0.996 32.245 1.86 ;
     RECT  30.947 41.792 32.339 42.016 ;
     RECT  29.699 6.272 32.341 7.26 ;
     RECT  32.341 6.208 32.437 7.26 ;
     RECT  31.765 30.528 32.437 30.56 ;
     RECT  31.915 31.872 32.437 34.784 ;
     RECT  30.851 17.196 32.531 19.232 ;
     RECT  31.147 43.584 32.531 52.128 ;
     RECT  30.517 57.28 32.531 61.26 ;
     RECT  29.699 4.544 32.533 4.704 ;
     RECT  30.718 9.216 32.579 9.568 ;
     RECT  30.803 27.52 32.579 28.86 ;
     RECT  32.437 6.144 32.821 7.26 ;
     RECT  32.579 9.536 32.821 9.568 ;
     RECT  31.083 11.584 32.821 12.66 ;
     RECT  32.533 4.224 32.875 4.704 ;
     RECT  32.821 9.536 33.013 12.66 ;
     RECT  32.339 41.792 33.013 41.824 ;
     RECT  32.821 6.144 33.059 7.904 ;
     RECT  33.013 9.536 33.059 13.024 ;
     RECT  32.437 30.528 33.107 34.784 ;
     RECT  32.531 17.196 33.141 18.06 ;
     RECT  31.955 62.848 33.395 64.032 ;
     RECT  32.579 27.996 33.589 28.86 ;
     RECT  33.013 41.664 33.637 41.824 ;
     RECT  32.531 43.904 33.637 52.128 ;
     RECT  31.147 54.016 33.637 55.86 ;
     RECT  33.059 6.144 33.707 7.26 ;
     RECT  33.637 43.904 33.707 55.86 ;
     RECT  32.245 0.064 33.829 1.86 ;
     RECT  33.829 0.064 33.899 2.912 ;
     RECT  33.141 16.448 33.909 18.06 ;
     RECT  33.107 30.528 33.982 34.464 ;
     RECT  32.531 57.6 34.155 61.26 ;
     RECT  33.059 9.536 34.165 9.568 ;
     RECT  34.155 57.6 34.165 58.336 ;
     RECT  33.909 15.552 34.259 18.06 ;
     RECT  31.915 36.288 34.283 39.66 ;
     RECT  34.165 9.344 34.549 9.568 ;
     RECT  33.059 11.648 34.549 13.024 ;
     RECT  34.283 36.416 34.597 39.66 ;
     RECT  33.637 40.96 34.597 41.824 ;
     RECT  34.549 9.344 34.603 13.024 ;
     RECT  33.707 43.904 34.741 51.744 ;
     RECT  34.603 9.344 34.835 12.66 ;
     RECT  33.589 27.996 35.267 29.024 ;
     RECT  34.597 36.416 35.267 41.824 ;
     RECT  33.982 31.68 35.269 34.464 ;
     RECT  34.259 16.256 35.317 18.06 ;
     RECT  33.707 54.08 35.317 55.86 ;
     RECT  35.317 53.184 35.381 55.86 ;
     RECT  34.155 59.776 35.557 61.26 ;
     RECT  34.741 43.84 35.573 51.744 ;
     RECT  35.573 43.328 35.651 51.744 ;
     RECT  35.269 31.488 35.691 34.464 ;
     RECT  35.557 59.776 35.893 61.408 ;
     RECT  33.395 62.848 35.893 62.88 ;
     RECT  35.893 59.776 35.985 62.88 ;
     RECT  35.691 33.024 36.021 34.464 ;
     RECT  30.755 22.596 36.085 23.46 ;
     RECT  35.317 16.256 36.133 19.04 ;
     RECT  34.165 57.216 36.133 58.336 ;
     RECT  36.085 22.464 36.154 23.968 ;
     RECT  35.381 53.12 36.277 55.86 ;
     RECT  36.133 57.216 36.277 58.464 ;
     RECT  36.277 53.056 36.331 58.464 ;
     RECT  36.331 53.056 36.346 56.096 ;
     RECT  36.346 53.184 36.459 56.096 ;
     RECT  33.899 0.064 36.469 2.016 ;
     RECT  34.837 3.968 36.469 4 ;
     RECT  36.459 53.696 36.478 56.096 ;
     RECT  34.835 9.536 36.515 9.568 ;
     RECT  36.133 16.256 36.563 19.424 ;
     RECT  34.835 11.796 36.613 12.66 ;
     RECT  35.985 60.096 36.659 62.88 ;
     RECT  36.469 0.064 36.755 4 ;
     RECT  33.707 6.208 36.997 7.26 ;
     RECT  36.949 9.152 36.997 9.376 ;
     RECT  36.563 19.392 36.997 19.424 ;
     RECT  35.267 27.996 36.997 28.86 ;
     RECT  36.755 3.328 37.035 4 ;
     RECT  36.659 60.096 37.091 61.856 ;
     RECT  36.021 33.024 37.093 34.848 ;
     RECT  35.691 31.488 37.573 31.712 ;
     RECT  37.573 31.36 37.685 31.712 ;
     RECT  37.093 33.024 37.685 35.296 ;
     RECT  36.613 10.752 37.811 12.66 ;
     RECT  37.685 31.36 37.859 35.296 ;
     RECT  36.478 54.996 37.859 56.096 ;
     RECT  37.859 32.704 37.867 35.296 ;
     RECT  35.651 43.392 37.867 51.744 ;
     RECT  35.267 37.376 37.941 41.824 ;
     RECT  37.867 43.392 37.941 47.584 ;
     RECT  36.154 22.596 38.437 23.968 ;
     RECT  36.331 57.536 38.437 58.464 ;
     RECT  37.091 60.096 38.437 61.6 ;
     RECT  37.941 37.376 38.483 47.584 ;
     RECT  38.437 21.952 38.507 23.968 ;
     RECT  38.437 25.408 38.507 25.44 ;
     RECT  37.867 48.896 38.517 51.744 ;
     RECT  36.997 27.996 38.531 29.024 ;
     RECT  37.035 3.328 38.581 3.36 ;
     RECT  37.859 31.36 38.725 31.392 ;
     RECT  38.517 48.896 38.725 52 ;
     RECT  37.909 53.504 38.725 53.536 ;
     RECT  38.725 48.896 38.965 53.536 ;
     RECT  37.859 54.996 38.965 55.86 ;
     RECT  36.997 6.208 39.013 9.376 ;
     RECT  39.013 5.696 39.083 9.76 ;
     RECT  36.563 16.256 39.109 18.06 ;
     RECT  36.997 19.392 39.109 20.32 ;
     RECT  37.811 11.648 39.205 12.66 ;
     RECT  39.109 16.256 39.278 20.32 ;
     RECT  38.581 3.328 39.285 4 ;
     RECT  39.083 5.696 39.285 9.376 ;
     RECT  37.867 32.704 39.285 34.976 ;
     RECT  39.205 11.584 39.301 12.66 ;
     RECT  38.725 14.08 39.301 14.112 ;
     RECT  38.965 48.896 39.339 55.86 ;
     RECT  39.278 15.936 39.347 20.32 ;
     RECT  39.347 16.32 39.349 20.32 ;
     RECT  39.349 16.32 39.403 21.152 ;
     RECT  39.403 20.288 39.418 21.152 ;
     RECT  38.725 30.592 39.589 31.392 ;
     RECT  39.285 32.704 39.589 35.296 ;
     RECT  39.339 54.848 39.861 55.86 ;
     RECT  38.437 57.536 39.861 61.6 ;
     RECT  39.285 3.328 39.923 9.376 ;
     RECT  38.507 22.596 39.923 23.584 ;
     RECT  39.589 30.592 39.971 35.296 ;
     RECT  39.403 16.32 40.065 18.848 ;
     RECT  39.861 54.848 40.405 61.6 ;
     RECT  39.301 11.584 40.549 14.112 ;
     RECT  40.021 25.856 40.549 25.888 ;
     RECT  36.755 0.064 40.565 1.86 ;
     RECT  39.923 3.328 40.565 7.26 ;
     RECT  40.549 11.392 40.619 14.112 ;
     RECT  40.405 54.848 40.691 61.92 ;
     RECT  38.531 27.996 40.693 28.86 ;
     RECT  40.565 0.064 40.739 7.26 ;
     RECT  40.549 25.024 40.747 25.888 ;
     RECT  38.483 37.568 40.789 47.584 ;
     RECT  39.339 48.896 40.789 53.536 ;
     RECT  39.923 9.344 40.933 9.376 ;
     RECT  40.619 11.584 40.979 12.66 ;
     RECT  40.619 14.08 40.979 14.112 ;
     RECT  40.065 16.512 40.981 18.848 ;
     RECT  39.418 20.288 40.981 20.32 ;
     RECT  40.933 9.344 41.075 10.272 ;
     RECT  40.789 37.568 41.323 53.536 ;
     RECT  39.923 22.596 41.461 23.46 ;
     RECT  41.075 9.344 41.557 9.376 ;
     RECT  41.323 41.92 41.651 53.536 ;
     RECT  40.747 25.088 41.963 25.12 ;
     RECT  40.979 11.648 41.973 12.66 ;
     RECT  40.981 15.104 41.973 15.136 ;
     RECT  40.981 16.512 41.973 20.32 ;
     RECT  41.973 15.104 42.027 20.32 ;
     RECT  41.651 43.584 42.027 53.536 ;
     RECT  41.973 11.648 42.046 13.088 ;
     RECT  40.693 27.996 42.133 29.024 ;
     RECT  41.323 37.568 42.165 40.352 ;
     RECT  40.739 3.328 42.227 7.26 ;
     RECT  42.027 49.596 42.469 53.536 ;
     RECT  40.691 54.848 42.469 58.464 ;
     RECT  42.027 15.296 42.475 20.32 ;
     RECT  42.165 36.992 42.539 40.352 ;
     RECT  39.971 31.36 42.613 35.296 ;
     RECT  42.133 27.996 42.741 29.344 ;
     RECT  42.613 31.36 42.741 35.488 ;
     RECT  40.691 60.396 42.757 61.92 ;
     RECT  42.741 27.996 42.795 35.488 ;
     RECT  42.475 20.096 42.803 20.32 ;
     RECT  41.557 8.576 43.043 9.376 ;
     RECT  42.046 11.648 43.051 12.66 ;
     RECT  42.803 20.16 43.179 20.32 ;
     RECT  41.651 41.92 43.285 42.208 ;
     RECT  42.027 43.584 43.285 48.224 ;
     RECT  43.043 8.832 43.379 9.376 ;
     RECT  42.475 15.296 43.379 18.208 ;
     RECT  42.539 36.992 43.379 40.288 ;
     RECT  43.285 41.92 43.829 48.224 ;
     RECT  42.469 49.596 43.829 58.464 ;
     RECT  42.757 60.396 43.861 62.304 ;
     RECT  43.379 15.296 43.886 15.328 ;
     RECT  40.739 0.064 43.893 1.86 ;
     RECT  42.227 3.328 43.893 3.36 ;
     RECT  43.861 60.032 43.893 62.304 ;
     RECT  43.829 41.92 43.909 58.464 ;
     RECT  43.893 59.776 43.909 62.304 ;
     RECT  43.893 0.064 43.947 3.36 ;
     RECT  43.886 14.208 43.947 15.328 ;
     RECT  43.947 14.208 43.955 14.24 ;
     RECT  43.947 0.064 43.966 2.912 ;
     RECT  42.795 27.996 44.147 30.176 ;
     RECT  43.909 41.92 44.435 62.304 ;
     RECT  43.379 8.832 44.483 9.184 ;
     RECT  43.179 20.16 44.483 20.192 ;
     RECT  44.435 58.176 44.483 62.304 ;
     RECT  42.227 6.396 44.485 7.26 ;
     RECT  42.795 32.128 44.629 35.488 ;
     RECT  43.379 37.504 44.661 40.288 ;
     RECT  44.661 37.056 44.734 40.288 ;
     RECT  44.734 37.568 44.853 40.288 ;
     RECT  44.435 41.92 44.853 56.864 ;
     RECT  44.853 37.568 44.926 56.864 ;
     RECT  44.483 58.176 45.035 61.6 ;
     RECT  41.461 22.464 45.282 23.46 ;
     RECT  45.282 21.504 45.355 23.968 ;
     RECT  44.483 8.832 45.443 8.864 ;
     RECT  44.629 30.912 45.539 35.488 ;
     RECT  43.051 11.796 45.541 12.66 ;
     RECT  44.147 27.996 45.541 29.344 ;
     RECT  45.539 32.384 45.635 35.488 ;
     RECT  43.966 0.064 46.133 1.86 ;
     RECT  44.926 37.568 46.165 40.288 ;
     RECT  46.117 4.032 46.187 4.064 ;
     RECT  45.541 27.996 46.197 29.536 ;
     RECT  46.133 0.064 46.211 2.272 ;
     RECT  45.035 58.176 46.211 61.26 ;
     RECT  46.165 37.184 46.213 40.288 ;
     RECT  46.242 3.712 46.315 3.744 ;
     RECT  46.213 37.12 46.379 40.288 ;
     RECT  44.485 5.632 46.403 7.26 ;
     RECT  46.379 37.184 46.443 40.288 ;
     RECT  45.541 11.796 46.693 13.728 ;
     RECT  45.355 22.596 46.693 23.46 ;
     RECT  45.635 32.384 46.763 35.36 ;
     RECT  46.693 10.624 46.787 13.728 ;
     RECT  46.197 27.84 46.787 29.536 ;
     RECT  46.763 32.384 46.787 35.232 ;
     RECT  44.926 41.92 46.787 56.864 ;
     RECT  46.787 10.624 46.837 12.66 ;
     RECT  46.837 9.6 46.891 12.66 ;
     RECT  46.211 58.368 46.965 61.26 ;
     RECT  46.787 27.84 47.075 28.86 ;
     RECT  46.891 9.6 47.171 9.632 ;
     RECT  46.443 37.568 47.269 40.288 ;
     RECT  47.269 37.568 47.339 41.568 ;
     RECT  46.787 42.944 47.339 56.864 ;
     RECT  46.787 32.384 47.363 34.72 ;
     RECT  47.339 43.136 47.467 56.864 ;
     RECT  46.117 19.776 47.653 19.808 ;
     RECT  47.653 19.776 47.723 20.512 ;
     RECT  47.363 32.768 47.723 34.72 ;
     RECT  46.693 22.596 47.939 25.184 ;
     RECT  45.539 30.912 47.939 30.944 ;
     RECT  47.723 32.896 47.939 34.72 ;
     RECT  46.965 58.368 48.227 61.408 ;
     RECT  47.339 37.568 48.229 40.288 ;
     RECT  47.467 43.264 48.421 56.864 ;
     RECT  47.939 33.396 48.469 34.72 ;
     RECT  48.469 33.396 48.709 35.616 ;
     RECT  48.229 37.056 48.709 40.288 ;
     RECT  48.421 43.264 48.709 56.928 ;
     RECT  48.227 58.368 48.709 61.26 ;
     RECT  47.723 19.776 49.205 19.808 ;
     RECT  49.205 19.776 49.237 20 ;
     RECT  47.939 22.596 49.269 23.46 ;
     RECT  49.237 19.776 49.323 20.256 ;
     RECT  48.709 33.396 49.387 40.288 ;
     RECT  49.387 37.056 49.525 40.288 ;
     RECT  48.709 43.264 49.813 61.26 ;
     RECT  49.269 22.464 50.005 23.46 ;
     RECT  49.813 43.264 50.027 61.6 ;
     RECT  43.379 17.196 50.037 18.208 ;
     RECT  49.323 19.776 50.037 19.808 ;
     RECT  50.005 21.76 50.165 23.46 ;
     RECT  50.027 54.336 50.195 61.26 ;
     RECT  50.037 17.196 50.283 19.808 ;
     RECT  49.387 33.396 50.677 35.744 ;
     RECT  50.165 21.184 50.725 23.46 ;
     RECT  47.939 25.024 50.725 25.184 ;
     RECT  50.283 19.392 50.771 19.808 ;
     RECT  46.403 6.396 50.773 7.26 ;
     RECT  50.725 21.184 50.795 26.272 ;
     RECT  49.525 37.056 50.85 40.352 ;
     RECT  50.85 37.056 50.869 40.48 ;
     RECT  49.861 41.792 50.869 41.824 ;
     RECT  50.869 37.056 50.923 41.824 ;
     RECT  50.195 59.84 51.051 61.26 ;
     RECT  50.795 21.184 51.253 23.776 ;
     RECT  50.773 6.396 51.307 8.416 ;
     RECT  50.027 43.264 51.347 51.872 ;
     RECT  51.347 48.704 51.426 51.872 ;
     RECT  51.426 48.704 51.445 52.512 ;
     RECT  50.195 54.336 51.445 58.4 ;
     RECT  51.445 48.704 51.499 58.4 ;
     RECT  50.677 32.832 51.589 35.744 ;
     RECT  50.923 37.056 51.589 40.992 ;
     RECT  51.589 32.832 51.646 40.992 ;
     RECT  51.253 9.728 51.683 9.76 ;
     RECT  51.646 32.832 51.683 34.26 ;
     RECT  47.075 27.996 51.685 28.86 ;
     RECT  50.795 25.152 51.755 25.184 ;
     RECT  51.685 27.996 51.755 29.664 ;
     RECT  51.646 35.712 51.923 40.992 ;
     RECT  51.253 19.904 52.259 23.776 ;
     RECT  46.891 11.796 52.357 12.66 ;
     RECT  51.347 43.264 52.469 47.2 ;
     RECT  51.923 35.712 52.523 40.352 ;
     RECT  52.523 36.096 52.595 40.352 ;
     RECT  52.259 19.904 52.691 23.648 ;
     RECT  51.499 53.76 52.691 58.4 ;
     RECT  52.691 54.016 52.715 58.4 ;
     RECT  52.715 54.996 52.725 58.4 ;
     RECT  51.051 60.396 52.725 61.26 ;
     RECT  52.725 54.996 52.798 61.26 ;
     RECT  52.469 42.752 53.075 47.2 ;
     RECT  51.499 48.704 53.075 51.872 ;
     RECT  51.683 33.396 53.077 34.26 ;
     RECT  52.798 60.288 53.171 61.26 ;
     RECT  46.211 0.064 53.267 1.86 ;
     RECT  52.691 22.464 53.557 23.648 ;
     RECT  52.595 36.48 53.931 40.352 ;
     RECT  52.798 54.996 54.035 58.656 ;
     RECT  53.931 36.48 54.059 40.224 ;
     RECT  54.114 19.392 54.133 19.424 ;
     RECT  53.557 22.464 54.179 24.544 ;
     RECT  52.357 11.072 54.187 12.66 ;
     RECT  54.133 19.392 54.187 19.552 ;
     RECT  54.059 36.48 54.187 37.088 ;
     RECT  54.179 22.464 54.202 23.648 ;
     RECT  53.075 49.596 54.261 51.872 ;
     RECT  54.133 53.376 54.261 53.408 ;
     RECT  54.035 54.996 54.315 58.208 ;
     RECT  53.075 43.648 54.325 47.2 ;
     RECT  54.261 49.596 54.389 53.408 ;
     RECT  54.315 54.996 54.389 56.16 ;
     RECT  54.315 57.728 54.443 58.208 ;
     RECT  53.877 41.856 54.507 41.888 ;
     RECT  53.077 33.396 54.517 34.784 ;
     RECT  54.187 36.48 54.517 36.512 ;
     RECT  54.187 19.52 54.613 19.552 ;
     RECT  54.517 33.396 54.613 36.512 ;
     RECT  54.443 57.728 54.659 57.76 ;
     RECT  54.613 33.024 54.699 36.512 ;
     RECT  54.699 33.396 54.707 36.512 ;
     RECT  54.707 36.032 54.755 36.512 ;
     RECT  54.325 43.648 54.755 47.904 ;
     RECT  54.755 43.648 55.189 46.816 ;
     RECT  54.389 49.596 55.214 56.16 ;
     RECT  55.189 42.688 55.275 46.816 ;
     RECT  55.214 49.472 55.275 56.16 ;
     RECT  54.613 19.52 55.331 20 ;
     RECT  54.059 38.796 55.331 40.224 ;
     RECT  55.275 43.776 55.331 46.816 ;
     RECT  55.275 49.472 55.477 52.832 ;
     RECT  55.477 48.96 55.523 52.832 ;
     RECT  53.557 30.528 55.571 30.56 ;
     RECT  54.709 26.624 55.907 26.656 ;
     RECT  55.331 44.032 55.907 45.472 ;
     RECT  55.275 54.4 55.907 56.16 ;
     RECT  55.523 48.96 55.955 52.576 ;
     RECT  55.331 38.796 56.053 39.968 ;
     RECT  54.755 36.48 56.245 36.512 ;
     RECT  56.053 38.592 56.299 39.968 ;
     RECT  56.245 36.48 56.339 36.96 ;
     RECT  56.299 38.796 56.387 39.968 ;
     RECT  55.955 48.96 56.427 51.616 ;
     RECT  55.331 46.784 56.531 46.816 ;
     RECT  54.707 33.396 56.629 34.26 ;
     RECT  51.755 27.996 56.965 28.86 ;
     RECT  56.629 33.216 56.965 34.26 ;
     RECT  56.427 48.96 57.059 51.488 ;
     RECT  56.965 27.52 57.877 28.86 ;
     RECT  57.877 26.688 57.909 28.86 ;
     RECT  57.909 26.688 57.963 29.024 ;
     RECT  55.907 44.032 58.117 45.408 ;
     RECT  56.965 31.936 58.163 34.26 ;
     RECT  58.117 43.584 58.219 45.408 ;
     RECT  57.963 27.996 58.357 29.024 ;
     RECT  56.387 38.796 58.357 39.66 ;
     RECT  58.357 27.996 58.426 29.088 ;
     RECT  58.357 38.656 58.451 39.776 ;
     RECT  58.451 38.796 58.453 39.776 ;
     RECT  58.453 38.796 58.539 41.056 ;
     RECT  54.202 22.596 58.549 23.648 ;
     RECT  55.331 19.52 58.645 19.552 ;
     RECT  50.283 17.196 58.741 18.06 ;
     RECT  58.645 19.52 58.741 20.512 ;
     RECT  57.059 48.96 59.029 50.46 ;
     RECT  58.549 22.596 59.221 23.968 ;
     RECT  58.165 25.728 59.221 26.272 ;
     RECT  59.221 22.596 59.461 26.272 ;
     RECT  58.219 43.584 59.509 45.06 ;
     RECT  58.741 17.196 60.083 20.512 ;
     RECT  58.539 38.796 60.085 39.776 ;
     RECT  60.083 20.48 60.181 20.512 ;
     RECT  59.461 22.08 60.181 26.272 ;
     RECT  60.181 20.48 60.227 26.272 ;
     RECT  59.509 43.584 60.373 45.664 ;
     RECT  56.339 36.48 60.613 36.512 ;
     RECT  58.163 33.396 60.661 34.26 ;
     RECT  60.613 35.904 60.661 36.512 ;
     RECT  60.661 33.396 60.715 36.512 ;
     RECT  60.715 33.396 60.73 34.784 ;
     RECT  60.227 20.8 60.755 26.272 ;
     RECT  58.163 31.936 60.917 31.968 ;
     RECT  60.755 25.728 60.949 26.272 ;
     RECT  58.426 27.996 60.949 28.86 ;
     RECT  60.917 31.296 60.993 31.968 ;
     RECT  60.755 20.8 61.043 23.46 ;
     RECT  60.949 25.728 61.043 28.86 ;
     RECT  60.715 36.48 61.043 36.512 ;
     RECT  60.373 42.496 61.163 45.664 ;
     RECT  61.163 43.52 61.187 45.664 ;
     RECT  60.993 31.296 61.619 31.392 ;
     RECT  61.187 43.904 61.619 45.664 ;
     RECT  59.029 48.448 61.619 50.46 ;
     RECT  60.085 38.796 61.811 40.864 ;
     RECT  61.619 44.032 62.195 45.06 ;
     RECT  61.043 20.8 62.197 20.832 ;
     RECT  61.043 26.752 62.245 28.86 ;
     RECT  62.197 19.904 62.251 20.832 ;
     RECT  62.245 26.752 62.315 29.024 ;
     RECT  62.315 26.752 62.483 28.86 ;
     RECT  61.043 22.596 62.629 23.46 ;
     RECT  62.251 19.904 63.299 19.936 ;
     RECT  62.629 22.596 63.299 24.416 ;
     RECT  61.619 31.36 63.299 31.392 ;
     RECT  53.267 0.996 64.8 1.86 ;
     RECT  51.307 6.396 64.8 7.26 ;
     RECT  54.187 11.796 64.8 12.66 ;
     RECT  60.083 17.196 64.8 18.06 ;
     RECT  63.299 22.596 64.8 23.46 ;
     RECT  62.483 27.996 64.8 28.86 ;
     RECT  60.73 33.396 64.8 34.26 ;
     RECT  61.811 38.796 64.8 39.66 ;
     RECT  62.195 44.196 64.8 45.06 ;
     RECT  61.619 49.596 64.8 50.46 ;
     RECT  55.907 54.996 64.8 55.86 ;
     RECT  53.171 60.396 64.8 61.26 ;
    LAYER M7 ;
     RECT  32.256 0.053 32.288 0.531 ;
     RECT  27.856 0.531 28.144 1.397 ;
     RECT  32.256 0.531 33.544 1.397 ;
     RECT  27.856 1.397 28.64 2.101 ;
     RECT  17.056 0.531 17.344 2.229 ;
     RECT  30.72 1.397 30.752 2.347 ;
     RECT  22.456 0.531 22.744 2.677 ;
     RECT  17.056 2.229 17.76 2.805 ;
     RECT  44.056 0.531 44.344 2.869 ;
     RECT  32.256 1.397 33.888 2.923 ;
     RECT  17.056 2.805 18.208 3.381 ;
     RECT  46.144 2.229 46.176 3.701 ;
     RECT  16.128 3.381 18.208 3.755 ;
     RECT  16.128 3.755 17.76 3.829 ;
     RECT  36.48 1.973 36.512 3.957 ;
     RECT  38.656 0.531 38.944 3.957 ;
     RECT  36.48 3.957 37.024 4.011 ;
     RECT  46.144 3.701 46.304 4.075 ;
     RECT  27.856 2.101 29.216 4.213 ;
     RECT  38.656 3.957 39.072 4.533 ;
     RECT  40.576 2.229 40.608 4.533 ;
     RECT  26.816 4.213 29.216 4.789 ;
     RECT  22.456 2.677 23.584 5.237 ;
     RECT  22.456 5.237 24.48 5.291 ;
     RECT  43.904 2.869 44.344 5.621 ;
     RECT  46.272 4.075 46.304 5.621 ;
     RECT  43.904 5.621 46.304 5.675 ;
     RECT  32.256 2.923 33.544 6.133 ;
     RECT  38.656 4.533 40.608 6.251 ;
     RECT  26.816 4.789 29.408 6.315 ;
     RECT  43.904 5.675 45.216 6.891 ;
     RECT  11.656 0.531 11.944 7.349 ;
     RECT  24.448 5.291 24.48 7.467 ;
     RECT  38.656 6.251 39.136 7.915 ;
     RECT  6.256 0.531 6.544 7.925 ;
     RECT  16 3.829 17.76 8.043 ;
     RECT  0.856 0.531 1.144 8.245 ;
     RECT  6.256 7.925 7.008 8.555 ;
     RECT  11.656 7.349 13.088 8.619 ;
     RECT  16 8.043 17.504 8.747 ;
     RECT  43.904 6.891 44.344 9.013 ;
     RECT  36.992 4.011 37.024 9.195 ;
     RECT  19.2 8.693 19.232 9.205 ;
     RECT  32.256 6.133 33.696 9.397 ;
     RECT  31.04 9.397 33.696 9.461 ;
     RECT  26.24 7.925 26.272 9.515 ;
     RECT  27.648 6.315 29.216 9.515 ;
     RECT  4.416 8.309 4.448 9.653 ;
     RECT  19.2 9.205 19.296 9.653 ;
     RECT  38.656 7.915 39.072 9.771 ;
     RECT  51.264 6.773 51.296 9.771 ;
     RECT  18.944 9.653 19.296 10.101 ;
     RECT  6.256 8.555 6.544 10.229 ;
     RECT  0.856 8.245 1.312 10.539 ;
     RECT  30.656 9.461 33.696 10.613 ;
     RECT  4.288 9.653 4.448 10.741 ;
     RECT  16.576 8.747 17.504 10.923 ;
     RECT  22.456 5.291 22.744 10.933 ;
     RECT  27.648 9.515 28.448 10.933 ;
     RECT  54.856 0.531 55.144 11.061 ;
     RECT  18.944 10.101 19.424 11.115 ;
     RECT  27.648 10.933 29.024 11.115 ;
     RECT  30.656 10.613 34.592 11.115 ;
     RECT  19.2 11.115 19.424 11.435 ;
     RECT  26.112 10.549 26.144 11.637 ;
     RECT  27.856 11.115 29.024 11.637 ;
     RECT  30.656 11.115 30.816 11.637 ;
     RECT  49.456 0.531 49.744 12.149 ;
     RECT  17.056 10.923 17.504 12.203 ;
     RECT  4.288 10.741 4.512 12.213 ;
     RECT  46.848 9.589 46.88 12.267 ;
     RECT  14.72 10.101 14.752 12.779 ;
     RECT  4.16 12.213 4.512 12.853 ;
     RECT  32.256 11.115 34.592 13.035 ;
     RECT  43.008 9.013 44.344 13.045 ;
     RECT  6.256 10.229 7.392 13.291 ;
     RECT  27.856 11.637 30.816 13.291 ;
     RECT  11.656 8.619 11.944 13.685 ;
     RECT  40.576 6.251 40.608 14.123 ;
     RECT  30.784 13.291 30.816 14.315 ;
     RECT  25.088 11.637 26.144 15.147 ;
     RECT  17.056 12.203 17.344 15.157 ;
     RECT  41.984 13.045 44.344 15.339 ;
     RECT  19.2 11.435 19.296 15.349 ;
     RECT  11.656 13.685 12.512 15.403 ;
     RECT  32.256 13.035 33.952 15.595 ;
     RECT  0.856 10.539 1.144 15.861 ;
     RECT  38.656 9.771 38.944 15.925 ;
     RECT  27.856 13.291 29.024 16.299 ;
     RECT  38.656 15.925 39.328 16.309 ;
     RECT  6.256 13.291 6.544 16.885 ;
     RECT  27.856 16.299 28.256 17.013 ;
     RECT  38.656 16.309 40.032 17.589 ;
     RECT  49.456 12.149 50.272 17.589 ;
     RECT  3.84 12.853 4.512 18.165 ;
     RECT  38.208 17.589 40.032 18.283 ;
     RECT  27.648 17.013 28.256 18.741 ;
     RECT  11.656 15.403 12.192 18.859 ;
     RECT  11.656 18.859 11.944 19.253 ;
     RECT  15.936 15.157 17.344 19.253 ;
     RECT  19.072 15.349 19.296 19.253 ;
     RECT  0.856 15.861 1.248 19.317 ;
     RECT  27.072 18.741 28.256 19.317 ;
     RECT  22.336 10.933 22.744 19.371 ;
     RECT  25.088 15.147 25.12 19.371 ;
     RECT  36.416 18.741 36.448 19.435 ;
     RECT  42.112 15.339 44.344 19.435 ;
     RECT  49.216 17.589 50.272 19.435 ;
     RECT  38.208 18.283 39.392 19.563 ;
     RECT  6.256 16.885 6.88 19.755 ;
     RECT  10.432 19.253 11.944 20.011 ;
     RECT  49.216 19.435 50.208 20.011 ;
     RECT  0.856 19.317 1.504 20.085 ;
     RECT  2.816 18.165 4.512 20.085 ;
     RECT  42.432 19.435 44.344 20.139 ;
     RECT  15.936 19.253 19.296 20.331 ;
     RECT  42.944 20.139 44.344 20.331 ;
     RECT  0.856 20.085 4.512 20.715 ;
     RECT  22.456 19.371 22.744 20.789 ;
     RECT  62.208 19.893 62.24 20.843 ;
     RECT  38.656 19.563 39.392 21.163 ;
     RECT  43.136 20.331 44.344 21.493 ;
     RECT  49.28 20.011 50.208 21.739 ;
     RECT  38.656 21.163 38.944 21.941 ;
     RECT  60.256 0.531 60.544 22.069 ;
     RECT  17.056 20.331 19.296 22.197 ;
     RECT  43.136 21.493 45.344 22.453 ;
     RECT  49.28 21.739 50.08 22.507 ;
     RECT  17.056 22.197 20.576 23.019 ;
     RECT  22.456 20.789 23.904 23.019 ;
     RECT  26.816 19.317 28.256 23.019 ;
     RECT  60.256 22.069 60.96 23.019 ;
     RECT  2.624 20.715 4.512 23.595 ;
     RECT  58.56 22.965 58.592 23.605 ;
     RECT  54.144 11.061 55.144 23.659 ;
     RECT  19.264 23.019 20.576 23.851 ;
     RECT  36.096 22.453 36.128 23.979 ;
     RECT  41.92 22.453 45.344 23.979 ;
     RECT  58.176 23.605 58.592 23.979 ;
     RECT  11.656 20.011 11.944 24.437 ;
     RECT  49.456 22.507 50.08 24.437 ;
     RECT  51.712 23.733 51.744 24.437 ;
     RECT  27.856 23.019 28.256 24.501 ;
     RECT  41.92 23.979 44.344 25.013 ;
     RECT  40.704 25.013 44.344 25.131 ;
     RECT  38.464 21.941 38.944 25.451 ;
     RECT  20.608 23.925 20.64 25.707 ;
     RECT  2.624 23.595 4 25.717 ;
     RECT  58.176 23.979 58.208 25.717 ;
     RECT  6.256 19.755 6.544 26.165 ;
     RECT  11.656 24.437 12.512 26.165 ;
     RECT  2.624 25.717 4.064 26.283 ;
     RECT  49.456 24.437 51.744 26.283 ;
     RECT  26.88 24.501 28.256 26.539 ;
     RECT  58.176 25.717 58.4 26.677 ;
     RECT  27.856 26.539 28.256 26.859 ;
     RECT  6.256 26.165 7.136 27.563 ;
     RECT  30.208 24.437 30.24 27.563 ;
     RECT  9.92 26.165 9.952 27.627 ;
     RECT  2.816 26.283 4.064 27.819 ;
     RECT  11.656 26.165 12.96 27.883 ;
     RECT  46.208 27.829 46.24 28.459 ;
     RECT  32.256 15.595 33.544 28.981 ;
     RECT  40.704 25.131 40.736 29.035 ;
     RECT  57.92 26.677 58.4 29.035 ;
     RECT  58.368 29.035 58.4 29.099 ;
     RECT  2.816 27.819 4 29.493 ;
     RECT  11.656 27.883 11.944 29.557 ;
     RECT  2.816 29.493 4.512 29.675 ;
     RECT  51.712 26.283 51.744 29.675 ;
     RECT  43.136 25.131 44.344 30.133 ;
     RECT  32.256 28.981 33.952 30.571 ;
     RECT  4.48 29.675 4.512 30.709 ;
     RECT  6.256 27.563 6.544 30.709 ;
     RECT  22.456 23.019 22.744 31.157 ;
     RECT  11.328 29.557 11.944 31.211 ;
     RECT  60.256 23.019 60.544 31.285 ;
     RECT  22.272 31.157 22.744 31.403 ;
     RECT  42.752 30.133 44.344 31.403 ;
     RECT  62.272 28.981 62.304 31.403 ;
     RECT  4.48 30.709 6.544 31.467 ;
     RECT  38.656 25.451 38.944 31.477 ;
     RECT  60.256 31.285 60.96 31.979 ;
     RECT  36.032 31.669 36.064 32.245 ;
     RECT  44.056 31.403 44.344 32.437 ;
     RECT  32.256 30.571 33.544 32.555 ;
     RECT  47.68 20.469 47.712 32.757 ;
     RECT  47.296 32.757 47.712 32.811 ;
     RECT  6.256 31.467 6.544 32.821 ;
     RECT  37.696 31.477 38.944 32.821 ;
     RECT  41.152 32.693 41.184 32.821 ;
     RECT  44.056 32.437 44.704 32.885 ;
     RECT  2.816 29.675 3.168 33.013 ;
     RECT  10.24 32.885 10.272 33.013 ;
     RECT  11.656 31.211 11.944 33.013 ;
     RECT  54.856 23.659 55.144 33.013 ;
     RECT  37.696 32.821 41.184 33.067 ;
     RECT  30.912 31.861 30.944 33.195 ;
     RECT  4.48 31.467 4.512 33.269 ;
     RECT  6.256 32.821 6.688 33.269 ;
     RECT  27.856 26.859 28.144 33.269 ;
     RECT  47.296 32.811 47.328 33.269 ;
     RECT  10.24 33.013 11.944 33.835 ;
     RECT  11.656 33.835 11.944 33.845 ;
     RECT  37.696 33.067 40.608 33.899 ;
     RECT  4.48 33.269 6.688 34.411 ;
     RECT  2.752 33.013 3.168 34.421 ;
     RECT  4.48 34.411 4.512 34.421 ;
     RECT  42.624 32.885 44.704 34.421 ;
     RECT  2.752 34.421 4.512 34.475 ;
     RECT  42.112 34.421 44.704 34.475 ;
     RECT  46.4 33.269 47.328 34.485 ;
     RECT  49.456 26.283 49.744 34.485 ;
     RECT  10.24 33.835 10.272 34.677 ;
     RECT  0.856 20.715 1.144 34.741 ;
     RECT  19.264 23.851 19.296 34.741 ;
     RECT  30.016 33.845 30.048 34.741 ;
     RECT  31.872 33.845 31.904 34.741 ;
     RECT  60.256 31.979 60.544 34.741 ;
     RECT  35.648 32.245 36.064 34.859 ;
     RECT  54.656 33.013 55.144 34.869 ;
     RECT  37.696 33.899 40.224 34.933 ;
     RECT  37.632 34.933 40.224 34.987 ;
     RECT  6.256 34.411 6.688 34.997 ;
     RECT  22.336 31.403 22.744 34.997 ;
     RECT  10.112 34.677 10.272 35.115 ;
     RECT  37.632 34.987 39.328 35.253 ;
     RECT  26.688 33.269 28.576 35.307 ;
     RECT  10.112 35.115 10.144 35.445 ;
     RECT  51.584 34.805 51.616 35.701 ;
     RECT  51.584 35.701 52.192 35.829 ;
     RECT  2.752 34.475 4.384 35.883 ;
     RECT  11.656 33.845 12.704 35.883 ;
     RECT  9.728 35.445 10.144 35.947 ;
     RECT  60.256 34.741 60.704 35.947 ;
     RECT  0.448 34.741 1.144 36.011 ;
     RECT  22.336 34.997 23.968 36.149 ;
     RECT  33.256 32.555 33.544 36.277 ;
     RECT  33.256 36.277 34.272 36.405 ;
     RECT  35.648 34.859 35.68 36.405 ;
     RECT  30.016 34.741 31.904 36.459 ;
     RECT  54.528 34.869 55.144 36.469 ;
     RECT  6.256 34.997 6.816 36.523 ;
     RECT  19.264 34.741 20 36.523 ;
     RECT  27.856 35.307 28.576 36.661 ;
     RECT  30.016 36.459 30.368 36.661 ;
     RECT  27.856 36.661 30.368 36.715 ;
     RECT  54.528 36.469 56.416 37.045 ;
     RECT  51.584 35.829 52.512 37.099 ;
     RECT  46.4 34.485 49.744 37.109 ;
     RECT  2.752 35.883 3.04 37.301 ;
     RECT  22.272 36.149 23.968 37.429 ;
     RECT  54.144 37.045 56.416 37.429 ;
     RECT  11.656 35.883 11.944 37.557 ;
     RECT  44.056 34.475 44.704 37.557 ;
     RECT  42.112 34.475 42.72 37.621 ;
     RECT  44.056 37.557 44.896 37.621 ;
     RECT  31.872 36.459 31.904 37.675 ;
     RECT  52.16 37.099 52.512 37.675 ;
     RECT  42.112 37.621 44.896 37.685 ;
     RECT  17.056 23.019 17.568 38.005 ;
     RECT  33.256 36.405 35.68 38.005 ;
     RECT  21.12 37.429 23.968 38.069 ;
     RECT  26.496 36.085 26.528 38.069 ;
     RECT  2.624 37.301 3.04 38.133 ;
     RECT  4.352 35.883 4.384 38.133 ;
     RECT  42.048 37.685 44.896 38.133 ;
     RECT  32.64 38.005 35.68 38.187 ;
     RECT  11.52 37.557 11.944 38.197 ;
     RECT  21.12 38.069 26.528 38.507 ;
     RECT  2.624 38.133 4.384 38.645 ;
     RECT  6.256 36.523 6.544 38.645 ;
     RECT  37.12 35.253 39.328 38.645 ;
     RECT  40.96 38.133 44.896 38.645 ;
     RECT  46.336 37.109 49.744 38.645 ;
     RECT  25.216 38.507 26.528 38.699 ;
     RECT  37.12 38.645 44.896 39.211 ;
     RECT  29.504 36.715 30.368 39.221 ;
     RECT  9.728 35.947 9.76 39.733 ;
     RECT  11.328 38.197 11.944 39.733 ;
     RECT  27.856 36.715 28.144 39.733 ;
     RECT  58.368 38.645 58.4 39.733 ;
     RECT  21.12 38.507 22.744 39.787 ;
     RECT  33.256 38.187 35.68 39.787 ;
     RECT  58.368 39.733 58.528 39.787 ;
     RECT  37.12 39.211 42.656 40.043 ;
     RECT  54.016 37.429 56.416 40.309 ;
     RECT  2.624 38.645 6.544 40.437 ;
     RECT  58.496 39.787 58.528 41.067 ;
     RECT  27.648 39.733 28.144 41.077 ;
     RECT  29.504 39.221 30.688 41.077 ;
     RECT  35.2 39.787 35.68 41.131 ;
     RECT  27.648 41.077 30.688 41.259 ;
     RECT  8.64 39.733 11.944 41.323 ;
     RECT  2.624 40.437 6.816 41.387 ;
     RECT  25.216 38.699 25.632 41.387 ;
     RECT  21.632 39.787 22.744 41.643 ;
     RECT  46.336 38.645 50.912 41.835 ;
     RECT  53.888 40.309 56.416 41.899 ;
     RECT  15.936 38.005 17.568 41.973 ;
     RECT  19.264 36.523 19.296 41.973 ;
     RECT  27.856 41.259 30.688 41.973 ;
     RECT  14.016 41.781 14.048 42.037 ;
     RECT  8.64 41.323 9.888 42.091 ;
     RECT  3.008 41.387 6.816 42.101 ;
     RECT  8.64 42.091 8.736 42.101 ;
     RECT  37.12 40.043 42.528 42.219 ;
     RECT  25.6 41.387 25.632 42.411 ;
     RECT  60.256 35.947 60.544 42.485 ;
     RECT  44.056 39.211 44.896 42.613 ;
     RECT  46.336 41.835 50.784 42.613 ;
     RECT  11.52 41.323 11.944 42.677 ;
     RECT  13.696 42.037 14.048 42.677 ;
     RECT  27.856 41.973 30.752 42.677 ;
     RECT  3.008 42.101 8.736 42.795 ;
     RECT  52.48 37.675 52.512 42.795 ;
     RECT  21.888 41.643 22.744 43.253 ;
     RECT  35.2 41.131 35.616 43.381 ;
     RECT  60.256 42.485 61.152 43.563 ;
     RECT  54.016 41.899 56.416 43.573 ;
     RECT  21.696 43.253 22.744 43.829 ;
     RECT  4.608 42.795 8.736 43.883 ;
     RECT  44.056 42.613 50.784 43.947 ;
     RECT  27.072 42.677 30.752 43.957 ;
     RECT  37.12 42.219 42.144 44.011 ;
     RECT  44.056 43.947 50.336 44.011 ;
     RECT  15.936 41.973 19.296 44.021 ;
     RECT  24.768 43.253 25.184 44.021 ;
     RECT  4.608 43.883 6.816 44.075 ;
     RECT  11.52 42.677 14.048 44.597 ;
     RECT  33.256 39.787 33.696 44.597 ;
     RECT  8.64 43.883 8.736 44.651 ;
     RECT  3.008 42.795 3.04 45.227 ;
     RECT  38.464 44.011 42.144 45.227 ;
     RECT  35.2 43.381 35.744 45.237 ;
     RECT  8.704 44.651 8.736 45.301 ;
     RECT  4.608 44.075 6.544 45.419 ;
     RECT  58.176 43.573 58.208 45.419 ;
     RECT  46.4 44.011 50.336 45.493 ;
     RECT  5.568 45.419 6.544 45.621 ;
     RECT  24.448 44.021 25.184 45.621 ;
     RECT  21.44 43.829 22.744 45.675 ;
     RECT  15.936 44.021 19.936 45.739 ;
     RECT  24.448 45.621 25.312 45.931 ;
     RECT  15.936 45.739 17.632 46.133 ;
     RECT  19.264 45.739 19.936 47.019 ;
     RECT  27.072 43.957 31.2 47.083 ;
     RECT  37.12 44.011 37.152 47.083 ;
     RECT  38.656 45.227 42.144 47.093 ;
     RECT  46.4 45.493 50.848 47.147 ;
     RECT  25.28 45.931 25.312 47.221 ;
     RECT  38.656 47.093 42.72 47.221 ;
     RECT  5.568 45.621 7.264 47.339 ;
     RECT  15.424 46.133 17.632 47.339 ;
     RECT  8.704 45.301 9.504 47.349 ;
     RECT  11.456 44.597 14.048 47.349 ;
     RECT  8.704 47.349 14.048 47.531 ;
     RECT  33.256 44.597 33.824 47.541 ;
     RECT  37.696 47.221 42.72 47.541 ;
     RECT  44.056 44.011 44.512 47.541 ;
     RECT  35.136 45.237 35.744 47.595 ;
     RECT  32.512 47.541 33.824 47.605 ;
     RECT  35.136 47.595 35.232 47.605 ;
     RECT  32.512 47.605 35.232 47.787 ;
     RECT  24.192 47.221 25.312 47.797 ;
     RECT  27.072 47.083 28.144 47.797 ;
     RECT  37.696 47.541 44.512 47.797 ;
     RECT  15.424 47.339 15.456 47.979 ;
     RECT  8.704 47.531 12.896 48.043 ;
     RECT  9.408 48.043 12.896 48.427 ;
     RECT  5.632 47.339 7.264 48.619 ;
     RECT  17.056 47.339 17.632 49.131 ;
     RECT  33.024 47.787 35.232 49.259 ;
     RECT  19.264 47.019 19.872 49.269 ;
     RECT  37.696 47.797 44.704 49.333 ;
     RECT  46.656 47.147 50.848 49.333 ;
     RECT  24.192 47.797 28.144 49.461 ;
     RECT  29.696 47.083 31.2 49.461 ;
     RECT  15.424 49.461 15.456 49.973 ;
     RECT  17.056 49.131 17.344 49.973 ;
     RECT  37.696 49.333 50.848 49.973 ;
     RECT  33.256 49.259 35.232 50.027 ;
     RECT  52.736 43.573 56.416 50.027 ;
     RECT  36.544 49.973 50.848 50.037 ;
     RECT  52.736 50.027 53.152 50.037 ;
     RECT  9.408 48.427 12.64 50.091 ;
     RECT  36.544 50.037 53.152 50.603 ;
     RECT  36.544 50.603 46.24 50.613 ;
     RECT  35.392 50.613 46.24 50.731 ;
     RECT  15.424 49.973 17.344 51.051 ;
     RECT  5.632 48.619 6.544 51.115 ;
     RECT  9.408 50.091 11.944 51.115 ;
     RECT  16.448 51.051 17.344 51.253 ;
     RECT  19.264 49.269 20.128 51.253 ;
     RECT  21.696 45.675 22.744 51.253 ;
     RECT  24.192 49.461 28.256 51.253 ;
     RECT  35.392 50.731 44.768 51.371 ;
     RECT  46.208 50.731 46.24 51.371 ;
     RECT  47.744 50.603 53.152 51.573 ;
     RECT  54.464 50.027 56.416 51.573 ;
     RECT  37.696 51.371 44.768 51.627 ;
     RECT  47.744 51.573 56.416 51.627 ;
     RECT  29.696 49.461 31.264 51.701 ;
     RECT  33.256 50.027 33.952 51.701 ;
     RECT  9.408 51.115 9.44 51.947 ;
     RECT  11.52 51.115 11.944 51.947 ;
     RECT  16.448 51.253 20.128 51.947 ;
     RECT  21.696 51.253 28.256 51.947 ;
     RECT  38.528 51.627 44.768 52.011 ;
     RECT  25.28 51.947 28.256 52.021 ;
     RECT  29.696 51.701 33.952 52.021 ;
     RECT  21.696 51.947 23.904 52.395 ;
     RECT  19.84 51.947 20.128 52.523 ;
     RECT  47.744 51.627 55.144 52.853 ;
     RECT  16.896 51.947 18.464 53.099 ;
     RECT  19.84 52.523 19.872 53.099 ;
     RECT  38.656 52.011 44.768 53.099 ;
     RECT  35.392 51.371 36.32 53.163 ;
     RECT  35.584 53.163 36.32 53.173 ;
     RECT  47.424 52.853 55.144 53.237 ;
     RECT  38.656 53.099 40.224 53.291 ;
     RECT  38.656 53.291 39.328 53.493 ;
     RECT  22.456 52.395 23.904 53.739 ;
     RECT  25.28 52.021 33.952 54.059 ;
     RECT  25.28 54.059 31.2 54.123 ;
     RECT  38.016 53.493 39.328 54.635 ;
     RECT  17.056 53.099 18.464 54.699 ;
     RECT  38.016 54.635 39.2 54.763 ;
     RECT  47.424 53.237 55.264 54.763 ;
     RECT  41.856 53.099 44.768 54.837 ;
     RECT  41.856 54.837 44.96 55.349 ;
     RECT  29.696 54.123 31.2 55.403 ;
     RECT  35.584 53.173 36.448 55.413 ;
     RECT  17.056 54.699 17.504 55.979 ;
     RECT  35.328 55.413 36.448 56.107 ;
     RECT  22.456 53.739 22.744 56.117 ;
     RECT  47.424 54.763 47.456 56.373 ;
     RECT  47.424 56.373 47.584 56.427 ;
     RECT  38.016 54.763 39.072 57.013 ;
     RECT  21.44 56.117 22.744 57.131 ;
     RECT  35.328 56.107 36.32 57.259 ;
     RECT  22.456 57.131 22.744 57.525 ;
     RECT  36.672 57.525 36.704 57.589 ;
     RECT  38.016 57.013 39.904 57.589 ;
     RECT  25.28 54.123 28.144 57.707 ;
     RECT  33.256 54.059 33.952 57.717 ;
     RECT  49.456 54.763 55.144 58.219 ;
     RECT  35.328 57.259 35.36 58.347 ;
     RECT  49.456 58.219 53.152 58.411 ;
     RECT  41.856 55.349 45.024 58.475 ;
     RECT  33.024 57.717 33.952 58.485 ;
     RECT  22.456 57.525 23.712 59.125 ;
     RECT  22.208 59.125 23.712 59.179 ;
     RECT  25.408 57.707 28.144 59.179 ;
     RECT  33.024 58.485 34.144 59.307 ;
     RECT  36.672 57.589 39.904 59.307 ;
     RECT  47.552 56.427 47.584 59.307 ;
     RECT  52.736 58.411 53.152 59.499 ;
     RECT  36.672 59.307 39.072 59.563 ;
     RECT  30.528 55.403 31.2 59.765 ;
     RECT  36.672 59.563 38.944 59.765 ;
     RECT  25.408 59.179 25.44 59.883 ;
     RECT  49.456 58.411 51.04 59.883 ;
     RECT  22.208 59.179 22.744 60.075 ;
     RECT  33.256 59.307 34.144 60.075 ;
     RECT  53.12 59.499 53.152 60.331 ;
     RECT  27.072 59.179 28.144 60.843 ;
     RECT  41.856 58.475 41.888 60.843 ;
     RECT  30.144 59.765 31.2 60.907 ;
     RECT  35.904 59.765 38.944 60.907 ;
     RECT  37.76 60.907 38.944 61.419 ;
     RECT  46.976 59.765 47.008 61.419 ;
     RECT  43.904 58.475 45.024 61.611 ;
     RECT  49.456 59.883 50.016 61.611 ;
     RECT  43.904 61.611 44.344 61.739 ;
     RECT  35.904 60.907 35.936 61.867 ;
     RECT  31.168 60.907 31.2 62.645 ;
     RECT  31.168 62.645 31.904 62.827 ;
     RECT  27.712 60.843 28.144 63.403 ;
     RECT  24.832 62.453 24.864 63.531 ;
     RECT  31.744 62.827 31.904 63.915 ;
     RECT  31.872 63.915 31.904 64.043 ;
     RECT  0.856 36.011 1.144 64.269 ;
     RECT  6.256 51.115 6.544 64.269 ;
     RECT  11.656 51.947 11.944 64.269 ;
     RECT  17.056 55.979 17.344 64.269 ;
     RECT  22.456 60.075 22.744 64.269 ;
     RECT  27.856 63.403 28.144 64.269 ;
     RECT  33.256 60.075 33.544 64.269 ;
     RECT  38.656 61.419 38.944 64.269 ;
     RECT  44.056 61.739 44.344 64.269 ;
     RECT  49.456 61.611 49.744 64.269 ;
     RECT  54.856 58.219 55.144 64.269 ;
     RECT  60.256 43.563 60.544 64.269 ;
  END
END dsfd_dw_ep_c
END LIBRARY
